VERSION 5.8 ;
BUSBITCHARS "[]" ;
DIVIDERCHAR "/" ;
UNITS
    DATABASE MICRONS 1000 ;
END UNITS

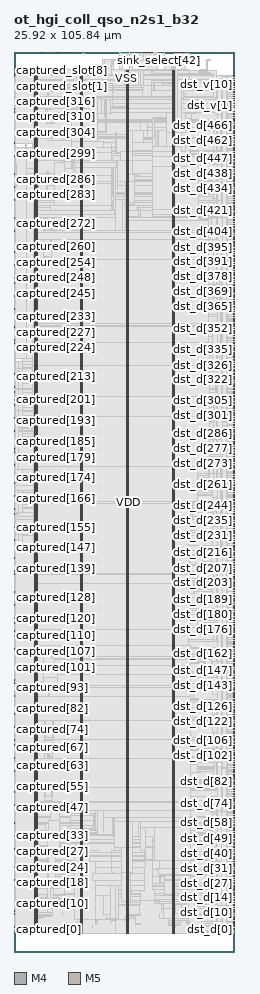
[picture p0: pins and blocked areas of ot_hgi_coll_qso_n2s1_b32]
MACRO ot_hgi_coll_qso_n2s1_b32
  FOREIGN ot_hgi_coll_qso_n2s1_b32 0 0 ;
  CLASS BLOCK ;
  SIZE 25.92 BY 105.84 ;
  PIN captured[0]
    DIRECTION INPUT ;
    USE SIGNAL ;
    PORT
      LAYER M4 ;
        RECT  0 2.64 0.084 2.664 ;
    END
  END captured[0]
  PIN captured[100]
    DIRECTION INPUT ;
    USE SIGNAL ;
    PORT
      LAYER M4 ;
        RECT  0 33.168 0.084 33.192 ;
    END
  END captured[100]
  PIN captured[101]
    DIRECTION INPUT ;
    USE SIGNAL ;
    PORT
      LAYER M4 ;
        RECT  0 33.456 0.084 33.48 ;
    END
  END captured[101]
  PIN captured[102]
    DIRECTION INPUT ;
    USE SIGNAL ;
    PORT
      LAYER M4 ;
        RECT  0 33.792 0.084 33.816 ;
    END
  END captured[102]
  PIN captured[103]
    DIRECTION INPUT ;
    USE SIGNAL ;
    PORT
      LAYER M4 ;
        RECT  0 34.08 0.084 34.104 ;
    END
  END captured[103]
  PIN captured[104]
    DIRECTION INPUT ;
    USE SIGNAL ;
    PORT
      LAYER M4 ;
        RECT  0 34.368 0.084 34.392 ;
    END
  END captured[104]
  PIN captured[105]
    DIRECTION INPUT ;
    USE SIGNAL ;
    PORT
      LAYER M4 ;
        RECT  0 34.704 0.084 34.728 ;
    END
  END captured[105]
  PIN captured[106]
    DIRECTION INPUT ;
    USE SIGNAL ;
    PORT
      LAYER M4 ;
        RECT  0 34.992 0.084 35.016 ;
    END
  END captured[106]
  PIN captured[107]
    DIRECTION INPUT ;
    USE SIGNAL ;
    PORT
      LAYER M4 ;
        RECT  0 35.328 0.084 35.352 ;
    END
  END captured[107]
  PIN captured[108]
    DIRECTION INPUT ;
    USE SIGNAL ;
    PORT
      LAYER M4 ;
        RECT  0 35.616 0.084 35.64 ;
    END
  END captured[108]
  PIN captured[109]
    DIRECTION INPUT ;
    USE SIGNAL ;
    PORT
      LAYER M4 ;
        RECT  0 35.904 0.084 35.928 ;
    END
  END captured[109]
  PIN captured[10]
    DIRECTION INPUT ;
    USE SIGNAL ;
    PORT
      LAYER M4 ;
        RECT  0 5.712 0.084 5.736 ;
    END
  END captured[10]
  PIN captured[110]
    DIRECTION INPUT ;
    USE SIGNAL ;
    PORT
      LAYER M4 ;
        RECT  0 36.24 0.084 36.264 ;
    END
  END captured[110]
  PIN captured[111]
    DIRECTION INPUT ;
    USE SIGNAL ;
    PORT
      LAYER M4 ;
        RECT  0 36.528 0.084 36.552 ;
    END
  END captured[111]
  PIN captured[112]
    DIRECTION INPUT ;
    USE SIGNAL ;
    PORT
      LAYER M4 ;
        RECT  0 36.816 0.084 36.84 ;
    END
  END captured[112]
  PIN captured[113]
    DIRECTION INPUT ;
    USE SIGNAL ;
    PORT
      LAYER M4 ;
        RECT  0 37.152 0.084 37.176 ;
    END
  END captured[113]
  PIN captured[114]
    DIRECTION INPUT ;
    USE SIGNAL ;
    PORT
      LAYER M4 ;
        RECT  0 37.44 0.084 37.464 ;
    END
  END captured[114]
  PIN captured[115]
    DIRECTION INPUT ;
    USE SIGNAL ;
    PORT
      LAYER M4 ;
        RECT  0 37.728 0.084 37.752 ;
    END
  END captured[115]
  PIN captured[116]
    DIRECTION INPUT ;
    USE SIGNAL ;
    PORT
      LAYER M4 ;
        RECT  0 38.064 0.084 38.088 ;
    END
  END captured[116]
  PIN captured[117]
    DIRECTION INPUT ;
    USE SIGNAL ;
    PORT
      LAYER M4 ;
        RECT  0 38.352 0.084 38.376 ;
    END
  END captured[117]
  PIN captured[118]
    DIRECTION INPUT ;
    USE SIGNAL ;
    PORT
      LAYER M4 ;
        RECT  0 38.688 0.084 38.712 ;
    END
  END captured[118]
  PIN captured[119]
    DIRECTION INPUT ;
    USE SIGNAL ;
    PORT
      LAYER M4 ;
        RECT  0 38.976 0.084 39 ;
    END
  END captured[119]
  PIN captured[11]
    DIRECTION INPUT ;
    USE SIGNAL ;
    PORT
      LAYER M4 ;
        RECT  0 6 0.084 6.024 ;
    END
  END captured[11]
  PIN captured[120]
    DIRECTION INPUT ;
    USE SIGNAL ;
    PORT
      LAYER M4 ;
        RECT  0 39.264 0.084 39.288 ;
    END
  END captured[120]
  PIN captured[121]
    DIRECTION INPUT ;
    USE SIGNAL ;
    PORT
      LAYER M4 ;
        RECT  0 39.6 0.084 39.624 ;
    END
  END captured[121]
  PIN captured[122]
    DIRECTION INPUT ;
    USE SIGNAL ;
    PORT
      LAYER M4 ;
        RECT  0 39.888 0.084 39.912 ;
    END
  END captured[122]
  PIN captured[123]
    DIRECTION INPUT ;
    USE SIGNAL ;
    PORT
      LAYER M4 ;
        RECT  0 40.176 0.084 40.2 ;
    END
  END captured[123]
  PIN captured[124]
    DIRECTION INPUT ;
    USE SIGNAL ;
    PORT
      LAYER M4 ;
        RECT  0 40.512 0.084 40.536 ;
    END
  END captured[124]
  PIN captured[125]
    DIRECTION INPUT ;
    USE SIGNAL ;
    PORT
      LAYER M4 ;
        RECT  0 40.8 0.084 40.824 ;
    END
  END captured[125]
  PIN captured[126]
    DIRECTION INPUT ;
    USE SIGNAL ;
    PORT
      LAYER M4 ;
        RECT  0 41.088 0.084 41.112 ;
    END
  END captured[126]
  PIN captured[127]
    DIRECTION INPUT ;
    USE SIGNAL ;
    PORT
      LAYER M4 ;
        RECT  0 41.424 0.084 41.448 ;
    END
  END captured[127]
  PIN captured[128]
    DIRECTION INPUT ;
    USE SIGNAL ;
    PORT
      LAYER M4 ;
        RECT  0 41.712 0.084 41.736 ;
    END
  END captured[128]
  PIN captured[129]
    DIRECTION INPUT ;
    USE SIGNAL ;
    PORT
      LAYER M4 ;
        RECT  0 42 0.084 42.024 ;
    END
  END captured[129]
  PIN captured[12]
    DIRECTION INPUT ;
    USE SIGNAL ;
    PORT
      LAYER M4 ;
        RECT  0 6.288 0.084 6.312 ;
    END
  END captured[12]
  PIN captured[130]
    DIRECTION INPUT ;
    USE SIGNAL ;
    PORT
      LAYER M4 ;
        RECT  0 42.336 0.084 42.36 ;
    END
  END captured[130]
  PIN captured[131]
    DIRECTION INPUT ;
    USE SIGNAL ;
    PORT
      LAYER M4 ;
        RECT  0 42.624 0.084 42.648 ;
    END
  END captured[131]
  PIN captured[132]
    DIRECTION INPUT ;
    USE SIGNAL ;
    PORT
      LAYER M4 ;
        RECT  0 42.96 0.084 42.984 ;
    END
  END captured[132]
  PIN captured[133]
    DIRECTION INPUT ;
    USE SIGNAL ;
    PORT
      LAYER M4 ;
        RECT  0 43.248 0.084 43.272 ;
    END
  END captured[133]
  PIN captured[134]
    DIRECTION INPUT ;
    USE SIGNAL ;
    PORT
      LAYER M4 ;
        RECT  0 43.536 0.084 43.56 ;
    END
  END captured[134]
  PIN captured[135]
    DIRECTION INPUT ;
    USE SIGNAL ;
    PORT
      LAYER M4 ;
        RECT  0 43.872 0.084 43.896 ;
    END
  END captured[135]
  PIN captured[136]
    DIRECTION INPUT ;
    USE SIGNAL ;
    PORT
      LAYER M4 ;
        RECT  0 44.16 0.084 44.184 ;
    END
  END captured[136]
  PIN captured[137]
    DIRECTION INPUT ;
    USE SIGNAL ;
    PORT
      LAYER M4 ;
        RECT  0 44.448 0.084 44.472 ;
    END
  END captured[137]
  PIN captured[138]
    DIRECTION INPUT ;
    USE SIGNAL ;
    PORT
      LAYER M4 ;
        RECT  0 44.784 0.084 44.808 ;
    END
  END captured[138]
  PIN captured[139]
    DIRECTION INPUT ;
    USE SIGNAL ;
    PORT
      LAYER M4 ;
        RECT  0 45.072 0.084 45.096 ;
    END
  END captured[139]
  PIN captured[13]
    DIRECTION INPUT ;
    USE SIGNAL ;
    PORT
      LAYER M4 ;
        RECT  0 6.624 0.084 6.648 ;
    END
  END captured[13]
  PIN captured[140]
    DIRECTION INPUT ;
    USE SIGNAL ;
    PORT
      LAYER M4 ;
        RECT  0 45.36 0.084 45.384 ;
    END
  END captured[140]
  PIN captured[141]
    DIRECTION INPUT ;
    USE SIGNAL ;
    PORT
      LAYER M4 ;
        RECT  0 45.696 0.084 45.72 ;
    END
  END captured[141]
  PIN captured[142]
    DIRECTION INPUT ;
    USE SIGNAL ;
    PORT
      LAYER M4 ;
        RECT  0 45.984 0.084 46.008 ;
    END
  END captured[142]
  PIN captured[143]
    DIRECTION INPUT ;
    USE SIGNAL ;
    PORT
      LAYER M4 ;
        RECT  0 46.32 0.084 46.344 ;
    END
  END captured[143]
  PIN captured[144]
    DIRECTION INPUT ;
    USE SIGNAL ;
    PORT
      LAYER M4 ;
        RECT  0 46.608 0.084 46.632 ;
    END
  END captured[144]
  PIN captured[145]
    DIRECTION INPUT ;
    USE SIGNAL ;
    PORT
      LAYER M4 ;
        RECT  0 46.896 0.084 46.92 ;
    END
  END captured[145]
  PIN captured[146]
    DIRECTION INPUT ;
    USE SIGNAL ;
    PORT
      LAYER M4 ;
        RECT  0 47.232 0.084 47.256 ;
    END
  END captured[146]
  PIN captured[147]
    DIRECTION INPUT ;
    USE SIGNAL ;
    PORT
      LAYER M4 ;
        RECT  0 47.52 0.084 47.544 ;
    END
  END captured[147]
  PIN captured[148]
    DIRECTION INPUT ;
    USE SIGNAL ;
    PORT
      LAYER M4 ;
        RECT  0 47.808 0.084 47.832 ;
    END
  END captured[148]
  PIN captured[149]
    DIRECTION INPUT ;
    USE SIGNAL ;
    PORT
      LAYER M4 ;
        RECT  0 48.144 0.084 48.168 ;
    END
  END captured[149]
  PIN captured[14]
    DIRECTION INPUT ;
    USE SIGNAL ;
    PORT
      LAYER M4 ;
        RECT  0 6.912 0.084 6.936 ;
    END
  END captured[14]
  PIN captured[150]
    DIRECTION INPUT ;
    USE SIGNAL ;
    PORT
      LAYER M4 ;
        RECT  0 48.432 0.084 48.456 ;
    END
  END captured[150]
  PIN captured[151]
    DIRECTION INPUT ;
    USE SIGNAL ;
    PORT
      LAYER M4 ;
        RECT  0 48.72 0.084 48.744 ;
    END
  END captured[151]
  PIN captured[152]
    DIRECTION INPUT ;
    USE SIGNAL ;
    PORT
      LAYER M4 ;
        RECT  0 49.056 0.084 49.08 ;
    END
  END captured[152]
  PIN captured[153]
    DIRECTION INPUT ;
    USE SIGNAL ;
    PORT
      LAYER M4 ;
        RECT  0 49.344 0.084 49.368 ;
    END
  END captured[153]
  PIN captured[154]
    DIRECTION INPUT ;
    USE SIGNAL ;
    PORT
      LAYER M4 ;
        RECT  0 49.632 0.084 49.656 ;
    END
  END captured[154]
  PIN captured[155]
    DIRECTION INPUT ;
    USE SIGNAL ;
    PORT
      LAYER M4 ;
        RECT  0 49.968 0.084 49.992 ;
    END
  END captured[155]
  PIN captured[156]
    DIRECTION INPUT ;
    USE SIGNAL ;
    PORT
      LAYER M4 ;
        RECT  0 50.256 0.084 50.28 ;
    END
  END captured[156]
  PIN captured[157]
    DIRECTION INPUT ;
    USE SIGNAL ;
    PORT
      LAYER M4 ;
        RECT  0 50.592 0.084 50.616 ;
    END
  END captured[157]
  PIN captured[158]
    DIRECTION INPUT ;
    USE SIGNAL ;
    PORT
      LAYER M4 ;
        RECT  0 50.88 0.084 50.904 ;
    END
  END captured[158]
  PIN captured[159]
    DIRECTION INPUT ;
    USE SIGNAL ;
    PORT
      LAYER M4 ;
        RECT  0 51.168 0.084 51.192 ;
    END
  END captured[159]
  PIN captured[15]
    DIRECTION INPUT ;
    USE SIGNAL ;
    PORT
      LAYER M4 ;
        RECT  0 7.2 0.084 7.224 ;
    END
  END captured[15]
  PIN captured[160]
    DIRECTION INPUT ;
    USE SIGNAL ;
    PORT
      LAYER M4 ;
        RECT  0 51.504 0.084 51.528 ;
    END
  END captured[160]
  PIN captured[161]
    DIRECTION INPUT ;
    USE SIGNAL ;
    PORT
      LAYER M4 ;
        RECT  0 51.792 0.084 51.816 ;
    END
  END captured[161]
  PIN captured[162]
    DIRECTION INPUT ;
    USE SIGNAL ;
    PORT
      LAYER M4 ;
        RECT  0 52.08 0.084 52.104 ;
    END
  END captured[162]
  PIN captured[163]
    DIRECTION INPUT ;
    USE SIGNAL ;
    PORT
      LAYER M4 ;
        RECT  0 52.416 0.084 52.44 ;
    END
  END captured[163]
  PIN captured[164]
    DIRECTION INPUT ;
    USE SIGNAL ;
    PORT
      LAYER M4 ;
        RECT  0 52.704 0.084 52.728 ;
    END
  END captured[164]
  PIN captured[165]
    DIRECTION INPUT ;
    USE SIGNAL ;
    PORT
      LAYER M4 ;
        RECT  0 52.992 0.084 53.016 ;
    END
  END captured[165]
  PIN captured[166]
    DIRECTION INPUT ;
    USE SIGNAL ;
    PORT
      LAYER M4 ;
        RECT  0 53.328 0.084 53.352 ;
    END
  END captured[166]
  PIN captured[167]
    DIRECTION INPUT ;
    USE SIGNAL ;
    PORT
      LAYER M4 ;
        RECT  0 53.616 0.084 53.64 ;
    END
  END captured[167]
  PIN captured[168]
    DIRECTION INPUT ;
    USE SIGNAL ;
    PORT
      LAYER M4 ;
        RECT  0 53.952 0.084 53.976 ;
    END
  END captured[168]
  PIN captured[169]
    DIRECTION INPUT ;
    USE SIGNAL ;
    PORT
      LAYER M4 ;
        RECT  0 54.24 0.084 54.264 ;
    END
  END captured[169]
  PIN captured[16]
    DIRECTION INPUT ;
    USE SIGNAL ;
    PORT
      LAYER M4 ;
        RECT  0 7.536 0.084 7.56 ;
    END
  END captured[16]
  PIN captured[170]
    DIRECTION INPUT ;
    USE SIGNAL ;
    PORT
      LAYER M4 ;
        RECT  0 54.528 0.084 54.552 ;
    END
  END captured[170]
  PIN captured[171]
    DIRECTION INPUT ;
    USE SIGNAL ;
    PORT
      LAYER M4 ;
        RECT  0 54.864 0.084 54.888 ;
    END
  END captured[171]
  PIN captured[172]
    DIRECTION INPUT ;
    USE SIGNAL ;
    PORT
      LAYER M4 ;
        RECT  0 55.152 0.084 55.176 ;
    END
  END captured[172]
  PIN captured[173]
    DIRECTION INPUT ;
    USE SIGNAL ;
    PORT
      LAYER M4 ;
        RECT  0 55.44 0.084 55.464 ;
    END
  END captured[173]
  PIN captured[174]
    DIRECTION INPUT ;
    USE SIGNAL ;
    PORT
      LAYER M4 ;
        RECT  0 55.776 0.084 55.8 ;
    END
  END captured[174]
  PIN captured[175]
    DIRECTION INPUT ;
    USE SIGNAL ;
    PORT
      LAYER M4 ;
        RECT  0 56.064 0.084 56.088 ;
    END
  END captured[175]
  PIN captured[176]
    DIRECTION INPUT ;
    USE SIGNAL ;
    PORT
      LAYER M4 ;
        RECT  0 56.352 0.084 56.376 ;
    END
  END captured[176]
  PIN captured[177]
    DIRECTION INPUT ;
    USE SIGNAL ;
    PORT
      LAYER M4 ;
        RECT  0 56.688 0.084 56.712 ;
    END
  END captured[177]
  PIN captured[178]
    DIRECTION INPUT ;
    USE SIGNAL ;
    PORT
      LAYER M4 ;
        RECT  0 56.976 0.084 57 ;
    END
  END captured[178]
  PIN captured[179]
    DIRECTION INPUT ;
    USE SIGNAL ;
    PORT
      LAYER M4 ;
        RECT  0 57.264 0.084 57.288 ;
    END
  END captured[179]
  PIN captured[17]
    DIRECTION INPUT ;
    USE SIGNAL ;
    PORT
      LAYER M4 ;
        RECT  0 7.824 0.084 7.848 ;
    END
  END captured[17]
  PIN captured[180]
    DIRECTION INPUT ;
    USE SIGNAL ;
    PORT
      LAYER M4 ;
        RECT  0 57.6 0.084 57.624 ;
    END
  END captured[180]
  PIN captured[181]
    DIRECTION INPUT ;
    USE SIGNAL ;
    PORT
      LAYER M4 ;
        RECT  0 57.888 0.084 57.912 ;
    END
  END captured[181]
  PIN captured[182]
    DIRECTION INPUT ;
    USE SIGNAL ;
    PORT
      LAYER M4 ;
        RECT  0 58.224 0.084 58.248 ;
    END
  END captured[182]
  PIN captured[183]
    DIRECTION INPUT ;
    USE SIGNAL ;
    PORT
      LAYER M4 ;
        RECT  0 58.512 0.084 58.536 ;
    END
  END captured[183]
  PIN captured[184]
    DIRECTION INPUT ;
    USE SIGNAL ;
    PORT
      LAYER M4 ;
        RECT  0 58.8 0.084 58.824 ;
    END
  END captured[184]
  PIN captured[185]
    DIRECTION INPUT ;
    USE SIGNAL ;
    PORT
      LAYER M4 ;
        RECT  0 59.136 0.084 59.16 ;
    END
  END captured[185]
  PIN captured[186]
    DIRECTION INPUT ;
    USE SIGNAL ;
    PORT
      LAYER M4 ;
        RECT  0 59.424 0.084 59.448 ;
    END
  END captured[186]
  PIN captured[187]
    DIRECTION INPUT ;
    USE SIGNAL ;
    PORT
      LAYER M4 ;
        RECT  0 59.712 0.084 59.736 ;
    END
  END captured[187]
  PIN captured[188]
    DIRECTION INPUT ;
    USE SIGNAL ;
    PORT
      LAYER M4 ;
        RECT  0 60.048 0.084 60.072 ;
    END
  END captured[188]
  PIN captured[189]
    DIRECTION INPUT ;
    USE SIGNAL ;
    PORT
      LAYER M4 ;
        RECT  0 60.336 0.084 60.36 ;
    END
  END captured[189]
  PIN captured[18]
    DIRECTION INPUT ;
    USE SIGNAL ;
    PORT
      LAYER M4 ;
        RECT  0 8.16 0.084 8.184 ;
    END
  END captured[18]
  PIN captured[190]
    DIRECTION INPUT ;
    USE SIGNAL ;
    PORT
      LAYER M4 ;
        RECT  0 60.624 0.084 60.648 ;
    END
  END captured[190]
  PIN captured[191]
    DIRECTION INPUT ;
    USE SIGNAL ;
    PORT
      LAYER M4 ;
        RECT  0 60.96 0.084 60.984 ;
    END
  END captured[191]
  PIN captured[192]
    DIRECTION INPUT ;
    USE SIGNAL ;
    PORT
      LAYER M4 ;
        RECT  0 61.248 0.084 61.272 ;
    END
  END captured[192]
  PIN captured[193]
    DIRECTION INPUT ;
    USE SIGNAL ;
    PORT
      LAYER M4 ;
        RECT  0 61.584 0.084 61.608 ;
    END
  END captured[193]
  PIN captured[194]
    DIRECTION INPUT ;
    USE SIGNAL ;
    PORT
      LAYER M4 ;
        RECT  0 61.872 0.084 61.896 ;
    END
  END captured[194]
  PIN captured[195]
    DIRECTION INPUT ;
    USE SIGNAL ;
    PORT
      LAYER M4 ;
        RECT  0 62.16 0.084 62.184 ;
    END
  END captured[195]
  PIN captured[196]
    DIRECTION INPUT ;
    USE SIGNAL ;
    PORT
      LAYER M4 ;
        RECT  0 62.496 0.084 62.52 ;
    END
  END captured[196]
  PIN captured[197]
    DIRECTION INPUT ;
    USE SIGNAL ;
    PORT
      LAYER M4 ;
        RECT  0 62.784 0.084 62.808 ;
    END
  END captured[197]
  PIN captured[198]
    DIRECTION INPUT ;
    USE SIGNAL ;
    PORT
      LAYER M4 ;
        RECT  0 63.072 0.084 63.096 ;
    END
  END captured[198]
  PIN captured[199]
    DIRECTION INPUT ;
    USE SIGNAL ;
    PORT
      LAYER M4 ;
        RECT  0 63.408 0.084 63.432 ;
    END
  END captured[199]
  PIN captured[19]
    DIRECTION INPUT ;
    USE SIGNAL ;
    PORT
      LAYER M4 ;
        RECT  0 8.448 0.084 8.472 ;
    END
  END captured[19]
  PIN captured[1]
    DIRECTION INPUT ;
    USE SIGNAL ;
    PORT
      LAYER M4 ;
        RECT  0 2.928 0.084 2.952 ;
    END
  END captured[1]
  PIN captured[200]
    DIRECTION INPUT ;
    USE SIGNAL ;
    PORT
      LAYER M4 ;
        RECT  0 63.696 0.084 63.72 ;
    END
  END captured[200]
  PIN captured[201]
    DIRECTION INPUT ;
    USE SIGNAL ;
    PORT
      LAYER M4 ;
        RECT  0 63.984 0.084 64.008 ;
    END
  END captured[201]
  PIN captured[202]
    DIRECTION INPUT ;
    USE SIGNAL ;
    PORT
      LAYER M4 ;
        RECT  0 64.32 0.084 64.344 ;
    END
  END captured[202]
  PIN captured[203]
    DIRECTION INPUT ;
    USE SIGNAL ;
    PORT
      LAYER M4 ;
        RECT  0 64.608 0.084 64.632 ;
    END
  END captured[203]
  PIN captured[204]
    DIRECTION INPUT ;
    USE SIGNAL ;
    PORT
      LAYER M4 ;
        RECT  0 64.896 0.084 64.92 ;
    END
  END captured[204]
  PIN captured[205]
    DIRECTION INPUT ;
    USE SIGNAL ;
    PORT
      LAYER M4 ;
        RECT  0 65.232 0.084 65.256 ;
    END
  END captured[205]
  PIN captured[206]
    DIRECTION INPUT ;
    USE SIGNAL ;
    PORT
      LAYER M4 ;
        RECT  0 65.52 0.084 65.544 ;
    END
  END captured[206]
  PIN captured[207]
    DIRECTION INPUT ;
    USE SIGNAL ;
    PORT
      LAYER M4 ;
        RECT  0 65.856 0.084 65.88 ;
    END
  END captured[207]
  PIN captured[208]
    DIRECTION INPUT ;
    USE SIGNAL ;
    PORT
      LAYER M4 ;
        RECT  0 66.144 0.084 66.168 ;
    END
  END captured[208]
  PIN captured[209]
    DIRECTION INPUT ;
    USE SIGNAL ;
    PORT
      LAYER M4 ;
        RECT  0 66.432 0.084 66.456 ;
    END
  END captured[209]
  PIN captured[20]
    DIRECTION INPUT ;
    USE SIGNAL ;
    PORT
      LAYER M4 ;
        RECT  0 8.736 0.084 8.76 ;
    END
  END captured[20]
  PIN captured[210]
    DIRECTION INPUT ;
    USE SIGNAL ;
    PORT
      LAYER M4 ;
        RECT  0 66.768 0.084 66.792 ;
    END
  END captured[210]
  PIN captured[211]
    DIRECTION INPUT ;
    USE SIGNAL ;
    PORT
      LAYER M4 ;
        RECT  0 67.056 0.084 67.08 ;
    END
  END captured[211]
  PIN captured[212]
    DIRECTION INPUT ;
    USE SIGNAL ;
    PORT
      LAYER M4 ;
        RECT  0 67.344 0.084 67.368 ;
    END
  END captured[212]
  PIN captured[213]
    DIRECTION INPUT ;
    USE SIGNAL ;
    PORT
      LAYER M4 ;
        RECT  0 67.68 0.084 67.704 ;
    END
  END captured[213]
  PIN captured[214]
    DIRECTION INPUT ;
    USE SIGNAL ;
    PORT
      LAYER M4 ;
        RECT  0 67.968 0.084 67.992 ;
    END
  END captured[214]
  PIN captured[215]
    DIRECTION INPUT ;
    USE SIGNAL ;
    PORT
      LAYER M4 ;
        RECT  0 68.256 0.084 68.28 ;
    END
  END captured[215]
  PIN captured[216]
    DIRECTION INPUT ;
    USE SIGNAL ;
    PORT
      LAYER M4 ;
        RECT  0 68.592 0.084 68.616 ;
    END
  END captured[216]
  PIN captured[217]
    DIRECTION INPUT ;
    USE SIGNAL ;
    PORT
      LAYER M4 ;
        RECT  0 68.88 0.084 68.904 ;
    END
  END captured[217]
  PIN captured[218]
    DIRECTION INPUT ;
    USE SIGNAL ;
    PORT
      LAYER M4 ;
        RECT  0 69.216 0.084 69.24 ;
    END
  END captured[218]
  PIN captured[219]
    DIRECTION INPUT ;
    USE SIGNAL ;
    PORT
      LAYER M4 ;
        RECT  0 69.504 0.084 69.528 ;
    END
  END captured[219]
  PIN captured[21]
    DIRECTION INPUT ;
    USE SIGNAL ;
    PORT
      LAYER M4 ;
        RECT  0 9.072 0.084 9.096 ;
    END
  END captured[21]
  PIN captured[220]
    DIRECTION INPUT ;
    USE SIGNAL ;
    PORT
      LAYER M4 ;
        RECT  0 69.792 0.084 69.816 ;
    END
  END captured[220]
  PIN captured[221]
    DIRECTION INPUT ;
    USE SIGNAL ;
    PORT
      LAYER M4 ;
        RECT  0 70.128 0.084 70.152 ;
    END
  END captured[221]
  PIN captured[222]
    DIRECTION INPUT ;
    USE SIGNAL ;
    PORT
      LAYER M4 ;
        RECT  0 70.416 0.084 70.44 ;
    END
  END captured[222]
  PIN captured[223]
    DIRECTION INPUT ;
    USE SIGNAL ;
    PORT
      LAYER M4 ;
        RECT  0 70.704 0.084 70.728 ;
    END
  END captured[223]
  PIN captured[224]
    DIRECTION INPUT ;
    USE SIGNAL ;
    PORT
      LAYER M4 ;
        RECT  0 71.04 0.084 71.064 ;
    END
  END captured[224]
  PIN captured[225]
    DIRECTION INPUT ;
    USE SIGNAL ;
    PORT
      LAYER M4 ;
        RECT  0 71.328 0.084 71.352 ;
    END
  END captured[225]
  PIN captured[226]
    DIRECTION INPUT ;
    USE SIGNAL ;
    PORT
      LAYER M4 ;
        RECT  0 71.616 0.084 71.64 ;
    END
  END captured[226]
  PIN captured[227]
    DIRECTION INPUT ;
    USE SIGNAL ;
    PORT
      LAYER M4 ;
        RECT  0 71.952 0.084 71.976 ;
    END
  END captured[227]
  PIN captured[228]
    DIRECTION INPUT ;
    USE SIGNAL ;
    PORT
      LAYER M4 ;
        RECT  0 72.24 0.084 72.264 ;
    END
  END captured[228]
  PIN captured[229]
    DIRECTION INPUT ;
    USE SIGNAL ;
    PORT
      LAYER M4 ;
        RECT  0 72.528 0.084 72.552 ;
    END
  END captured[229]
  PIN captured[22]
    DIRECTION INPUT ;
    USE SIGNAL ;
    PORT
      LAYER M4 ;
        RECT  0 9.36 0.084 9.384 ;
    END
  END captured[22]
  PIN captured[230]
    DIRECTION INPUT ;
    USE SIGNAL ;
    PORT
      LAYER M4 ;
        RECT  0 72.864 0.084 72.888 ;
    END
  END captured[230]
  PIN captured[231]
    DIRECTION INPUT ;
    USE SIGNAL ;
    PORT
      LAYER M4 ;
        RECT  0 73.152 0.084 73.176 ;
    END
  END captured[231]
  PIN captured[232]
    DIRECTION INPUT ;
    USE SIGNAL ;
    PORT
      LAYER M4 ;
        RECT  0 73.488 0.084 73.512 ;
    END
  END captured[232]
  PIN captured[233]
    DIRECTION INPUT ;
    USE SIGNAL ;
    PORT
      LAYER M4 ;
        RECT  0 73.776 0.084 73.8 ;
    END
  END captured[233]
  PIN captured[234]
    DIRECTION INPUT ;
    USE SIGNAL ;
    PORT
      LAYER M4 ;
        RECT  0 74.064 0.084 74.088 ;
    END
  END captured[234]
  PIN captured[235]
    DIRECTION INPUT ;
    USE SIGNAL ;
    PORT
      LAYER M4 ;
        RECT  0 74.4 0.084 74.424 ;
    END
  END captured[235]
  PIN captured[236]
    DIRECTION INPUT ;
    USE SIGNAL ;
    PORT
      LAYER M4 ;
        RECT  0 74.688 0.084 74.712 ;
    END
  END captured[236]
  PIN captured[237]
    DIRECTION INPUT ;
    USE SIGNAL ;
    PORT
      LAYER M4 ;
        RECT  0 74.976 0.084 75 ;
    END
  END captured[237]
  PIN captured[238]
    DIRECTION INPUT ;
    USE SIGNAL ;
    PORT
      LAYER M4 ;
        RECT  0 75.312 0.084 75.336 ;
    END
  END captured[238]
  PIN captured[239]
    DIRECTION INPUT ;
    USE SIGNAL ;
    PORT
      LAYER M4 ;
        RECT  0 75.6 0.084 75.624 ;
    END
  END captured[239]
  PIN captured[23]
    DIRECTION INPUT ;
    USE SIGNAL ;
    PORT
      LAYER M4 ;
        RECT  0 9.648 0.084 9.672 ;
    END
  END captured[23]
  PIN captured[240]
    DIRECTION INPUT ;
    USE SIGNAL ;
    PORT
      LAYER M4 ;
        RECT  0 75.888 0.084 75.912 ;
    END
  END captured[240]
  PIN captured[241]
    DIRECTION INPUT ;
    USE SIGNAL ;
    PORT
      LAYER M4 ;
        RECT  0 76.224 0.084 76.248 ;
    END
  END captured[241]
  PIN captured[242]
    DIRECTION INPUT ;
    USE SIGNAL ;
    PORT
      LAYER M4 ;
        RECT  0 76.512 0.084 76.536 ;
    END
  END captured[242]
  PIN captured[243]
    DIRECTION INPUT ;
    USE SIGNAL ;
    PORT
      LAYER M4 ;
        RECT  0 76.848 0.084 76.872 ;
    END
  END captured[243]
  PIN captured[244]
    DIRECTION INPUT ;
    USE SIGNAL ;
    PORT
      LAYER M4 ;
        RECT  0 77.136 0.084 77.16 ;
    END
  END captured[244]
  PIN captured[245]
    DIRECTION INPUT ;
    USE SIGNAL ;
    PORT
      LAYER M4 ;
        RECT  0 77.424 0.084 77.448 ;
    END
  END captured[245]
  PIN captured[246]
    DIRECTION INPUT ;
    USE SIGNAL ;
    PORT
      LAYER M4 ;
        RECT  0 77.76 0.084 77.784 ;
    END
  END captured[246]
  PIN captured[247]
    DIRECTION INPUT ;
    USE SIGNAL ;
    PORT
      LAYER M4 ;
        RECT  0 78.048 0.084 78.072 ;
    END
  END captured[247]
  PIN captured[248]
    DIRECTION INPUT ;
    USE SIGNAL ;
    PORT
      LAYER M4 ;
        RECT  0 78.336 0.084 78.36 ;
    END
  END captured[248]
  PIN captured[249]
    DIRECTION INPUT ;
    USE SIGNAL ;
    PORT
      LAYER M4 ;
        RECT  0 78.672 0.084 78.696 ;
    END
  END captured[249]
  PIN captured[24]
    DIRECTION INPUT ;
    USE SIGNAL ;
    PORT
      LAYER M4 ;
        RECT  0 9.984 0.084 10.008 ;
    END
  END captured[24]
  PIN captured[250]
    DIRECTION INPUT ;
    USE SIGNAL ;
    PORT
      LAYER M4 ;
        RECT  0 78.96 0.084 78.984 ;
    END
  END captured[250]
  PIN captured[251]
    DIRECTION INPUT ;
    USE SIGNAL ;
    PORT
      LAYER M4 ;
        RECT  0 79.248 0.084 79.272 ;
    END
  END captured[251]
  PIN captured[252]
    DIRECTION INPUT ;
    USE SIGNAL ;
    PORT
      LAYER M4 ;
        RECT  0 79.584 0.084 79.608 ;
    END
  END captured[252]
  PIN captured[253]
    DIRECTION INPUT ;
    USE SIGNAL ;
    PORT
      LAYER M4 ;
        RECT  0 79.872 0.084 79.896 ;
    END
  END captured[253]
  PIN captured[254]
    DIRECTION INPUT ;
    USE SIGNAL ;
    PORT
      LAYER M4 ;
        RECT  0 80.16 0.084 80.184 ;
    END
  END captured[254]
  PIN captured[255]
    DIRECTION INPUT ;
    USE SIGNAL ;
    PORT
      LAYER M4 ;
        RECT  0 80.496 0.084 80.52 ;
    END
  END captured[255]
  PIN captured[256]
    DIRECTION INPUT ;
    USE SIGNAL ;
    PORT
      LAYER M4 ;
        RECT  0 80.784 0.084 80.808 ;
    END
  END captured[256]
  PIN captured[257]
    DIRECTION INPUT ;
    USE SIGNAL ;
    PORT
      LAYER M4 ;
        RECT  0 81.12 0.084 81.144 ;
    END
  END captured[257]
  PIN captured[258]
    DIRECTION INPUT ;
    USE SIGNAL ;
    PORT
      LAYER M4 ;
        RECT  0 81.408 0.084 81.432 ;
    END
  END captured[258]
  PIN captured[259]
    DIRECTION INPUT ;
    USE SIGNAL ;
    PORT
      LAYER M4 ;
        RECT  0 81.696 0.084 81.72 ;
    END
  END captured[259]
  PIN captured[25]
    DIRECTION INPUT ;
    USE SIGNAL ;
    PORT
      LAYER M4 ;
        RECT  0 10.272 0.084 10.296 ;
    END
  END captured[25]
  PIN captured[260]
    DIRECTION INPUT ;
    USE SIGNAL ;
    PORT
      LAYER M4 ;
        RECT  0 82.032 0.084 82.056 ;
    END
  END captured[260]
  PIN captured[261]
    DIRECTION INPUT ;
    USE SIGNAL ;
    PORT
      LAYER M4 ;
        RECT  0 82.32 0.084 82.344 ;
    END
  END captured[261]
  PIN captured[262]
    DIRECTION INPUT ;
    USE SIGNAL ;
    PORT
      LAYER M4 ;
        RECT  0 82.608 0.084 82.632 ;
    END
  END captured[262]
  PIN captured[263]
    DIRECTION INPUT ;
    USE SIGNAL ;
    PORT
      LAYER M4 ;
        RECT  0 82.944 0.084 82.968 ;
    END
  END captured[263]
  PIN captured[264]
    DIRECTION INPUT ;
    USE SIGNAL ;
    PORT
      LAYER M4 ;
        RECT  0 83.232 0.084 83.256 ;
    END
  END captured[264]
  PIN captured[265]
    DIRECTION INPUT ;
    USE SIGNAL ;
    PORT
      LAYER M4 ;
        RECT  0 83.52 0.084 83.544 ;
    END
  END captured[265]
  PIN captured[266]
    DIRECTION INPUT ;
    USE SIGNAL ;
    PORT
      LAYER M4 ;
        RECT  0 83.856 0.084 83.88 ;
    END
  END captured[266]
  PIN captured[267]
    DIRECTION INPUT ;
    USE SIGNAL ;
    PORT
      LAYER M4 ;
        RECT  0 84.144 0.084 84.168 ;
    END
  END captured[267]
  PIN captured[268]
    DIRECTION INPUT ;
    USE SIGNAL ;
    PORT
      LAYER M4 ;
        RECT  0 84.48 0.084 84.504 ;
    END
  END captured[268]
  PIN captured[269]
    DIRECTION INPUT ;
    USE SIGNAL ;
    PORT
      LAYER M4 ;
        RECT  0 84.768 0.084 84.792 ;
    END
  END captured[269]
  PIN captured[26]
    DIRECTION INPUT ;
    USE SIGNAL ;
    PORT
      LAYER M4 ;
        RECT  0 10.56 0.084 10.584 ;
    END
  END captured[26]
  PIN captured[270]
    DIRECTION INPUT ;
    USE SIGNAL ;
    PORT
      LAYER M4 ;
        RECT  0 85.056 0.084 85.08 ;
    END
  END captured[270]
  PIN captured[271]
    DIRECTION INPUT ;
    USE SIGNAL ;
    PORT
      LAYER M4 ;
        RECT  0 85.392 0.084 85.416 ;
    END
  END captured[271]
  PIN captured[272]
    DIRECTION INPUT ;
    USE SIGNAL ;
    PORT
      LAYER M4 ;
        RECT  0 85.68 0.084 85.704 ;
    END
  END captured[272]
  PIN captured[273]
    DIRECTION INPUT ;
    USE SIGNAL ;
    PORT
      LAYER M4 ;
        RECT  0 85.968 0.084 85.992 ;
    END
  END captured[273]
  PIN captured[274]
    DIRECTION INPUT ;
    USE SIGNAL ;
    PORT
      LAYER M4 ;
        RECT  0 86.304 0.084 86.328 ;
    END
  END captured[274]
  PIN captured[275]
    DIRECTION INPUT ;
    USE SIGNAL ;
    PORT
      LAYER M4 ;
        RECT  0 86.592 0.084 86.616 ;
    END
  END captured[275]
  PIN captured[276]
    DIRECTION INPUT ;
    USE SIGNAL ;
    PORT
      LAYER M4 ;
        RECT  0 86.88 0.084 86.904 ;
    END
  END captured[276]
  PIN captured[277]
    DIRECTION INPUT ;
    USE SIGNAL ;
    PORT
      LAYER M4 ;
        RECT  0 87.216 0.084 87.24 ;
    END
  END captured[277]
  PIN captured[278]
    DIRECTION INPUT ;
    USE SIGNAL ;
    PORT
      LAYER M4 ;
        RECT  0 87.504 0.084 87.528 ;
    END
  END captured[278]
  PIN captured[279]
    DIRECTION INPUT ;
    USE SIGNAL ;
    PORT
      LAYER M4 ;
        RECT  0 87.792 0.084 87.816 ;
    END
  END captured[279]
  PIN captured[27]
    DIRECTION INPUT ;
    USE SIGNAL ;
    PORT
      LAYER M4 ;
        RECT  0 10.896 0.084 10.92 ;
    END
  END captured[27]
  PIN captured[280]
    DIRECTION INPUT ;
    USE SIGNAL ;
    PORT
      LAYER M4 ;
        RECT  0 88.128 0.084 88.152 ;
    END
  END captured[280]
  PIN captured[281]
    DIRECTION INPUT ;
    USE SIGNAL ;
    PORT
      LAYER M4 ;
        RECT  0 88.416 0.084 88.44 ;
    END
  END captured[281]
  PIN captured[282]
    DIRECTION INPUT ;
    USE SIGNAL ;
    PORT
      LAYER M4 ;
        RECT  0 88.752 0.084 88.776 ;
    END
  END captured[282]
  PIN captured[283]
    DIRECTION INPUT ;
    USE SIGNAL ;
    PORT
      LAYER M4 ;
        RECT  0 89.04 0.084 89.064 ;
    END
  END captured[283]
  PIN captured[284]
    DIRECTION INPUT ;
    USE SIGNAL ;
    PORT
      LAYER M4 ;
        RECT  0 89.328 0.084 89.352 ;
    END
  END captured[284]
  PIN captured[285]
    DIRECTION INPUT ;
    USE SIGNAL ;
    PORT
      LAYER M4 ;
        RECT  0 89.664 0.084 89.688 ;
    END
  END captured[285]
  PIN captured[286]
    DIRECTION INPUT ;
    USE SIGNAL ;
    PORT
      LAYER M4 ;
        RECT  0 89.952 0.084 89.976 ;
    END
  END captured[286]
  PIN captured[287]
    DIRECTION INPUT ;
    USE SIGNAL ;
    PORT
      LAYER M4 ;
        RECT  0 90.24 0.084 90.264 ;
    END
  END captured[287]
  PIN captured[288]
    DIRECTION INPUT ;
    USE SIGNAL ;
    PORT
      LAYER M4 ;
        RECT  0 90.576 0.084 90.6 ;
    END
  END captured[288]
  PIN captured[289]
    DIRECTION INPUT ;
    USE SIGNAL ;
    PORT
      LAYER M4 ;
        RECT  0 90.864 0.084 90.888 ;
    END
  END captured[289]
  PIN captured[28]
    DIRECTION INPUT ;
    USE SIGNAL ;
    PORT
      LAYER M4 ;
        RECT  0 11.184 0.084 11.208 ;
    END
  END captured[28]
  PIN captured[290]
    DIRECTION INPUT ;
    USE SIGNAL ;
    PORT
      LAYER M4 ;
        RECT  0 91.152 0.084 91.176 ;
    END
  END captured[290]
  PIN captured[291]
    DIRECTION INPUT ;
    USE SIGNAL ;
    PORT
      LAYER M4 ;
        RECT  0 91.488 0.084 91.512 ;
    END
  END captured[291]
  PIN captured[292]
    DIRECTION INPUT ;
    USE SIGNAL ;
    PORT
      LAYER M4 ;
        RECT  0 91.776 0.084 91.8 ;
    END
  END captured[292]
  PIN captured[293]
    DIRECTION INPUT ;
    USE SIGNAL ;
    PORT
      LAYER M4 ;
        RECT  0 92.112 0.084 92.136 ;
    END
  END captured[293]
  PIN captured[294]
    DIRECTION INPUT ;
    USE SIGNAL ;
    PORT
      LAYER M4 ;
        RECT  0 92.4 0.084 92.424 ;
    END
  END captured[294]
  PIN captured[295]
    DIRECTION INPUT ;
    USE SIGNAL ;
    PORT
      LAYER M4 ;
        RECT  0 92.688 0.084 92.712 ;
    END
  END captured[295]
  PIN captured[296]
    DIRECTION INPUT ;
    USE SIGNAL ;
    PORT
      LAYER M4 ;
        RECT  0 93.024 0.084 93.048 ;
    END
  END captured[296]
  PIN captured[297]
    DIRECTION INPUT ;
    USE SIGNAL ;
    PORT
      LAYER M4 ;
        RECT  0 93.312 0.084 93.336 ;
    END
  END captured[297]
  PIN captured[298]
    DIRECTION INPUT ;
    USE SIGNAL ;
    PORT
      LAYER M4 ;
        RECT  0 93.6 0.084 93.624 ;
    END
  END captured[298]
  PIN captured[299]
    DIRECTION INPUT ;
    USE SIGNAL ;
    PORT
      LAYER M4 ;
        RECT  0 93.936 0.084 93.96 ;
    END
  END captured[299]
  PIN captured[29]
    DIRECTION INPUT ;
    USE SIGNAL ;
    PORT
      LAYER M4 ;
        RECT  0 11.472 0.084 11.496 ;
    END
  END captured[29]
  PIN captured[2]
    DIRECTION INPUT ;
    USE SIGNAL ;
    PORT
      LAYER M4 ;
        RECT  0 3.264 0.084 3.288 ;
    END
  END captured[2]
  PIN captured[300]
    DIRECTION INPUT ;
    USE SIGNAL ;
    PORT
      LAYER M4 ;
        RECT  0 94.224 0.084 94.248 ;
    END
  END captured[300]
  PIN captured[301]
    DIRECTION INPUT ;
    USE SIGNAL ;
    PORT
      LAYER M4 ;
        RECT  0 94.512 0.084 94.536 ;
    END
  END captured[301]
  PIN captured[302]
    DIRECTION INPUT ;
    USE SIGNAL ;
    PORT
      LAYER M4 ;
        RECT  0 94.848 0.084 94.872 ;
    END
  END captured[302]
  PIN captured[303]
    DIRECTION INPUT ;
    USE SIGNAL ;
    PORT
      LAYER M4 ;
        RECT  0 95.136 0.084 95.16 ;
    END
  END captured[303]
  PIN captured[304]
    DIRECTION INPUT ;
    USE SIGNAL ;
    PORT
      LAYER M4 ;
        RECT  0 95.424 0.084 95.448 ;
    END
  END captured[304]
  PIN captured[305]
    DIRECTION INPUT ;
    USE SIGNAL ;
    PORT
      LAYER M4 ;
        RECT  0 95.76 0.084 95.784 ;
    END
  END captured[305]
  PIN captured[306]
    DIRECTION INPUT ;
    USE SIGNAL ;
    PORT
      LAYER M4 ;
        RECT  0 96.048 0.084 96.072 ;
    END
  END captured[306]
  PIN captured[307]
    DIRECTION INPUT ;
    USE SIGNAL ;
    PORT
      LAYER M4 ;
        RECT  0 96.384 0.084 96.408 ;
    END
  END captured[307]
  PIN captured[308]
    DIRECTION INPUT ;
    USE SIGNAL ;
    PORT
      LAYER M4 ;
        RECT  0 96.672 0.084 96.696 ;
    END
  END captured[308]
  PIN captured[309]
    DIRECTION INPUT ;
    USE SIGNAL ;
    PORT
      LAYER M4 ;
        RECT  0 96.96 0.084 96.984 ;
    END
  END captured[309]
  PIN captured[30]
    DIRECTION INPUT ;
    USE SIGNAL ;
    PORT
      LAYER M4 ;
        RECT  0 11.808 0.084 11.832 ;
    END
  END captured[30]
  PIN captured[310]
    DIRECTION INPUT ;
    USE SIGNAL ;
    PORT
      LAYER M4 ;
        RECT  0 97.296 0.084 97.32 ;
    END
  END captured[310]
  PIN captured[311]
    DIRECTION INPUT ;
    USE SIGNAL ;
    PORT
      LAYER M4 ;
        RECT  0 97.584 0.084 97.608 ;
    END
  END captured[311]
  PIN captured[312]
    DIRECTION INPUT ;
    USE SIGNAL ;
    PORT
      LAYER M4 ;
        RECT  0 97.872 0.084 97.896 ;
    END
  END captured[312]
  PIN captured[313]
    DIRECTION INPUT ;
    USE SIGNAL ;
    PORT
      LAYER M4 ;
        RECT  0 98.208 0.084 98.232 ;
    END
  END captured[313]
  PIN captured[314]
    DIRECTION INPUT ;
    USE SIGNAL ;
    PORT
      LAYER M4 ;
        RECT  0 98.496 0.084 98.52 ;
    END
  END captured[314]
  PIN captured[315]
    DIRECTION INPUT ;
    USE SIGNAL ;
    PORT
      LAYER M4 ;
        RECT  0 98.784 0.084 98.808 ;
    END
  END captured[315]
  PIN captured[316]
    DIRECTION INPUT ;
    USE SIGNAL ;
    PORT
      LAYER M4 ;
        RECT  0 99.12 0.084 99.144 ;
    END
  END captured[316]
  PIN captured[317]
    DIRECTION INPUT ;
    USE SIGNAL ;
    PORT
      LAYER M4 ;
        RECT  0 99.408 0.084 99.432 ;
    END
  END captured[317]
  PIN captured[318]
    DIRECTION INPUT ;
    USE SIGNAL ;
    PORT
      LAYER M4 ;
        RECT  0 99.744 0.084 99.768 ;
    END
  END captured[318]
  PIN captured[319]
    DIRECTION INPUT ;
    USE SIGNAL ;
    PORT
      LAYER M4 ;
        RECT  0 100.032 0.084 100.056 ;
    END
  END captured[319]
  PIN captured[31]
    DIRECTION INPUT ;
    USE SIGNAL ;
    PORT
      LAYER M4 ;
        RECT  0 12.096 0.084 12.12 ;
    END
  END captured[31]
  PIN captured[32]
    DIRECTION INPUT ;
    USE SIGNAL ;
    PORT
      LAYER M4 ;
        RECT  0 12.432 0.084 12.456 ;
    END
  END captured[32]
  PIN captured[33]
    DIRECTION INPUT ;
    USE SIGNAL ;
    PORT
      LAYER M4 ;
        RECT  0 12.72 0.084 12.744 ;
    END
  END captured[33]
  PIN captured[34]
    DIRECTION INPUT ;
    USE SIGNAL ;
    PORT
      LAYER M4 ;
        RECT  0 13.008 0.084 13.032 ;
    END
  END captured[34]
  PIN captured[35]
    DIRECTION INPUT ;
    USE SIGNAL ;
    PORT
      LAYER M4 ;
        RECT  0 13.344 0.084 13.368 ;
    END
  END captured[35]
  PIN captured[36]
    DIRECTION INPUT ;
    USE SIGNAL ;
    PORT
      LAYER M4 ;
        RECT  0 13.632 0.084 13.656 ;
    END
  END captured[36]
  PIN captured[37]
    DIRECTION INPUT ;
    USE SIGNAL ;
    PORT
      LAYER M4 ;
        RECT  0 13.92 0.084 13.944 ;
    END
  END captured[37]
  PIN captured[38]
    DIRECTION INPUT ;
    USE SIGNAL ;
    PORT
      LAYER M4 ;
        RECT  0 14.256 0.084 14.28 ;
    END
  END captured[38]
  PIN captured[39]
    DIRECTION INPUT ;
    USE SIGNAL ;
    PORT
      LAYER M4 ;
        RECT  0 14.544 0.084 14.568 ;
    END
  END captured[39]
  PIN captured[3]
    DIRECTION INPUT ;
    USE SIGNAL ;
    PORT
      LAYER M4 ;
        RECT  0 3.552 0.084 3.576 ;
    END
  END captured[3]
  PIN captured[40]
    DIRECTION INPUT ;
    USE SIGNAL ;
    PORT
      LAYER M4 ;
        RECT  0 14.832 0.084 14.856 ;
    END
  END captured[40]
  PIN captured[41]
    DIRECTION INPUT ;
    USE SIGNAL ;
    PORT
      LAYER M4 ;
        RECT  0 15.168 0.084 15.192 ;
    END
  END captured[41]
  PIN captured[42]
    DIRECTION INPUT ;
    USE SIGNAL ;
    PORT
      LAYER M4 ;
        RECT  0 15.456 0.084 15.48 ;
    END
  END captured[42]
  PIN captured[43]
    DIRECTION INPUT ;
    USE SIGNAL ;
    PORT
      LAYER M4 ;
        RECT  0 15.792 0.084 15.816 ;
    END
  END captured[43]
  PIN captured[44]
    DIRECTION INPUT ;
    USE SIGNAL ;
    PORT
      LAYER M4 ;
        RECT  0 16.08 0.084 16.104 ;
    END
  END captured[44]
  PIN captured[45]
    DIRECTION INPUT ;
    USE SIGNAL ;
    PORT
      LAYER M4 ;
        RECT  0 16.368 0.084 16.392 ;
    END
  END captured[45]
  PIN captured[46]
    DIRECTION INPUT ;
    USE SIGNAL ;
    PORT
      LAYER M4 ;
        RECT  0 16.704 0.084 16.728 ;
    END
  END captured[46]
  PIN captured[47]
    DIRECTION INPUT ;
    USE SIGNAL ;
    PORT
      LAYER M4 ;
        RECT  0 16.992 0.084 17.016 ;
    END
  END captured[47]
  PIN captured[48]
    DIRECTION INPUT ;
    USE SIGNAL ;
    PORT
      LAYER M4 ;
        RECT  0 17.28 0.084 17.304 ;
    END
  END captured[48]
  PIN captured[49]
    DIRECTION INPUT ;
    USE SIGNAL ;
    PORT
      LAYER M4 ;
        RECT  0 17.616 0.084 17.64 ;
    END
  END captured[49]
  PIN captured[4]
    DIRECTION INPUT ;
    USE SIGNAL ;
    PORT
      LAYER M4 ;
        RECT  0 3.84 0.084 3.864 ;
    END
  END captured[4]
  PIN captured[50]
    DIRECTION INPUT ;
    USE SIGNAL ;
    PORT
      LAYER M4 ;
        RECT  0 17.904 0.084 17.928 ;
    END
  END captured[50]
  PIN captured[51]
    DIRECTION INPUT ;
    USE SIGNAL ;
    PORT
      LAYER M4 ;
        RECT  0 18.192 0.084 18.216 ;
    END
  END captured[51]
  PIN captured[52]
    DIRECTION INPUT ;
    USE SIGNAL ;
    PORT
      LAYER M4 ;
        RECT  0 18.528 0.084 18.552 ;
    END
  END captured[52]
  PIN captured[53]
    DIRECTION INPUT ;
    USE SIGNAL ;
    PORT
      LAYER M4 ;
        RECT  0 18.816 0.084 18.84 ;
    END
  END captured[53]
  PIN captured[54]
    DIRECTION INPUT ;
    USE SIGNAL ;
    PORT
      LAYER M4 ;
        RECT  0 19.104 0.084 19.128 ;
    END
  END captured[54]
  PIN captured[55]
    DIRECTION INPUT ;
    USE SIGNAL ;
    PORT
      LAYER M4 ;
        RECT  0 19.44 0.084 19.464 ;
    END
  END captured[55]
  PIN captured[56]
    DIRECTION INPUT ;
    USE SIGNAL ;
    PORT
      LAYER M4 ;
        RECT  0 19.728 0.084 19.752 ;
    END
  END captured[56]
  PIN captured[57]
    DIRECTION INPUT ;
    USE SIGNAL ;
    PORT
      LAYER M4 ;
        RECT  0 20.064 0.084 20.088 ;
    END
  END captured[57]
  PIN captured[58]
    DIRECTION INPUT ;
    USE SIGNAL ;
    PORT
      LAYER M4 ;
        RECT  0 20.352 0.084 20.376 ;
    END
  END captured[58]
  PIN captured[59]
    DIRECTION INPUT ;
    USE SIGNAL ;
    PORT
      LAYER M4 ;
        RECT  0 20.64 0.084 20.664 ;
    END
  END captured[59]
  PIN captured[5]
    DIRECTION INPUT ;
    USE SIGNAL ;
    PORT
      LAYER M4 ;
        RECT  0 4.176 0.084 4.2 ;
    END
  END captured[5]
  PIN captured[60]
    DIRECTION INPUT ;
    USE SIGNAL ;
    PORT
      LAYER M4 ;
        RECT  0 20.976 0.084 21 ;
    END
  END captured[60]
  PIN captured[61]
    DIRECTION INPUT ;
    USE SIGNAL ;
    PORT
      LAYER M4 ;
        RECT  0 21.264 0.084 21.288 ;
    END
  END captured[61]
  PIN captured[62]
    DIRECTION INPUT ;
    USE SIGNAL ;
    PORT
      LAYER M4 ;
        RECT  0 21.552 0.084 21.576 ;
    END
  END captured[62]
  PIN captured[63]
    DIRECTION INPUT ;
    USE SIGNAL ;
    PORT
      LAYER M4 ;
        RECT  0 21.888 0.084 21.912 ;
    END
  END captured[63]
  PIN captured[64]
    DIRECTION INPUT ;
    USE SIGNAL ;
    PORT
      LAYER M4 ;
        RECT  0 22.176 0.084 22.2 ;
    END
  END captured[64]
  PIN captured[65]
    DIRECTION INPUT ;
    USE SIGNAL ;
    PORT
      LAYER M4 ;
        RECT  0 22.464 0.084 22.488 ;
    END
  END captured[65]
  PIN captured[66]
    DIRECTION INPUT ;
    USE SIGNAL ;
    PORT
      LAYER M4 ;
        RECT  0 22.8 0.084 22.824 ;
    END
  END captured[66]
  PIN captured[67]
    DIRECTION INPUT ;
    USE SIGNAL ;
    PORT
      LAYER M4 ;
        RECT  0 23.088 0.084 23.112 ;
    END
  END captured[67]
  PIN captured[68]
    DIRECTION INPUT ;
    USE SIGNAL ;
    PORT
      LAYER M4 ;
        RECT  0 23.424 0.084 23.448 ;
    END
  END captured[68]
  PIN captured[69]
    DIRECTION INPUT ;
    USE SIGNAL ;
    PORT
      LAYER M4 ;
        RECT  0 23.712 0.084 23.736 ;
    END
  END captured[69]
  PIN captured[6]
    DIRECTION INPUT ;
    USE SIGNAL ;
    PORT
      LAYER M4 ;
        RECT  0 4.464 0.084 4.488 ;
    END
  END captured[6]
  PIN captured[70]
    DIRECTION INPUT ;
    USE SIGNAL ;
    PORT
      LAYER M4 ;
        RECT  0 24 0.084 24.024 ;
    END
  END captured[70]
  PIN captured[71]
    DIRECTION INPUT ;
    USE SIGNAL ;
    PORT
      LAYER M4 ;
        RECT  0 24.336 0.084 24.36 ;
    END
  END captured[71]
  PIN captured[72]
    DIRECTION INPUT ;
    USE SIGNAL ;
    PORT
      LAYER M4 ;
        RECT  0 24.624 0.084 24.648 ;
    END
  END captured[72]
  PIN captured[73]
    DIRECTION INPUT ;
    USE SIGNAL ;
    PORT
      LAYER M4 ;
        RECT  0 24.912 0.084 24.936 ;
    END
  END captured[73]
  PIN captured[74]
    DIRECTION INPUT ;
    USE SIGNAL ;
    PORT
      LAYER M4 ;
        RECT  0 25.248 0.084 25.272 ;
    END
  END captured[74]
  PIN captured[75]
    DIRECTION INPUT ;
    USE SIGNAL ;
    PORT
      LAYER M4 ;
        RECT  0 25.536 0.084 25.56 ;
    END
  END captured[75]
  PIN captured[76]
    DIRECTION INPUT ;
    USE SIGNAL ;
    PORT
      LAYER M4 ;
        RECT  0 25.824 0.084 25.848 ;
    END
  END captured[76]
  PIN captured[77]
    DIRECTION INPUT ;
    USE SIGNAL ;
    PORT
      LAYER M4 ;
        RECT  0 26.16 0.084 26.184 ;
    END
  END captured[77]
  PIN captured[78]
    DIRECTION INPUT ;
    USE SIGNAL ;
    PORT
      LAYER M4 ;
        RECT  0 26.448 0.084 26.472 ;
    END
  END captured[78]
  PIN captured[79]
    DIRECTION INPUT ;
    USE SIGNAL ;
    PORT
      LAYER M4 ;
        RECT  0 26.736 0.084 26.76 ;
    END
  END captured[79]
  PIN captured[7]
    DIRECTION INPUT ;
    USE SIGNAL ;
    PORT
      LAYER M4 ;
        RECT  0 4.8 0.084 4.824 ;
    END
  END captured[7]
  PIN captured[80]
    DIRECTION INPUT ;
    USE SIGNAL ;
    PORT
      LAYER M4 ;
        RECT  0 27.072 0.084 27.096 ;
    END
  END captured[80]
  PIN captured[81]
    DIRECTION INPUT ;
    USE SIGNAL ;
    PORT
      LAYER M4 ;
        RECT  0 27.36 0.084 27.384 ;
    END
  END captured[81]
  PIN captured[82]
    DIRECTION INPUT ;
    USE SIGNAL ;
    PORT
      LAYER M4 ;
        RECT  0 27.696 0.084 27.72 ;
    END
  END captured[82]
  PIN captured[83]
    DIRECTION INPUT ;
    USE SIGNAL ;
    PORT
      LAYER M4 ;
        RECT  0 27.984 0.084 28.008 ;
    END
  END captured[83]
  PIN captured[84]
    DIRECTION INPUT ;
    USE SIGNAL ;
    PORT
      LAYER M4 ;
        RECT  0 28.272 0.084 28.296 ;
    END
  END captured[84]
  PIN captured[85]
    DIRECTION INPUT ;
    USE SIGNAL ;
    PORT
      LAYER M4 ;
        RECT  0 28.608 0.084 28.632 ;
    END
  END captured[85]
  PIN captured[86]
    DIRECTION INPUT ;
    USE SIGNAL ;
    PORT
      LAYER M4 ;
        RECT  0 28.896 0.084 28.92 ;
    END
  END captured[86]
  PIN captured[87]
    DIRECTION INPUT ;
    USE SIGNAL ;
    PORT
      LAYER M4 ;
        RECT  0 29.184 0.084 29.208 ;
    END
  END captured[87]
  PIN captured[88]
    DIRECTION INPUT ;
    USE SIGNAL ;
    PORT
      LAYER M4 ;
        RECT  0 29.52 0.084 29.544 ;
    END
  END captured[88]
  PIN captured[89]
    DIRECTION INPUT ;
    USE SIGNAL ;
    PORT
      LAYER M4 ;
        RECT  0 29.808 0.084 29.832 ;
    END
  END captured[89]
  PIN captured[8]
    DIRECTION INPUT ;
    USE SIGNAL ;
    PORT
      LAYER M4 ;
        RECT  0 5.088 0.084 5.112 ;
    END
  END captured[8]
  PIN captured[90]
    DIRECTION INPUT ;
    USE SIGNAL ;
    PORT
      LAYER M4 ;
        RECT  0 30.096 0.084 30.12 ;
    END
  END captured[90]
  PIN captured[91]
    DIRECTION INPUT ;
    USE SIGNAL ;
    PORT
      LAYER M4 ;
        RECT  0 30.432 0.084 30.456 ;
    END
  END captured[91]
  PIN captured[92]
    DIRECTION INPUT ;
    USE SIGNAL ;
    PORT
      LAYER M4 ;
        RECT  0 30.72 0.084 30.744 ;
    END
  END captured[92]
  PIN captured[93]
    DIRECTION INPUT ;
    USE SIGNAL ;
    PORT
      LAYER M4 ;
        RECT  0 31.056 0.084 31.08 ;
    END
  END captured[93]
  PIN captured[94]
    DIRECTION INPUT ;
    USE SIGNAL ;
    PORT
      LAYER M4 ;
        RECT  0 31.344 0.084 31.368 ;
    END
  END captured[94]
  PIN captured[95]
    DIRECTION INPUT ;
    USE SIGNAL ;
    PORT
      LAYER M4 ;
        RECT  0 31.632 0.084 31.656 ;
    END
  END captured[95]
  PIN captured[96]
    DIRECTION INPUT ;
    USE SIGNAL ;
    PORT
      LAYER M4 ;
        RECT  0 31.968 0.084 31.992 ;
    END
  END captured[96]
  PIN captured[97]
    DIRECTION INPUT ;
    USE SIGNAL ;
    PORT
      LAYER M4 ;
        RECT  0 32.256 0.084 32.28 ;
    END
  END captured[97]
  PIN captured[98]
    DIRECTION INPUT ;
    USE SIGNAL ;
    PORT
      LAYER M4 ;
        RECT  0 32.544 0.084 32.568 ;
    END
  END captured[98]
  PIN captured[99]
    DIRECTION INPUT ;
    USE SIGNAL ;
    PORT
      LAYER M4 ;
        RECT  0 32.88 0.084 32.904 ;
    END
  END captured[99]
  PIN captured[9]
    DIRECTION INPUT ;
    USE SIGNAL ;
    PORT
      LAYER M4 ;
        RECT  0 5.376 0.084 5.4 ;
    END
  END captured[9]
  PIN captured_slot[0]
    DIRECTION INPUT ;
    USE SIGNAL ;
    PORT
      LAYER M4 ;
        RECT  0 100.512 0.084 100.536 ;
    END
  END captured_slot[0]
  PIN captured_slot[1]
    DIRECTION INPUT ;
    USE SIGNAL ;
    PORT
      LAYER M4 ;
        RECT  0 100.8 0.084 100.824 ;
    END
  END captured_slot[1]
  PIN captured_slot[2]
    DIRECTION INPUT ;
    USE SIGNAL ;
    PORT
      LAYER M4 ;
        RECT  0 101.088 0.084 101.112 ;
    END
  END captured_slot[2]
  PIN captured_slot[3]
    DIRECTION INPUT ;
    USE SIGNAL ;
    PORT
      LAYER M4 ;
        RECT  0 101.328 0.084 101.352 ;
    END
  END captured_slot[3]
  PIN captured_slot[4]
    DIRECTION INPUT ;
    USE SIGNAL ;
    PORT
      LAYER M4 ;
        RECT  0 101.616 0.084 101.64 ;
    END
  END captured_slot[4]
  PIN captured_slot[5]
    DIRECTION INPUT ;
    USE SIGNAL ;
    PORT
      LAYER M4 ;
        RECT  0 101.904 0.084 101.928 ;
    END
  END captured_slot[5]
  PIN captured_slot[6]
    DIRECTION INPUT ;
    USE SIGNAL ;
    PORT
      LAYER M4 ;
        RECT  0 102.144 0.084 102.168 ;
    END
  END captured_slot[6]
  PIN captured_slot[7]
    DIRECTION INPUT ;
    USE SIGNAL ;
    PORT
      LAYER M4 ;
        RECT  0 102.432 0.084 102.456 ;
    END
  END captured_slot[7]
  PIN captured_slot[8]
    DIRECTION INPUT ;
    USE SIGNAL ;
    PORT
      LAYER M4 ;
        RECT  0 102.72 0.084 102.744 ;
    END
  END captured_slot[8]
  PIN captured_slot[9]
    DIRECTION INPUT ;
    USE SIGNAL ;
    PORT
      LAYER M4 ;
        RECT  0 103.008 0.084 103.032 ;
    END
  END captured_slot[9]
  PIN clk
    DIRECTION INPUT ;
    USE SIGNAL ;
    PORT
      LAYER M5 ;
        RECT  21.552 105.756 21.576 105.84 ;
    END
  END clk
  PIN dst_d[0]
    DIRECTION OUTPUT ;
    USE SIGNAL ;
    PORT
      LAYER M4 ;
        RECT  25.836 2.592 25.92 2.616 ;
    END
  END dst_d[0]
  PIN dst_d[100]
    DIRECTION OUTPUT ;
    USE SIGNAL ;
    PORT
      LAYER M4 ;
        RECT  25.836 22.704 25.92 22.728 ;
    END
  END dst_d[100]
  PIN dst_d[101]
    DIRECTION OUTPUT ;
    USE SIGNAL ;
    PORT
      LAYER M4 ;
        RECT  25.836 22.896 25.92 22.92 ;
    END
  END dst_d[101]
  PIN dst_d[102]
    DIRECTION OUTPUT ;
    USE SIGNAL ;
    PORT
      LAYER M4 ;
        RECT  25.836 23.088 25.92 23.112 ;
    END
  END dst_d[102]
  PIN dst_d[103]
    DIRECTION OUTPUT ;
    USE SIGNAL ;
    PORT
      LAYER M4 ;
        RECT  25.836 23.28 25.92 23.304 ;
    END
  END dst_d[103]
  PIN dst_d[104]
    DIRECTION OUTPUT ;
    USE SIGNAL ;
    PORT
      LAYER M4 ;
        RECT  25.836 23.472 25.92 23.496 ;
    END
  END dst_d[104]
  PIN dst_d[105]
    DIRECTION OUTPUT ;
    USE SIGNAL ;
    PORT
      LAYER M4 ;
        RECT  25.836 23.664 25.92 23.688 ;
    END
  END dst_d[105]
  PIN dst_d[106]
    DIRECTION OUTPUT ;
    USE SIGNAL ;
    PORT
      LAYER M4 ;
        RECT  25.836 23.904 25.92 23.928 ;
    END
  END dst_d[106]
  PIN dst_d[107]
    DIRECTION OUTPUT ;
    USE SIGNAL ;
    PORT
      LAYER M4 ;
        RECT  25.836 24.096 25.92 24.12 ;
    END
  END dst_d[107]
  PIN dst_d[108]
    DIRECTION OUTPUT ;
    USE SIGNAL ;
    PORT
      LAYER M4 ;
        RECT  25.836 24.288 25.92 24.312 ;
    END
  END dst_d[108]
  PIN dst_d[109]
    DIRECTION OUTPUT ;
    USE SIGNAL ;
    PORT
      LAYER M4 ;
        RECT  25.836 24.48 25.92 24.504 ;
    END
  END dst_d[109]
  PIN dst_d[10]
    DIRECTION OUTPUT ;
    USE SIGNAL ;
    PORT
      LAYER M4 ;
        RECT  25.836 4.608 25.92 4.632 ;
    END
  END dst_d[10]
  PIN dst_d[110]
    DIRECTION OUTPUT ;
    USE SIGNAL ;
    PORT
      LAYER M4 ;
        RECT  25.836 24.672 25.92 24.696 ;
    END
  END dst_d[110]
  PIN dst_d[111]
    DIRECTION OUTPUT ;
    USE SIGNAL ;
    PORT
      LAYER M4 ;
        RECT  25.836 24.912 25.92 24.936 ;
    END
  END dst_d[111]
  PIN dst_d[112]
    DIRECTION OUTPUT ;
    USE SIGNAL ;
    PORT
      LAYER M4 ;
        RECT  25.836 25.104 25.92 25.128 ;
    END
  END dst_d[112]
  PIN dst_d[113]
    DIRECTION OUTPUT ;
    USE SIGNAL ;
    PORT
      LAYER M4 ;
        RECT  25.836 25.296 25.92 25.32 ;
    END
  END dst_d[113]
  PIN dst_d[114]
    DIRECTION OUTPUT ;
    USE SIGNAL ;
    PORT
      LAYER M4 ;
        RECT  25.836 25.488 25.92 25.512 ;
    END
  END dst_d[114]
  PIN dst_d[115]
    DIRECTION OUTPUT ;
    USE SIGNAL ;
    PORT
      LAYER M4 ;
        RECT  25.836 25.68 25.92 25.704 ;
    END
  END dst_d[115]
  PIN dst_d[116]
    DIRECTION OUTPUT ;
    USE SIGNAL ;
    PORT
      LAYER M4 ;
        RECT  25.836 25.872 25.92 25.896 ;
    END
  END dst_d[116]
  PIN dst_d[117]
    DIRECTION OUTPUT ;
    USE SIGNAL ;
    PORT
      LAYER M4 ;
        RECT  25.836 26.112 25.92 26.136 ;
    END
  END dst_d[117]
  PIN dst_d[118]
    DIRECTION OUTPUT ;
    USE SIGNAL ;
    PORT
      LAYER M4 ;
        RECT  25.836 26.304 25.92 26.328 ;
    END
  END dst_d[118]
  PIN dst_d[119]
    DIRECTION OUTPUT ;
    USE SIGNAL ;
    PORT
      LAYER M4 ;
        RECT  25.836 26.496 25.92 26.52 ;
    END
  END dst_d[119]
  PIN dst_d[11]
    DIRECTION OUTPUT ;
    USE SIGNAL ;
    PORT
      LAYER M4 ;
        RECT  25.836 4.8 25.92 4.824 ;
    END
  END dst_d[11]
  PIN dst_d[120]
    DIRECTION OUTPUT ;
    USE SIGNAL ;
    PORT
      LAYER M4 ;
        RECT  25.836 26.688 25.92 26.712 ;
    END
  END dst_d[120]
  PIN dst_d[121]
    DIRECTION OUTPUT ;
    USE SIGNAL ;
    PORT
      LAYER M4 ;
        RECT  25.836 26.88 25.92 26.904 ;
    END
  END dst_d[121]
  PIN dst_d[122]
    DIRECTION OUTPUT ;
    USE SIGNAL ;
    PORT
      LAYER M4 ;
        RECT  25.836 27.12 25.92 27.144 ;
    END
  END dst_d[122]
  PIN dst_d[123]
    DIRECTION OUTPUT ;
    USE SIGNAL ;
    PORT
      LAYER M4 ;
        RECT  25.836 27.312 25.92 27.336 ;
    END
  END dst_d[123]
  PIN dst_d[124]
    DIRECTION OUTPUT ;
    USE SIGNAL ;
    PORT
      LAYER M4 ;
        RECT  25.836 27.504 25.92 27.528 ;
    END
  END dst_d[124]
  PIN dst_d[125]
    DIRECTION OUTPUT ;
    USE SIGNAL ;
    PORT
      LAYER M4 ;
        RECT  25.836 27.696 25.92 27.72 ;
    END
  END dst_d[125]
  PIN dst_d[126]
    DIRECTION OUTPUT ;
    USE SIGNAL ;
    PORT
      LAYER M4 ;
        RECT  25.836 27.888 25.92 27.912 ;
    END
  END dst_d[126]
  PIN dst_d[127]
    DIRECTION OUTPUT ;
    USE SIGNAL ;
    PORT
      LAYER M4 ;
        RECT  25.836 28.128 25.92 28.152 ;
    END
  END dst_d[127]
  PIN dst_d[128]
    DIRECTION OUTPUT ;
    USE SIGNAL ;
    PORT
      LAYER M4 ;
        RECT  25.836 28.32 25.92 28.344 ;
    END
  END dst_d[128]
  PIN dst_d[129]
    DIRECTION OUTPUT ;
    USE SIGNAL ;
    PORT
      LAYER M4 ;
        RECT  25.836 28.512 25.92 28.536 ;
    END
  END dst_d[129]
  PIN dst_d[12]
    DIRECTION OUTPUT ;
    USE SIGNAL ;
    PORT
      LAYER M4 ;
        RECT  25.836 4.992 25.92 5.016 ;
    END
  END dst_d[12]
  PIN dst_d[130]
    DIRECTION OUTPUT ;
    USE SIGNAL ;
    PORT
      LAYER M4 ;
        RECT  25.836 28.704 25.92 28.728 ;
    END
  END dst_d[130]
  PIN dst_d[131]
    DIRECTION OUTPUT ;
    USE SIGNAL ;
    PORT
      LAYER M4 ;
        RECT  25.836 28.896 25.92 28.92 ;
    END
  END dst_d[131]
  PIN dst_d[132]
    DIRECTION OUTPUT ;
    USE SIGNAL ;
    PORT
      LAYER M4 ;
        RECT  25.836 29.088 25.92 29.112 ;
    END
  END dst_d[132]
  PIN dst_d[133]
    DIRECTION OUTPUT ;
    USE SIGNAL ;
    PORT
      LAYER M4 ;
        RECT  25.836 29.328 25.92 29.352 ;
    END
  END dst_d[133]
  PIN dst_d[134]
    DIRECTION OUTPUT ;
    USE SIGNAL ;
    PORT
      LAYER M4 ;
        RECT  25.836 29.52 25.92 29.544 ;
    END
  END dst_d[134]
  PIN dst_d[135]
    DIRECTION OUTPUT ;
    USE SIGNAL ;
    PORT
      LAYER M4 ;
        RECT  25.836 29.712 25.92 29.736 ;
    END
  END dst_d[135]
  PIN dst_d[136]
    DIRECTION OUTPUT ;
    USE SIGNAL ;
    PORT
      LAYER M4 ;
        RECT  25.836 29.904 25.92 29.928 ;
    END
  END dst_d[136]
  PIN dst_d[137]
    DIRECTION OUTPUT ;
    USE SIGNAL ;
    PORT
      LAYER M4 ;
        RECT  25.836 30.096 25.92 30.12 ;
    END
  END dst_d[137]
  PIN dst_d[138]
    DIRECTION OUTPUT ;
    USE SIGNAL ;
    PORT
      LAYER M4 ;
        RECT  25.836 30.336 25.92 30.36 ;
    END
  END dst_d[138]
  PIN dst_d[139]
    DIRECTION OUTPUT ;
    USE SIGNAL ;
    PORT
      LAYER M4 ;
        RECT  25.836 30.528 25.92 30.552 ;
    END
  END dst_d[139]
  PIN dst_d[13]
    DIRECTION OUTPUT ;
    USE SIGNAL ;
    PORT
      LAYER M4 ;
        RECT  25.836 5.184 25.92 5.208 ;
    END
  END dst_d[13]
  PIN dst_d[140]
    DIRECTION OUTPUT ;
    USE SIGNAL ;
    PORT
      LAYER M4 ;
        RECT  25.836 30.72 25.92 30.744 ;
    END
  END dst_d[140]
  PIN dst_d[141]
    DIRECTION OUTPUT ;
    USE SIGNAL ;
    PORT
      LAYER M4 ;
        RECT  25.836 30.912 25.92 30.936 ;
    END
  END dst_d[141]
  PIN dst_d[142]
    DIRECTION OUTPUT ;
    USE SIGNAL ;
    PORT
      LAYER M4 ;
        RECT  25.836 31.104 25.92 31.128 ;
    END
  END dst_d[142]
  PIN dst_d[143]
    DIRECTION OUTPUT ;
    USE SIGNAL ;
    PORT
      LAYER M4 ;
        RECT  25.836 31.344 25.92 31.368 ;
    END
  END dst_d[143]
  PIN dst_d[144]
    DIRECTION OUTPUT ;
    USE SIGNAL ;
    PORT
      LAYER M4 ;
        RECT  25.836 31.536 25.92 31.56 ;
    END
  END dst_d[144]
  PIN dst_d[145]
    DIRECTION OUTPUT ;
    USE SIGNAL ;
    PORT
      LAYER M4 ;
        RECT  25.836 31.728 25.92 31.752 ;
    END
  END dst_d[145]
  PIN dst_d[146]
    DIRECTION OUTPUT ;
    USE SIGNAL ;
    PORT
      LAYER M4 ;
        RECT  25.836 31.92 25.92 31.944 ;
    END
  END dst_d[146]
  PIN dst_d[147]
    DIRECTION OUTPUT ;
    USE SIGNAL ;
    PORT
      LAYER M4 ;
        RECT  25.836 32.112 25.92 32.136 ;
    END
  END dst_d[147]
  PIN dst_d[148]
    DIRECTION OUTPUT ;
    USE SIGNAL ;
    PORT
      LAYER M4 ;
        RECT  25.836 32.304 25.92 32.328 ;
    END
  END dst_d[148]
  PIN dst_d[149]
    DIRECTION OUTPUT ;
    USE SIGNAL ;
    PORT
      LAYER M4 ;
        RECT  25.836 32.544 25.92 32.568 ;
    END
  END dst_d[149]
  PIN dst_d[14]
    DIRECTION OUTPUT ;
    USE SIGNAL ;
    PORT
      LAYER M4 ;
        RECT  25.836 5.424 25.92 5.448 ;
    END
  END dst_d[14]
  PIN dst_d[150]
    DIRECTION OUTPUT ;
    USE SIGNAL ;
    PORT
      LAYER M4 ;
        RECT  25.836 32.736 25.92 32.76 ;
    END
  END dst_d[150]
  PIN dst_d[151]
    DIRECTION OUTPUT ;
    USE SIGNAL ;
    PORT
      LAYER M4 ;
        RECT  25.836 32.928 25.92 32.952 ;
    END
  END dst_d[151]
  PIN dst_d[152]
    DIRECTION OUTPUT ;
    USE SIGNAL ;
    PORT
      LAYER M4 ;
        RECT  25.836 33.12 25.92 33.144 ;
    END
  END dst_d[152]
  PIN dst_d[153]
    DIRECTION OUTPUT ;
    USE SIGNAL ;
    PORT
      LAYER M4 ;
        RECT  25.836 33.312 25.92 33.336 ;
    END
  END dst_d[153]
  PIN dst_d[154]
    DIRECTION OUTPUT ;
    USE SIGNAL ;
    PORT
      LAYER M4 ;
        RECT  25.836 33.552 25.92 33.576 ;
    END
  END dst_d[154]
  PIN dst_d[155]
    DIRECTION OUTPUT ;
    USE SIGNAL ;
    PORT
      LAYER M4 ;
        RECT  25.836 33.744 25.92 33.768 ;
    END
  END dst_d[155]
  PIN dst_d[156]
    DIRECTION OUTPUT ;
    USE SIGNAL ;
    PORT
      LAYER M4 ;
        RECT  25.836 33.936 25.92 33.96 ;
    END
  END dst_d[156]
  PIN dst_d[157]
    DIRECTION OUTPUT ;
    USE SIGNAL ;
    PORT
      LAYER M4 ;
        RECT  25.836 34.128 25.92 34.152 ;
    END
  END dst_d[157]
  PIN dst_d[158]
    DIRECTION OUTPUT ;
    USE SIGNAL ;
    PORT
      LAYER M4 ;
        RECT  25.836 34.32 25.92 34.344 ;
    END
  END dst_d[158]
  PIN dst_d[159]
    DIRECTION OUTPUT ;
    USE SIGNAL ;
    PORT
      LAYER M4 ;
        RECT  25.836 34.512 25.92 34.536 ;
    END
  END dst_d[159]
  PIN dst_d[15]
    DIRECTION OUTPUT ;
    USE SIGNAL ;
    PORT
      LAYER M4 ;
        RECT  25.836 5.616 25.92 5.64 ;
    END
  END dst_d[15]
  PIN dst_d[160]
    DIRECTION OUTPUT ;
    USE SIGNAL ;
    PORT
      LAYER M4 ;
        RECT  25.836 34.752 25.92 34.776 ;
    END
  END dst_d[160]
  PIN dst_d[161]
    DIRECTION OUTPUT ;
    USE SIGNAL ;
    PORT
      LAYER M4 ;
        RECT  25.836 34.944 25.92 34.968 ;
    END
  END dst_d[161]
  PIN dst_d[162]
    DIRECTION OUTPUT ;
    USE SIGNAL ;
    PORT
      LAYER M4 ;
        RECT  25.836 35.136 25.92 35.16 ;
    END
  END dst_d[162]
  PIN dst_d[163]
    DIRECTION OUTPUT ;
    USE SIGNAL ;
    PORT
      LAYER M4 ;
        RECT  25.836 35.328 25.92 35.352 ;
    END
  END dst_d[163]
  PIN dst_d[164]
    DIRECTION OUTPUT ;
    USE SIGNAL ;
    PORT
      LAYER M4 ;
        RECT  25.836 35.52 25.92 35.544 ;
    END
  END dst_d[164]
  PIN dst_d[165]
    DIRECTION OUTPUT ;
    USE SIGNAL ;
    PORT
      LAYER M4 ;
        RECT  25.836 35.76 25.92 35.784 ;
    END
  END dst_d[165]
  PIN dst_d[166]
    DIRECTION OUTPUT ;
    USE SIGNAL ;
    PORT
      LAYER M4 ;
        RECT  25.836 35.952 25.92 35.976 ;
    END
  END dst_d[166]
  PIN dst_d[167]
    DIRECTION OUTPUT ;
    USE SIGNAL ;
    PORT
      LAYER M4 ;
        RECT  25.836 36.144 25.92 36.168 ;
    END
  END dst_d[167]
  PIN dst_d[168]
    DIRECTION OUTPUT ;
    USE SIGNAL ;
    PORT
      LAYER M4 ;
        RECT  25.836 36.336 25.92 36.36 ;
    END
  END dst_d[168]
  PIN dst_d[169]
    DIRECTION OUTPUT ;
    USE SIGNAL ;
    PORT
      LAYER M4 ;
        RECT  25.836 36.528 25.92 36.552 ;
    END
  END dst_d[169]
  PIN dst_d[16]
    DIRECTION OUTPUT ;
    USE SIGNAL ;
    PORT
      LAYER M4 ;
        RECT  25.836 5.808 25.92 5.832 ;
    END
  END dst_d[16]
  PIN dst_d[170]
    DIRECTION OUTPUT ;
    USE SIGNAL ;
    PORT
      LAYER M4 ;
        RECT  25.836 36.768 25.92 36.792 ;
    END
  END dst_d[170]
  PIN dst_d[171]
    DIRECTION OUTPUT ;
    USE SIGNAL ;
    PORT
      LAYER M4 ;
        RECT  25.836 36.96 25.92 36.984 ;
    END
  END dst_d[171]
  PIN dst_d[172]
    DIRECTION OUTPUT ;
    USE SIGNAL ;
    PORT
      LAYER M4 ;
        RECT  25.836 37.152 25.92 37.176 ;
    END
  END dst_d[172]
  PIN dst_d[173]
    DIRECTION OUTPUT ;
    USE SIGNAL ;
    PORT
      LAYER M4 ;
        RECT  25.836 37.344 25.92 37.368 ;
    END
  END dst_d[173]
  PIN dst_d[174]
    DIRECTION OUTPUT ;
    USE SIGNAL ;
    PORT
      LAYER M4 ;
        RECT  25.836 37.536 25.92 37.56 ;
    END
  END dst_d[174]
  PIN dst_d[175]
    DIRECTION OUTPUT ;
    USE SIGNAL ;
    PORT
      LAYER M4 ;
        RECT  25.836 37.728 25.92 37.752 ;
    END
  END dst_d[175]
  PIN dst_d[176]
    DIRECTION OUTPUT ;
    USE SIGNAL ;
    PORT
      LAYER M4 ;
        RECT  25.836 37.968 25.92 37.992 ;
    END
  END dst_d[176]
  PIN dst_d[177]
    DIRECTION OUTPUT ;
    USE SIGNAL ;
    PORT
      LAYER M4 ;
        RECT  25.836 38.16 25.92 38.184 ;
    END
  END dst_d[177]
  PIN dst_d[178]
    DIRECTION OUTPUT ;
    USE SIGNAL ;
    PORT
      LAYER M4 ;
        RECT  25.836 38.352 25.92 38.376 ;
    END
  END dst_d[178]
  PIN dst_d[179]
    DIRECTION OUTPUT ;
    USE SIGNAL ;
    PORT
      LAYER M4 ;
        RECT  25.836 38.544 25.92 38.568 ;
    END
  END dst_d[179]
  PIN dst_d[17]
    DIRECTION OUTPUT ;
    USE SIGNAL ;
    PORT
      LAYER M4 ;
        RECT  25.836 6 25.92 6.024 ;
    END
  END dst_d[17]
  PIN dst_d[180]
    DIRECTION OUTPUT ;
    USE SIGNAL ;
    PORT
      LAYER M4 ;
        RECT  25.836 38.736 25.92 38.76 ;
    END
  END dst_d[180]
  PIN dst_d[181]
    DIRECTION OUTPUT ;
    USE SIGNAL ;
    PORT
      LAYER M4 ;
        RECT  25.836 38.976 25.92 39 ;
    END
  END dst_d[181]
  PIN dst_d[182]
    DIRECTION OUTPUT ;
    USE SIGNAL ;
    PORT
      LAYER M4 ;
        RECT  25.836 39.168 25.92 39.192 ;
    END
  END dst_d[182]
  PIN dst_d[183]
    DIRECTION OUTPUT ;
    USE SIGNAL ;
    PORT
      LAYER M4 ;
        RECT  25.836 39.36 25.92 39.384 ;
    END
  END dst_d[183]
  PIN dst_d[184]
    DIRECTION OUTPUT ;
    USE SIGNAL ;
    PORT
      LAYER M4 ;
        RECT  25.836 39.552 25.92 39.576 ;
    END
  END dst_d[184]
  PIN dst_d[185]
    DIRECTION OUTPUT ;
    USE SIGNAL ;
    PORT
      LAYER M4 ;
        RECT  25.836 39.744 25.92 39.768 ;
    END
  END dst_d[185]
  PIN dst_d[186]
    DIRECTION OUTPUT ;
    USE SIGNAL ;
    PORT
      LAYER M4 ;
        RECT  25.836 39.936 25.92 39.96 ;
    END
  END dst_d[186]
  PIN dst_d[187]
    DIRECTION OUTPUT ;
    USE SIGNAL ;
    PORT
      LAYER M4 ;
        RECT  25.836 40.176 25.92 40.2 ;
    END
  END dst_d[187]
  PIN dst_d[188]
    DIRECTION OUTPUT ;
    USE SIGNAL ;
    PORT
      LAYER M4 ;
        RECT  25.836 40.368 25.92 40.392 ;
    END
  END dst_d[188]
  PIN dst_d[189]
    DIRECTION OUTPUT ;
    USE SIGNAL ;
    PORT
      LAYER M4 ;
        RECT  25.836 40.56 25.92 40.584 ;
    END
  END dst_d[189]
  PIN dst_d[18]
    DIRECTION OUTPUT ;
    USE SIGNAL ;
    PORT
      LAYER M4 ;
        RECT  25.836 6.192 25.92 6.216 ;
    END
  END dst_d[18]
  PIN dst_d[190]
    DIRECTION OUTPUT ;
    USE SIGNAL ;
    PORT
      LAYER M4 ;
        RECT  25.836 40.752 25.92 40.776 ;
    END
  END dst_d[190]
  PIN dst_d[191]
    DIRECTION OUTPUT ;
    USE SIGNAL ;
    PORT
      LAYER M4 ;
        RECT  25.836 40.944 25.92 40.968 ;
    END
  END dst_d[191]
  PIN dst_d[192]
    DIRECTION OUTPUT ;
    USE SIGNAL ;
    PORT
      LAYER M4 ;
        RECT  25.836 41.184 25.92 41.208 ;
    END
  END dst_d[192]
  PIN dst_d[193]
    DIRECTION OUTPUT ;
    USE SIGNAL ;
    PORT
      LAYER M4 ;
        RECT  25.836 41.376 25.92 41.4 ;
    END
  END dst_d[193]
  PIN dst_d[194]
    DIRECTION OUTPUT ;
    USE SIGNAL ;
    PORT
      LAYER M4 ;
        RECT  25.836 41.568 25.92 41.592 ;
    END
  END dst_d[194]
  PIN dst_d[195]
    DIRECTION OUTPUT ;
    USE SIGNAL ;
    PORT
      LAYER M4 ;
        RECT  25.836 41.76 25.92 41.784 ;
    END
  END dst_d[195]
  PIN dst_d[196]
    DIRECTION OUTPUT ;
    USE SIGNAL ;
    PORT
      LAYER M4 ;
        RECT  25.836 41.952 25.92 41.976 ;
    END
  END dst_d[196]
  PIN dst_d[197]
    DIRECTION OUTPUT ;
    USE SIGNAL ;
    PORT
      LAYER M4 ;
        RECT  25.836 42.192 25.92 42.216 ;
    END
  END dst_d[197]
  PIN dst_d[198]
    DIRECTION OUTPUT ;
    USE SIGNAL ;
    PORT
      LAYER M4 ;
        RECT  25.836 42.384 25.92 42.408 ;
    END
  END dst_d[198]
  PIN dst_d[199]
    DIRECTION OUTPUT ;
    USE SIGNAL ;
    PORT
      LAYER M4 ;
        RECT  25.836 42.576 25.92 42.6 ;
    END
  END dst_d[199]
  PIN dst_d[19]
    DIRECTION OUTPUT ;
    USE SIGNAL ;
    PORT
      LAYER M4 ;
        RECT  25.836 6.384 25.92 6.408 ;
    END
  END dst_d[19]
  PIN dst_d[1]
    DIRECTION OUTPUT ;
    USE SIGNAL ;
    PORT
      LAYER M4 ;
        RECT  25.836 2.784 25.92 2.808 ;
    END
  END dst_d[1]
  PIN dst_d[200]
    DIRECTION OUTPUT ;
    USE SIGNAL ;
    PORT
      LAYER M4 ;
        RECT  25.836 42.768 25.92 42.792 ;
    END
  END dst_d[200]
  PIN dst_d[201]
    DIRECTION OUTPUT ;
    USE SIGNAL ;
    PORT
      LAYER M4 ;
        RECT  25.836 42.96 25.92 42.984 ;
    END
  END dst_d[201]
  PIN dst_d[202]
    DIRECTION OUTPUT ;
    USE SIGNAL ;
    PORT
      LAYER M4 ;
        RECT  25.836 43.152 25.92 43.176 ;
    END
  END dst_d[202]
  PIN dst_d[203]
    DIRECTION OUTPUT ;
    USE SIGNAL ;
    PORT
      LAYER M4 ;
        RECT  25.836 43.392 25.92 43.416 ;
    END
  END dst_d[203]
  PIN dst_d[204]
    DIRECTION OUTPUT ;
    USE SIGNAL ;
    PORT
      LAYER M4 ;
        RECT  25.836 43.584 25.92 43.608 ;
    END
  END dst_d[204]
  PIN dst_d[205]
    DIRECTION OUTPUT ;
    USE SIGNAL ;
    PORT
      LAYER M4 ;
        RECT  25.836 43.776 25.92 43.8 ;
    END
  END dst_d[205]
  PIN dst_d[206]
    DIRECTION OUTPUT ;
    USE SIGNAL ;
    PORT
      LAYER M4 ;
        RECT  25.836 43.968 25.92 43.992 ;
    END
  END dst_d[206]
  PIN dst_d[207]
    DIRECTION OUTPUT ;
    USE SIGNAL ;
    PORT
      LAYER M4 ;
        RECT  25.836 44.16 25.92 44.184 ;
    END
  END dst_d[207]
  PIN dst_d[208]
    DIRECTION OUTPUT ;
    USE SIGNAL ;
    PORT
      LAYER M4 ;
        RECT  25.836 44.4 25.92 44.424 ;
    END
  END dst_d[208]
  PIN dst_d[209]
    DIRECTION OUTPUT ;
    USE SIGNAL ;
    PORT
      LAYER M4 ;
        RECT  25.836 44.592 25.92 44.616 ;
    END
  END dst_d[209]
  PIN dst_d[20]
    DIRECTION OUTPUT ;
    USE SIGNAL ;
    PORT
      LAYER M4 ;
        RECT  25.836 6.624 25.92 6.648 ;
    END
  END dst_d[20]
  PIN dst_d[210]
    DIRECTION OUTPUT ;
    USE SIGNAL ;
    PORT
      LAYER M4 ;
        RECT  25.836 44.784 25.92 44.808 ;
    END
  END dst_d[210]
  PIN dst_d[211]
    DIRECTION OUTPUT ;
    USE SIGNAL ;
    PORT
      LAYER M4 ;
        RECT  25.836 44.976 25.92 45 ;
    END
  END dst_d[211]
  PIN dst_d[212]
    DIRECTION OUTPUT ;
    USE SIGNAL ;
    PORT
      LAYER M4 ;
        RECT  25.836 45.168 25.92 45.192 ;
    END
  END dst_d[212]
  PIN dst_d[213]
    DIRECTION OUTPUT ;
    USE SIGNAL ;
    PORT
      LAYER M4 ;
        RECT  25.836 45.408 25.92 45.432 ;
    END
  END dst_d[213]
  PIN dst_d[214]
    DIRECTION OUTPUT ;
    USE SIGNAL ;
    PORT
      LAYER M4 ;
        RECT  25.836 45.6 25.92 45.624 ;
    END
  END dst_d[214]
  PIN dst_d[215]
    DIRECTION OUTPUT ;
    USE SIGNAL ;
    PORT
      LAYER M4 ;
        RECT  25.836 45.792 25.92 45.816 ;
    END
  END dst_d[215]
  PIN dst_d[216]
    DIRECTION OUTPUT ;
    USE SIGNAL ;
    PORT
      LAYER M4 ;
        RECT  25.836 45.984 25.92 46.008 ;
    END
  END dst_d[216]
  PIN dst_d[217]
    DIRECTION OUTPUT ;
    USE SIGNAL ;
    PORT
      LAYER M4 ;
        RECT  25.836 46.176 25.92 46.2 ;
    END
  END dst_d[217]
  PIN dst_d[218]
    DIRECTION OUTPUT ;
    USE SIGNAL ;
    PORT
      LAYER M4 ;
        RECT  25.836 46.368 25.92 46.392 ;
    END
  END dst_d[218]
  PIN dst_d[219]
    DIRECTION OUTPUT ;
    USE SIGNAL ;
    PORT
      LAYER M4 ;
        RECT  25.836 46.608 25.92 46.632 ;
    END
  END dst_d[219]
  PIN dst_d[21]
    DIRECTION OUTPUT ;
    USE SIGNAL ;
    PORT
      LAYER M4 ;
        RECT  25.836 6.816 25.92 6.84 ;
    END
  END dst_d[21]
  PIN dst_d[220]
    DIRECTION OUTPUT ;
    USE SIGNAL ;
    PORT
      LAYER M4 ;
        RECT  25.836 46.8 25.92 46.824 ;
    END
  END dst_d[220]
  PIN dst_d[221]
    DIRECTION OUTPUT ;
    USE SIGNAL ;
    PORT
      LAYER M4 ;
        RECT  25.836 46.992 25.92 47.016 ;
    END
  END dst_d[221]
  PIN dst_d[222]
    DIRECTION OUTPUT ;
    USE SIGNAL ;
    PORT
      LAYER M4 ;
        RECT  25.836 47.184 25.92 47.208 ;
    END
  END dst_d[222]
  PIN dst_d[223]
    DIRECTION OUTPUT ;
    USE SIGNAL ;
    PORT
      LAYER M4 ;
        RECT  25.836 47.376 25.92 47.4 ;
    END
  END dst_d[223]
  PIN dst_d[224]
    DIRECTION OUTPUT ;
    USE SIGNAL ;
    PORT
      LAYER M4 ;
        RECT  25.836 47.616 25.92 47.64 ;
    END
  END dst_d[224]
  PIN dst_d[225]
    DIRECTION OUTPUT ;
    USE SIGNAL ;
    PORT
      LAYER M4 ;
        RECT  25.836 47.808 25.92 47.832 ;
    END
  END dst_d[225]
  PIN dst_d[226]
    DIRECTION OUTPUT ;
    USE SIGNAL ;
    PORT
      LAYER M4 ;
        RECT  25.836 48 25.92 48.024 ;
    END
  END dst_d[226]
  PIN dst_d[227]
    DIRECTION OUTPUT ;
    USE SIGNAL ;
    PORT
      LAYER M4 ;
        RECT  25.836 48.192 25.92 48.216 ;
    END
  END dst_d[227]
  PIN dst_d[228]
    DIRECTION OUTPUT ;
    USE SIGNAL ;
    PORT
      LAYER M4 ;
        RECT  25.836 48.384 25.92 48.408 ;
    END
  END dst_d[228]
  PIN dst_d[229]
    DIRECTION OUTPUT ;
    USE SIGNAL ;
    PORT
      LAYER M4 ;
        RECT  25.836 48.576 25.92 48.6 ;
    END
  END dst_d[229]
  PIN dst_d[22]
    DIRECTION OUTPUT ;
    USE SIGNAL ;
    PORT
      LAYER M4 ;
        RECT  25.836 7.008 25.92 7.032 ;
    END
  END dst_d[22]
  PIN dst_d[230]
    DIRECTION OUTPUT ;
    USE SIGNAL ;
    PORT
      LAYER M4 ;
        RECT  25.836 48.816 25.92 48.84 ;
    END
  END dst_d[230]
  PIN dst_d[231]
    DIRECTION OUTPUT ;
    USE SIGNAL ;
    PORT
      LAYER M4 ;
        RECT  25.836 49.008 25.92 49.032 ;
    END
  END dst_d[231]
  PIN dst_d[232]
    DIRECTION OUTPUT ;
    USE SIGNAL ;
    PORT
      LAYER M4 ;
        RECT  25.836 49.2 25.92 49.224 ;
    END
  END dst_d[232]
  PIN dst_d[233]
    DIRECTION OUTPUT ;
    USE SIGNAL ;
    PORT
      LAYER M4 ;
        RECT  25.836 49.392 25.92 49.416 ;
    END
  END dst_d[233]
  PIN dst_d[234]
    DIRECTION OUTPUT ;
    USE SIGNAL ;
    PORT
      LAYER M4 ;
        RECT  25.836 49.584 25.92 49.608 ;
    END
  END dst_d[234]
  PIN dst_d[235]
    DIRECTION OUTPUT ;
    USE SIGNAL ;
    PORT
      LAYER M4 ;
        RECT  25.836 49.824 25.92 49.848 ;
    END
  END dst_d[235]
  PIN dst_d[236]
    DIRECTION OUTPUT ;
    USE SIGNAL ;
    PORT
      LAYER M4 ;
        RECT  25.836 50.016 25.92 50.04 ;
    END
  END dst_d[236]
  PIN dst_d[237]
    DIRECTION OUTPUT ;
    USE SIGNAL ;
    PORT
      LAYER M4 ;
        RECT  25.836 50.208 25.92 50.232 ;
    END
  END dst_d[237]
  PIN dst_d[238]
    DIRECTION OUTPUT ;
    USE SIGNAL ;
    PORT
      LAYER M4 ;
        RECT  25.836 50.4 25.92 50.424 ;
    END
  END dst_d[238]
  PIN dst_d[239]
    DIRECTION OUTPUT ;
    USE SIGNAL ;
    PORT
      LAYER M4 ;
        RECT  25.836 50.592 25.92 50.616 ;
    END
  END dst_d[239]
  PIN dst_d[23]
    DIRECTION OUTPUT ;
    USE SIGNAL ;
    PORT
      LAYER M4 ;
        RECT  25.836 7.2 25.92 7.224 ;
    END
  END dst_d[23]
  PIN dst_d[240]
    DIRECTION OUTPUT ;
    USE SIGNAL ;
    PORT
      LAYER M4 ;
        RECT  25.836 50.832 25.92 50.856 ;
    END
  END dst_d[240]
  PIN dst_d[241]
    DIRECTION OUTPUT ;
    USE SIGNAL ;
    PORT
      LAYER M4 ;
        RECT  25.836 51.024 25.92 51.048 ;
    END
  END dst_d[241]
  PIN dst_d[242]
    DIRECTION OUTPUT ;
    USE SIGNAL ;
    PORT
      LAYER M4 ;
        RECT  25.836 51.216 25.92 51.24 ;
    END
  END dst_d[242]
  PIN dst_d[243]
    DIRECTION OUTPUT ;
    USE SIGNAL ;
    PORT
      LAYER M4 ;
        RECT  25.836 51.408 25.92 51.432 ;
    END
  END dst_d[243]
  PIN dst_d[244]
    DIRECTION OUTPUT ;
    USE SIGNAL ;
    PORT
      LAYER M4 ;
        RECT  25.836 51.6 25.92 51.624 ;
    END
  END dst_d[244]
  PIN dst_d[245]
    DIRECTION OUTPUT ;
    USE SIGNAL ;
    PORT
      LAYER M4 ;
        RECT  25.836 51.792 25.92 51.816 ;
    END
  END dst_d[245]
  PIN dst_d[246]
    DIRECTION OUTPUT ;
    USE SIGNAL ;
    PORT
      LAYER M4 ;
        RECT  25.836 52.032 25.92 52.056 ;
    END
  END dst_d[246]
  PIN dst_d[247]
    DIRECTION OUTPUT ;
    USE SIGNAL ;
    PORT
      LAYER M4 ;
        RECT  25.836 52.224 25.92 52.248 ;
    END
  END dst_d[247]
  PIN dst_d[248]
    DIRECTION OUTPUT ;
    USE SIGNAL ;
    PORT
      LAYER M4 ;
        RECT  25.836 52.416 25.92 52.44 ;
    END
  END dst_d[248]
  PIN dst_d[249]
    DIRECTION OUTPUT ;
    USE SIGNAL ;
    PORT
      LAYER M4 ;
        RECT  25.836 52.608 25.92 52.632 ;
    END
  END dst_d[249]
  PIN dst_d[24]
    DIRECTION OUTPUT ;
    USE SIGNAL ;
    PORT
      LAYER M4 ;
        RECT  25.836 7.392 25.92 7.416 ;
    END
  END dst_d[24]
  PIN dst_d[250]
    DIRECTION OUTPUT ;
    USE SIGNAL ;
    PORT
      LAYER M4 ;
        RECT  25.836 52.8 25.92 52.824 ;
    END
  END dst_d[250]
  PIN dst_d[251]
    DIRECTION OUTPUT ;
    USE SIGNAL ;
    PORT
      LAYER M4 ;
        RECT  25.836 53.04 25.92 53.064 ;
    END
  END dst_d[251]
  PIN dst_d[252]
    DIRECTION OUTPUT ;
    USE SIGNAL ;
    PORT
      LAYER M4 ;
        RECT  25.836 53.232 25.92 53.256 ;
    END
  END dst_d[252]
  PIN dst_d[253]
    DIRECTION OUTPUT ;
    USE SIGNAL ;
    PORT
      LAYER M4 ;
        RECT  25.836 53.424 25.92 53.448 ;
    END
  END dst_d[253]
  PIN dst_d[254]
    DIRECTION OUTPUT ;
    USE SIGNAL ;
    PORT
      LAYER M4 ;
        RECT  25.836 53.616 25.92 53.64 ;
    END
  END dst_d[254]
  PIN dst_d[255]
    DIRECTION OUTPUT ;
    USE SIGNAL ;
    PORT
      LAYER M4 ;
        RECT  25.836 53.808 25.92 53.832 ;
    END
  END dst_d[255]
  PIN dst_d[256]
    DIRECTION OUTPUT ;
    USE SIGNAL ;
    PORT
      LAYER M4 ;
        RECT  25.836 54 25.92 54.024 ;
    END
  END dst_d[256]
  PIN dst_d[257]
    DIRECTION OUTPUT ;
    USE SIGNAL ;
    PORT
      LAYER M4 ;
        RECT  25.836 54.24 25.92 54.264 ;
    END
  END dst_d[257]
  PIN dst_d[258]
    DIRECTION OUTPUT ;
    USE SIGNAL ;
    PORT
      LAYER M4 ;
        RECT  25.836 54.432 25.92 54.456 ;
    END
  END dst_d[258]
  PIN dst_d[259]
    DIRECTION OUTPUT ;
    USE SIGNAL ;
    PORT
      LAYER M4 ;
        RECT  25.836 54.624 25.92 54.648 ;
    END
  END dst_d[259]
  PIN dst_d[25]
    DIRECTION OUTPUT ;
    USE SIGNAL ;
    PORT
      LAYER M4 ;
        RECT  25.836 7.632 25.92 7.656 ;
    END
  END dst_d[25]
  PIN dst_d[260]
    DIRECTION OUTPUT ;
    USE SIGNAL ;
    PORT
      LAYER M4 ;
        RECT  25.836 54.816 25.92 54.84 ;
    END
  END dst_d[260]
  PIN dst_d[261]
    DIRECTION OUTPUT ;
    USE SIGNAL ;
    PORT
      LAYER M4 ;
        RECT  25.836 55.008 25.92 55.032 ;
    END
  END dst_d[261]
  PIN dst_d[262]
    DIRECTION OUTPUT ;
    USE SIGNAL ;
    PORT
      LAYER M4 ;
        RECT  25.836 55.248 25.92 55.272 ;
    END
  END dst_d[262]
  PIN dst_d[263]
    DIRECTION OUTPUT ;
    USE SIGNAL ;
    PORT
      LAYER M4 ;
        RECT  25.836 55.44 25.92 55.464 ;
    END
  END dst_d[263]
  PIN dst_d[264]
    DIRECTION OUTPUT ;
    USE SIGNAL ;
    PORT
      LAYER M4 ;
        RECT  25.836 55.632 25.92 55.656 ;
    END
  END dst_d[264]
  PIN dst_d[265]
    DIRECTION OUTPUT ;
    USE SIGNAL ;
    PORT
      LAYER M4 ;
        RECT  25.836 55.824 25.92 55.848 ;
    END
  END dst_d[265]
  PIN dst_d[266]
    DIRECTION OUTPUT ;
    USE SIGNAL ;
    PORT
      LAYER M4 ;
        RECT  25.836 56.016 25.92 56.04 ;
    END
  END dst_d[266]
  PIN dst_d[267]
    DIRECTION OUTPUT ;
    USE SIGNAL ;
    PORT
      LAYER M4 ;
        RECT  25.836 56.256 25.92 56.28 ;
    END
  END dst_d[267]
  PIN dst_d[268]
    DIRECTION OUTPUT ;
    USE SIGNAL ;
    PORT
      LAYER M4 ;
        RECT  25.836 56.448 25.92 56.472 ;
    END
  END dst_d[268]
  PIN dst_d[269]
    DIRECTION OUTPUT ;
    USE SIGNAL ;
    PORT
      LAYER M4 ;
        RECT  25.836 56.64 25.92 56.664 ;
    END
  END dst_d[269]
  PIN dst_d[26]
    DIRECTION OUTPUT ;
    USE SIGNAL ;
    PORT
      LAYER M4 ;
        RECT  25.836 7.824 25.92 7.848 ;
    END
  END dst_d[26]
  PIN dst_d[270]
    DIRECTION OUTPUT ;
    USE SIGNAL ;
    PORT
      LAYER M4 ;
        RECT  25.836 56.832 25.92 56.856 ;
    END
  END dst_d[270]
  PIN dst_d[271]
    DIRECTION OUTPUT ;
    USE SIGNAL ;
    PORT
      LAYER M4 ;
        RECT  25.836 57.024 25.92 57.048 ;
    END
  END dst_d[271]
  PIN dst_d[272]
    DIRECTION OUTPUT ;
    USE SIGNAL ;
    PORT
      LAYER M4 ;
        RECT  25.836 57.216 25.92 57.24 ;
    END
  END dst_d[272]
  PIN dst_d[273]
    DIRECTION OUTPUT ;
    USE SIGNAL ;
    PORT
      LAYER M4 ;
        RECT  25.836 57.456 25.92 57.48 ;
    END
  END dst_d[273]
  PIN dst_d[274]
    DIRECTION OUTPUT ;
    USE SIGNAL ;
    PORT
      LAYER M4 ;
        RECT  25.836 57.648 25.92 57.672 ;
    END
  END dst_d[274]
  PIN dst_d[275]
    DIRECTION OUTPUT ;
    USE SIGNAL ;
    PORT
      LAYER M4 ;
        RECT  25.836 57.84 25.92 57.864 ;
    END
  END dst_d[275]
  PIN dst_d[276]
    DIRECTION OUTPUT ;
    USE SIGNAL ;
    PORT
      LAYER M4 ;
        RECT  25.836 58.032 25.92 58.056 ;
    END
  END dst_d[276]
  PIN dst_d[277]
    DIRECTION OUTPUT ;
    USE SIGNAL ;
    PORT
      LAYER M4 ;
        RECT  25.836 58.224 25.92 58.248 ;
    END
  END dst_d[277]
  PIN dst_d[278]
    DIRECTION OUTPUT ;
    USE SIGNAL ;
    PORT
      LAYER M4 ;
        RECT  25.836 58.464 25.92 58.488 ;
    END
  END dst_d[278]
  PIN dst_d[279]
    DIRECTION OUTPUT ;
    USE SIGNAL ;
    PORT
      LAYER M4 ;
        RECT  25.836 58.656 25.92 58.68 ;
    END
  END dst_d[279]
  PIN dst_d[27]
    DIRECTION OUTPUT ;
    USE SIGNAL ;
    PORT
      LAYER M4 ;
        RECT  25.836 8.016 25.92 8.04 ;
    END
  END dst_d[27]
  PIN dst_d[280]
    DIRECTION OUTPUT ;
    USE SIGNAL ;
    PORT
      LAYER M4 ;
        RECT  25.836 58.848 25.92 58.872 ;
    END
  END dst_d[280]
  PIN dst_d[281]
    DIRECTION OUTPUT ;
    USE SIGNAL ;
    PORT
      LAYER M4 ;
        RECT  25.836 59.04 25.92 59.064 ;
    END
  END dst_d[281]
  PIN dst_d[282]
    DIRECTION OUTPUT ;
    USE SIGNAL ;
    PORT
      LAYER M4 ;
        RECT  25.836 59.232 25.92 59.256 ;
    END
  END dst_d[282]
  PIN dst_d[283]
    DIRECTION OUTPUT ;
    USE SIGNAL ;
    PORT
      LAYER M4 ;
        RECT  25.836 59.472 25.92 59.496 ;
    END
  END dst_d[283]
  PIN dst_d[284]
    DIRECTION OUTPUT ;
    USE SIGNAL ;
    PORT
      LAYER M4 ;
        RECT  25.836 59.664 25.92 59.688 ;
    END
  END dst_d[284]
  PIN dst_d[285]
    DIRECTION OUTPUT ;
    USE SIGNAL ;
    PORT
      LAYER M4 ;
        RECT  25.836 59.856 25.92 59.88 ;
    END
  END dst_d[285]
  PIN dst_d[286]
    DIRECTION OUTPUT ;
    USE SIGNAL ;
    PORT
      LAYER M4 ;
        RECT  25.836 60.048 25.92 60.072 ;
    END
  END dst_d[286]
  PIN dst_d[287]
    DIRECTION OUTPUT ;
    USE SIGNAL ;
    PORT
      LAYER M4 ;
        RECT  25.836 60.24 25.92 60.264 ;
    END
  END dst_d[287]
  PIN dst_d[288]
    DIRECTION OUTPUT ;
    USE SIGNAL ;
    PORT
      LAYER M4 ;
        RECT  25.836 60.432 25.92 60.456 ;
    END
  END dst_d[288]
  PIN dst_d[289]
    DIRECTION OUTPUT ;
    USE SIGNAL ;
    PORT
      LAYER M4 ;
        RECT  25.836 60.672 25.92 60.696 ;
    END
  END dst_d[289]
  PIN dst_d[28]
    DIRECTION OUTPUT ;
    USE SIGNAL ;
    PORT
      LAYER M4 ;
        RECT  25.836 8.208 25.92 8.232 ;
    END
  END dst_d[28]
  PIN dst_d[290]
    DIRECTION OUTPUT ;
    USE SIGNAL ;
    PORT
      LAYER M4 ;
        RECT  25.836 60.864 25.92 60.888 ;
    END
  END dst_d[290]
  PIN dst_d[291]
    DIRECTION OUTPUT ;
    USE SIGNAL ;
    PORT
      LAYER M4 ;
        RECT  25.836 61.056 25.92 61.08 ;
    END
  END dst_d[291]
  PIN dst_d[292]
    DIRECTION OUTPUT ;
    USE SIGNAL ;
    PORT
      LAYER M4 ;
        RECT  25.836 61.248 25.92 61.272 ;
    END
  END dst_d[292]
  PIN dst_d[293]
    DIRECTION OUTPUT ;
    USE SIGNAL ;
    PORT
      LAYER M4 ;
        RECT  25.836 61.44 25.92 61.464 ;
    END
  END dst_d[293]
  PIN dst_d[294]
    DIRECTION OUTPUT ;
    USE SIGNAL ;
    PORT
      LAYER M4 ;
        RECT  25.836 61.68 25.92 61.704 ;
    END
  END dst_d[294]
  PIN dst_d[295]
    DIRECTION OUTPUT ;
    USE SIGNAL ;
    PORT
      LAYER M4 ;
        RECT  25.836 61.872 25.92 61.896 ;
    END
  END dst_d[295]
  PIN dst_d[296]
    DIRECTION OUTPUT ;
    USE SIGNAL ;
    PORT
      LAYER M4 ;
        RECT  25.836 62.064 25.92 62.088 ;
    END
  END dst_d[296]
  PIN dst_d[297]
    DIRECTION OUTPUT ;
    USE SIGNAL ;
    PORT
      LAYER M4 ;
        RECT  25.836 62.256 25.92 62.28 ;
    END
  END dst_d[297]
  PIN dst_d[298]
    DIRECTION OUTPUT ;
    USE SIGNAL ;
    PORT
      LAYER M4 ;
        RECT  25.836 62.448 25.92 62.472 ;
    END
  END dst_d[298]
  PIN dst_d[299]
    DIRECTION OUTPUT ;
    USE SIGNAL ;
    PORT
      LAYER M4 ;
        RECT  25.836 62.64 25.92 62.664 ;
    END
  END dst_d[299]
  PIN dst_d[29]
    DIRECTION OUTPUT ;
    USE SIGNAL ;
    PORT
      LAYER M4 ;
        RECT  25.836 8.4 25.92 8.424 ;
    END
  END dst_d[29]
  PIN dst_d[2]
    DIRECTION OUTPUT ;
    USE SIGNAL ;
    PORT
      LAYER M4 ;
        RECT  25.836 2.976 25.92 3 ;
    END
  END dst_d[2]
  PIN dst_d[300]
    DIRECTION OUTPUT ;
    USE SIGNAL ;
    PORT
      LAYER M4 ;
        RECT  25.836 62.88 25.92 62.904 ;
    END
  END dst_d[300]
  PIN dst_d[301]
    DIRECTION OUTPUT ;
    USE SIGNAL ;
    PORT
      LAYER M4 ;
        RECT  25.836 63.072 25.92 63.096 ;
    END
  END dst_d[301]
  PIN dst_d[302]
    DIRECTION OUTPUT ;
    USE SIGNAL ;
    PORT
      LAYER M4 ;
        RECT  25.836 63.264 25.92 63.288 ;
    END
  END dst_d[302]
  PIN dst_d[303]
    DIRECTION OUTPUT ;
    USE SIGNAL ;
    PORT
      LAYER M4 ;
        RECT  25.836 63.456 25.92 63.48 ;
    END
  END dst_d[303]
  PIN dst_d[304]
    DIRECTION OUTPUT ;
    USE SIGNAL ;
    PORT
      LAYER M4 ;
        RECT  25.836 63.648 25.92 63.672 ;
    END
  END dst_d[304]
  PIN dst_d[305]
    DIRECTION OUTPUT ;
    USE SIGNAL ;
    PORT
      LAYER M4 ;
        RECT  25.836 63.888 25.92 63.912 ;
    END
  END dst_d[305]
  PIN dst_d[306]
    DIRECTION OUTPUT ;
    USE SIGNAL ;
    PORT
      LAYER M4 ;
        RECT  25.836 64.08 25.92 64.104 ;
    END
  END dst_d[306]
  PIN dst_d[307]
    DIRECTION OUTPUT ;
    USE SIGNAL ;
    PORT
      LAYER M4 ;
        RECT  25.836 64.272 25.92 64.296 ;
    END
  END dst_d[307]
  PIN dst_d[308]
    DIRECTION OUTPUT ;
    USE SIGNAL ;
    PORT
      LAYER M4 ;
        RECT  25.836 64.464 25.92 64.488 ;
    END
  END dst_d[308]
  PIN dst_d[309]
    DIRECTION OUTPUT ;
    USE SIGNAL ;
    PORT
      LAYER M4 ;
        RECT  25.836 64.656 25.92 64.68 ;
    END
  END dst_d[309]
  PIN dst_d[30]
    DIRECTION OUTPUT ;
    USE SIGNAL ;
    PORT
      LAYER M4 ;
        RECT  25.836 8.64 25.92 8.664 ;
    END
  END dst_d[30]
  PIN dst_d[310]
    DIRECTION OUTPUT ;
    USE SIGNAL ;
    PORT
      LAYER M4 ;
        RECT  25.836 64.896 25.92 64.92 ;
    END
  END dst_d[310]
  PIN dst_d[311]
    DIRECTION OUTPUT ;
    USE SIGNAL ;
    PORT
      LAYER M4 ;
        RECT  25.836 65.088 25.92 65.112 ;
    END
  END dst_d[311]
  PIN dst_d[312]
    DIRECTION OUTPUT ;
    USE SIGNAL ;
    PORT
      LAYER M4 ;
        RECT  25.836 65.28 25.92 65.304 ;
    END
  END dst_d[312]
  PIN dst_d[313]
    DIRECTION OUTPUT ;
    USE SIGNAL ;
    PORT
      LAYER M4 ;
        RECT  25.836 65.472 25.92 65.496 ;
    END
  END dst_d[313]
  PIN dst_d[314]
    DIRECTION OUTPUT ;
    USE SIGNAL ;
    PORT
      LAYER M4 ;
        RECT  25.836 65.664 25.92 65.688 ;
    END
  END dst_d[314]
  PIN dst_d[315]
    DIRECTION OUTPUT ;
    USE SIGNAL ;
    PORT
      LAYER M4 ;
        RECT  25.836 65.856 25.92 65.88 ;
    END
  END dst_d[315]
  PIN dst_d[316]
    DIRECTION OUTPUT ;
    USE SIGNAL ;
    PORT
      LAYER M4 ;
        RECT  25.836 66.096 25.92 66.12 ;
    END
  END dst_d[316]
  PIN dst_d[317]
    DIRECTION OUTPUT ;
    USE SIGNAL ;
    PORT
      LAYER M4 ;
        RECT  25.836 66.288 25.92 66.312 ;
    END
  END dst_d[317]
  PIN dst_d[318]
    DIRECTION OUTPUT ;
    USE SIGNAL ;
    PORT
      LAYER M4 ;
        RECT  25.836 66.48 25.92 66.504 ;
    END
  END dst_d[318]
  PIN dst_d[319]
    DIRECTION OUTPUT ;
    USE SIGNAL ;
    PORT
      LAYER M4 ;
        RECT  25.836 66.672 25.92 66.696 ;
    END
  END dst_d[319]
  PIN dst_d[31]
    DIRECTION OUTPUT ;
    USE SIGNAL ;
    PORT
      LAYER M4 ;
        RECT  25.836 8.832 25.92 8.856 ;
    END
  END dst_d[31]
  PIN dst_d[320]
    DIRECTION OUTPUT ;
    USE SIGNAL ;
    PORT
      LAYER M4 ;
        RECT  25.836 66.864 25.92 66.888 ;
    END
  END dst_d[320]
  PIN dst_d[321]
    DIRECTION OUTPUT ;
    USE SIGNAL ;
    PORT
      LAYER M4 ;
        RECT  25.836 67.104 25.92 67.128 ;
    END
  END dst_d[321]
  PIN dst_d[322]
    DIRECTION OUTPUT ;
    USE SIGNAL ;
    PORT
      LAYER M4 ;
        RECT  25.836 67.296 25.92 67.32 ;
    END
  END dst_d[322]
  PIN dst_d[323]
    DIRECTION OUTPUT ;
    USE SIGNAL ;
    PORT
      LAYER M4 ;
        RECT  25.836 67.488 25.92 67.512 ;
    END
  END dst_d[323]
  PIN dst_d[324]
    DIRECTION OUTPUT ;
    USE SIGNAL ;
    PORT
      LAYER M4 ;
        RECT  25.836 67.68 25.92 67.704 ;
    END
  END dst_d[324]
  PIN dst_d[325]
    DIRECTION OUTPUT ;
    USE SIGNAL ;
    PORT
      LAYER M4 ;
        RECT  25.836 67.872 25.92 67.896 ;
    END
  END dst_d[325]
  PIN dst_d[326]
    DIRECTION OUTPUT ;
    USE SIGNAL ;
    PORT
      LAYER M4 ;
        RECT  25.836 68.064 25.92 68.088 ;
    END
  END dst_d[326]
  PIN dst_d[327]
    DIRECTION OUTPUT ;
    USE SIGNAL ;
    PORT
      LAYER M4 ;
        RECT  25.836 68.304 25.92 68.328 ;
    END
  END dst_d[327]
  PIN dst_d[328]
    DIRECTION OUTPUT ;
    USE SIGNAL ;
    PORT
      LAYER M4 ;
        RECT  25.836 68.496 25.92 68.52 ;
    END
  END dst_d[328]
  PIN dst_d[329]
    DIRECTION OUTPUT ;
    USE SIGNAL ;
    PORT
      LAYER M4 ;
        RECT  25.836 68.688 25.92 68.712 ;
    END
  END dst_d[329]
  PIN dst_d[32]
    DIRECTION OUTPUT ;
    USE SIGNAL ;
    PORT
      LAYER M4 ;
        RECT  25.836 9.024 25.92 9.048 ;
    END
  END dst_d[32]
  PIN dst_d[330]
    DIRECTION OUTPUT ;
    USE SIGNAL ;
    PORT
      LAYER M4 ;
        RECT  25.836 68.88 25.92 68.904 ;
    END
  END dst_d[330]
  PIN dst_d[331]
    DIRECTION OUTPUT ;
    USE SIGNAL ;
    PORT
      LAYER M4 ;
        RECT  25.836 69.072 25.92 69.096 ;
    END
  END dst_d[331]
  PIN dst_d[332]
    DIRECTION OUTPUT ;
    USE SIGNAL ;
    PORT
      LAYER M4 ;
        RECT  25.836 69.312 25.92 69.336 ;
    END
  END dst_d[332]
  PIN dst_d[333]
    DIRECTION OUTPUT ;
    USE SIGNAL ;
    PORT
      LAYER M4 ;
        RECT  25.836 69.504 25.92 69.528 ;
    END
  END dst_d[333]
  PIN dst_d[334]
    DIRECTION OUTPUT ;
    USE SIGNAL ;
    PORT
      LAYER M4 ;
        RECT  25.836 69.696 25.92 69.72 ;
    END
  END dst_d[334]
  PIN dst_d[335]
    DIRECTION OUTPUT ;
    USE SIGNAL ;
    PORT
      LAYER M4 ;
        RECT  25.836 69.888 25.92 69.912 ;
    END
  END dst_d[335]
  PIN dst_d[336]
    DIRECTION OUTPUT ;
    USE SIGNAL ;
    PORT
      LAYER M4 ;
        RECT  25.836 70.08 25.92 70.104 ;
    END
  END dst_d[336]
  PIN dst_d[337]
    DIRECTION OUTPUT ;
    USE SIGNAL ;
    PORT
      LAYER M4 ;
        RECT  25.836 70.32 25.92 70.344 ;
    END
  END dst_d[337]
  PIN dst_d[338]
    DIRECTION OUTPUT ;
    USE SIGNAL ;
    PORT
      LAYER M4 ;
        RECT  25.836 70.512 25.92 70.536 ;
    END
  END dst_d[338]
  PIN dst_d[339]
    DIRECTION OUTPUT ;
    USE SIGNAL ;
    PORT
      LAYER M4 ;
        RECT  25.836 70.704 25.92 70.728 ;
    END
  END dst_d[339]
  PIN dst_d[33]
    DIRECTION OUTPUT ;
    USE SIGNAL ;
    PORT
      LAYER M4 ;
        RECT  25.836 9.216 25.92 9.24 ;
    END
  END dst_d[33]
  PIN dst_d[340]
    DIRECTION OUTPUT ;
    USE SIGNAL ;
    PORT
      LAYER M4 ;
        RECT  25.836 70.896 25.92 70.92 ;
    END
  END dst_d[340]
  PIN dst_d[341]
    DIRECTION OUTPUT ;
    USE SIGNAL ;
    PORT
      LAYER M4 ;
        RECT  25.836 71.088 25.92 71.112 ;
    END
  END dst_d[341]
  PIN dst_d[342]
    DIRECTION OUTPUT ;
    USE SIGNAL ;
    PORT
      LAYER M4 ;
        RECT  25.836 71.28 25.92 71.304 ;
    END
  END dst_d[342]
  PIN dst_d[343]
    DIRECTION OUTPUT ;
    USE SIGNAL ;
    PORT
      LAYER M4 ;
        RECT  25.836 71.52 25.92 71.544 ;
    END
  END dst_d[343]
  PIN dst_d[344]
    DIRECTION OUTPUT ;
    USE SIGNAL ;
    PORT
      LAYER M4 ;
        RECT  25.836 71.712 25.92 71.736 ;
    END
  END dst_d[344]
  PIN dst_d[345]
    DIRECTION OUTPUT ;
    USE SIGNAL ;
    PORT
      LAYER M4 ;
        RECT  25.836 71.904 25.92 71.928 ;
    END
  END dst_d[345]
  PIN dst_d[346]
    DIRECTION OUTPUT ;
    USE SIGNAL ;
    PORT
      LAYER M4 ;
        RECT  25.836 72.096 25.92 72.12 ;
    END
  END dst_d[346]
  PIN dst_d[347]
    DIRECTION OUTPUT ;
    USE SIGNAL ;
    PORT
      LAYER M4 ;
        RECT  25.836 72.288 25.92 72.312 ;
    END
  END dst_d[347]
  PIN dst_d[348]
    DIRECTION OUTPUT ;
    USE SIGNAL ;
    PORT
      LAYER M4 ;
        RECT  25.836 72.528 25.92 72.552 ;
    END
  END dst_d[348]
  PIN dst_d[349]
    DIRECTION OUTPUT ;
    USE SIGNAL ;
    PORT
      LAYER M4 ;
        RECT  25.836 72.72 25.92 72.744 ;
    END
  END dst_d[349]
  PIN dst_d[34]
    DIRECTION OUTPUT ;
    USE SIGNAL ;
    PORT
      LAYER M4 ;
        RECT  25.836 9.408 25.92 9.432 ;
    END
  END dst_d[34]
  PIN dst_d[350]
    DIRECTION OUTPUT ;
    USE SIGNAL ;
    PORT
      LAYER M4 ;
        RECT  25.836 72.912 25.92 72.936 ;
    END
  END dst_d[350]
  PIN dst_d[351]
    DIRECTION OUTPUT ;
    USE SIGNAL ;
    PORT
      LAYER M4 ;
        RECT  25.836 73.104 25.92 73.128 ;
    END
  END dst_d[351]
  PIN dst_d[352]
    DIRECTION OUTPUT ;
    USE SIGNAL ;
    PORT
      LAYER M4 ;
        RECT  25.836 73.296 25.92 73.32 ;
    END
  END dst_d[352]
  PIN dst_d[353]
    DIRECTION OUTPUT ;
    USE SIGNAL ;
    PORT
      LAYER M4 ;
        RECT  25.836 73.536 25.92 73.56 ;
    END
  END dst_d[353]
  PIN dst_d[354]
    DIRECTION OUTPUT ;
    USE SIGNAL ;
    PORT
      LAYER M4 ;
        RECT  25.836 73.728 25.92 73.752 ;
    END
  END dst_d[354]
  PIN dst_d[355]
    DIRECTION OUTPUT ;
    USE SIGNAL ;
    PORT
      LAYER M4 ;
        RECT  25.836 73.92 25.92 73.944 ;
    END
  END dst_d[355]
  PIN dst_d[356]
    DIRECTION OUTPUT ;
    USE SIGNAL ;
    PORT
      LAYER M4 ;
        RECT  25.836 74.112 25.92 74.136 ;
    END
  END dst_d[356]
  PIN dst_d[357]
    DIRECTION OUTPUT ;
    USE SIGNAL ;
    PORT
      LAYER M4 ;
        RECT  25.836 74.304 25.92 74.328 ;
    END
  END dst_d[357]
  PIN dst_d[358]
    DIRECTION OUTPUT ;
    USE SIGNAL ;
    PORT
      LAYER M4 ;
        RECT  25.836 74.496 25.92 74.52 ;
    END
  END dst_d[358]
  PIN dst_d[359]
    DIRECTION OUTPUT ;
    USE SIGNAL ;
    PORT
      LAYER M4 ;
        RECT  25.836 74.736 25.92 74.76 ;
    END
  END dst_d[359]
  PIN dst_d[35]
    DIRECTION OUTPUT ;
    USE SIGNAL ;
    PORT
      LAYER M4 ;
        RECT  25.836 9.6 25.92 9.624 ;
    END
  END dst_d[35]
  PIN dst_d[360]
    DIRECTION OUTPUT ;
    USE SIGNAL ;
    PORT
      LAYER M4 ;
        RECT  25.836 74.928 25.92 74.952 ;
    END
  END dst_d[360]
  PIN dst_d[361]
    DIRECTION OUTPUT ;
    USE SIGNAL ;
    PORT
      LAYER M4 ;
        RECT  25.836 75.12 25.92 75.144 ;
    END
  END dst_d[361]
  PIN dst_d[362]
    DIRECTION OUTPUT ;
    USE SIGNAL ;
    PORT
      LAYER M4 ;
        RECT  25.836 75.312 25.92 75.336 ;
    END
  END dst_d[362]
  PIN dst_d[363]
    DIRECTION OUTPUT ;
    USE SIGNAL ;
    PORT
      LAYER M4 ;
        RECT  25.836 75.504 25.92 75.528 ;
    END
  END dst_d[363]
  PIN dst_d[364]
    DIRECTION OUTPUT ;
    USE SIGNAL ;
    PORT
      LAYER M4 ;
        RECT  25.836 75.744 25.92 75.768 ;
    END
  END dst_d[364]
  PIN dst_d[365]
    DIRECTION OUTPUT ;
    USE SIGNAL ;
    PORT
      LAYER M4 ;
        RECT  25.836 75.936 25.92 75.96 ;
    END
  END dst_d[365]
  PIN dst_d[366]
    DIRECTION OUTPUT ;
    USE SIGNAL ;
    PORT
      LAYER M4 ;
        RECT  25.836 76.128 25.92 76.152 ;
    END
  END dst_d[366]
  PIN dst_d[367]
    DIRECTION OUTPUT ;
    USE SIGNAL ;
    PORT
      LAYER M4 ;
        RECT  25.836 76.32 25.92 76.344 ;
    END
  END dst_d[367]
  PIN dst_d[368]
    DIRECTION OUTPUT ;
    USE SIGNAL ;
    PORT
      LAYER M4 ;
        RECT  25.836 76.512 25.92 76.536 ;
    END
  END dst_d[368]
  PIN dst_d[369]
    DIRECTION OUTPUT ;
    USE SIGNAL ;
    PORT
      LAYER M4 ;
        RECT  25.836 76.704 25.92 76.728 ;
    END
  END dst_d[369]
  PIN dst_d[36]
    DIRECTION OUTPUT ;
    USE SIGNAL ;
    PORT
      LAYER M4 ;
        RECT  25.836 9.84 25.92 9.864 ;
    END
  END dst_d[36]
  PIN dst_d[370]
    DIRECTION OUTPUT ;
    USE SIGNAL ;
    PORT
      LAYER M4 ;
        RECT  25.836 76.944 25.92 76.968 ;
    END
  END dst_d[370]
  PIN dst_d[371]
    DIRECTION OUTPUT ;
    USE SIGNAL ;
    PORT
      LAYER M4 ;
        RECT  25.836 77.136 25.92 77.16 ;
    END
  END dst_d[371]
  PIN dst_d[372]
    DIRECTION OUTPUT ;
    USE SIGNAL ;
    PORT
      LAYER M4 ;
        RECT  25.836 77.328 25.92 77.352 ;
    END
  END dst_d[372]
  PIN dst_d[373]
    DIRECTION OUTPUT ;
    USE SIGNAL ;
    PORT
      LAYER M4 ;
        RECT  25.836 77.52 25.92 77.544 ;
    END
  END dst_d[373]
  PIN dst_d[374]
    DIRECTION OUTPUT ;
    USE SIGNAL ;
    PORT
      LAYER M4 ;
        RECT  25.836 77.712 25.92 77.736 ;
    END
  END dst_d[374]
  PIN dst_d[375]
    DIRECTION OUTPUT ;
    USE SIGNAL ;
    PORT
      LAYER M4 ;
        RECT  25.836 77.952 25.92 77.976 ;
    END
  END dst_d[375]
  PIN dst_d[376]
    DIRECTION OUTPUT ;
    USE SIGNAL ;
    PORT
      LAYER M4 ;
        RECT  25.836 78.144 25.92 78.168 ;
    END
  END dst_d[376]
  PIN dst_d[377]
    DIRECTION OUTPUT ;
    USE SIGNAL ;
    PORT
      LAYER M4 ;
        RECT  25.836 78.336 25.92 78.36 ;
    END
  END dst_d[377]
  PIN dst_d[378]
    DIRECTION OUTPUT ;
    USE SIGNAL ;
    PORT
      LAYER M4 ;
        RECT  25.836 78.528 25.92 78.552 ;
    END
  END dst_d[378]
  PIN dst_d[379]
    DIRECTION OUTPUT ;
    USE SIGNAL ;
    PORT
      LAYER M4 ;
        RECT  25.836 78.72 25.92 78.744 ;
    END
  END dst_d[379]
  PIN dst_d[37]
    DIRECTION OUTPUT ;
    USE SIGNAL ;
    PORT
      LAYER M4 ;
        RECT  25.836 10.032 25.92 10.056 ;
    END
  END dst_d[37]
  PIN dst_d[380]
    DIRECTION OUTPUT ;
    USE SIGNAL ;
    PORT
      LAYER M4 ;
        RECT  25.836 78.96 25.92 78.984 ;
    END
  END dst_d[380]
  PIN dst_d[381]
    DIRECTION OUTPUT ;
    USE SIGNAL ;
    PORT
      LAYER M4 ;
        RECT  25.836 79.152 25.92 79.176 ;
    END
  END dst_d[381]
  PIN dst_d[382]
    DIRECTION OUTPUT ;
    USE SIGNAL ;
    PORT
      LAYER M4 ;
        RECT  25.836 79.344 25.92 79.368 ;
    END
  END dst_d[382]
  PIN dst_d[383]
    DIRECTION OUTPUT ;
    USE SIGNAL ;
    PORT
      LAYER M4 ;
        RECT  25.836 79.536 25.92 79.56 ;
    END
  END dst_d[383]
  PIN dst_d[384]
    DIRECTION OUTPUT ;
    USE SIGNAL ;
    PORT
      LAYER M4 ;
        RECT  25.836 79.728 25.92 79.752 ;
    END
  END dst_d[384]
  PIN dst_d[385]
    DIRECTION OUTPUT ;
    USE SIGNAL ;
    PORT
      LAYER M4 ;
        RECT  25.836 79.92 25.92 79.944 ;
    END
  END dst_d[385]
  PIN dst_d[386]
    DIRECTION OUTPUT ;
    USE SIGNAL ;
    PORT
      LAYER M4 ;
        RECT  25.836 80.16 25.92 80.184 ;
    END
  END dst_d[386]
  PIN dst_d[387]
    DIRECTION OUTPUT ;
    USE SIGNAL ;
    PORT
      LAYER M4 ;
        RECT  25.836 80.352 25.92 80.376 ;
    END
  END dst_d[387]
  PIN dst_d[388]
    DIRECTION OUTPUT ;
    USE SIGNAL ;
    PORT
      LAYER M4 ;
        RECT  25.836 80.544 25.92 80.568 ;
    END
  END dst_d[388]
  PIN dst_d[389]
    DIRECTION OUTPUT ;
    USE SIGNAL ;
    PORT
      LAYER M4 ;
        RECT  25.836 80.736 25.92 80.76 ;
    END
  END dst_d[389]
  PIN dst_d[38]
    DIRECTION OUTPUT ;
    USE SIGNAL ;
    PORT
      LAYER M4 ;
        RECT  25.836 10.224 25.92 10.248 ;
    END
  END dst_d[38]
  PIN dst_d[390]
    DIRECTION OUTPUT ;
    USE SIGNAL ;
    PORT
      LAYER M4 ;
        RECT  25.836 80.928 25.92 80.952 ;
    END
  END dst_d[390]
  PIN dst_d[391]
    DIRECTION OUTPUT ;
    USE SIGNAL ;
    PORT
      LAYER M4 ;
        RECT  25.836 81.168 25.92 81.192 ;
    END
  END dst_d[391]
  PIN dst_d[392]
    DIRECTION OUTPUT ;
    USE SIGNAL ;
    PORT
      LAYER M4 ;
        RECT  25.836 81.36 25.92 81.384 ;
    END
  END dst_d[392]
  PIN dst_d[393]
    DIRECTION OUTPUT ;
    USE SIGNAL ;
    PORT
      LAYER M4 ;
        RECT  25.836 81.552 25.92 81.576 ;
    END
  END dst_d[393]
  PIN dst_d[394]
    DIRECTION OUTPUT ;
    USE SIGNAL ;
    PORT
      LAYER M4 ;
        RECT  25.836 81.744 25.92 81.768 ;
    END
  END dst_d[394]
  PIN dst_d[395]
    DIRECTION OUTPUT ;
    USE SIGNAL ;
    PORT
      LAYER M4 ;
        RECT  25.836 81.936 25.92 81.96 ;
    END
  END dst_d[395]
  PIN dst_d[396]
    DIRECTION OUTPUT ;
    USE SIGNAL ;
    PORT
      LAYER M4 ;
        RECT  25.836 82.128 25.92 82.152 ;
    END
  END dst_d[396]
  PIN dst_d[397]
    DIRECTION OUTPUT ;
    USE SIGNAL ;
    PORT
      LAYER M4 ;
        RECT  25.836 82.368 25.92 82.392 ;
    END
  END dst_d[397]
  PIN dst_d[398]
    DIRECTION OUTPUT ;
    USE SIGNAL ;
    PORT
      LAYER M4 ;
        RECT  25.836 82.56 25.92 82.584 ;
    END
  END dst_d[398]
  PIN dst_d[399]
    DIRECTION OUTPUT ;
    USE SIGNAL ;
    PORT
      LAYER M4 ;
        RECT  25.836 82.752 25.92 82.776 ;
    END
  END dst_d[399]
  PIN dst_d[39]
    DIRECTION OUTPUT ;
    USE SIGNAL ;
    PORT
      LAYER M4 ;
        RECT  25.836 10.416 25.92 10.44 ;
    END
  END dst_d[39]
  PIN dst_d[3]
    DIRECTION OUTPUT ;
    USE SIGNAL ;
    PORT
      LAYER M4 ;
        RECT  25.836 3.168 25.92 3.192 ;
    END
  END dst_d[3]
  PIN dst_d[400]
    DIRECTION OUTPUT ;
    USE SIGNAL ;
    PORT
      LAYER M4 ;
        RECT  25.836 82.944 25.92 82.968 ;
    END
  END dst_d[400]
  PIN dst_d[401]
    DIRECTION OUTPUT ;
    USE SIGNAL ;
    PORT
      LAYER M4 ;
        RECT  25.836 83.136 25.92 83.16 ;
    END
  END dst_d[401]
  PIN dst_d[402]
    DIRECTION OUTPUT ;
    USE SIGNAL ;
    PORT
      LAYER M4 ;
        RECT  25.836 83.376 25.92 83.4 ;
    END
  END dst_d[402]
  PIN dst_d[403]
    DIRECTION OUTPUT ;
    USE SIGNAL ;
    PORT
      LAYER M4 ;
        RECT  25.836 83.568 25.92 83.592 ;
    END
  END dst_d[403]
  PIN dst_d[404]
    DIRECTION OUTPUT ;
    USE SIGNAL ;
    PORT
      LAYER M4 ;
        RECT  25.836 83.76 25.92 83.784 ;
    END
  END dst_d[404]
  PIN dst_d[405]
    DIRECTION OUTPUT ;
    USE SIGNAL ;
    PORT
      LAYER M4 ;
        RECT  25.836 83.952 25.92 83.976 ;
    END
  END dst_d[405]
  PIN dst_d[406]
    DIRECTION OUTPUT ;
    USE SIGNAL ;
    PORT
      LAYER M4 ;
        RECT  25.836 84.144 25.92 84.168 ;
    END
  END dst_d[406]
  PIN dst_d[407]
    DIRECTION OUTPUT ;
    USE SIGNAL ;
    PORT
      LAYER M4 ;
        RECT  25.836 84.384 25.92 84.408 ;
    END
  END dst_d[407]
  PIN dst_d[408]
    DIRECTION OUTPUT ;
    USE SIGNAL ;
    PORT
      LAYER M4 ;
        RECT  25.836 84.576 25.92 84.6 ;
    END
  END dst_d[408]
  PIN dst_d[409]
    DIRECTION OUTPUT ;
    USE SIGNAL ;
    PORT
      LAYER M4 ;
        RECT  25.836 84.768 25.92 84.792 ;
    END
  END dst_d[409]
  PIN dst_d[40]
    DIRECTION OUTPUT ;
    USE SIGNAL ;
    PORT
      LAYER M4 ;
        RECT  25.836 10.608 25.92 10.632 ;
    END
  END dst_d[40]
  PIN dst_d[410]
    DIRECTION OUTPUT ;
    USE SIGNAL ;
    PORT
      LAYER M4 ;
        RECT  25.836 84.96 25.92 84.984 ;
    END
  END dst_d[410]
  PIN dst_d[411]
    DIRECTION OUTPUT ;
    USE SIGNAL ;
    PORT
      LAYER M4 ;
        RECT  25.836 85.152 25.92 85.176 ;
    END
  END dst_d[411]
  PIN dst_d[412]
    DIRECTION OUTPUT ;
    USE SIGNAL ;
    PORT
      LAYER M4 ;
        RECT  25.836 85.344 25.92 85.368 ;
    END
  END dst_d[412]
  PIN dst_d[413]
    DIRECTION OUTPUT ;
    USE SIGNAL ;
    PORT
      LAYER M4 ;
        RECT  25.836 85.584 25.92 85.608 ;
    END
  END dst_d[413]
  PIN dst_d[414]
    DIRECTION OUTPUT ;
    USE SIGNAL ;
    PORT
      LAYER M4 ;
        RECT  25.836 85.776 25.92 85.8 ;
    END
  END dst_d[414]
  PIN dst_d[415]
    DIRECTION OUTPUT ;
    USE SIGNAL ;
    PORT
      LAYER M4 ;
        RECT  25.836 85.968 25.92 85.992 ;
    END
  END dst_d[415]
  PIN dst_d[416]
    DIRECTION OUTPUT ;
    USE SIGNAL ;
    PORT
      LAYER M4 ;
        RECT  25.836 86.16 25.92 86.184 ;
    END
  END dst_d[416]
  PIN dst_d[417]
    DIRECTION OUTPUT ;
    USE SIGNAL ;
    PORT
      LAYER M4 ;
        RECT  25.836 86.352 25.92 86.376 ;
    END
  END dst_d[417]
  PIN dst_d[418]
    DIRECTION OUTPUT ;
    USE SIGNAL ;
    PORT
      LAYER M4 ;
        RECT  25.836 86.592 25.92 86.616 ;
    END
  END dst_d[418]
  PIN dst_d[419]
    DIRECTION OUTPUT ;
    USE SIGNAL ;
    PORT
      LAYER M4 ;
        RECT  25.836 86.784 25.92 86.808 ;
    END
  END dst_d[419]
  PIN dst_d[41]
    DIRECTION OUTPUT ;
    USE SIGNAL ;
    PORT
      LAYER M4 ;
        RECT  25.836 10.848 25.92 10.872 ;
    END
  END dst_d[41]
  PIN dst_d[420]
    DIRECTION OUTPUT ;
    USE SIGNAL ;
    PORT
      LAYER M4 ;
        RECT  25.836 86.976 25.92 87 ;
    END
  END dst_d[420]
  PIN dst_d[421]
    DIRECTION OUTPUT ;
    USE SIGNAL ;
    PORT
      LAYER M4 ;
        RECT  25.836 87.168 25.92 87.192 ;
    END
  END dst_d[421]
  PIN dst_d[422]
    DIRECTION OUTPUT ;
    USE SIGNAL ;
    PORT
      LAYER M4 ;
        RECT  25.836 87.36 25.92 87.384 ;
    END
  END dst_d[422]
  PIN dst_d[423]
    DIRECTION OUTPUT ;
    USE SIGNAL ;
    PORT
      LAYER M4 ;
        RECT  25.836 87.6 25.92 87.624 ;
    END
  END dst_d[423]
  PIN dst_d[424]
    DIRECTION OUTPUT ;
    USE SIGNAL ;
    PORT
      LAYER M4 ;
        RECT  25.836 87.792 25.92 87.816 ;
    END
  END dst_d[424]
  PIN dst_d[425]
    DIRECTION OUTPUT ;
    USE SIGNAL ;
    PORT
      LAYER M4 ;
        RECT  25.836 87.984 25.92 88.008 ;
    END
  END dst_d[425]
  PIN dst_d[426]
    DIRECTION OUTPUT ;
    USE SIGNAL ;
    PORT
      LAYER M4 ;
        RECT  25.836 88.176 25.92 88.2 ;
    END
  END dst_d[426]
  PIN dst_d[427]
    DIRECTION OUTPUT ;
    USE SIGNAL ;
    PORT
      LAYER M4 ;
        RECT  25.836 88.368 25.92 88.392 ;
    END
  END dst_d[427]
  PIN dst_d[428]
    DIRECTION OUTPUT ;
    USE SIGNAL ;
    PORT
      LAYER M4 ;
        RECT  25.836 88.56 25.92 88.584 ;
    END
  END dst_d[428]
  PIN dst_d[429]
    DIRECTION OUTPUT ;
    USE SIGNAL ;
    PORT
      LAYER M4 ;
        RECT  25.836 88.8 25.92 88.824 ;
    END
  END dst_d[429]
  PIN dst_d[42]
    DIRECTION OUTPUT ;
    USE SIGNAL ;
    PORT
      LAYER M4 ;
        RECT  25.836 11.04 25.92 11.064 ;
    END
  END dst_d[42]
  PIN dst_d[430]
    DIRECTION OUTPUT ;
    USE SIGNAL ;
    PORT
      LAYER M4 ;
        RECT  25.836 88.992 25.92 89.016 ;
    END
  END dst_d[430]
  PIN dst_d[431]
    DIRECTION OUTPUT ;
    USE SIGNAL ;
    PORT
      LAYER M4 ;
        RECT  25.836 89.184 25.92 89.208 ;
    END
  END dst_d[431]
  PIN dst_d[432]
    DIRECTION OUTPUT ;
    USE SIGNAL ;
    PORT
      LAYER M4 ;
        RECT  25.836 89.376 25.92 89.4 ;
    END
  END dst_d[432]
  PIN dst_d[433]
    DIRECTION OUTPUT ;
    USE SIGNAL ;
    PORT
      LAYER M4 ;
        RECT  25.836 89.568 25.92 89.592 ;
    END
  END dst_d[433]
  PIN dst_d[434]
    DIRECTION OUTPUT ;
    USE SIGNAL ;
    PORT
      LAYER M4 ;
        RECT  25.836 89.808 25.92 89.832 ;
    END
  END dst_d[434]
  PIN dst_d[435]
    DIRECTION OUTPUT ;
    USE SIGNAL ;
    PORT
      LAYER M4 ;
        RECT  25.836 90 25.92 90.024 ;
    END
  END dst_d[435]
  PIN dst_d[436]
    DIRECTION OUTPUT ;
    USE SIGNAL ;
    PORT
      LAYER M4 ;
        RECT  25.836 90.192 25.92 90.216 ;
    END
  END dst_d[436]
  PIN dst_d[437]
    DIRECTION OUTPUT ;
    USE SIGNAL ;
    PORT
      LAYER M4 ;
        RECT  25.836 90.384 25.92 90.408 ;
    END
  END dst_d[437]
  PIN dst_d[438]
    DIRECTION OUTPUT ;
    USE SIGNAL ;
    PORT
      LAYER M4 ;
        RECT  25.836 90.576 25.92 90.6 ;
    END
  END dst_d[438]
  PIN dst_d[439]
    DIRECTION OUTPUT ;
    USE SIGNAL ;
    PORT
      LAYER M4 ;
        RECT  25.836 90.768 25.92 90.792 ;
    END
  END dst_d[439]
  PIN dst_d[43]
    DIRECTION OUTPUT ;
    USE SIGNAL ;
    PORT
      LAYER M4 ;
        RECT  25.836 11.232 25.92 11.256 ;
    END
  END dst_d[43]
  PIN dst_d[440]
    DIRECTION OUTPUT ;
    USE SIGNAL ;
    PORT
      LAYER M4 ;
        RECT  25.836 91.008 25.92 91.032 ;
    END
  END dst_d[440]
  PIN dst_d[441]
    DIRECTION OUTPUT ;
    USE SIGNAL ;
    PORT
      LAYER M4 ;
        RECT  25.836 91.2 25.92 91.224 ;
    END
  END dst_d[441]
  PIN dst_d[442]
    DIRECTION OUTPUT ;
    USE SIGNAL ;
    PORT
      LAYER M4 ;
        RECT  25.836 91.392 25.92 91.416 ;
    END
  END dst_d[442]
  PIN dst_d[443]
    DIRECTION OUTPUT ;
    USE SIGNAL ;
    PORT
      LAYER M4 ;
        RECT  25.836 91.584 25.92 91.608 ;
    END
  END dst_d[443]
  PIN dst_d[444]
    DIRECTION OUTPUT ;
    USE SIGNAL ;
    PORT
      LAYER M4 ;
        RECT  25.836 91.776 25.92 91.8 ;
    END
  END dst_d[444]
  PIN dst_d[445]
    DIRECTION OUTPUT ;
    USE SIGNAL ;
    PORT
      LAYER M4 ;
        RECT  25.836 92.016 25.92 92.04 ;
    END
  END dst_d[445]
  PIN dst_d[446]
    DIRECTION OUTPUT ;
    USE SIGNAL ;
    PORT
      LAYER M4 ;
        RECT  25.836 92.208 25.92 92.232 ;
    END
  END dst_d[446]
  PIN dst_d[447]
    DIRECTION OUTPUT ;
    USE SIGNAL ;
    PORT
      LAYER M4 ;
        RECT  25.836 92.4 25.92 92.424 ;
    END
  END dst_d[447]
  PIN dst_d[448]
    DIRECTION OUTPUT ;
    USE SIGNAL ;
    PORT
      LAYER M4 ;
        RECT  25.836 92.592 25.92 92.616 ;
    END
  END dst_d[448]
  PIN dst_d[449]
    DIRECTION OUTPUT ;
    USE SIGNAL ;
    PORT
      LAYER M4 ;
        RECT  25.836 92.784 25.92 92.808 ;
    END
  END dst_d[449]
  PIN dst_d[44]
    DIRECTION OUTPUT ;
    USE SIGNAL ;
    PORT
      LAYER M4 ;
        RECT  25.836 11.424 25.92 11.448 ;
    END
  END dst_d[44]
  PIN dst_d[450]
    DIRECTION OUTPUT ;
    USE SIGNAL ;
    PORT
      LAYER M4 ;
        RECT  25.836 93.024 25.92 93.048 ;
    END
  END dst_d[450]
  PIN dst_d[451]
    DIRECTION OUTPUT ;
    USE SIGNAL ;
    PORT
      LAYER M4 ;
        RECT  25.836 93.216 25.92 93.24 ;
    END
  END dst_d[451]
  PIN dst_d[452]
    DIRECTION OUTPUT ;
    USE SIGNAL ;
    PORT
      LAYER M4 ;
        RECT  25.836 93.408 25.92 93.432 ;
    END
  END dst_d[452]
  PIN dst_d[453]
    DIRECTION OUTPUT ;
    USE SIGNAL ;
    PORT
      LAYER M4 ;
        RECT  25.836 93.6 25.92 93.624 ;
    END
  END dst_d[453]
  PIN dst_d[454]
    DIRECTION OUTPUT ;
    USE SIGNAL ;
    PORT
      LAYER M4 ;
        RECT  25.836 93.792 25.92 93.816 ;
    END
  END dst_d[454]
  PIN dst_d[455]
    DIRECTION OUTPUT ;
    USE SIGNAL ;
    PORT
      LAYER M4 ;
        RECT  25.836 93.984 25.92 94.008 ;
    END
  END dst_d[455]
  PIN dst_d[456]
    DIRECTION OUTPUT ;
    USE SIGNAL ;
    PORT
      LAYER M4 ;
        RECT  25.836 94.224 25.92 94.248 ;
    END
  END dst_d[456]
  PIN dst_d[457]
    DIRECTION OUTPUT ;
    USE SIGNAL ;
    PORT
      LAYER M4 ;
        RECT  25.836 94.416 25.92 94.44 ;
    END
  END dst_d[457]
  PIN dst_d[458]
    DIRECTION OUTPUT ;
    USE SIGNAL ;
    PORT
      LAYER M4 ;
        RECT  25.836 94.608 25.92 94.632 ;
    END
  END dst_d[458]
  PIN dst_d[459]
    DIRECTION OUTPUT ;
    USE SIGNAL ;
    PORT
      LAYER M4 ;
        RECT  25.836 94.8 25.92 94.824 ;
    END
  END dst_d[459]
  PIN dst_d[45]
    DIRECTION OUTPUT ;
    USE SIGNAL ;
    PORT
      LAYER M4 ;
        RECT  25.836 11.616 25.92 11.64 ;
    END
  END dst_d[45]
  PIN dst_d[460]
    DIRECTION OUTPUT ;
    USE SIGNAL ;
    PORT
      LAYER M4 ;
        RECT  25.836 94.992 25.92 95.016 ;
    END
  END dst_d[460]
  PIN dst_d[461]
    DIRECTION OUTPUT ;
    USE SIGNAL ;
    PORT
      LAYER M4 ;
        RECT  25.836 95.232 25.92 95.256 ;
    END
  END dst_d[461]
  PIN dst_d[462]
    DIRECTION OUTPUT ;
    USE SIGNAL ;
    PORT
      LAYER M4 ;
        RECT  25.836 95.424 25.92 95.448 ;
    END
  END dst_d[462]
  PIN dst_d[463]
    DIRECTION OUTPUT ;
    USE SIGNAL ;
    PORT
      LAYER M4 ;
        RECT  25.836 95.616 25.92 95.64 ;
    END
  END dst_d[463]
  PIN dst_d[464]
    DIRECTION OUTPUT ;
    USE SIGNAL ;
    PORT
      LAYER M4 ;
        RECT  25.836 95.808 25.92 95.832 ;
    END
  END dst_d[464]
  PIN dst_d[465]
    DIRECTION OUTPUT ;
    USE SIGNAL ;
    PORT
      LAYER M4 ;
        RECT  25.836 96 25.92 96.024 ;
    END
  END dst_d[465]
  PIN dst_d[466]
    DIRECTION OUTPUT ;
    USE SIGNAL ;
    PORT
      LAYER M4 ;
        RECT  25.836 96.24 25.92 96.264 ;
    END
  END dst_d[466]
  PIN dst_d[467]
    DIRECTION OUTPUT ;
    USE SIGNAL ;
    PORT
      LAYER M4 ;
        RECT  25.836 96.432 25.92 96.456 ;
    END
  END dst_d[467]
  PIN dst_d[468]
    DIRECTION OUTPUT ;
    USE SIGNAL ;
    PORT
      LAYER M4 ;
        RECT  25.836 96.624 25.92 96.648 ;
    END
  END dst_d[468]
  PIN dst_d[469]
    DIRECTION OUTPUT ;
    USE SIGNAL ;
    PORT
      LAYER M4 ;
        RECT  25.836 96.816 25.92 96.84 ;
    END
  END dst_d[469]
  PIN dst_d[46]
    DIRECTION OUTPUT ;
    USE SIGNAL ;
    PORT
      LAYER M4 ;
        RECT  25.836 11.808 25.92 11.832 ;
    END
  END dst_d[46]
  PIN dst_d[470]
    DIRECTION OUTPUT ;
    USE SIGNAL ;
    PORT
      LAYER M4 ;
        RECT  25.836 97.008 25.92 97.032 ;
    END
  END dst_d[470]
  PIN dst_d[471]
    DIRECTION OUTPUT ;
    USE SIGNAL ;
    PORT
      LAYER M4 ;
        RECT  25.836 97.2 25.92 97.224 ;
    END
  END dst_d[471]
  PIN dst_d[472]
    DIRECTION OUTPUT ;
    USE SIGNAL ;
    PORT
      LAYER M4 ;
        RECT  25.836 97.44 25.92 97.464 ;
    END
  END dst_d[472]
  PIN dst_d[473]
    DIRECTION OUTPUT ;
    USE SIGNAL ;
    PORT
      LAYER M4 ;
        RECT  25.836 97.632 25.92 97.656 ;
    END
  END dst_d[473]
  PIN dst_d[474]
    DIRECTION OUTPUT ;
    USE SIGNAL ;
    PORT
      LAYER M4 ;
        RECT  25.836 97.824 25.92 97.848 ;
    END
  END dst_d[474]
  PIN dst_d[475]
    DIRECTION OUTPUT ;
    USE SIGNAL ;
    PORT
      LAYER M4 ;
        RECT  25.836 98.016 25.92 98.04 ;
    END
  END dst_d[475]
  PIN dst_d[476]
    DIRECTION OUTPUT ;
    USE SIGNAL ;
    PORT
      LAYER M4 ;
        RECT  25.836 98.208 25.92 98.232 ;
    END
  END dst_d[476]
  PIN dst_d[477]
    DIRECTION OUTPUT ;
    USE SIGNAL ;
    PORT
      LAYER M4 ;
        RECT  25.836 98.448 25.92 98.472 ;
    END
  END dst_d[477]
  PIN dst_d[478]
    DIRECTION OUTPUT ;
    USE SIGNAL ;
    PORT
      LAYER M4 ;
        RECT  25.836 98.64 25.92 98.664 ;
    END
  END dst_d[478]
  PIN dst_d[479]
    DIRECTION OUTPUT ;
    USE SIGNAL ;
    PORT
      LAYER M4 ;
        RECT  25.836 98.832 25.92 98.856 ;
    END
  END dst_d[479]
  PIN dst_d[47]
    DIRECTION OUTPUT ;
    USE SIGNAL ;
    PORT
      LAYER M4 ;
        RECT  25.836 12.048 25.92 12.072 ;
    END
  END dst_d[47]
  PIN dst_d[48]
    DIRECTION OUTPUT ;
    USE SIGNAL ;
    PORT
      LAYER M4 ;
        RECT  25.836 12.24 25.92 12.264 ;
    END
  END dst_d[48]
  PIN dst_d[49]
    DIRECTION OUTPUT ;
    USE SIGNAL ;
    PORT
      LAYER M4 ;
        RECT  25.836 12.432 25.92 12.456 ;
    END
  END dst_d[49]
  PIN dst_d[4]
    DIRECTION OUTPUT ;
    USE SIGNAL ;
    PORT
      LAYER M4 ;
        RECT  25.836 3.408 25.92 3.432 ;
    END
  END dst_d[4]
  PIN dst_d[50]
    DIRECTION OUTPUT ;
    USE SIGNAL ;
    PORT
      LAYER M4 ;
        RECT  25.836 12.624 25.92 12.648 ;
    END
  END dst_d[50]
  PIN dst_d[51]
    DIRECTION OUTPUT ;
    USE SIGNAL ;
    PORT
      LAYER M4 ;
        RECT  25.836 12.816 25.92 12.84 ;
    END
  END dst_d[51]
  PIN dst_d[52]
    DIRECTION OUTPUT ;
    USE SIGNAL ;
    PORT
      LAYER M4 ;
        RECT  25.836 13.056 25.92 13.08 ;
    END
  END dst_d[52]
  PIN dst_d[53]
    DIRECTION OUTPUT ;
    USE SIGNAL ;
    PORT
      LAYER M4 ;
        RECT  25.836 13.248 25.92 13.272 ;
    END
  END dst_d[53]
  PIN dst_d[54]
    DIRECTION OUTPUT ;
    USE SIGNAL ;
    PORT
      LAYER M4 ;
        RECT  25.836 13.44 25.92 13.464 ;
    END
  END dst_d[54]
  PIN dst_d[55]
    DIRECTION OUTPUT ;
    USE SIGNAL ;
    PORT
      LAYER M4 ;
        RECT  25.836 13.632 25.92 13.656 ;
    END
  END dst_d[55]
  PIN dst_d[56]
    DIRECTION OUTPUT ;
    USE SIGNAL ;
    PORT
      LAYER M4 ;
        RECT  25.836 13.824 25.92 13.848 ;
    END
  END dst_d[56]
  PIN dst_d[57]
    DIRECTION OUTPUT ;
    USE SIGNAL ;
    PORT
      LAYER M4 ;
        RECT  25.836 14.064 25.92 14.088 ;
    END
  END dst_d[57]
  PIN dst_d[58]
    DIRECTION OUTPUT ;
    USE SIGNAL ;
    PORT
      LAYER M4 ;
        RECT  25.836 14.256 25.92 14.28 ;
    END
  END dst_d[58]
  PIN dst_d[59]
    DIRECTION OUTPUT ;
    USE SIGNAL ;
    PORT
      LAYER M4 ;
        RECT  25.836 14.448 25.92 14.472 ;
    END
  END dst_d[59]
  PIN dst_d[5]
    DIRECTION OUTPUT ;
    USE SIGNAL ;
    PORT
      LAYER M4 ;
        RECT  25.836 3.6 25.92 3.624 ;
    END
  END dst_d[5]
  PIN dst_d[60]
    DIRECTION OUTPUT ;
    USE SIGNAL ;
    PORT
      LAYER M4 ;
        RECT  25.836 14.64 25.92 14.664 ;
    END
  END dst_d[60]
  PIN dst_d[61]
    DIRECTION OUTPUT ;
    USE SIGNAL ;
    PORT
      LAYER M4 ;
        RECT  25.836 14.832 25.92 14.856 ;
    END
  END dst_d[61]
  PIN dst_d[62]
    DIRECTION OUTPUT ;
    USE SIGNAL ;
    PORT
      LAYER M4 ;
        RECT  25.836 15.024 25.92 15.048 ;
    END
  END dst_d[62]
  PIN dst_d[63]
    DIRECTION OUTPUT ;
    USE SIGNAL ;
    PORT
      LAYER M4 ;
        RECT  25.836 15.264 25.92 15.288 ;
    END
  END dst_d[63]
  PIN dst_d[64]
    DIRECTION OUTPUT ;
    USE SIGNAL ;
    PORT
      LAYER M4 ;
        RECT  25.836 15.456 25.92 15.48 ;
    END
  END dst_d[64]
  PIN dst_d[65]
    DIRECTION OUTPUT ;
    USE SIGNAL ;
    PORT
      LAYER M4 ;
        RECT  25.836 15.648 25.92 15.672 ;
    END
  END dst_d[65]
  PIN dst_d[66]
    DIRECTION OUTPUT ;
    USE SIGNAL ;
    PORT
      LAYER M4 ;
        RECT  25.836 15.84 25.92 15.864 ;
    END
  END dst_d[66]
  PIN dst_d[67]
    DIRECTION OUTPUT ;
    USE SIGNAL ;
    PORT
      LAYER M4 ;
        RECT  25.836 16.032 25.92 16.056 ;
    END
  END dst_d[67]
  PIN dst_d[68]
    DIRECTION OUTPUT ;
    USE SIGNAL ;
    PORT
      LAYER M4 ;
        RECT  25.836 16.272 25.92 16.296 ;
    END
  END dst_d[68]
  PIN dst_d[69]
    DIRECTION OUTPUT ;
    USE SIGNAL ;
    PORT
      LAYER M4 ;
        RECT  25.836 16.464 25.92 16.488 ;
    END
  END dst_d[69]
  PIN dst_d[6]
    DIRECTION OUTPUT ;
    USE SIGNAL ;
    PORT
      LAYER M4 ;
        RECT  25.836 3.792 25.92 3.816 ;
    END
  END dst_d[6]
  PIN dst_d[70]
    DIRECTION OUTPUT ;
    USE SIGNAL ;
    PORT
      LAYER M4 ;
        RECT  25.836 16.656 25.92 16.68 ;
    END
  END dst_d[70]
  PIN dst_d[71]
    DIRECTION OUTPUT ;
    USE SIGNAL ;
    PORT
      LAYER M4 ;
        RECT  25.836 16.848 25.92 16.872 ;
    END
  END dst_d[71]
  PIN dst_d[72]
    DIRECTION OUTPUT ;
    USE SIGNAL ;
    PORT
      LAYER M4 ;
        RECT  25.836 17.04 25.92 17.064 ;
    END
  END dst_d[72]
  PIN dst_d[73]
    DIRECTION OUTPUT ;
    USE SIGNAL ;
    PORT
      LAYER M4 ;
        RECT  25.836 17.232 25.92 17.256 ;
    END
  END dst_d[73]
  PIN dst_d[74]
    DIRECTION OUTPUT ;
    USE SIGNAL ;
    PORT
      LAYER M4 ;
        RECT  25.836 17.472 25.92 17.496 ;
    END
  END dst_d[74]
  PIN dst_d[75]
    DIRECTION OUTPUT ;
    USE SIGNAL ;
    PORT
      LAYER M4 ;
        RECT  25.836 17.664 25.92 17.688 ;
    END
  END dst_d[75]
  PIN dst_d[76]
    DIRECTION OUTPUT ;
    USE SIGNAL ;
    PORT
      LAYER M4 ;
        RECT  25.836 17.856 25.92 17.88 ;
    END
  END dst_d[76]
  PIN dst_d[77]
    DIRECTION OUTPUT ;
    USE SIGNAL ;
    PORT
      LAYER M4 ;
        RECT  25.836 18.048 25.92 18.072 ;
    END
  END dst_d[77]
  PIN dst_d[78]
    DIRECTION OUTPUT ;
    USE SIGNAL ;
    PORT
      LAYER M4 ;
        RECT  25.836 18.24 25.92 18.264 ;
    END
  END dst_d[78]
  PIN dst_d[79]
    DIRECTION OUTPUT ;
    USE SIGNAL ;
    PORT
      LAYER M4 ;
        RECT  25.836 18.48 25.92 18.504 ;
    END
  END dst_d[79]
  PIN dst_d[7]
    DIRECTION OUTPUT ;
    USE SIGNAL ;
    PORT
      LAYER M4 ;
        RECT  25.836 3.984 25.92 4.008 ;
    END
  END dst_d[7]
  PIN dst_d[80]
    DIRECTION OUTPUT ;
    USE SIGNAL ;
    PORT
      LAYER M4 ;
        RECT  25.836 18.672 25.92 18.696 ;
    END
  END dst_d[80]
  PIN dst_d[81]
    DIRECTION OUTPUT ;
    USE SIGNAL ;
    PORT
      LAYER M4 ;
        RECT  25.836 18.864 25.92 18.888 ;
    END
  END dst_d[81]
  PIN dst_d[82]
    DIRECTION OUTPUT ;
    USE SIGNAL ;
    PORT
      LAYER M4 ;
        RECT  25.836 19.056 25.92 19.08 ;
    END
  END dst_d[82]
  PIN dst_d[83]
    DIRECTION OUTPUT ;
    USE SIGNAL ;
    PORT
      LAYER M4 ;
        RECT  25.836 19.248 25.92 19.272 ;
    END
  END dst_d[83]
  PIN dst_d[84]
    DIRECTION OUTPUT ;
    USE SIGNAL ;
    PORT
      LAYER M4 ;
        RECT  25.836 19.488 25.92 19.512 ;
    END
  END dst_d[84]
  PIN dst_d[85]
    DIRECTION OUTPUT ;
    USE SIGNAL ;
    PORT
      LAYER M4 ;
        RECT  25.836 19.68 25.92 19.704 ;
    END
  END dst_d[85]
  PIN dst_d[86]
    DIRECTION OUTPUT ;
    USE SIGNAL ;
    PORT
      LAYER M4 ;
        RECT  25.836 19.872 25.92 19.896 ;
    END
  END dst_d[86]
  PIN dst_d[87]
    DIRECTION OUTPUT ;
    USE SIGNAL ;
    PORT
      LAYER M4 ;
        RECT  25.836 20.064 25.92 20.088 ;
    END
  END dst_d[87]
  PIN dst_d[88]
    DIRECTION OUTPUT ;
    USE SIGNAL ;
    PORT
      LAYER M4 ;
        RECT  25.836 20.256 25.92 20.28 ;
    END
  END dst_d[88]
  PIN dst_d[89]
    DIRECTION OUTPUT ;
    USE SIGNAL ;
    PORT
      LAYER M4 ;
        RECT  25.836 20.448 25.92 20.472 ;
    END
  END dst_d[89]
  PIN dst_d[8]
    DIRECTION OUTPUT ;
    USE SIGNAL ;
    PORT
      LAYER M4 ;
        RECT  25.836 4.176 25.92 4.2 ;
    END
  END dst_d[8]
  PIN dst_d[90]
    DIRECTION OUTPUT ;
    USE SIGNAL ;
    PORT
      LAYER M4 ;
        RECT  25.836 20.688 25.92 20.712 ;
    END
  END dst_d[90]
  PIN dst_d[91]
    DIRECTION OUTPUT ;
    USE SIGNAL ;
    PORT
      LAYER M4 ;
        RECT  25.836 20.88 25.92 20.904 ;
    END
  END dst_d[91]
  PIN dst_d[92]
    DIRECTION OUTPUT ;
    USE SIGNAL ;
    PORT
      LAYER M4 ;
        RECT  25.836 21.072 25.92 21.096 ;
    END
  END dst_d[92]
  PIN dst_d[93]
    DIRECTION OUTPUT ;
    USE SIGNAL ;
    PORT
      LAYER M4 ;
        RECT  25.836 21.264 25.92 21.288 ;
    END
  END dst_d[93]
  PIN dst_d[94]
    DIRECTION OUTPUT ;
    USE SIGNAL ;
    PORT
      LAYER M4 ;
        RECT  25.836 21.456 25.92 21.48 ;
    END
  END dst_d[94]
  PIN dst_d[95]
    DIRECTION OUTPUT ;
    USE SIGNAL ;
    PORT
      LAYER M4 ;
        RECT  25.836 21.696 25.92 21.72 ;
    END
  END dst_d[95]
  PIN dst_d[96]
    DIRECTION OUTPUT ;
    USE SIGNAL ;
    PORT
      LAYER M4 ;
        RECT  25.836 21.888 25.92 21.912 ;
    END
  END dst_d[96]
  PIN dst_d[97]
    DIRECTION OUTPUT ;
    USE SIGNAL ;
    PORT
      LAYER M4 ;
        RECT  25.836 22.08 25.92 22.104 ;
    END
  END dst_d[97]
  PIN dst_d[98]
    DIRECTION OUTPUT ;
    USE SIGNAL ;
    PORT
      LAYER M4 ;
        RECT  25.836 22.272 25.92 22.296 ;
    END
  END dst_d[98]
  PIN dst_d[99]
    DIRECTION OUTPUT ;
    USE SIGNAL ;
    PORT
      LAYER M4 ;
        RECT  25.836 22.464 25.92 22.488 ;
    END
  END dst_d[99]
  PIN dst_d[9]
    DIRECTION OUTPUT ;
    USE SIGNAL ;
    PORT
      LAYER M4 ;
        RECT  25.836 4.416 25.92 4.44 ;
    END
  END dst_d[9]
  PIN dst_v[0]
    DIRECTION OUTPUT ;
    USE SIGNAL ;
    PORT
      LAYER M4 ;
        RECT  25.836 99.264 25.92 99.288 ;
    END
  END dst_v[0]
  PIN dst_v[10]
    DIRECTION OUTPUT ;
    USE SIGNAL ;
    PORT
      LAYER M4 ;
        RECT  25.836 101.952 25.92 101.976 ;
    END
  END dst_v[10]
  PIN dst_v[11]
    DIRECTION OUTPUT ;
    USE SIGNAL ;
    PORT
      LAYER M4 ;
        RECT  25.836 102.192 25.92 102.216 ;
    END
  END dst_v[11]
  PIN dst_v[12]
    DIRECTION OUTPUT ;
    USE SIGNAL ;
    PORT
      LAYER M4 ;
        RECT  25.836 102.48 25.92 102.504 ;
    END
  END dst_v[12]
  PIN dst_v[13]
    DIRECTION OUTPUT ;
    USE SIGNAL ;
    PORT
      LAYER M4 ;
        RECT  25.836 102.72 25.92 102.744 ;
    END
  END dst_v[13]
  PIN dst_v[14]
    DIRECTION OUTPUT ;
    USE SIGNAL ;
    PORT
      LAYER M4 ;
        RECT  25.836 103.008 25.92 103.032 ;
    END
  END dst_v[14]
  PIN dst_v[1]
    DIRECTION OUTPUT ;
    USE SIGNAL ;
    PORT
      LAYER M4 ;
        RECT  25.836 99.552 25.92 99.576 ;
    END
  END dst_v[1]
  PIN dst_v[2]
    DIRECTION OUTPUT ;
    USE SIGNAL ;
    PORT
      LAYER M4 ;
        RECT  25.836 99.792 25.92 99.816 ;
    END
  END dst_v[2]
  PIN dst_v[3]
    DIRECTION OUTPUT ;
    USE SIGNAL ;
    PORT
      LAYER M4 ;
        RECT  25.836 100.08 25.92 100.104 ;
    END
  END dst_v[3]
  PIN dst_v[4]
    DIRECTION OUTPUT ;
    USE SIGNAL ;
    PORT
      LAYER M4 ;
        RECT  25.836 100.32 25.92 100.344 ;
    END
  END dst_v[4]
  PIN dst_v[5]
    DIRECTION OUTPUT ;
    USE SIGNAL ;
    PORT
      LAYER M4 ;
        RECT  25.836 100.608 25.92 100.632 ;
    END
  END dst_v[5]
  PIN dst_v[6]
    DIRECTION OUTPUT ;
    USE SIGNAL ;
    PORT
      LAYER M4 ;
        RECT  25.836 100.848 25.92 100.872 ;
    END
  END dst_v[6]
  PIN dst_v[7]
    DIRECTION OUTPUT ;
    USE SIGNAL ;
    PORT
      LAYER M4 ;
        RECT  25.836 101.136 25.92 101.16 ;
    END
  END dst_v[7]
  PIN dst_v[8]
    DIRECTION OUTPUT ;
    USE SIGNAL ;
    PORT
      LAYER M4 ;
        RECT  25.836 101.376 25.92 101.4 ;
    END
  END dst_v[8]
  PIN dst_v[9]
    DIRECTION OUTPUT ;
    USE SIGNAL ;
    PORT
      LAYER M4 ;
        RECT  25.836 101.664 25.92 101.688 ;
    END
  END dst_v[9]
  PIN rst_n
    DIRECTION INPUT ;
    USE SIGNAL ;
    PORT
      LAYER M5 ;
        RECT  22.08 105.756 22.104 105.84 ;
    END
  END rst_n
  PIN select_fault
    DIRECTION OUTPUT ;
    USE SIGNAL ;
    PORT
      LAYER M5 ;
        RECT  22.56 105.756 22.584 105.84 ;
    END
  END select_fault
  PIN sink_select[0]
    DIRECTION INPUT ;
    USE SIGNAL ;
    PORT
      LAYER M5 ;
        RECT  6.816 105.756 6.84 105.84 ;
    END
  END sink_select[0]
  PIN sink_select[10]
    DIRECTION INPUT ;
    USE SIGNAL ;
    PORT
      LAYER M5 ;
        RECT  9.216 105.756 9.24 105.84 ;
    END
  END sink_select[10]
  PIN sink_select[11]
    DIRECTION INPUT ;
    USE SIGNAL ;
    PORT
      LAYER M5 ;
        RECT  9.456 105.756 9.48 105.84 ;
    END
  END sink_select[11]
  PIN sink_select[12]
    DIRECTION INPUT ;
    USE SIGNAL ;
    PORT
      LAYER M5 ;
        RECT  9.696 105.756 9.72 105.84 ;
    END
  END sink_select[12]
  PIN sink_select[13]
    DIRECTION INPUT ;
    USE SIGNAL ;
    PORT
      LAYER M5 ;
        RECT  9.936 105.756 9.96 105.84 ;
    END
  END sink_select[13]
  PIN sink_select[14]
    DIRECTION INPUT ;
    USE SIGNAL ;
    PORT
      LAYER M5 ;
        RECT  10.176 105.756 10.2 105.84 ;
    END
  END sink_select[14]
  PIN sink_select[15]
    DIRECTION INPUT ;
    USE SIGNAL ;
    PORT
      LAYER M5 ;
        RECT  10.416 105.756 10.44 105.84 ;
    END
  END sink_select[15]
  PIN sink_select[16]
    DIRECTION INPUT ;
    USE SIGNAL ;
    PORT
      LAYER M5 ;
        RECT  10.704 105.756 10.728 105.84 ;
    END
  END sink_select[16]
  PIN sink_select[17]
    DIRECTION INPUT ;
    USE SIGNAL ;
    PORT
      LAYER M5 ;
        RECT  10.944 105.756 10.968 105.84 ;
    END
  END sink_select[17]
  PIN sink_select[18]
    DIRECTION INPUT ;
    USE SIGNAL ;
    PORT
      LAYER M5 ;
        RECT  11.184 105.756 11.208 105.84 ;
    END
  END sink_select[18]
  PIN sink_select[19]
    DIRECTION INPUT ;
    USE SIGNAL ;
    PORT
      LAYER M5 ;
        RECT  11.424 105.756 11.448 105.84 ;
    END
  END sink_select[19]
  PIN sink_select[1]
    DIRECTION INPUT ;
    USE SIGNAL ;
    PORT
      LAYER M5 ;
        RECT  7.056 105.756 7.08 105.84 ;
    END
  END sink_select[1]
  PIN sink_select[20]
    DIRECTION INPUT ;
    USE SIGNAL ;
    PORT
      LAYER M5 ;
        RECT  11.664 105.756 11.688 105.84 ;
    END
  END sink_select[20]
  PIN sink_select[21]
    DIRECTION INPUT ;
    USE SIGNAL ;
    PORT
      LAYER M5 ;
        RECT  11.904 105.756 11.928 105.84 ;
    END
  END sink_select[21]
  PIN sink_select[22]
    DIRECTION INPUT ;
    USE SIGNAL ;
    PORT
      LAYER M5 ;
        RECT  12.144 105.756 12.168 105.84 ;
    END
  END sink_select[22]
  PIN sink_select[23]
    DIRECTION INPUT ;
    USE SIGNAL ;
    PORT
      LAYER M5 ;
        RECT  12.384 105.756 12.408 105.84 ;
    END
  END sink_select[23]
  PIN sink_select[24]
    DIRECTION INPUT ;
    USE SIGNAL ;
    PORT
      LAYER M5 ;
        RECT  12.624 105.756 12.648 105.84 ;
    END
  END sink_select[24]
  PIN sink_select[25]
    DIRECTION INPUT ;
    USE SIGNAL ;
    PORT
      LAYER M5 ;
        RECT  12.864 105.756 12.888 105.84 ;
    END
  END sink_select[25]
  PIN sink_select[26]
    DIRECTION INPUT ;
    USE SIGNAL ;
    PORT
      LAYER M5 ;
        RECT  13.104 105.756 13.128 105.84 ;
    END
  END sink_select[26]
  PIN sink_select[27]
    DIRECTION INPUT ;
    USE SIGNAL ;
    PORT
      LAYER M5 ;
        RECT  13.344 105.756 13.368 105.84 ;
    END
  END sink_select[27]
  PIN sink_select[28]
    DIRECTION INPUT ;
    USE SIGNAL ;
    PORT
      LAYER M5 ;
        RECT  13.584 105.756 13.608 105.84 ;
    END
  END sink_select[28]
  PIN sink_select[29]
    DIRECTION INPUT ;
    USE SIGNAL ;
    PORT
      LAYER M5 ;
        RECT  13.824 105.756 13.848 105.84 ;
    END
  END sink_select[29]
  PIN sink_select[2]
    DIRECTION INPUT ;
    USE SIGNAL ;
    PORT
      LAYER M5 ;
        RECT  7.296 105.756 7.32 105.84 ;
    END
  END sink_select[2]
  PIN sink_select[30]
    DIRECTION INPUT ;
    USE SIGNAL ;
    PORT
      LAYER M5 ;
        RECT  14.064 105.756 14.088 105.84 ;
    END
  END sink_select[30]
  PIN sink_select[31]
    DIRECTION INPUT ;
    USE SIGNAL ;
    PORT
      LAYER M5 ;
        RECT  14.304 105.756 14.328 105.84 ;
    END
  END sink_select[31]
  PIN sink_select[32]
    DIRECTION INPUT ;
    USE SIGNAL ;
    PORT
      LAYER M5 ;
        RECT  14.544 105.756 14.568 105.84 ;
    END
  END sink_select[32]
  PIN sink_select[33]
    DIRECTION INPUT ;
    USE SIGNAL ;
    PORT
      LAYER M5 ;
        RECT  14.784 105.756 14.808 105.84 ;
    END
  END sink_select[33]
  PIN sink_select[34]
    DIRECTION INPUT ;
    USE SIGNAL ;
    PORT
      LAYER M5 ;
        RECT  15.024 105.756 15.048 105.84 ;
    END
  END sink_select[34]
  PIN sink_select[35]
    DIRECTION INPUT ;
    USE SIGNAL ;
    PORT
      LAYER M5 ;
        RECT  15.264 105.756 15.288 105.84 ;
    END
  END sink_select[35]
  PIN sink_select[36]
    DIRECTION INPUT ;
    USE SIGNAL ;
    PORT
      LAYER M5 ;
        RECT  15.504 105.756 15.528 105.84 ;
    END
  END sink_select[36]
  PIN sink_select[37]
    DIRECTION INPUT ;
    USE SIGNAL ;
    PORT
      LAYER M5 ;
        RECT  15.744 105.756 15.768 105.84 ;
    END
  END sink_select[37]
  PIN sink_select[38]
    DIRECTION INPUT ;
    USE SIGNAL ;
    PORT
      LAYER M5 ;
        RECT  15.984 105.756 16.008 105.84 ;
    END
  END sink_select[38]
  PIN sink_select[39]
    DIRECTION INPUT ;
    USE SIGNAL ;
    PORT
      LAYER M5 ;
        RECT  16.224 105.756 16.248 105.84 ;
    END
  END sink_select[39]
  PIN sink_select[3]
    DIRECTION INPUT ;
    USE SIGNAL ;
    PORT
      LAYER M5 ;
        RECT  7.536 105.756 7.56 105.84 ;
    END
  END sink_select[3]
  PIN sink_select[40]
    DIRECTION INPUT ;
    USE SIGNAL ;
    PORT
      LAYER M5 ;
        RECT  16.512 105.756 16.536 105.84 ;
    END
  END sink_select[40]
  PIN sink_select[41]
    DIRECTION INPUT ;
    USE SIGNAL ;
    PORT
      LAYER M5 ;
        RECT  16.752 105.756 16.776 105.84 ;
    END
  END sink_select[41]
  PIN sink_select[42]
    DIRECTION INPUT ;
    USE SIGNAL ;
    PORT
      LAYER M5 ;
        RECT  16.992 105.756 17.016 105.84 ;
    END
  END sink_select[42]
  PIN sink_select[43]
    DIRECTION INPUT ;
    USE SIGNAL ;
    PORT
      LAYER M5 ;
        RECT  17.232 105.756 17.256 105.84 ;
    END
  END sink_select[43]
  PIN sink_select[44]
    DIRECTION INPUT ;
    USE SIGNAL ;
    PORT
      LAYER M5 ;
        RECT  17.472 105.756 17.496 105.84 ;
    END
  END sink_select[44]
  PIN sink_select[45]
    DIRECTION INPUT ;
    USE SIGNAL ;
    PORT
      LAYER M5 ;
        RECT  17.712 105.756 17.736 105.84 ;
    END
  END sink_select[45]
  PIN sink_select[46]
    DIRECTION INPUT ;
    USE SIGNAL ;
    PORT
      LAYER M5 ;
        RECT  17.952 105.756 17.976 105.84 ;
    END
  END sink_select[46]
  PIN sink_select[47]
    DIRECTION INPUT ;
    USE SIGNAL ;
    PORT
      LAYER M5 ;
        RECT  18.192 105.756 18.216 105.84 ;
    END
  END sink_select[47]
  PIN sink_select[48]
    DIRECTION INPUT ;
    USE SIGNAL ;
    PORT
      LAYER M5 ;
        RECT  18.432 105.756 18.456 105.84 ;
    END
  END sink_select[48]
  PIN sink_select[49]
    DIRECTION INPUT ;
    USE SIGNAL ;
    PORT
      LAYER M5 ;
        RECT  18.672 105.756 18.696 105.84 ;
    END
  END sink_select[49]
  PIN sink_select[4]
    DIRECTION INPUT ;
    USE SIGNAL ;
    PORT
      LAYER M5 ;
        RECT  7.776 105.756 7.8 105.84 ;
    END
  END sink_select[4]
  PIN sink_select[50]
    DIRECTION INPUT ;
    USE SIGNAL ;
    PORT
      LAYER M5 ;
        RECT  18.912 105.756 18.936 105.84 ;
    END
  END sink_select[50]
  PIN sink_select[51]
    DIRECTION INPUT ;
    USE SIGNAL ;
    PORT
      LAYER M5 ;
        RECT  19.152 105.756 19.176 105.84 ;
    END
  END sink_select[51]
  PIN sink_select[52]
    DIRECTION INPUT ;
    USE SIGNAL ;
    PORT
      LAYER M5 ;
        RECT  19.392 105.756 19.416 105.84 ;
    END
  END sink_select[52]
  PIN sink_select[53]
    DIRECTION INPUT ;
    USE SIGNAL ;
    PORT
      LAYER M5 ;
        RECT  19.632 105.756 19.656 105.84 ;
    END
  END sink_select[53]
  PIN sink_select[54]
    DIRECTION INPUT ;
    USE SIGNAL ;
    PORT
      LAYER M5 ;
        RECT  19.872 105.756 19.896 105.84 ;
    END
  END sink_select[54]
  PIN sink_select[55]
    DIRECTION INPUT ;
    USE SIGNAL ;
    PORT
      LAYER M5 ;
        RECT  20.112 105.756 20.136 105.84 ;
    END
  END sink_select[55]
  PIN sink_select[56]
    DIRECTION INPUT ;
    USE SIGNAL ;
    PORT
      LAYER M5 ;
        RECT  20.352 105.756 20.376 105.84 ;
    END
  END sink_select[56]
  PIN sink_select[57]
    DIRECTION INPUT ;
    USE SIGNAL ;
    PORT
      LAYER M5 ;
        RECT  20.592 105.756 20.616 105.84 ;
    END
  END sink_select[57]
  PIN sink_select[58]
    DIRECTION INPUT ;
    USE SIGNAL ;
    PORT
      LAYER M5 ;
        RECT  20.832 105.756 20.856 105.84 ;
    END
  END sink_select[58]
  PIN sink_select[59]
    DIRECTION INPUT ;
    USE SIGNAL ;
    PORT
      LAYER M5 ;
        RECT  21.072 105.756 21.096 105.84 ;
    END
  END sink_select[59]
  PIN sink_select[5]
    DIRECTION INPUT ;
    USE SIGNAL ;
    PORT
      LAYER M5 ;
        RECT  8.016 105.756 8.04 105.84 ;
    END
  END sink_select[5]
  PIN sink_select[6]
    DIRECTION INPUT ;
    USE SIGNAL ;
    PORT
      LAYER M5 ;
        RECT  8.256 105.756 8.28 105.84 ;
    END
  END sink_select[6]
  PIN sink_select[7]
    DIRECTION INPUT ;
    USE SIGNAL ;
    PORT
      LAYER M5 ;
        RECT  8.496 105.756 8.52 105.84 ;
    END
  END sink_select[7]
  PIN sink_select[8]
    DIRECTION INPUT ;
    USE SIGNAL ;
    PORT
      LAYER M5 ;
        RECT  8.736 105.756 8.76 105.84 ;
    END
  END sink_select[8]
  PIN sink_select[9]
    DIRECTION INPUT ;
    USE SIGNAL ;
    PORT
      LAYER M5 ;
        RECT  8.976 105.756 9 105.84 ;
    END
  END sink_select[9]
  PIN sink_slot[0]
    DIRECTION INPUT ;
    USE SIGNAL ;
    PORT
      LAYER M5 ;
        RECT  2.64 105.756 2.664 105.84 ;
    END
  END sink_slot[0]
  PIN sink_slot[10]
    DIRECTION INPUT ;
    USE SIGNAL ;
    PORT
      LAYER M5 ;
        RECT  5.28 105.756 5.304 105.84 ;
    END
  END sink_slot[10]
  PIN sink_slot[11]
    DIRECTION INPUT ;
    USE SIGNAL ;
    PORT
      LAYER M5 ;
        RECT  5.568 105.756 5.592 105.84 ;
    END
  END sink_slot[11]
  PIN sink_slot[12]
    DIRECTION INPUT ;
    USE SIGNAL ;
    PORT
      LAYER M5 ;
        RECT  5.808 105.756 5.832 105.84 ;
    END
  END sink_slot[12]
  PIN sink_slot[13]
    DIRECTION INPUT ;
    USE SIGNAL ;
    PORT
      LAYER M5 ;
        RECT  6.096 105.756 6.12 105.84 ;
    END
  END sink_slot[13]
  PIN sink_slot[14]
    DIRECTION INPUT ;
    USE SIGNAL ;
    PORT
      LAYER M5 ;
        RECT  6.336 105.756 6.36 105.84 ;
    END
  END sink_slot[14]
  PIN sink_slot[1]
    DIRECTION INPUT ;
    USE SIGNAL ;
    PORT
      LAYER M5 ;
        RECT  2.88 105.756 2.904 105.84 ;
    END
  END sink_slot[1]
  PIN sink_slot[2]
    DIRECTION INPUT ;
    USE SIGNAL ;
    PORT
      LAYER M5 ;
        RECT  3.168 105.756 3.192 105.84 ;
    END
  END sink_slot[2]
  PIN sink_slot[3]
    DIRECTION INPUT ;
    USE SIGNAL ;
    PORT
      LAYER M5 ;
        RECT  3.408 105.756 3.432 105.84 ;
    END
  END sink_slot[3]
  PIN sink_slot[4]
    DIRECTION INPUT ;
    USE SIGNAL ;
    PORT
      LAYER M5 ;
        RECT  3.696 105.756 3.72 105.84 ;
    END
  END sink_slot[4]
  PIN sink_slot[5]
    DIRECTION INPUT ;
    USE SIGNAL ;
    PORT
      LAYER M5 ;
        RECT  3.936 105.756 3.96 105.84 ;
    END
  END sink_slot[5]
  PIN sink_slot[6]
    DIRECTION INPUT ;
    USE SIGNAL ;
    PORT
      LAYER M5 ;
        RECT  4.224 105.756 4.248 105.84 ;
    END
  END sink_slot[6]
  PIN sink_slot[7]
    DIRECTION INPUT ;
    USE SIGNAL ;
    PORT
      LAYER M5 ;
        RECT  4.512 105.756 4.536 105.84 ;
    END
  END sink_slot[7]
  PIN sink_slot[8]
    DIRECTION INPUT ;
    USE SIGNAL ;
    PORT
      LAYER M5 ;
        RECT  4.752 105.756 4.776 105.84 ;
    END
  END sink_slot[8]
  PIN sink_slot[9]
    DIRECTION INPUT ;
    USE SIGNAL ;
    PORT
      LAYER M5 ;
        RECT  5.04 105.756 5.064 105.84 ;
    END
  END sink_slot[9]
  PIN unavailable_fault
    DIRECTION OUTPUT ;
    USE SIGNAL ;
    PORT
      LAYER M5 ;
        RECT  23.04 105.756 23.064 105.84 ;
    END
  END unavailable_fault
  PIN VDD
    DIRECTION INOUT ;
    USE POWER ;
    PORT
      LAYER M5 ;
        RECT  18.792 2.151 18.912 103.689 ;
        RECT  13.392 2.151 13.512 103.689 ;
        RECT  7.992 2.151 8.112 103.689 ;
        RECT  2.592 2.151 2.712 103.689 ;
    END
  END VDD
  PIN VSS
    DIRECTION INOUT ;
    USE GROUND ;
    PORT
      LAYER M5 ;
        RECT  18.6 2.137 18.72 103.703 ;
        RECT  13.2 2.137 13.32 103.703 ;
        RECT  7.8 2.137 7.92 103.703 ;
        RECT  2.4 2.137 2.52 103.703 ;
    END
  END VSS
  # OT_OBS_CLOSED layer=M5 d_um=1.536 added=72
  OBS
    LAYER RVTN ;
     RECT  2.16 2.16 23.76 2.295 ;
     RECT  2.16 2.565 23.76 2.835 ;
     RECT  2.16 3.105 23.76 3.375 ;
     RECT  2.16 3.645 23.76 3.915 ;
     RECT  2.16 4.185 23.76 4.455 ;
     RECT  2.16 4.725 23.76 4.995 ;
     RECT  2.16 5.265 23.76 5.535 ;
     RECT  2.16 5.805 23.76 6.075 ;
     RECT  2.16 6.345 23.76 6.615 ;
     RECT  2.16 6.885 23.76 7.155 ;
     RECT  2.16 7.425 23.76 7.695 ;
     RECT  2.16 7.965 23.76 8.235 ;
     RECT  2.16 8.505 23.76 8.775 ;
     RECT  2.16 9.045 23.76 9.315 ;
     RECT  2.16 9.585 23.76 9.855 ;
     RECT  2.16 10.125 23.76 10.395 ;
     RECT  2.16 10.665 23.76 10.935 ;
     RECT  2.16 11.205 23.76 11.475 ;
     RECT  2.16 11.745 23.76 12.015 ;
     RECT  2.16 12.285 23.76 12.555 ;
     RECT  2.16 12.825 23.76 13.095 ;
     RECT  2.16 13.365 23.76 13.635 ;
     RECT  2.16 13.905 23.76 14.175 ;
     RECT  2.16 14.445 23.76 14.715 ;
     RECT  2.16 14.985 23.76 15.255 ;
     RECT  2.16 15.525 23.76 15.795 ;
     RECT  2.16 16.065 23.76 16.335 ;
     RECT  2.16 16.605 23.76 16.875 ;
     RECT  2.16 17.145 23.76 17.415 ;
     RECT  2.16 17.685 23.76 17.955 ;
     RECT  2.16 18.225 23.76 18.495 ;
     RECT  2.16 18.765 23.76 19.035 ;
     RECT  2.16 19.305 23.76 19.575 ;
     RECT  2.16 19.845 23.76 20.115 ;
     RECT  2.16 20.385 23.76 20.655 ;
     RECT  2.16 20.925 23.76 21.195 ;
     RECT  2.16 21.465 23.76 21.735 ;
     RECT  2.16 22.005 23.76 22.275 ;
     RECT  2.16 22.545 23.76 22.815 ;
     RECT  2.16 23.085 23.76 23.355 ;
     RECT  2.16 23.625 23.76 23.895 ;
     RECT  2.16 24.165 23.76 24.435 ;
     RECT  2.16 24.705 23.76 24.975 ;
     RECT  2.16 25.245 23.76 25.515 ;
     RECT  2.16 25.785 23.76 26.055 ;
     RECT  2.16 26.325 23.76 26.595 ;
     RECT  2.16 26.865 23.76 27.135 ;
     RECT  2.16 27.405 23.76 27.675 ;
     RECT  2.16 27.945 23.76 28.215 ;
     RECT  2.16 28.485 23.76 28.755 ;
     RECT  2.16 29.025 23.76 29.295 ;
     RECT  2.16 29.565 23.76 29.835 ;
     RECT  2.16 30.105 23.76 30.375 ;
     RECT  2.16 30.645 23.76 30.915 ;
     RECT  2.16 31.185 23.76 31.455 ;
     RECT  2.16 31.725 23.76 31.995 ;
     RECT  2.16 32.265 23.76 32.535 ;
     RECT  2.16 32.805 23.76 33.075 ;
     RECT  2.16 33.345 23.76 33.615 ;
     RECT  2.16 33.885 23.76 34.155 ;
     RECT  2.16 34.425 23.76 34.695 ;
     RECT  2.16 34.965 23.76 35.235 ;
     RECT  2.16 35.505 23.76 35.775 ;
     RECT  2.16 36.045 23.76 36.315 ;
     RECT  2.16 36.585 23.76 36.855 ;
     RECT  2.16 37.125 23.76 37.395 ;
     RECT  2.16 37.665 23.76 37.935 ;
     RECT  2.16 38.205 23.76 38.475 ;
     RECT  2.16 38.745 23.76 39.015 ;
     RECT  2.16 39.285 23.76 39.555 ;
     RECT  2.16 39.825 23.76 40.095 ;
     RECT  2.16 40.365 23.76 40.635 ;
     RECT  2.16 40.905 23.76 41.175 ;
     RECT  2.16 41.445 23.76 41.715 ;
     RECT  2.16 41.985 23.76 42.255 ;
     RECT  2.16 42.525 23.76 42.795 ;
     RECT  2.16 43.065 23.76 43.335 ;
     RECT  2.16 43.605 23.76 43.875 ;
     RECT  2.16 44.145 23.76 44.415 ;
     RECT  2.16 44.685 23.76 44.955 ;
     RECT  2.16 45.225 23.76 45.495 ;
     RECT  2.16 45.765 23.76 46.035 ;
     RECT  2.16 46.305 23.76 46.575 ;
     RECT  2.16 46.845 23.76 47.115 ;
     RECT  2.16 47.385 23.76 47.655 ;
     RECT  2.16 47.925 23.76 48.195 ;
     RECT  2.16 48.465 23.76 48.735 ;
     RECT  2.16 49.005 23.76 49.275 ;
     RECT  2.16 49.545 23.76 49.815 ;
     RECT  2.16 50.085 23.76 50.355 ;
     RECT  2.16 50.625 23.76 50.895 ;
     RECT  2.16 51.165 23.76 51.435 ;
     RECT  2.16 51.705 23.76 51.975 ;
     RECT  2.16 52.245 23.76 52.515 ;
     RECT  2.16 52.785 23.76 53.055 ;
     RECT  2.16 53.325 23.76 53.595 ;
     RECT  2.16 53.865 23.76 54.135 ;
     RECT  2.16 54.405 23.76 54.675 ;
     RECT  2.16 54.945 23.76 55.215 ;
     RECT  2.16 55.485 23.76 55.755 ;
     RECT  2.16 56.025 23.76 56.295 ;
     RECT  2.16 56.565 23.76 56.835 ;
     RECT  2.16 57.105 23.76 57.375 ;
     RECT  2.16 57.645 23.76 57.915 ;
     RECT  2.16 58.185 23.76 58.455 ;
     RECT  2.16 58.725 23.76 58.995 ;
     RECT  2.16 59.265 23.76 59.535 ;
     RECT  2.16 59.805 23.76 60.075 ;
     RECT  2.16 60.345 23.76 60.615 ;
     RECT  2.16 60.885 23.76 61.155 ;
     RECT  2.16 61.425 23.76 61.695 ;
     RECT  2.16 61.965 23.76 62.235 ;
     RECT  2.16 62.505 23.76 62.775 ;
     RECT  2.16 63.045 23.76 63.315 ;
     RECT  2.16 63.585 23.76 63.855 ;
     RECT  2.16 64.125 23.76 64.395 ;
     RECT  2.16 64.665 23.76 64.935 ;
     RECT  2.16 65.205 23.76 65.475 ;
     RECT  2.16 65.745 23.76 66.015 ;
     RECT  2.16 66.285 23.76 66.555 ;
     RECT  2.16 66.825 23.76 67.095 ;
     RECT  2.16 67.365 23.76 67.635 ;
     RECT  2.16 67.905 23.76 68.175 ;
     RECT  2.16 68.445 23.76 68.715 ;
     RECT  2.16 68.985 23.76 69.255 ;
     RECT  2.16 69.525 23.76 69.795 ;
     RECT  2.16 70.065 23.76 70.335 ;
     RECT  2.16 70.605 23.76 70.875 ;
     RECT  2.16 71.145 23.76 71.415 ;
     RECT  2.16 71.685 23.76 71.955 ;
     RECT  2.16 72.225 23.76 72.495 ;
     RECT  2.16 72.765 23.76 73.035 ;
     RECT  2.16 73.305 23.76 73.575 ;
     RECT  2.16 73.845 23.76 74.115 ;
     RECT  2.16 74.385 23.76 74.655 ;
     RECT  2.16 74.925 23.76 75.195 ;
     RECT  2.16 75.465 23.76 75.735 ;
     RECT  2.16 76.005 23.76 76.275 ;
     RECT  2.16 76.545 23.76 76.815 ;
     RECT  2.16 77.085 23.76 77.355 ;
     RECT  2.16 77.625 23.76 77.895 ;
     RECT  2.16 78.165 23.76 78.435 ;
     RECT  2.16 78.705 23.76 78.975 ;
     RECT  2.16 79.245 23.76 79.515 ;
     RECT  2.16 79.785 23.76 80.055 ;
     RECT  2.16 80.325 23.76 80.595 ;
     RECT  2.16 80.865 23.76 81.135 ;
     RECT  2.16 81.405 23.76 81.675 ;
     RECT  2.16 81.945 23.76 82.215 ;
     RECT  2.16 82.485 23.76 82.755 ;
     RECT  2.16 83.025 23.76 83.295 ;
     RECT  2.16 83.565 23.76 83.835 ;
     RECT  2.16 84.105 23.76 84.375 ;
     RECT  2.16 84.645 23.76 84.915 ;
     RECT  2.16 85.185 23.76 85.455 ;
     RECT  2.16 85.725 23.76 85.995 ;
     RECT  2.16 86.265 23.76 86.535 ;
     RECT  2.16 86.805 23.76 87.075 ;
     RECT  2.16 87.345 23.76 87.615 ;
     RECT  2.16 87.885 23.76 88.155 ;
     RECT  2.16 88.425 23.76 88.695 ;
     RECT  2.16 88.965 23.76 89.235 ;
     RECT  2.16 89.505 23.76 89.775 ;
     RECT  2.16 90.045 23.76 90.315 ;
     RECT  2.16 90.585 23.76 90.855 ;
     RECT  2.16 91.125 23.76 91.395 ;
     RECT  2.16 91.665 23.76 91.935 ;
     RECT  2.16 92.205 23.76 92.475 ;
     RECT  2.16 92.745 23.76 93.015 ;
     RECT  2.16 93.285 23.76 93.555 ;
     RECT  2.16 93.825 23.76 94.095 ;
     RECT  2.16 94.365 23.76 94.635 ;
     RECT  2.16 94.905 23.76 95.175 ;
     RECT  2.16 95.445 23.76 95.715 ;
     RECT  2.16 95.985 23.76 96.255 ;
     RECT  2.16 96.525 23.76 96.795 ;
     RECT  2.16 97.065 23.76 97.335 ;
     RECT  2.16 97.605 23.76 97.875 ;
     RECT  2.16 98.145 23.76 98.415 ;
     RECT  2.16 98.685 23.76 98.955 ;
     RECT  2.16 99.225 23.76 99.495 ;
     RECT  2.16 99.765 23.76 100.035 ;
     RECT  2.16 100.305 23.76 100.575 ;
     RECT  2.16 100.845 23.76 101.115 ;
     RECT  2.16 101.385 23.76 101.655 ;
     RECT  2.16 101.925 23.76 102.195 ;
     RECT  2.16 102.465 23.76 102.735 ;
     RECT  2.16 103.005 23.76 103.275 ;
     RECT  2.16 103.545 23.76 103.68 ;
    LAYER RVTP ;
     RECT  2.16 2.295 23.76 2.565 ;
     RECT  2.16 2.835 23.76 3.105 ;
     RECT  2.16 3.375 23.76 3.645 ;
     RECT  2.16 3.915 23.76 4.185 ;
     RECT  2.16 4.455 23.76 4.725 ;
     RECT  2.16 4.995 23.76 5.265 ;
     RECT  2.16 5.535 23.76 5.805 ;
     RECT  2.16 6.075 23.76 6.345 ;
     RECT  2.16 6.615 23.76 6.885 ;
     RECT  2.16 7.155 23.76 7.425 ;
     RECT  2.16 7.695 23.76 7.965 ;
     RECT  2.16 8.235 23.76 8.505 ;
     RECT  2.16 8.775 23.76 9.045 ;
     RECT  2.16 9.315 23.76 9.585 ;
     RECT  2.16 9.855 23.76 10.125 ;
     RECT  2.16 10.395 23.76 10.665 ;
     RECT  2.16 10.935 23.76 11.205 ;
     RECT  2.16 11.475 23.76 11.745 ;
     RECT  2.16 12.015 23.76 12.285 ;
     RECT  2.16 12.555 23.76 12.825 ;
     RECT  2.16 13.095 23.76 13.365 ;
     RECT  2.16 13.635 23.76 13.905 ;
     RECT  2.16 14.175 23.76 14.445 ;
     RECT  2.16 14.715 23.76 14.985 ;
     RECT  2.16 15.255 23.76 15.525 ;
     RECT  2.16 15.795 23.76 16.065 ;
     RECT  2.16 16.335 23.76 16.605 ;
     RECT  2.16 16.875 23.76 17.145 ;
     RECT  2.16 17.415 23.76 17.685 ;
     RECT  2.16 17.955 23.76 18.225 ;
     RECT  2.16 18.495 23.76 18.765 ;
     RECT  2.16 19.035 23.76 19.305 ;
     RECT  2.16 19.575 23.76 19.845 ;
     RECT  2.16 20.115 23.76 20.385 ;
     RECT  2.16 20.655 23.76 20.925 ;
     RECT  2.16 21.195 23.76 21.465 ;
     RECT  2.16 21.735 23.76 22.005 ;
     RECT  2.16 22.275 23.76 22.545 ;
     RECT  2.16 22.815 23.76 23.085 ;
     RECT  2.16 23.355 23.76 23.625 ;
     RECT  2.16 23.895 23.76 24.165 ;
     RECT  2.16 24.435 23.76 24.705 ;
     RECT  2.16 24.975 23.76 25.245 ;
     RECT  2.16 25.515 23.76 25.785 ;
     RECT  2.16 26.055 23.76 26.325 ;
     RECT  2.16 26.595 23.76 26.865 ;
     RECT  2.16 27.135 23.76 27.405 ;
     RECT  2.16 27.675 23.76 27.945 ;
     RECT  2.16 28.215 23.76 28.485 ;
     RECT  2.16 28.755 23.76 29.025 ;
     RECT  2.16 29.295 23.76 29.565 ;
     RECT  2.16 29.835 23.76 30.105 ;
     RECT  2.16 30.375 23.76 30.645 ;
     RECT  2.16 30.915 23.76 31.185 ;
     RECT  2.16 31.455 23.76 31.725 ;
     RECT  2.16 31.995 23.76 32.265 ;
     RECT  2.16 32.535 23.76 32.805 ;
     RECT  2.16 33.075 23.76 33.345 ;
     RECT  2.16 33.615 23.76 33.885 ;
     RECT  2.16 34.155 23.76 34.425 ;
     RECT  2.16 34.695 23.76 34.965 ;
     RECT  2.16 35.235 23.76 35.505 ;
     RECT  2.16 35.775 23.76 36.045 ;
     RECT  2.16 36.315 23.76 36.585 ;
     RECT  2.16 36.855 23.76 37.125 ;
     RECT  2.16 37.395 23.76 37.665 ;
     RECT  2.16 37.935 23.76 38.205 ;
     RECT  2.16 38.475 23.76 38.745 ;
     RECT  2.16 39.015 23.76 39.285 ;
     RECT  2.16 39.555 23.76 39.825 ;
     RECT  2.16 40.095 23.76 40.365 ;
     RECT  2.16 40.635 23.76 40.905 ;
     RECT  2.16 41.175 23.76 41.445 ;
     RECT  2.16 41.715 23.76 41.985 ;
     RECT  2.16 42.255 23.76 42.525 ;
     RECT  2.16 42.795 23.76 43.065 ;
     RECT  2.16 43.335 23.76 43.605 ;
     RECT  2.16 43.875 23.76 44.145 ;
     RECT  2.16 44.415 23.76 44.685 ;
     RECT  2.16 44.955 23.76 45.225 ;
     RECT  2.16 45.495 23.76 45.765 ;
     RECT  2.16 46.035 23.76 46.305 ;
     RECT  2.16 46.575 23.76 46.845 ;
     RECT  2.16 47.115 23.76 47.385 ;
     RECT  2.16 47.655 23.76 47.925 ;
     RECT  2.16 48.195 23.76 48.465 ;
     RECT  2.16 48.735 23.76 49.005 ;
     RECT  2.16 49.275 23.76 49.545 ;
     RECT  2.16 49.815 23.76 50.085 ;
     RECT  2.16 50.355 23.76 50.625 ;
     RECT  2.16 50.895 23.76 51.165 ;
     RECT  2.16 51.435 23.76 51.705 ;
     RECT  2.16 51.975 23.76 52.245 ;
     RECT  2.16 52.515 23.76 52.785 ;
     RECT  2.16 53.055 23.76 53.325 ;
     RECT  2.16 53.595 23.76 53.865 ;
     RECT  2.16 54.135 23.76 54.405 ;
     RECT  2.16 54.675 23.76 54.945 ;
     RECT  2.16 55.215 23.76 55.485 ;
     RECT  2.16 55.755 23.76 56.025 ;
     RECT  2.16 56.295 23.76 56.565 ;
     RECT  2.16 56.835 23.76 57.105 ;
     RECT  2.16 57.375 23.76 57.645 ;
     RECT  2.16 57.915 23.76 58.185 ;
     RECT  2.16 58.455 23.76 58.725 ;
     RECT  2.16 58.995 23.76 59.265 ;
     RECT  2.16 59.535 23.76 59.805 ;
     RECT  2.16 60.075 23.76 60.345 ;
     RECT  2.16 60.615 23.76 60.885 ;
     RECT  2.16 61.155 23.76 61.425 ;
     RECT  2.16 61.695 23.76 61.965 ;
     RECT  2.16 62.235 23.76 62.505 ;
     RECT  2.16 62.775 23.76 63.045 ;
     RECT  2.16 63.315 23.76 63.585 ;
     RECT  2.16 63.855 23.76 64.125 ;
     RECT  2.16 64.395 23.76 64.665 ;
     RECT  2.16 64.935 23.76 65.205 ;
     RECT  2.16 65.475 23.76 65.745 ;
     RECT  2.16 66.015 23.76 66.285 ;
     RECT  2.16 66.555 23.76 66.825 ;
     RECT  2.16 67.095 23.76 67.365 ;
     RECT  2.16 67.635 23.76 67.905 ;
     RECT  2.16 68.175 23.76 68.445 ;
     RECT  2.16 68.715 23.76 68.985 ;
     RECT  2.16 69.255 23.76 69.525 ;
     RECT  2.16 69.795 23.76 70.065 ;
     RECT  2.16 70.335 23.76 70.605 ;
     RECT  2.16 70.875 23.76 71.145 ;
     RECT  2.16 71.415 23.76 71.685 ;
     RECT  2.16 71.955 23.76 72.225 ;
     RECT  2.16 72.495 23.76 72.765 ;
     RECT  2.16 73.035 23.76 73.305 ;
     RECT  2.16 73.575 23.76 73.845 ;
     RECT  2.16 74.115 23.76 74.385 ;
     RECT  2.16 74.655 23.76 74.925 ;
     RECT  2.16 75.195 23.76 75.465 ;
     RECT  2.16 75.735 23.76 76.005 ;
     RECT  2.16 76.275 23.76 76.545 ;
     RECT  2.16 76.815 23.76 77.085 ;
     RECT  2.16 77.355 23.76 77.625 ;
     RECT  2.16 77.895 23.76 78.165 ;
     RECT  2.16 78.435 23.76 78.705 ;
     RECT  2.16 78.975 23.76 79.245 ;
     RECT  2.16 79.515 23.76 79.785 ;
     RECT  2.16 80.055 23.76 80.325 ;
     RECT  2.16 80.595 23.76 80.865 ;
     RECT  2.16 81.135 23.76 81.405 ;
     RECT  2.16 81.675 23.76 81.945 ;
     RECT  2.16 82.215 23.76 82.485 ;
     RECT  2.16 82.755 23.76 83.025 ;
     RECT  2.16 83.295 23.76 83.565 ;
     RECT  2.16 83.835 23.76 84.105 ;
     RECT  2.16 84.375 23.76 84.645 ;
     RECT  2.16 84.915 23.76 85.185 ;
     RECT  2.16 85.455 23.76 85.725 ;
     RECT  2.16 85.995 23.76 86.265 ;
     RECT  2.16 86.535 23.76 86.805 ;
     RECT  2.16 87.075 23.76 87.345 ;
     RECT  2.16 87.615 23.76 87.885 ;
     RECT  2.16 88.155 23.76 88.425 ;
     RECT  2.16 88.695 23.76 88.965 ;
     RECT  2.16 89.235 23.76 89.505 ;
     RECT  2.16 89.775 23.76 90.045 ;
     RECT  2.16 90.315 23.76 90.585 ;
     RECT  2.16 90.855 23.76 91.125 ;
     RECT  2.16 91.395 23.76 91.665 ;
     RECT  2.16 91.935 23.76 92.205 ;
     RECT  2.16 92.475 23.76 92.745 ;
     RECT  2.16 93.015 23.76 93.285 ;
     RECT  2.16 93.555 23.76 93.825 ;
     RECT  2.16 94.095 23.76 94.365 ;
     RECT  2.16 94.635 23.76 94.905 ;
     RECT  2.16 95.175 23.76 95.445 ;
     RECT  2.16 95.715 23.76 95.985 ;
     RECT  2.16 96.255 23.76 96.525 ;
     RECT  2.16 96.795 23.76 97.065 ;
     RECT  2.16 97.335 23.76 97.605 ;
     RECT  2.16 97.875 23.76 98.145 ;
     RECT  2.16 98.415 23.76 98.685 ;
     RECT  2.16 98.955 23.76 99.225 ;
     RECT  2.16 99.495 23.76 99.765 ;
     RECT  2.16 100.035 23.76 100.305 ;
     RECT  2.16 100.575 23.76 100.845 ;
     RECT  2.16 101.115 23.76 101.385 ;
     RECT  2.16 101.655 23.76 101.925 ;
     RECT  2.16 102.195 23.76 102.465 ;
     RECT  2.16 102.735 23.76 103.005 ;
     RECT  2.16 103.275 23.76 103.545 ;
    LAYER M1 ;
     RECT  2.16 2.151 23.76 103.689 ;
    LAYER M2 ;
     RECT  0.031 79.218 0.103 79.236 ;
     RECT  0.031 91.872 0.103 91.89 ;
     RECT  0.103 91.71 0.131 91.89 ;
     RECT  0.103 25.02 0.139 25.038 ;
     RECT  0.103 39.222 0.139 39.24 ;
     RECT  0.103 48.816 0.139 52.74 ;
     RECT  0.103 61.362 0.139 62.19 ;
     RECT  0.103 68.652 0.139 69.48 ;
     RECT  0.103 83.61 0.139 83.628 ;
     RECT  0.103 87.12 0.139 87.138 ;
     RECT  0.103 93.6 0.139 93.618 ;
     RECT  0.103 94.572 0.139 94.59 ;
     RECT  0.139 48.402 0.535 52.74 ;
     RECT  0.103 58.392 0.535 60.03 ;
     RECT  0.139 61.092 0.535 62.19 ;
     RECT  0.103 62.982 0.535 67.428 ;
     RECT  0.139 68.22 0.535 69.48 ;
     RECT  0.103 79.218 0.823 79.578 ;
     RECT  0.103 43.812 1.039 43.83 ;
     RECT  0.103 45 1.039 45.45 ;
     RECT  1.039 73.35 1.075 73.368 ;
     RECT  0.103 33.588 1.111 33.606 ;
     RECT  1.111 72.54 1.147 72.558 ;
     RECT  0.139 25.02 1.399 25.308 ;
     RECT  0.103 77.832 1.399 77.85 ;
     RECT  0.139 93.6 1.399 94.59 ;
     RECT  0.139 90.9 1.435 90.918 ;
     RECT  0.131 91.71 1.435 91.728 ;
     RECT  0.103 95.49 1.435 95.508 ;
     RECT  0.103 96.3 1.435 96.318 ;
     RECT  0.103 71.622 1.471 71.64 ;
     RECT  1.147 72.432 1.471 72.558 ;
     RECT  1.435 95.49 1.471 96.318 ;
     RECT  0.103 74.592 1.507 74.61 ;
     RECT  1.039 43.812 1.543 45.45 ;
     RECT  1.543 43.146 1.579 45.45 ;
     RECT  1.507 74.592 1.579 74.988 ;
     RECT  0.535 58.392 1.651 69.48 ;
     RECT  0.535 70.344 1.651 70.362 ;
     RECT  1.651 58.392 1.687 70.362 ;
     RECT  1.471 71.622 1.687 72.558 ;
     RECT  0.139 83.502 1.687 83.628 ;
     RECT  0.103 35.28 1.903 35.298 ;
     RECT  1.579 74.592 1.903 75.528 ;
     RECT  1.723 81.18 1.939 81.198 ;
     RECT  1.687 58.392 1.975 72.558 ;
     RECT  0.823 79.218 1.975 80.118 ;
     RECT  0.103 88.902 1.975 88.92 ;
     RECT  1.399 77.832 2.011 78.39 ;
     RECT  1.975 79.218 2.011 80.154 ;
     RECT  1.975 58.23 2.047 72.558 ;
     RECT  1.075 73.314 2.047 73.368 ;
     RECT  2.011 77.832 2.083 80.154 ;
     RECT  1.939 80.946 2.083 81.198 ;
     RECT  1.687 37.71 2.119 37.728 ;
     RECT  2.119 37.71 2.155 37.764 ;
     RECT  1.903 74.592 2.155 75.564 ;
     RECT  0.103 76.59 2.155 76.608 ;
     RECT  0.103 2.916 2.16 2.934 ;
     RECT  0.103 5.076 2.16 5.094 ;
     RECT  1.399 8.442 2.16 8.46 ;
     RECT  1.975 10.206 2.16 10.224 ;
     RECT  1.975 12.564 2.16 12.582 ;
     RECT  0.103 18.774 2.16 19.368 ;
     RECT  0.103 22.752 2.16 22.77 ;
     RECT  1.399 25.02 2.16 25.74 ;
     RECT  0.103 28.8 2.16 28.818 ;
     RECT  0.103 31.23 2.16 31.248 ;
     RECT  1.111 33.354 2.16 33.606 ;
     RECT  1.939 34.47 2.16 34.488 ;
     RECT  1.903 35.28 2.16 35.838 ;
     RECT  2.155 37.71 2.16 38.034 ;
     RECT  0.139 39.222 2.16 39.618 ;
     RECT  0.103 40.41 2.16 40.428 ;
     RECT  1.579 43.146 2.16 45.594 ;
     RECT  1.507 46.854 2.16 46.872 ;
     RECT  0.535 48.402 2.16 52.884 ;
     RECT  0.103 54.072 2.16 57.33 ;
     RECT  2.047 58.23 2.16 73.368 ;
     RECT  2.155 74.592 2.16 76.608 ;
     RECT  2.083 77.832 2.16 81.198 ;
     RECT  1.687 83.376 2.16 83.628 ;
     RECT  0.139 86.778 2.16 87.138 ;
     RECT  1.975 88.2 2.16 88.92 ;
     RECT  2.047 89.982 2.16 90 ;
     RECT  1.435 90.9 2.16 91.728 ;
     RECT  1.399 93.06 2.16 94.59 ;
     RECT  1.471 95.49 2.16 96.588 ;
     RECT  0.031 97.65 2.16 97.668 ;
     RECT  0.103 99.162 2.16 99.18 ;
     RECT  0.103 100.242 2.16 100.26 ;
     RECT  0.103 101.43 2.16 101.988 ;
     RECT  2.16 2.151 11.983 103.689 ;
     RECT  11.983 2.151 20.471 103.734 ;
     RECT  20.471 2.151 23.76 103.689 ;
     RECT  23.76 80.874 23.891 101.844 ;
     RECT  23.76 7.596 23.927 30.024 ;
     RECT  23.76 30.888 23.927 80.082 ;
     RECT  23.927 16.236 23.963 30.024 ;
     RECT  23.927 55.296 23.963 64.314 ;
     RECT  23.891 80.946 23.963 101.844 ;
     RECT  23.927 68.616 24.143 79.974 ;
     RECT  23.927 30.888 24.359 31.914 ;
     RECT  23.927 32.706 24.395 38.034 ;
     RECT  24.143 69.498 24.395 79.974 ;
     RECT  23.963 16.236 24.431 21.834 ;
     RECT  23.963 22.896 24.431 30.024 ;
     RECT  23.963 90.864 24.431 101.844 ;
     RECT  23.927 14.526 24.467 15.282 ;
     RECT  24.431 16.236 24.467 19.134 ;
     RECT  24.431 22.896 24.467 25.704 ;
     RECT  24.395 35.406 24.467 38.034 ;
     RECT  23.927 43.038 24.467 48.924 ;
     RECT  24.395 69.498 24.467 77.544 ;
     RECT  24.431 99.576 24.467 101.844 ;
     RECT  23.927 7.596 24.503 13.662 ;
     RECT  24.467 14.688 24.503 15.282 ;
     RECT  24.467 18.846 24.503 19.134 ;
     RECT  24.467 22.986 24.503 25.704 ;
     RECT  24.431 26.766 24.503 30.024 ;
     RECT  23.927 39.294 24.503 40.356 ;
     RECT  23.927 41.256 24.503 42.084 ;
     RECT  24.467 43.038 24.503 47.142 ;
     RECT  23.927 49.896 24.503 50.814 ;
     RECT  23.927 51.606 24.503 54.468 ;
     RECT  23.963 55.386 24.503 62.604 ;
     RECT  23.963 63.666 24.503 64.314 ;
     RECT  24.467 69.696 24.503 71.064 ;
     RECT  23.963 80.946 24.503 89.964 ;
     RECT  24.431 90.864 24.503 98.514 ;
     RECT  24.467 99.666 24.503 101.844 ;
     RECT  23.76 3.816 24.539 6.804 ;
     RECT  24.503 23.706 24.539 25.704 ;
     RECT  24.467 72.036 24.539 77.544 ;
     RECT  24.503 93.636 24.539 98.514 ;
     RECT  24.503 80.946 24.575 82.944 ;
     RECT  24.359 30.888 25.043 31.104 ;
     RECT  24.467 35.406 25.043 37.854 ;
     RECT  24.503 51.606 25.043 52.974 ;
     RECT  24.143 68.616 25.043 68.742 ;
     RECT  24.503 70.038 25.043 71.064 ;
     RECT  24.395 78.336 25.043 79.974 ;
     RECT  24.539 93.636 25.043 97.794 ;
     RECT  23.76 102.744 25.043 103.104 ;
     RECT  24.539 3.816 25.079 6.102 ;
     RECT  24.503 7.596 25.079 8.424 ;
     RECT  24.503 9.216 25.079 13.554 ;
     RECT  24.503 14.994 25.079 15.282 ;
     RECT  24.467 16.236 25.079 17.874 ;
     RECT  24.503 18.846 25.079 19.062 ;
     RECT  24.431 20.556 25.079 21.834 ;
     RECT  24.539 24.786 25.079 25.704 ;
     RECT  24.503 26.766 25.079 28.944 ;
     RECT  24.503 30.006 25.079 30.024 ;
     RECT  25.043 30.924 25.079 31.104 ;
     RECT  24.359 31.896 25.079 31.914 ;
     RECT  24.395 32.706 25.079 33.534 ;
     RECT  24.395 34.506 25.079 34.614 ;
     RECT  25.043 35.406 25.079 35.424 ;
     RECT  25.043 36.216 25.079 37.854 ;
     RECT  24.503 39.456 25.079 40.194 ;
     RECT  24.503 44.496 25.079 47.07 ;
     RECT  24.467 48.096 25.079 48.924 ;
     RECT  24.503 49.986 25.079 50.814 ;
     RECT  25.043 51.876 25.079 51.894 ;
     RECT  25.043 52.686 25.079 52.974 ;
     RECT  24.503 53.766 25.079 54.126 ;
     RECT  24.503 55.386 25.079 57.294 ;
     RECT  24.503 58.122 25.079 62.604 ;
     RECT  24.503 63.756 25.079 64.314 ;
     RECT  23.927 65.214 25.079 67.554 ;
     RECT  25.043 68.616 25.079 68.634 ;
     RECT  25.043 71.046 25.079 71.064 ;
     RECT  24.539 72.126 25.079 77.544 ;
     RECT  25.043 78.336 25.079 78.354 ;
     RECT  25.043 79.326 25.079 79.974 ;
     RECT  24.575 80.946 25.079 82.134 ;
     RECT  24.575 82.926 25.079 82.944 ;
     RECT  24.503 84.456 25.079 89.964 ;
     RECT  24.503 90.864 25.079 91.854 ;
     RECT  25.043 93.636 25.079 97.524 ;
     RECT  24.503 100.386 25.079 101.754 ;
     RECT  25.043 102.744 25.079 102.762 ;
     RECT  25.079 6.084 25.115 6.102 ;
     RECT  25.079 7.776 25.115 7.794 ;
     RECT  25.079 9.9 25.115 11.574 ;
     RECT  25.079 12.366 25.115 12.888 ;
     RECT  25.079 16.956 25.115 17.172 ;
     RECT  25.079 20.736 25.115 21.834 ;
     RECT  25.079 27.216 25.115 28.944 ;
     RECT  25.079 34.506 25.115 34.524 ;
     RECT  24.503 43.038 25.115 43.632 ;
     RECT  25.079 44.496 25.115 46.062 ;
     RECT  25.079 58.122 25.115 58.824 ;
     RECT  25.079 60.39 25.115 62.604 ;
     RECT  25.079 65.214 25.115 66.888 ;
     RECT  25.079 72.396 25.115 72.594 ;
     RECT  25.079 76.014 25.115 76.302 ;
     RECT  25.079 79.326 25.115 79.344 ;
     RECT  25.079 80.946 25.115 81.738 ;
     RECT  25.079 93.636 25.115 94.626 ;
     RECT  25.079 101.736 25.115 101.754 ;
     RECT  23.76 2.268 25.151 2.826 ;
     RECT  25.115 12.87 25.151 12.888 ;
     RECT  25.115 28.296 25.151 28.944 ;
     RECT  25.115 72.396 25.151 72.414 ;
     RECT  25.079 84.456 25.151 85.554 ;
     RECT  25.151 2.268 25.187 2.556 ;
     RECT  25.079 4.536 25.799 5.328 ;
     RECT  25.079 25.29 25.799 25.344 ;
     RECT  25.079 36.63 25.799 36.684 ;
     RECT  24.503 41.256 25.799 41.814 ;
     RECT  25.115 43.038 25.799 43.092 ;
     RECT  25.115 45.036 25.799 46.062 ;
     RECT  25.079 88.236 25.799 88.722 ;
     RECT  25.187 2.268 25.835 2.286 ;
     RECT  25.799 4.536 25.835 4.554 ;
     RECT  25.799 5.31 25.835 5.328 ;
     RECT  25.115 9.9 25.835 10.962 ;
     RECT  25.115 17.154 25.835 17.172 ;
     RECT  25.079 18.846 25.835 18.864 ;
     RECT  25.115 21.276 25.835 21.294 ;
     RECT  24.539 23.706 25.835 23.724 ;
     RECT  25.799 25.326 25.835 25.344 ;
     RECT  25.151 28.926 25.835 28.944 ;
     RECT  25.079 30.924 25.835 30.942 ;
     RECT  25.079 33.318 25.835 33.336 ;
     RECT  25.799 36.666 25.835 36.684 ;
     RECT  25.079 37.476 25.835 37.494 ;
     RECT  25.079 39.636 25.835 39.654 ;
     RECT  25.799 41.796 25.835 41.814 ;
     RECT  25.799 43.074 25.835 43.092 ;
     RECT  25.799 45.036 25.835 45.054 ;
     RECT  25.799 46.044 25.835 46.062 ;
     RECT  25.079 48.546 25.835 48.564 ;
     RECT  25.079 56.034 25.835 56.052 ;
     RECT  25.115 58.122 25.835 58.14 ;
     RECT  25.079 59.616 25.835 59.634 ;
     RECT  25.115 60.39 25.835 60.408 ;
     RECT  25.115 61.236 25.835 62.334 ;
     RECT  25.079 63.756 25.835 64.152 ;
     RECT  25.115 65.214 25.835 65.232 ;
     RECT  25.115 66.87 25.835 66.888 ;
     RECT  25.043 70.038 25.835 70.056 ;
     RECT  25.079 73.854 25.835 73.872 ;
     RECT  25.115 76.284 25.835 76.302 ;
     RECT  25.115 80.946 25.835 80.964 ;
     RECT  25.115 81.72 25.835 81.738 ;
     RECT  25.151 84.456 25.835 84.672 ;
     RECT  25.151 85.536 25.835 85.554 ;
     RECT  25.079 86.778 25.835 86.796 ;
     RECT  25.799 88.236 25.835 88.254 ;
     RECT  25.079 89.586 25.835 89.874 ;
     RECT  25.079 90.864 25.835 91.188 ;
     RECT  25.115 93.636 25.835 94.194 ;
     RECT  25.079 96.228 25.835 96.246 ;
     RECT  25.079 97.146 25.835 97.164 ;
     RECT  25.079 100.386 25.835 100.404 ;
    LAYER M3 ;
     RECT  2.415 2.143 2.505 2.413 ;
     RECT  7.815 2.143 7.905 2.413 ;
     RECT  13.215 2.143 13.305 2.413 ;
     RECT  18.615 2.143 18.705 2.413 ;
     RECT  22.716 2.263 23.418 2.461 ;
     RECT  25.812 2.263 25.83 2.533 ;
     RECT  22.32 2.461 23.418 2.569 ;
     RECT  25.164 2.533 25.83 2.587 ;
     RECT  24.48 2.587 25.83 2.633 ;
     RECT  2.415 2.413 2.697 2.635 ;
     RECT  24.516 2.633 25.83 2.813 ;
     RECT  18.615 2.413 18.897 2.911 ;
     RECT  0.108 2.911 0.126 2.957 ;
     RECT  3.924 2.875 4.014 3.001 ;
     RECT  21.492 2.641 21.51 3.001 ;
     RECT  22.32 2.569 23.49 3.001 ;
     RECT  4.86 2.911 4.878 3.029 ;
     RECT  21.492 3.001 23.49 3.029 ;
     RECT  3.636 3.001 4.014 3.065 ;
     RECT  9.252 2.911 9.27 3.065 ;
     RECT  3.636 3.065 3.654 3.101 ;
     RECT  21.924 3.029 23.49 3.101 ;
     RECT  7.815 2.413 8.097 3.109 ;
     RECT  18.615 2.911 18.954 3.109 ;
     RECT  20.7 2.911 20.718 3.145 ;
     RECT  14.292 3.145 14.31 3.181 ;
     RECT  18.216 3.109 19.422 3.181 ;
     RECT  24.516 2.813 25.182 3.197 ;
     RECT  14.292 3.181 14.886 3.335 ;
     RECT  21.996 3.101 23.49 3.371 ;
     RECT  20.556 3.145 20.754 3.403 ;
     RECT  18.216 3.181 19.53 3.415 ;
     RECT  24.516 3.197 25.074 3.437 ;
     RECT  20.268 3.403 20.754 3.569 ;
     RECT  22.068 3.371 23.49 3.569 ;
     RECT  7.416 3.109 8.097 3.605 ;
     RECT  13.215 2.413 13.497 3.649 ;
     RECT  18.144 3.415 19.53 3.649 ;
     RECT  20.268 3.569 20.502 3.649 ;
     RECT  11.304 3.307 11.322 3.685 ;
     RECT  2.304 2.635 2.697 3.721 ;
     RECT  9.576 3.181 9.702 3.721 ;
     RECT  11.304 3.685 12.042 3.811 ;
     RECT  12.996 3.649 13.497 3.811 ;
     RECT  11.304 3.811 13.497 3.839 ;
     RECT  25.056 3.437 25.074 3.839 ;
     RECT  9.576 3.721 9.918 3.869 ;
     RECT  18.144 3.649 20.502 3.911 ;
     RECT  2.304 3.721 2.754 3.919 ;
     RECT  11.304 3.839 12.33 3.919 ;
     RECT  13.068 3.839 13.497 3.947 ;
     RECT  13.104 3.947 13.497 3.955 ;
     RECT  14.292 3.335 14.31 3.955 ;
     RECT  18.144 3.911 20.322 3.965 ;
     RECT  10.872 3.919 12.33 3.983 ;
     RECT  23.94 3.883 23.958 4.013 ;
     RECT  2.304 3.919 3.078 4.081 ;
     RECT  13.104 3.955 14.31 4.145 ;
     RECT  2.304 4.081 3.438 4.189 ;
     RECT  2.304 4.189 3.87 4.225 ;
     RECT  2.304 4.225 4.374 4.261 ;
     RECT  13.215 4.145 14.31 4.261 ;
     RECT  22.068 3.569 23.202 4.261 ;
     RECT  24.444 4.171 24.462 4.289 ;
     RECT  2.304 4.261 4.518 4.379 ;
     RECT  17.064 3.931 17.082 4.379 ;
     RECT  21.456 4.261 23.202 4.379 ;
     RECT  13.215 4.261 14.85 4.415 ;
     RECT  10.872 3.983 11.322 4.423 ;
     RECT  21.456 4.379 23.13 4.495 ;
     RECT  25.776 4.411 25.794 4.531 ;
     RECT  18.216 3.965 20.322 4.559 ;
     RECT  2.304 4.379 4.482 4.685 ;
     RECT  5.688 4.261 5.706 4.685 ;
     RECT  25.776 4.531 25.83 4.757 ;
     RECT  3.924 4.685 4.482 5.099 ;
     RECT  0.108 5.071 0.126 5.117 ;
     RECT  17.352 4.621 17.37 5.131 ;
     RECT  18.216 4.559 18.954 5.131 ;
     RECT  21.312 4.495 23.13 5.161 ;
     RECT  25.056 4.795 25.074 5.269 ;
     RECT  25.812 4.757 25.83 5.333 ;
     RECT  3.996 5.099 4.482 5.341 ;
     RECT  21.312 5.161 23.454 5.341 ;
     RECT  2.304 4.685 2.898 5.371 ;
     RECT  12.312 3.983 12.33 5.431 ;
     RECT  13.215 4.415 14.814 5.431 ;
     RECT  17.352 5.131 18.954 5.575 ;
     RECT  19.692 4.559 20.322 5.575 ;
     RECT  12.312 5.431 14.814 5.603 ;
     RECT  13.176 5.603 14.814 5.611 ;
     RECT  21.312 5.341 23.958 5.611 ;
     RECT  25.02 5.269 25.074 5.611 ;
     RECT  16.56 5.611 16.578 5.707 ;
     RECT  17.352 5.575 20.322 5.707 ;
     RECT  3.996 5.341 4.59 5.765 ;
     RECT  13.176 5.611 14.85 5.765 ;
     RECT  2.268 5.371 2.898 5.881 ;
     RECT  3.996 5.765 4.374 5.881 ;
     RECT  5.976 5.071 5.994 5.881 ;
     RECT  21.276 5.611 25.074 5.909 ;
     RECT  16.56 5.707 20.322 5.971 ;
     RECT  21.276 5.909 23.922 5.971 ;
     RECT  2.268 5.881 4.374 6.035 ;
     RECT  24.984 5.909 25.074 6.079 ;
     RECT  5.904 5.881 5.994 6.151 ;
     RECT  16.56 5.971 23.922 6.179 ;
     RECT  24.984 6.079 25.11 6.221 ;
     RECT  2.268 6.035 2.898 6.305 ;
     RECT  5.364 6.151 5.994 6.331 ;
     RECT  24.984 6.221 25.074 6.413 ;
     RECT  12.312 5.603 12.33 6.511 ;
     RECT  12.312 6.511 12.366 6.547 ;
     RECT  13.215 5.765 14.85 6.547 ;
     RECT  16.56 6.179 23.454 6.611 ;
     RECT  5.148 6.331 5.994 6.619 ;
     RECT  3.78 6.035 4.374 6.691 ;
     RECT  5.148 6.619 6.03 6.691 ;
     RECT  9.576 3.869 9.594 6.691 ;
     RECT  10.512 4.423 11.322 6.691 ;
     RECT  2.304 6.305 2.898 6.781 ;
     RECT  3.78 6.691 6.03 6.781 ;
     RECT  12.312 6.547 14.85 6.781 ;
     RECT  24.984 6.413 25.002 6.781 ;
     RECT  2.304 6.781 6.03 6.809 ;
     RECT  16.56 6.611 23.382 6.845 ;
     RECT  12.276 6.781 14.85 6.853 ;
     RECT  24.516 6.781 25.002 7.195 ;
     RECT  12.276 6.853 14.922 7.231 ;
     RECT  16.56 6.845 23.13 7.321 ;
     RECT  24.516 7.195 25.074 7.387 ;
     RECT  2.304 6.809 5.994 7.565 ;
     RECT  24.48 7.387 25.074 7.627 ;
     RECT  2.34 7.565 5.994 7.655 ;
     RECT  16.272 7.321 23.13 7.723 ;
     RECT  16.272 7.723 23.346 7.735 ;
     RECT  24.444 7.627 25.074 7.735 ;
     RECT  16.272 7.735 25.074 7.771 ;
     RECT  16.272 7.771 25.11 7.853 ;
     RECT  9.576 6.691 11.322 7.861 ;
     RECT  12.276 7.231 15.39 7.861 ;
     RECT  0.108 7.819 0.126 7.949 ;
     RECT  16.272 7.853 25.074 8.045 ;
     RECT  7.815 3.605 8.097 8.311 ;
     RECT  9.576 7.861 15.39 8.401 ;
     RECT  7.632 8.311 8.097 8.437 ;
     RECT  2.415 7.655 5.994 8.443 ;
     RECT  1.404 4.459 1.422 8.465 ;
     RECT  7.632 8.437 8.37 8.465 ;
     RECT  7.815 8.465 8.37 8.581 ;
     RECT  7.815 8.581 8.406 8.699 ;
     RECT  7.815 8.699 8.19 8.735 ;
     RECT  16.272 8.045 23.454 8.843 ;
     RECT  2.304 8.443 5.994 8.851 ;
     RECT  24.372 8.045 25.074 8.879 ;
     RECT  2.304 8.851 6.354 9.077 ;
     RECT  5.652 9.077 6.354 9.121 ;
     RECT  5.652 9.121 6.678 9.211 ;
     RECT  22.572 8.843 23.454 9.211 ;
     RECT  9.288 8.401 15.39 9.275 ;
     RECT  5.652 9.211 6.858 9.391 ;
     RECT  7.815 8.735 8.097 9.391 ;
     RECT  22.572 9.211 23.922 9.419 ;
     RECT  5.652 9.391 7.002 9.509 ;
     RECT  7.776 9.391 8.097 9.545 ;
     RECT  22.572 9.419 23.454 9.625 ;
     RECT  2.304 9.077 4.806 9.643 ;
     RECT  16.272 8.843 21.402 9.661 ;
     RECT  22.392 9.625 23.454 9.661 ;
     RECT  25.056 8.879 25.074 9.835 ;
     RECT  25.812 9.403 25.83 9.835 ;
     RECT  9.576 9.275 15.39 9.931 ;
     RECT  25.056 9.835 25.83 9.931 ;
     RECT  2.268 9.643 4.806 10.027 ;
     RECT  5.652 9.509 6.858 10.027 ;
     RECT  24.372 9.931 25.83 10.061 ;
     RECT  2.268 10.027 6.858 10.201 ;
     RECT  1.98 10.201 6.858 10.301 ;
     RECT  25.056 10.061 25.83 10.499 ;
     RECT  2.304 10.301 6.858 10.597 ;
     RECT  9.576 9.931 15.426 10.669 ;
     RECT  16.272 9.661 23.454 10.741 ;
     RECT  2.304 10.597 6.93 10.769 ;
     RECT  16.272 10.741 23.49 10.903 ;
     RECT  2.304 10.769 6.354 10.925 ;
     RECT  25.812 10.499 25.83 10.967 ;
     RECT  7.815 9.545 8.097 11.011 ;
     RECT  25.056 10.499 25.074 11.035 ;
     RECT  24.408 11.035 25.074 11.227 ;
     RECT  8.892 10.669 15.426 11.245 ;
     RECT  24.372 11.227 25.074 11.309 ;
     RECT  8.892 11.245 15.462 11.405 ;
     RECT  16.272 10.903 23.526 11.419 ;
     RECT  2.415 10.925 6.354 11.515 ;
     RECT  7.272 11.011 8.097 11.515 ;
     RECT  25.056 11.309 25.074 11.551 ;
     RECT  2.415 11.515 8.097 11.659 ;
     RECT  8.892 11.405 15.426 11.659 ;
     RECT  2.415 11.659 15.426 11.669 ;
     RECT  2.415 11.669 6.39 11.803 ;
     RECT  16.272 11.419 23.922 11.849 ;
     RECT  2.304 11.803 6.39 12.427 ;
     RECT  1.98 12.427 6.39 12.479 ;
     RECT  1.98 12.479 3.114 12.515 ;
     RECT  1.98 12.515 2.862 12.587 ;
     RECT  25.056 11.551 25.11 12.619 ;
     RECT  3.96 12.479 6.39 12.793 ;
     RECT  7.272 11.669 15.426 12.793 ;
     RECT  3.96 12.793 15.426 12.821 ;
     RECT  24.48 12.619 25.11 12.821 ;
     RECT  25.056 12.821 25.11 12.865 ;
     RECT  16.272 11.849 23.526 13.051 ;
     RECT  16.272 13.051 23.922 13.091 ;
     RECT  3.96 12.821 15.39 13.261 ;
     RECT  25.056 12.865 25.146 13.277 ;
     RECT  25.056 13.277 25.074 13.559 ;
     RECT  3.636 13.261 15.39 13.675 ;
     RECT  16.272 13.091 23.418 13.675 ;
     RECT  3.636 13.675 23.418 13.819 ;
     RECT  24.48 13.627 24.498 13.819 ;
     RECT  2.304 12.587 2.862 13.981 ;
     RECT  3.636 13.819 24.498 13.981 ;
     RECT  2.304 13.981 24.498 14.009 ;
     RECT  2.304 14.009 23.418 14.285 ;
     RECT  0.108 14.539 0.126 14.669 ;
     RECT  24.444 14.009 24.498 14.711 ;
     RECT  4.644 14.285 23.418 14.827 ;
     RECT  2.304 14.285 3.726 15.025 ;
     RECT  2.268 15.025 3.726 15.061 ;
     RECT  4.644 14.827 23.922 15.061 ;
     RECT  2.268 15.061 23.922 15.197 ;
     RECT  25.056 14.989 25.074 15.296 ;
     RECT  2.304 15.197 23.922 15.827 ;
     RECT  2.304 15.827 23.886 15.899 ;
     RECT  2.304 15.899 23.454 15.989 ;
     RECT  2.304 15.989 23.382 16.699 ;
     RECT  2.268 16.699 23.382 16.915 ;
     RECT  25.056 16.027 25.074 16.951 ;
     RECT  25.056 16.951 25.11 17.035 ;
     RECT  2.268 16.915 23.454 17.105 ;
     RECT  25.056 17.035 25.83 17.177 ;
     RECT  25.056 17.177 25.11 17.261 ;
     RECT  0.108 17.275 0.126 17.453 ;
     RECT  2.304 17.105 23.454 17.851 ;
     RECT  25.056 17.261 25.074 17.879 ;
     RECT  2.304 17.851 23.922 18.235 ;
     RECT  2.304 18.235 24.498 18.329 ;
     RECT  25.812 18.667 25.83 18.869 ;
     RECT  4.464 18.329 24.498 19.039 ;
     RECT  4.464 19.039 25.074 19.085 ;
     RECT  4.464 19.085 24.498 19.139 ;
     RECT  4.464 19.139 24.426 19.265 ;
     RECT  2.304 18.329 3.654 19.381 ;
     RECT  0.108 18.769 0.126 19.469 ;
     RECT  4.788 19.265 24.426 19.867 ;
     RECT  4.788 19.867 25.074 19.949 ;
     RECT  4.788 19.949 23.562 20.039 ;
     RECT  2.304 19.381 3.834 20.047 ;
     RECT  2.304 20.047 3.906 20.191 ;
     RECT  4.788 20.039 23.49 20.191 ;
     RECT  2.304 20.191 23.49 20.219 ;
     RECT  4.572 20.219 23.49 20.309 ;
     RECT  24.372 19.949 25.074 20.381 ;
     RECT  24.48 20.381 25.074 20.687 ;
     RECT  25.02 20.687 25.074 20.731 ;
     RECT  2.304 20.219 3.834 20.849 ;
     RECT  25.02 20.731 25.11 20.909 ;
     RECT  4.572 20.309 23.418 21.235 ;
     RECT  25.812 21.067 25.83 21.299 ;
     RECT  2.304 20.849 3.726 21.505 ;
     RECT  4.572 21.235 23.454 21.505 ;
     RECT  25.02 20.909 25.074 21.541 ;
     RECT  2.268 21.505 3.726 21.581 ;
     RECT  2.304 21.581 3.726 21.595 ;
     RECT  4.572 21.505 23.562 21.595 ;
     RECT  2.304 21.595 23.562 21.659 ;
     RECT  4.5 21.659 23.562 21.775 ;
     RECT  24.516 21.541 25.074 21.811 ;
     RECT  24.516 21.811 25.11 21.917 ;
     RECT  4.5 21.775 23.634 22.267 ;
     RECT  24.444 22.075 24.462 22.267 ;
     RECT  2.304 21.659 3.726 22.549 ;
     RECT  4.5 22.267 24.462 22.549 ;
     RECT  0.108 22.747 0.126 22.829 ;
     RECT  2.304 22.549 24.462 22.891 ;
     RECT  2.304 22.891 24.498 23.009 ;
     RECT  2.304 23.009 23.958 23.707 ;
     RECT  25.812 22.699 25.83 23.729 ;
     RECT  2.268 23.707 23.958 23.863 ;
     RECT  2.268 23.863 24.498 23.927 ;
     RECT  2.268 23.927 23.418 23.963 ;
     RECT  24.444 23.927 24.498 24.241 ;
     RECT  24.444 24.241 24.534 24.283 ;
     RECT  2.304 23.963 23.418 24.907 ;
     RECT  24.444 24.283 25.074 24.907 ;
     RECT  2.304 24.907 25.074 25.007 ;
     RECT  2.304 25.007 23.454 25.205 ;
     RECT  0.108 25.015 0.126 25.285 ;
     RECT  24.408 25.007 25.074 25.285 ;
     RECT  25.812 25.099 25.83 25.285 ;
     RECT  24.408 25.285 25.83 25.349 ;
     RECT  0.108 25.285 0.162 25.565 ;
     RECT  1.404 21.883 1.422 25.745 ;
     RECT  0.144 25.565 0.162 25.853 ;
     RECT  24.408 25.349 25.794 26.051 ;
     RECT  25.056 26.051 25.794 26.141 ;
     RECT  4.5 25.205 23.454 26.491 ;
     RECT  4.5 26.491 23.922 26.627 ;
     RECT  25.056 26.141 25.074 27.115 ;
     RECT  2.304 25.205 3.726 27.175 ;
     RECT  4.5 26.627 23.454 27.175 ;
     RECT  24.48 27.115 25.074 27.211 ;
     RECT  2.304 27.175 23.454 27.329 ;
     RECT  2.304 27.329 23.418 27.599 ;
     RECT  24.48 27.211 25.11 27.779 ;
     RECT  25.056 27.779 25.11 27.869 ;
     RECT  25.092 27.869 25.11 28.291 ;
     RECT  25.092 28.291 25.146 28.349 ;
     RECT  25.128 28.349 25.146 28.541 ;
     RECT  2.304 27.599 23.382 28.699 ;
     RECT  25.812 28.921 25.83 29.117 ;
     RECT  0.108 28.795 0.126 29.213 ;
     RECT  2.304 28.699 23.922 29.299 ;
     RECT  2.304 29.299 23.958 29.323 ;
     RECT  2.304 29.323 24.498 29.561 ;
     RECT  2.304 29.561 23.958 29.741 ;
     RECT  25.056 29.899 25.074 30.883 ;
     RECT  25.812 30.523 25.83 30.947 ;
     RECT  2.304 29.741 23.922 31.531 ;
     RECT  25.02 30.883 25.074 31.531 ;
     RECT  0.108 31.225 0.126 31.997 ;
     RECT  2.304 31.531 25.074 32.261 ;
     RECT  24.48 32.261 25.074 32.909 ;
     RECT  25.812 33.304 25.83 33.341 ;
     RECT  25.056 32.909 25.074 33.739 ;
     RECT  2.304 32.261 23.454 33.961 ;
     RECT  24.372 33.739 25.074 33.961 ;
     RECT  1.116 33.349 1.134 34.075 ;
     RECT  2.304 33.961 25.074 34.075 ;
     RECT  0.108 33.583 0.126 34.109 ;
     RECT  1.116 34.075 25.074 34.157 ;
     RECT  24.372 34.157 25.074 34.501 ;
     RECT  24.372 34.501 25.11 34.541 ;
     RECT  1.116 34.157 23.238 34.747 ;
     RECT  1.08 34.747 23.238 34.969 ;
     RECT  1.08 34.969 23.454 35.131 ;
     RECT  24.372 34.541 25.074 35.131 ;
     RECT  0.108 35.275 0.126 35.357 ;
     RECT  1.08 35.131 25.074 35.771 ;
     RECT  25.02 35.771 25.074 35.807 ;
     RECT  25.056 35.807 25.074 36.331 ;
     RECT  25.812 36.139 25.83 36.331 ;
     RECT  1.08 35.771 23.958 36.557 ;
     RECT  25.056 36.331 25.83 36.653 ;
     RECT  1.08 36.557 23.634 36.779 ;
     RECT  25.056 36.653 25.074 36.895 ;
     RECT  25.812 36.653 25.83 37.499 ;
     RECT  24.516 36.895 25.074 37.859 ;
     RECT  1.08 36.779 23.418 38.129 ;
     RECT  22.32 38.129 23.418 38.155 ;
     RECT  24.444 37.963 24.498 38.155 ;
     RECT  22.32 38.155 24.498 38.731 ;
     RECT  22.32 38.731 25.074 39.011 ;
     RECT  1.08 38.129 21.546 39.019 ;
     RECT  22.32 39.011 23.634 39.019 ;
     RECT  24.48 39.011 25.074 39.395 ;
     RECT  0.108 39.217 0.126 39.595 ;
     RECT  25.812 39.163 25.83 39.659 ;
     RECT  1.08 39.019 23.634 39.739 ;
     RECT  1.08 39.739 23.994 40.171 ;
     RECT  25.056 39.395 25.074 40.171 ;
     RECT  1.08 40.171 25.074 40.397 ;
     RECT  0.108 39.595 0.162 40.541 ;
     RECT  0.144 40.541 0.162 40.829 ;
     RECT  1.08 40.397 24.498 40.901 ;
     RECT  25.776 41.251 25.794 41.563 ;
     RECT  1.08 40.901 23.598 41.639 ;
     RECT  25.776 41.563 25.83 41.789 ;
     RECT  25.812 41.789 25.83 41.819 ;
     RECT  1.08 41.639 23.526 42.379 ;
     RECT  24.444 40.901 24.498 42.379 ;
     RECT  1.08 42.379 24.498 42.629 ;
     RECT  25.812 42.763 25.83 42.955 ;
     RECT  25.776 42.955 25.83 43.097 ;
     RECT  24.48 42.629 24.498 43.387 ;
     RECT  1.08 42.629 23.418 43.645 ;
     RECT  1.08 43.645 23.454 43.871 ;
     RECT  21.636 43.871 23.454 43.963 ;
     RECT  24.48 43.387 25.11 43.963 ;
     RECT  21.636 43.963 25.11 44.213 ;
     RECT  1.08 43.871 20.718 44.491 ;
     RECT  24.408 44.213 25.11 44.587 ;
     RECT  21.636 44.213 23.49 44.609 ;
     RECT  1.044 44.491 20.718 44.761 ;
     RECT  21.636 44.609 23.454 44.761 ;
     RECT  24.408 44.587 25.83 44.951 ;
     RECT  25.092 44.951 25.83 45.059 ;
     RECT  1.044 44.761 23.454 45.499 ;
     RECT  1.044 45.499 23.958 45.527 ;
     RECT  22.14 45.527 23.958 45.629 ;
     RECT  22.14 45.629 23.454 45.689 ;
     RECT  0.108 43.807 0.126 45.725 ;
     RECT  25.092 45.059 25.794 45.787 ;
     RECT  22.14 45.689 23.346 45.869 ;
     RECT  25.092 45.787 25.83 46.013 ;
     RECT  25.812 46.013 25.83 46.067 ;
     RECT  1.044 45.527 21.294 46.381 ;
     RECT  22.14 45.869 23.238 46.381 ;
     RECT  1.044 46.381 23.238 46.651 ;
     RECT  1.044 46.651 23.418 46.795 ;
     RECT  24.48 46.171 25.074 46.795 ;
     RECT  1.044 46.795 25.074 47.213 ;
     RECT  1.044 47.213 24.462 47.759 ;
     RECT  0.108 48.139 0.126 48.397 ;
     RECT  25.812 48.187 25.83 48.569 ;
     RECT  0.108 48.397 0.162 48.749 ;
     RECT  1.044 47.759 23.958 49.003 ;
     RECT  25.056 47.995 25.074 49.003 ;
     RECT  1.044 49.003 25.074 49.307 ;
     RECT  1.044 49.307 23.49 50.203 ;
     RECT  24.444 49.307 25.074 50.203 ;
     RECT  0.108 48.749 0.126 50.251 ;
     RECT  1.044 50.203 25.074 50.251 ;
     RECT  0.108 50.251 25.074 50.861 ;
     RECT  0.108 50.861 23.922 51.197 ;
     RECT  25.02 50.861 25.074 51.595 ;
     RECT  0.108 51.197 23.418 51.737 ;
     RECT  1.044 51.737 23.418 52.213 ;
     RECT  24.372 51.595 25.074 52.213 ;
     RECT  1.044 52.213 25.074 52.277 ;
     RECT  1.044 52.277 23.958 52.637 ;
     RECT  0.108 51.737 0.162 52.745 ;
     RECT  1.044 52.637 23.454 52.861 ;
     RECT  0.54 52.861 23.454 53.021 ;
     RECT  25.02 52.277 25.074 53.035 ;
     RECT  24.444 53.035 25.074 53.591 ;
     RECT  1.044 53.021 23.454 53.671 ;
     RECT  1.044 53.671 23.958 53.837 ;
     RECT  1.044 53.837 23.49 54.059 ;
     RECT  0.108 53.947 0.126 54.235 ;
     RECT  1.044 54.059 23.418 54.235 ;
     RECT  25.056 53.591 25.074 54.269 ;
     RECT  24.48 54.427 24.498 54.473 ;
     RECT  0.108 54.235 23.418 54.811 ;
     RECT  0.108 54.811 24.462 55.243 ;
     RECT  0.108 55.243 25.074 55.469 ;
     RECT  0.108 55.469 23.454 55.517 ;
     RECT  25.812 55.627 25.83 56.057 ;
     RECT  1.044 55.517 23.454 56.251 ;
     RECT  24.444 55.469 25.074 56.251 ;
     RECT  1.044 56.251 25.074 56.327 ;
     RECT  24.336 56.327 25.074 56.939 ;
     RECT  1.044 56.327 23.49 57.029 ;
     RECT  24.372 56.939 25.074 57.299 ;
     RECT  1.044 57.029 23.418 57.835 ;
     RECT  24.372 57.299 24.498 57.835 ;
     RECT  0.108 55.517 0.126 58.507 ;
     RECT  1.044 57.835 24.498 58.559 ;
     RECT  24.48 58.559 24.498 58.685 ;
     RECT  25.812 58.117 25.83 58.801 ;
     RECT  25.02 58.801 25.83 58.877 ;
     RECT  25.02 58.877 25.074 59.539 ;
     RECT  25.812 58.877 25.83 59.639 ;
     RECT  24.372 59.539 25.074 59.885 ;
     RECT  1.044 58.559 23.49 60.235 ;
     RECT  24.372 59.885 24.498 60.235 ;
     RECT  0.108 58.507 0.162 60.331 ;
     RECT  1.044 60.235 24.498 60.331 ;
     RECT  0.108 60.331 24.498 60.413 ;
     RECT  1.044 60.413 24.498 60.611 ;
     RECT  1.044 60.611 23.922 60.917 ;
     RECT  1.044 60.917 23.886 60.989 ;
     RECT  25.056 60.667 25.074 61.123 ;
     RECT  25.812 60.385 25.83 61.123 ;
     RECT  25.056 61.123 25.83 61.277 ;
     RECT  25.056 61.277 25.074 61.469 ;
     RECT  0.108 60.413 0.162 61.579 ;
     RECT  1.044 60.989 23.454 61.579 ;
     RECT  0.108 61.579 23.454 61.727 ;
     RECT  24.516 61.867 24.534 62.251 ;
     RECT  25.812 61.277 25.83 62.251 ;
     RECT  24.516 62.251 25.83 62.339 ;
     RECT  1.044 61.727 23.454 62.401 ;
     RECT  24.516 62.339 25.146 62.477 ;
     RECT  0.108 61.727 0.126 62.491 ;
     RECT  1.044 62.401 23.562 62.491 ;
     RECT  0.108 62.491 23.562 62.573 ;
     RECT  24.516 62.477 25.11 62.669 ;
     RECT  1.044 62.573 23.562 63.121 ;
     RECT  24.48 62.875 24.498 63.121 ;
     RECT  1.044 63.121 24.498 63.581 ;
     RECT  24.48 63.581 24.498 63.643 ;
     RECT  24.48 63.643 25.074 63.689 ;
     RECT  1.044 63.581 23.526 64.049 ;
     RECT  25.812 63.751 25.83 64.157 ;
     RECT  25.056 63.689 25.074 64.459 ;
     RECT  1.044 64.049 23.418 64.891 ;
     RECT  24.444 64.459 25.074 64.891 ;
     RECT  25.812 65.083 25.83 65.237 ;
     RECT  1.044 64.891 25.074 65.309 ;
     RECT  25.056 65.309 25.074 65.399 ;
     RECT  1.044 65.309 24.138 65.741 ;
     RECT  1.044 65.741 23.922 65.849 ;
     RECT  0.108 62.573 0.126 66.139 ;
     RECT  1.044 65.849 23.742 66.139 ;
     RECT  25.092 65.551 25.11 66.283 ;
     RECT  0.108 66.139 23.742 66.317 ;
     RECT  25.056 66.283 25.11 66.509 ;
     RECT  1.044 66.317 23.742 66.859 ;
     RECT  25.812 66.667 25.83 66.893 ;
     RECT  0.108 66.317 0.126 67.339 ;
     RECT  1.044 66.859 23.922 67.339 ;
     RECT  0.108 67.339 23.922 67.667 ;
     RECT  1.044 67.667 23.922 67.867 ;
     RECT  0.108 67.667 0.162 68.285 ;
     RECT  25.056 66.509 25.074 68.491 ;
     RECT  25.02 68.491 25.074 68.639 ;
     RECT  1.044 67.867 24.138 68.683 ;
     RECT  25.02 68.639 25.038 68.683 ;
     RECT  1.044 68.683 25.038 68.747 ;
     RECT  1.044 68.747 24.498 69.101 ;
     RECT  0.108 68.285 0.126 69.295 ;
     RECT  1.044 69.101 23.634 69.449 ;
     RECT  0.108 69.295 0.162 69.485 ;
     RECT  0.144 69.485 0.162 69.533 ;
     RECT  25.812 69.883 25.83 70.061 ;
     RECT  24.408 69.101 24.498 70.075 ;
     RECT  1.044 69.449 23.346 70.123 ;
     RECT  0.54 70.123 23.346 70.367 ;
     RECT  1.044 70.367 23.346 70.375 ;
     RECT  1.044 70.375 23.418 70.507 ;
     RECT  24.408 70.075 25.074 70.507 ;
     RECT  1.044 70.507 25.074 71.309 ;
     RECT  1.044 71.309 23.526 71.339 ;
     RECT  1.044 71.339 23.49 71.609 ;
     RECT  0.108 71.323 0.126 71.645 ;
     RECT  24.444 71.309 25.074 71.987 ;
     RECT  24.48 71.987 25.074 72.329 ;
     RECT  25.056 72.329 25.074 72.391 ;
     RECT  1.044 71.609 23.418 72.427 ;
     RECT  1.044 72.427 23.454 72.841 ;
     RECT  1.044 72.841 23.49 73.075 ;
     RECT  25.056 72.391 25.146 73.133 ;
     RECT  25.056 73.133 25.074 73.139 ;
     RECT  1.044 73.075 23.634 73.345 ;
     RECT  24.48 73.291 24.498 73.345 ;
     RECT  1.044 73.345 24.498 73.373 ;
     RECT  25.812 73.531 25.83 73.877 ;
     RECT  1.512 73.373 24.498 73.915 ;
     RECT  1.512 73.915 25.074 73.949 ;
     RECT  0.108 74.587 0.126 74.717 ;
     RECT  1.512 73.949 23.922 74.731 ;
     RECT  25.056 73.949 25.074 74.731 ;
     RECT  1.512 74.731 25.074 74.993 ;
     RECT  1.584 74.993 25.074 75.533 ;
     RECT  1.692 75.533 25.074 75.731 ;
     RECT  25.056 75.731 25.074 76.009 ;
     RECT  25.812 75.739 25.83 76.009 ;
     RECT  25.056 76.009 25.83 76.157 ;
     RECT  25.812 76.157 25.83 76.307 ;
     RECT  1.692 75.731 23.922 76.379 ;
     RECT  1.692 76.379 23.562 76.469 ;
     RECT  25.056 76.157 25.074 76.507 ;
     RECT  25.02 76.507 25.074 76.699 ;
     RECT  24.336 76.699 25.074 77.621 ;
     RECT  1.692 76.469 23.418 77.707 ;
     RECT  1.692 77.707 23.922 78.367 ;
     RECT  1.404 78.367 23.922 78.539 ;
     RECT  0.108 76.585 0.126 78.701 ;
     RECT  25.02 77.621 25.074 78.955 ;
     RECT  1.404 78.539 23.454 79.169 ;
     RECT  24.372 78.955 25.074 79.321 ;
     RECT  24.372 79.321 25.11 79.373 ;
     RECT  0.036 79.213 0.054 79.555 ;
     RECT  24.372 79.373 25.074 79.619 ;
     RECT  0.036 79.555 0.126 79.901 ;
     RECT  1.404 79.169 23.274 79.915 ;
     RECT  25.056 79.619 25.074 79.979 ;
     RECT  1.404 79.915 23.922 80.095 ;
     RECT  25.092 80.347 25.11 80.923 ;
     RECT  25.092 80.923 25.83 81.131 ;
     RECT  0.828 80.095 23.922 81.139 ;
     RECT  0.828 81.139 25.074 81.197 ;
     RECT  0.828 81.197 23.922 81.671 ;
     RECT  25.812 81.131 25.83 81.743 ;
     RECT  25.056 81.197 25.074 81.931 ;
     RECT  25.02 81.931 25.074 82.123 ;
     RECT  24.372 82.123 25.074 82.247 ;
     RECT  0.828 81.671 23.454 82.409 ;
     RECT  24.48 82.247 25.074 82.949 ;
     RECT  24.48 82.949 24.57 82.973 ;
     RECT  0.036 79.901 0.054 83.497 ;
     RECT  0.828 82.409 23.418 83.497 ;
     RECT  0.036 83.497 23.418 83.569 ;
     RECT  24.48 82.973 24.498 83.569 ;
     RECT  0.036 83.569 24.498 83.789 ;
     RECT  23.94 83.789 24.498 83.981 ;
     RECT  24.48 83.981 24.498 84.173 ;
     RECT  0.036 83.789 23.13 84.613 ;
     RECT  0.036 84.613 23.382 84.955 ;
     RECT  0.036 84.955 23.49 85.085 ;
     RECT  0.828 85.085 23.49 85.109 ;
     RECT  24.48 84.955 24.498 85.147 ;
     RECT  24.48 85.147 25.074 85.181 ;
     RECT  25.056 85.181 25.074 85.261 ;
     RECT  25.812 84.379 25.83 85.261 ;
     RECT  25.056 85.261 25.83 85.805 ;
     RECT  0.828 85.109 23.274 86.305 ;
     RECT  0.828 86.305 23.418 86.347 ;
     RECT  0.828 86.347 23.922 86.495 ;
     RECT  18.54 86.495 23.922 86.503 ;
     RECT  25.056 85.805 25.074 86.503 ;
     RECT  18.54 86.503 25.074 86.639 ;
     RECT  18.54 86.639 23.418 86.729 ;
     RECT  0.036 85.085 0.054 86.773 ;
     RECT  0.828 86.495 17.73 86.773 ;
     RECT  25.812 85.805 25.83 86.801 ;
     RECT  0.036 86.773 17.73 87.241 ;
     RECT  18.54 86.729 23.274 87.241 ;
     RECT  0.036 87.241 23.274 87.511 ;
     RECT  24.336 86.639 25.074 87.809 ;
     RECT  0.036 87.511 23.418 87.821 ;
     RECT  24.336 87.809 24.39 87.917 ;
     RECT  25.812 87.979 25.83 88.171 ;
     RECT  0.828 87.821 23.418 88.195 ;
     RECT  25.776 88.171 25.83 88.259 ;
     RECT  0.828 88.195 23.958 88.397 ;
     RECT  25.776 88.259 25.794 88.727 ;
     RECT  0.036 87.821 0.054 88.897 ;
     RECT  0.828 88.397 23.454 88.897 ;
     RECT  0.036 88.897 23.454 89.069 ;
     RECT  0.828 89.069 23.454 89.179 ;
     RECT  0.828 89.179 23.922 89.267 ;
     RECT  25.812 89.371 25.83 89.879 ;
     RECT  25.056 88.771 25.074 89.969 ;
     RECT  0.828 89.267 23.418 90.121 ;
     RECT  0.828 90.121 23.958 90.617 ;
     RECT  0.828 90.617 23.346 90.689 ;
     RECT  17.28 90.689 23.238 90.779 ;
     RECT  0.036 89.069 0.054 90.895 ;
     RECT  0.828 90.689 16.29 90.895 ;
     RECT  0.036 90.895 16.29 91.181 ;
     RECT  25.812 90.763 25.83 91.229 ;
     RECT  17.424 90.779 23.238 91.319 ;
     RECT  24.48 90.931 24.498 91.387 ;
     RECT  1.404 91.181 16.29 91.517 ;
     RECT  24.48 91.387 25.074 91.579 ;
     RECT  24.372 91.579 25.074 91.741 ;
     RECT  23.94 91.741 25.074 91.859 ;
     RECT  0.036 91.181 0.162 91.895 ;
     RECT  17.424 91.319 23.202 91.895 ;
     RECT  21.96 91.895 23.202 92.137 ;
     RECT  23.94 91.859 24.498 92.137 ;
     RECT  0.108 91.895 0.162 92.429 ;
     RECT  21.96 92.137 24.498 92.741 ;
     RECT  17.424 91.895 21.114 92.923 ;
     RECT  17.244 92.923 21.114 92.971 ;
     RECT  24.444 92.741 24.498 93.019 ;
     RECT  1.44 91.517 16.29 93.055 ;
     RECT  17.1 92.971 21.114 93.055 ;
     RECT  21.96 92.741 23.346 93.055 ;
     RECT  0.144 92.429 0.162 93.595 ;
     RECT  1.404 93.055 16.29 93.629 ;
     RECT  2.304 93.629 16.29 93.865 ;
     RECT  17.1 93.055 23.346 93.865 ;
     RECT  24.444 93.019 25.074 93.979 ;
     RECT  2.304 93.865 23.346 94.135 ;
     RECT  24.336 93.979 25.074 94.135 ;
     RECT  2.304 94.135 25.074 94.253 ;
     RECT  24.336 94.253 25.074 94.469 ;
     RECT  0.108 93.595 0.162 94.541 ;
     RECT  24.48 94.469 25.074 94.603 ;
     RECT  25.812 93.403 25.83 94.603 ;
     RECT  24.48 94.603 25.83 94.733 ;
     RECT  24.48 94.733 25.11 94.829 ;
     RECT  24.48 94.829 25.074 95.419 ;
     RECT  2.304 94.253 23.418 95.719 ;
     RECT  24.444 95.419 25.074 95.719 ;
     RECT  2.304 95.719 25.074 95.819 ;
     RECT  15.66 95.819 25.074 95.837 ;
     RECT  2.304 95.819 14.886 95.945 ;
     RECT  2.34 95.945 14.886 96.179 ;
     RECT  25.812 95.611 25.83 96.251 ;
     RECT  0.108 94.541 0.126 96.413 ;
     RECT  1.404 93.629 1.458 96.565 ;
     RECT  15.66 95.837 23.418 96.565 ;
     RECT  15.66 96.565 23.49 96.601 ;
     RECT  2.34 96.179 6.894 96.667 ;
     RECT  2.304 96.667 6.894 96.755 ;
     RECT  15.66 96.601 23.562 96.989 ;
     RECT  25.812 97.003 25.83 97.169 ;
     RECT  24.444 95.837 25.074 97.195 ;
     RECT  24.372 97.195 25.074 97.529 ;
     RECT  7.668 96.179 14.886 97.537 ;
     RECT  15.66 96.989 23.49 97.537 ;
     RECT  1.404 96.565 1.494 97.613 ;
     RECT  7.668 97.537 23.49 97.681 ;
     RECT  24.372 97.529 25.038 97.799 ;
     RECT  7.632 97.681 23.49 97.819 ;
     RECT  24.372 97.799 24.534 97.819 ;
     RECT  2.304 96.755 6.786 97.915 ;
     RECT  7.632 97.819 24.534 97.915 ;
     RECT  2.304 97.915 24.534 98.669 ;
     RECT  1.44 97.613 1.494 98.813 ;
     RECT  2.304 98.669 24.498 99.149 ;
     RECT  0.036 97.645 0.054 99.157 ;
     RECT  0.036 99.157 0.126 99.437 ;
     RECT  2.415 99.149 24.498 99.725 ;
     RECT  1.476 98.813 1.494 99.773 ;
     RECT  5.688 99.725 24.498 99.773 ;
     RECT  2.415 99.725 4.914 100.075 ;
     RECT  0.036 99.437 0.054 100.237 ;
     RECT  7.704 99.773 24.498 100.301 ;
     RECT  25.812 100.075 25.83 100.409 ;
     RECT  7.704 100.301 23.706 100.499 ;
     RECT  7.704 100.499 23.49 100.535 ;
     RECT  0.036 100.237 0.126 100.541 ;
     RECT  7.704 100.535 23.418 100.607 ;
     RECT  24.444 100.301 24.498 100.637 ;
     RECT  2.304 100.075 4.914 100.651 ;
     RECT  5.688 99.773 6.75 100.651 ;
     RECT  24.48 100.637 24.498 100.843 ;
     RECT  2.304 100.651 6.75 101.155 ;
     RECT  16.164 100.607 23.418 101.309 ;
     RECT  2.304 101.155 6.822 101.317 ;
     RECT  7.704 100.607 15.102 101.317 ;
     RECT  24.48 100.843 25.074 101.371 ;
     RECT  0.036 100.541 0.054 101.425 ;
     RECT  2.304 101.317 15.102 101.461 ;
     RECT  24.444 101.371 25.074 101.489 ;
     RECT  2.304 101.461 15.174 101.687 ;
     RECT  24.48 101.489 25.074 101.731 ;
     RECT  24.48 101.731 25.11 102.221 ;
     RECT  16.164 101.309 23.31 102.271 ;
     RECT  2.304 101.687 14.958 102.475 ;
     RECT  16.164 102.271 23.346 102.541 ;
     RECT  2.304 102.475 15.21 102.631 ;
     RECT  16.128 102.541 23.562 102.631 ;
     RECT  0.036 101.425 0.126 102.653 ;
     RECT  2.304 102.631 23.562 102.659 ;
     RECT  0.108 102.653 0.126 102.749 ;
     RECT  24.48 102.221 25.074 102.767 ;
     RECT  24.48 102.767 25.038 103.037 ;
     RECT  2.304 102.659 23.454 103.073 ;
     RECT  25.02 103.037 25.038 103.109 ;
     RECT  2.415 103.073 23.454 103.199 ;
     RECT  2.415 103.199 23.058 103.343 ;
     RECT  21.672 103.343 23.058 103.469 ;
     RECT  21.744 103.469 22.806 103.505 ;
     RECT  21.96 103.505 22.806 103.613 ;
     RECT  2.415 103.343 20.61 103.649 ;
     RECT  2.415 103.649 18.882 103.661 ;
     RECT  19.692 103.649 20.61 103.661 ;
     RECT  2.415 103.661 8.37 103.697 ;
     RECT  9.216 103.661 13.878 103.697 ;
     RECT  2.664 103.697 8.37 103.709 ;
     RECT  14.616 103.661 18.882 103.709 ;
     RECT  19.692 103.661 20.466 103.739 ;
     RECT  2.664 103.709 8.262 103.757 ;
     RECT  9.216 103.697 12.726 103.757 ;
     RECT  14.616 103.709 16.902 103.757 ;
     RECT  17.64 103.709 18.882 103.757 ;
     RECT  21.996 103.613 22.806 103.757 ;
     RECT  2.664 103.757 2.682 103.805 ;
     RECT  7.776 103.757 7.794 103.853 ;
     RECT  9.288 103.757 10.458 104.333 ;
     RECT  11.304 103.757 11.646 104.333 ;
     RECT  17.64 103.757 18.846 104.381 ;
     RECT  17.64 104.381 17.982 104.861 ;
     RECT  22.608 103.757 22.806 104.861 ;
     RECT  10.44 104.333 10.458 104.909 ;
     RECT  11.628 104.333 11.646 104.909 ;
     RECT  14.796 103.757 16.902 104.909 ;
     RECT  19.692 103.739 20.214 104.909 ;
     RECT  22.788 104.861 22.806 104.909 ;
     RECT  12.456 103.757 12.726 104.957 ;
     RECT  19.692 104.909 20.142 105.629 ;
     RECT  13.536 103.697 13.878 105.677 ;
     RECT  19.692 105.629 19.818 105.677 ;
     RECT  12.456 104.957 12.474 105.725 ;
     RECT  13.536 105.677 13.554 105.725 ;
     RECT  15.264 104.909 15.282 105.725 ;
     RECT  16.452 104.909 16.902 105.725 ;
     RECT  17.64 104.861 17.658 105.725 ;
     RECT  18.828 104.381 18.846 105.725 ;
     RECT  19.692 105.677 19.71 105.725 ;
    LAYER M4 ;
     RECT  0.025 102.624 0.06 102.648 ;
     RECT  0.084 2.64 0.137 2.664 ;
     RECT  0.06 2.664 0.137 2.928 ;
     RECT  0.084 2.928 0.137 2.952 ;
     RECT  0.06 2.952 0.137 3.264 ;
     RECT  0.084 3.264 0.137 3.288 ;
     RECT  0.06 3.288 0.137 3.552 ;
     RECT  0.084 3.552 0.137 3.576 ;
     RECT  0.06 3.576 0.137 3.84 ;
     RECT  0.084 3.84 0.137 3.864 ;
     RECT  0.06 3.864 0.137 4.176 ;
     RECT  0.084 4.176 0.137 4.2 ;
     RECT  0.06 4.2 0.137 4.464 ;
     RECT  0.084 4.464 0.137 4.488 ;
     RECT  0.06 4.488 0.137 4.8 ;
     RECT  0.084 4.8 0.137 4.824 ;
     RECT  0.06 4.824 0.137 5.088 ;
     RECT  0.084 5.088 0.137 5.112 ;
     RECT  0.06 5.112 0.137 5.376 ;
     RECT  0.084 5.376 0.137 5.4 ;
     RECT  0.06 5.4 0.137 5.712 ;
     RECT  0.084 5.712 0.137 5.736 ;
     RECT  0.06 5.736 0.137 6 ;
     RECT  0.084 6 0.137 6.024 ;
     RECT  0.06 6.024 0.137 6.288 ;
     RECT  0.084 6.288 0.137 6.312 ;
     RECT  0.06 6.312 0.137 6.624 ;
     RECT  0.084 6.624 0.137 6.648 ;
     RECT  0.06 6.648 0.137 6.912 ;
     RECT  0.084 6.912 0.137 6.936 ;
     RECT  0.06 6.936 0.137 7.2 ;
     RECT  0.084 7.2 0.137 7.224 ;
     RECT  0.06 7.224 0.137 7.536 ;
     RECT  0.084 7.536 0.137 7.56 ;
     RECT  0.06 7.56 0.137 7.824 ;
     RECT  0.084 7.824 0.137 7.848 ;
     RECT  0.06 7.848 0.137 8.16 ;
     RECT  0.084 8.16 0.137 8.184 ;
     RECT  0.06 8.184 0.137 8.448 ;
     RECT  0.084 8.448 0.137 8.472 ;
     RECT  0.06 8.472 0.137 8.736 ;
     RECT  0.084 8.736 0.137 8.76 ;
     RECT  0.06 8.76 0.137 9.072 ;
     RECT  0.084 9.072 0.137 9.096 ;
     RECT  0.06 9.096 0.137 9.36 ;
     RECT  0.084 9.36 0.137 9.384 ;
     RECT  0.06 9.384 0.137 9.648 ;
     RECT  0.084 9.648 0.137 9.672 ;
     RECT  0.06 9.672 0.137 9.984 ;
     RECT  0.084 9.984 0.137 10.008 ;
     RECT  0.06 10.008 0.137 10.272 ;
     RECT  0.084 10.272 0.137 10.296 ;
     RECT  0.06 10.296 0.137 10.56 ;
     RECT  0.084 10.56 0.137 10.584 ;
     RECT  0.06 10.584 0.137 10.896 ;
     RECT  0.084 10.896 0.137 10.92 ;
     RECT  0.06 10.92 0.137 11.184 ;
     RECT  0.084 11.184 0.137 11.208 ;
     RECT  0.06 11.208 0.137 11.472 ;
     RECT  0.084 11.472 0.137 11.496 ;
     RECT  0.06 11.496 0.137 11.808 ;
     RECT  0.084 11.808 0.137 11.832 ;
     RECT  0.06 11.832 0.137 12.096 ;
     RECT  0.084 12.096 0.137 12.12 ;
     RECT  0.06 12.12 0.137 12.432 ;
     RECT  0.084 12.432 0.137 12.456 ;
     RECT  0.06 12.456 0.137 12.72 ;
     RECT  0.084 12.72 0.137 12.744 ;
     RECT  0.06 12.744 0.137 13.008 ;
     RECT  0.084 13.008 0.137 13.032 ;
     RECT  0.06 13.032 0.137 13.344 ;
     RECT  0.084 13.344 0.137 13.368 ;
     RECT  0.06 13.368 0.137 13.632 ;
     RECT  0.084 13.632 0.137 13.656 ;
     RECT  0.06 13.656 0.137 13.92 ;
     RECT  0.084 13.92 0.137 13.944 ;
     RECT  0.06 13.944 0.137 14.256 ;
     RECT  0.084 14.256 0.137 14.28 ;
     RECT  0.06 14.28 0.137 14.544 ;
     RECT  0.084 14.544 0.137 14.568 ;
     RECT  0.06 14.568 0.137 14.832 ;
     RECT  0.084 14.832 0.137 14.856 ;
     RECT  0.06 14.856 0.137 15.168 ;
     RECT  0.084 15.168 0.137 15.192 ;
     RECT  0.06 15.192 0.137 15.456 ;
     RECT  0.084 15.456 0.137 15.48 ;
     RECT  0.06 15.48 0.137 15.792 ;
     RECT  0.084 15.792 0.137 15.816 ;
     RECT  0.06 15.816 0.137 16.08 ;
     RECT  0.084 16.08 0.137 16.104 ;
     RECT  0.06 16.104 0.137 16.368 ;
     RECT  0.084 16.368 0.137 16.392 ;
     RECT  0.06 16.392 0.137 16.704 ;
     RECT  0.084 16.704 0.137 16.728 ;
     RECT  0.06 16.728 0.137 16.992 ;
     RECT  0.084 16.992 0.137 17.016 ;
     RECT  0.06 17.016 0.137 17.28 ;
     RECT  0.084 17.28 0.137 17.304 ;
     RECT  0.06 17.304 0.137 17.616 ;
     RECT  0.084 17.616 0.137 17.64 ;
     RECT  0.06 17.64 0.137 17.904 ;
     RECT  0.084 17.904 0.137 17.928 ;
     RECT  0.06 17.928 0.137 18.192 ;
     RECT  0.084 18.192 0.137 18.216 ;
     RECT  0.06 18.216 0.137 18.528 ;
     RECT  0.084 18.528 0.137 18.552 ;
     RECT  0.06 18.552 0.137 18.816 ;
     RECT  0.084 18.816 0.137 18.84 ;
     RECT  0.06 18.84 0.137 19.104 ;
     RECT  0.084 19.104 0.137 19.128 ;
     RECT  0.06 19.128 0.137 19.44 ;
     RECT  0.084 19.44 0.137 19.464 ;
     RECT  0.06 19.464 0.137 19.728 ;
     RECT  0.084 19.728 0.137 19.752 ;
     RECT  0.06 19.752 0.137 20.064 ;
     RECT  0.084 20.064 0.137 20.088 ;
     RECT  0.06 20.088 0.137 20.352 ;
     RECT  0.084 20.352 0.137 20.376 ;
     RECT  0.06 20.376 0.137 20.64 ;
     RECT  0.084 20.64 0.137 20.664 ;
     RECT  0.06 20.664 0.137 20.976 ;
     RECT  0.084 20.976 0.137 21 ;
     RECT  0.06 21 0.137 21.264 ;
     RECT  0.084 21.264 0.137 21.288 ;
     RECT  0.06 21.288 0.137 21.552 ;
     RECT  0.084 21.552 0.137 21.576 ;
     RECT  0.06 21.576 0.137 21.888 ;
     RECT  0.084 21.888 0.137 21.912 ;
     RECT  0.06 21.912 0.137 22.176 ;
     RECT  0.084 22.176 0.137 22.2 ;
     RECT  0.06 22.2 0.137 22.464 ;
     RECT  0.084 22.464 0.137 22.488 ;
     RECT  0.06 22.488 0.137 22.8 ;
     RECT  0.084 22.8 0.137 22.824 ;
     RECT  0.06 22.824 0.137 23.088 ;
     RECT  0.084 23.088 0.137 23.112 ;
     RECT  0.06 23.112 0.137 23.424 ;
     RECT  0.084 23.424 0.137 23.448 ;
     RECT  0.06 23.448 0.137 23.712 ;
     RECT  0.084 23.712 0.137 23.736 ;
     RECT  0.06 23.736 0.137 24 ;
     RECT  0.084 24 0.137 24.024 ;
     RECT  0.06 24.024 0.137 24.336 ;
     RECT  0.084 24.336 0.137 24.36 ;
     RECT  0.06 24.36 0.137 24.624 ;
     RECT  0.084 24.624 0.137 24.648 ;
     RECT  0.06 24.648 0.137 24.912 ;
     RECT  0.084 24.912 0.137 24.936 ;
     RECT  0.06 24.936 0.137 25.248 ;
     RECT  0.084 25.248 0.137 25.272 ;
     RECT  0.06 25.272 0.137 25.536 ;
     RECT  0.084 25.536 0.137 25.56 ;
     RECT  0.06 25.56 0.137 25.824 ;
     RECT  0.084 25.824 0.137 25.848 ;
     RECT  0.06 25.848 0.137 26.16 ;
     RECT  0.084 26.16 0.137 26.184 ;
     RECT  0.06 26.184 0.137 26.448 ;
     RECT  0.084 26.448 0.137 26.472 ;
     RECT  0.06 26.472 0.137 26.736 ;
     RECT  0.084 26.736 0.137 26.76 ;
     RECT  0.06 26.76 0.137 27.072 ;
     RECT  0.084 27.072 0.137 27.096 ;
     RECT  0.06 27.096 0.137 27.36 ;
     RECT  0.084 27.36 0.137 27.384 ;
     RECT  0.06 27.384 0.137 27.696 ;
     RECT  0.084 27.696 0.137 27.72 ;
     RECT  0.06 27.72 0.137 27.984 ;
     RECT  0.084 27.984 0.137 28.008 ;
     RECT  0.06 28.008 0.137 28.272 ;
     RECT  0.084 28.272 0.137 28.296 ;
     RECT  0.06 28.296 0.137 28.608 ;
     RECT  0.084 28.608 0.137 28.632 ;
     RECT  0.06 28.632 0.137 28.896 ;
     RECT  0.084 28.896 0.137 28.92 ;
     RECT  0.06 28.92 0.137 29.184 ;
     RECT  0.084 29.184 0.137 29.208 ;
     RECT  0.06 29.208 0.137 29.52 ;
     RECT  0.084 29.52 0.137 29.544 ;
     RECT  0.06 29.544 0.137 29.808 ;
     RECT  0.084 29.808 0.137 29.832 ;
     RECT  0.06 29.832 0.137 30.096 ;
     RECT  0.084 30.096 0.137 30.12 ;
     RECT  0.06 30.12 0.137 30.432 ;
     RECT  0.084 30.432 0.137 30.456 ;
     RECT  0.06 30.456 0.137 30.72 ;
     RECT  0.084 30.72 0.137 30.744 ;
     RECT  0.06 30.744 0.137 31.056 ;
     RECT  0.084 31.056 0.137 31.08 ;
     RECT  0.06 31.08 0.137 31.344 ;
     RECT  0.084 31.344 0.137 31.368 ;
     RECT  0.06 31.368 0.137 31.632 ;
     RECT  0.084 31.632 0.137 31.656 ;
     RECT  0.06 31.656 0.137 31.968 ;
     RECT  0.084 31.968 0.137 31.992 ;
     RECT  0.06 31.992 0.137 32.256 ;
     RECT  0.084 32.256 0.137 32.28 ;
     RECT  0.06 32.28 0.137 32.544 ;
     RECT  0.084 32.544 0.137 32.568 ;
     RECT  0.06 32.568 0.137 32.88 ;
     RECT  0.084 32.88 0.137 32.904 ;
     RECT  0.06 32.904 0.137 33.168 ;
     RECT  0.084 33.168 0.137 33.192 ;
     RECT  0.06 33.192 0.137 33.456 ;
     RECT  0.084 33.456 0.137 33.48 ;
     RECT  0.06 33.48 0.137 33.792 ;
     RECT  0.084 33.792 0.137 33.816 ;
     RECT  0.06 33.816 0.137 34.08 ;
     RECT  0.084 34.08 0.137 34.104 ;
     RECT  0.06 34.104 0.137 34.368 ;
     RECT  0.084 34.368 0.137 34.392 ;
     RECT  0.06 34.392 0.137 34.704 ;
     RECT  0.084 34.704 0.137 34.728 ;
     RECT  0.06 34.728 0.137 34.992 ;
     RECT  0.084 34.992 0.137 35.016 ;
     RECT  0.06 35.016 0.137 35.328 ;
     RECT  0.084 35.328 0.137 35.352 ;
     RECT  0.06 35.352 0.137 35.616 ;
     RECT  0.084 35.616 0.137 35.64 ;
     RECT  0.06 35.64 0.137 35.904 ;
     RECT  0.084 35.904 0.137 35.928 ;
     RECT  0.06 35.928 0.137 36.24 ;
     RECT  0.084 36.24 0.137 36.264 ;
     RECT  0.06 36.264 0.137 36.528 ;
     RECT  0.084 36.528 0.137 36.552 ;
     RECT  0.06 36.552 0.137 36.816 ;
     RECT  0.084 36.816 0.137 36.84 ;
     RECT  0.06 36.84 0.137 37.152 ;
     RECT  0.084 37.152 0.137 37.176 ;
     RECT  0.06 37.176 0.137 37.44 ;
     RECT  0.084 37.44 0.137 37.464 ;
     RECT  0.06 37.464 0.137 37.728 ;
     RECT  0.084 37.728 0.137 37.752 ;
     RECT  0.06 37.752 0.137 38.064 ;
     RECT  0.084 38.064 0.137 38.088 ;
     RECT  0.06 38.088 0.137 38.352 ;
     RECT  0.084 38.352 0.137 38.376 ;
     RECT  0.06 38.376 0.137 38.688 ;
     RECT  0.084 38.688 0.137 38.712 ;
     RECT  0.06 38.712 0.137 38.976 ;
     RECT  0.084 38.976 0.137 39 ;
     RECT  0.06 39 0.137 39.264 ;
     RECT  0.084 39.264 0.137 39.288 ;
     RECT  0.06 39.288 0.137 39.6 ;
     RECT  0.084 39.6 0.137 39.624 ;
     RECT  0.06 39.624 0.137 39.888 ;
     RECT  0.084 39.888 0.137 39.912 ;
     RECT  0.06 39.912 0.137 40.176 ;
     RECT  0.084 40.176 0.137 40.2 ;
     RECT  0.06 40.2 0.137 40.512 ;
     RECT  0.084 40.512 0.137 40.536 ;
     RECT  0.06 40.536 0.137 40.8 ;
     RECT  0.084 40.8 0.137 40.824 ;
     RECT  0.06 40.824 0.137 41.088 ;
     RECT  0.084 41.088 0.137 41.112 ;
     RECT  0.06 41.112 0.137 41.424 ;
     RECT  0.084 41.424 0.137 41.448 ;
     RECT  0.06 41.448 0.137 41.712 ;
     RECT  0.084 41.712 0.137 41.736 ;
     RECT  0.06 41.736 0.137 42 ;
     RECT  0.084 42 0.137 42.024 ;
     RECT  0.06 42.024 0.137 42.336 ;
     RECT  0.084 42.336 0.137 42.36 ;
     RECT  0.06 42.36 0.137 42.624 ;
     RECT  0.084 42.624 0.137 42.648 ;
     RECT  0.06 42.648 0.137 42.96 ;
     RECT  0.084 42.96 0.137 42.984 ;
     RECT  0.06 42.984 0.137 43.248 ;
     RECT  0.084 43.248 0.137 43.272 ;
     RECT  0.06 43.272 0.137 43.536 ;
     RECT  0.084 43.536 0.137 43.56 ;
     RECT  0.06 43.56 0.137 43.872 ;
     RECT  0.084 43.872 0.137 43.896 ;
     RECT  0.06 43.896 0.137 44.16 ;
     RECT  0.084 44.16 0.137 44.184 ;
     RECT  0.06 44.184 0.137 44.448 ;
     RECT  0.084 44.448 0.137 44.472 ;
     RECT  0.06 44.472 0.137 44.784 ;
     RECT  0.084 44.784 0.137 44.808 ;
     RECT  0.06 44.808 0.137 45.072 ;
     RECT  0.084 45.072 0.137 45.096 ;
     RECT  0.06 45.096 0.137 45.36 ;
     RECT  0.084 45.36 0.137 45.384 ;
     RECT  0.06 45.384 0.137 45.696 ;
     RECT  0.084 45.696 0.137 45.72 ;
     RECT  0.06 45.72 0.137 45.984 ;
     RECT  0.084 45.984 0.137 46.008 ;
     RECT  0.06 46.008 0.137 46.32 ;
     RECT  0.084 46.32 0.137 46.344 ;
     RECT  0.06 46.344 0.137 46.608 ;
     RECT  0.084 46.608 0.137 46.632 ;
     RECT  0.06 46.632 0.137 46.896 ;
     RECT  0.084 46.896 0.137 46.92 ;
     RECT  0.06 46.92 0.137 47.232 ;
     RECT  0.084 47.232 0.137 47.256 ;
     RECT  0.06 47.256 0.137 47.52 ;
     RECT  0.084 47.52 0.137 47.544 ;
     RECT  0.06 47.544 0.137 47.808 ;
     RECT  0.084 47.808 0.137 47.832 ;
     RECT  0.06 47.832 0.137 48.144 ;
     RECT  0.084 48.144 0.137 48.168 ;
     RECT  0.06 48.168 0.137 48.432 ;
     RECT  0.084 48.432 0.137 48.456 ;
     RECT  0.06 48.456 0.137 48.72 ;
     RECT  0.084 48.72 0.137 48.744 ;
     RECT  0.06 48.744 0.137 49.056 ;
     RECT  0.084 49.056 0.137 49.08 ;
     RECT  0.06 49.08 0.137 49.344 ;
     RECT  0.084 49.344 0.137 49.368 ;
     RECT  0.06 49.368 0.137 49.632 ;
     RECT  0.084 49.632 0.137 49.656 ;
     RECT  0.06 49.656 0.137 49.968 ;
     RECT  0.084 49.968 0.137 49.992 ;
     RECT  0.06 49.992 0.137 50.256 ;
     RECT  0.084 50.256 0.137 50.28 ;
     RECT  0.06 50.28 0.137 50.592 ;
     RECT  0.084 50.592 0.137 50.616 ;
     RECT  0.06 50.616 0.137 50.88 ;
     RECT  0.084 50.88 0.137 50.904 ;
     RECT  0.06 50.904 0.137 51.168 ;
     RECT  0.084 51.168 0.137 51.192 ;
     RECT  0.06 51.192 0.137 51.504 ;
     RECT  0.084 51.504 0.137 51.528 ;
     RECT  0.06 51.528 0.137 51.792 ;
     RECT  0.084 51.792 0.137 51.816 ;
     RECT  0.06 51.816 0.137 52.08 ;
     RECT  0.084 52.08 0.137 52.104 ;
     RECT  0.06 52.104 0.137 52.416 ;
     RECT  0.084 52.416 0.137 52.44 ;
     RECT  0.06 52.44 0.137 52.704 ;
     RECT  0.084 52.704 0.137 52.728 ;
     RECT  0.06 52.728 0.137 52.992 ;
     RECT  0.084 52.992 0.137 53.016 ;
     RECT  0.06 53.016 0.137 53.328 ;
     RECT  0.084 53.328 0.137 53.352 ;
     RECT  0.06 53.352 0.137 53.616 ;
     RECT  0.084 53.616 0.137 53.64 ;
     RECT  0.06 53.64 0.137 53.952 ;
     RECT  0.084 53.952 0.137 53.976 ;
     RECT  0.06 53.976 0.137 54.24 ;
     RECT  0.084 54.24 0.137 54.264 ;
     RECT  0.06 54.264 0.137 54.528 ;
     RECT  0.084 54.528 0.137 54.552 ;
     RECT  0.06 54.552 0.137 54.864 ;
     RECT  0.084 54.864 0.137 54.888 ;
     RECT  0.06 54.888 0.137 55.152 ;
     RECT  0.084 55.152 0.137 55.176 ;
     RECT  0.06 55.176 0.137 55.44 ;
     RECT  0.084 55.44 0.137 55.464 ;
     RECT  0.06 55.464 0.137 55.776 ;
     RECT  0.084 55.776 0.137 55.8 ;
     RECT  0.06 55.8 0.137 56.064 ;
     RECT  0.084 56.064 0.137 56.088 ;
     RECT  0.06 56.088 0.137 56.352 ;
     RECT  0.084 56.352 0.137 56.376 ;
     RECT  0.06 56.376 0.137 56.688 ;
     RECT  0.084 56.688 0.137 56.712 ;
     RECT  0.06 56.712 0.137 56.976 ;
     RECT  0.084 56.976 0.137 57 ;
     RECT  0.06 57 0.137 57.264 ;
     RECT  0.084 57.264 0.137 57.288 ;
     RECT  0.06 57.288 0.137 57.6 ;
     RECT  0.084 57.6 0.137 57.624 ;
     RECT  0.06 57.624 0.137 57.888 ;
     RECT  0.084 57.888 0.137 57.912 ;
     RECT  0.06 57.912 0.137 58.224 ;
     RECT  0.084 58.224 0.137 58.248 ;
     RECT  0.06 58.248 0.137 58.512 ;
     RECT  0.084 58.512 0.137 58.536 ;
     RECT  0.06 58.536 0.137 58.8 ;
     RECT  0.084 58.8 0.137 58.824 ;
     RECT  0.06 58.824 0.137 59.136 ;
     RECT  0.084 59.136 0.137 59.16 ;
     RECT  0.06 59.16 0.137 59.424 ;
     RECT  0.084 59.424 0.137 59.448 ;
     RECT  0.06 59.448 0.137 59.712 ;
     RECT  0.084 59.712 0.137 59.736 ;
     RECT  0.06 59.736 0.137 60.048 ;
     RECT  0.084 60.048 0.137 60.072 ;
     RECT  0.06 60.072 0.137 60.336 ;
     RECT  0.084 60.336 0.137 60.36 ;
     RECT  0.06 60.36 0.137 60.624 ;
     RECT  0.084 60.624 0.137 60.648 ;
     RECT  0.06 60.648 0.137 60.96 ;
     RECT  0.084 60.96 0.137 60.984 ;
     RECT  0.06 60.984 0.137 61.248 ;
     RECT  0.084 61.248 0.137 61.272 ;
     RECT  0.06 61.272 0.137 61.584 ;
     RECT  0.084 61.584 0.137 61.608 ;
     RECT  0.06 61.608 0.137 61.872 ;
     RECT  0.084 61.872 0.137 61.896 ;
     RECT  0.06 61.896 0.137 62.16 ;
     RECT  0.084 62.16 0.137 62.184 ;
     RECT  0.06 62.184 0.137 62.496 ;
     RECT  0.084 62.496 0.137 62.52 ;
     RECT  0.06 62.52 0.137 62.784 ;
     RECT  0.084 62.784 0.137 62.808 ;
     RECT  0.06 62.808 0.137 63.072 ;
     RECT  0.084 63.072 0.137 63.096 ;
     RECT  0.06 63.096 0.137 63.408 ;
     RECT  0.084 63.408 0.137 63.432 ;
     RECT  0.06 63.432 0.137 63.696 ;
     RECT  0.084 63.696 0.137 63.72 ;
     RECT  0.06 63.72 0.137 63.984 ;
     RECT  0.084 63.984 0.137 64.008 ;
     RECT  0.06 64.008 0.137 64.32 ;
     RECT  0.084 64.32 0.137 64.344 ;
     RECT  0.06 64.344 0.137 64.608 ;
     RECT  0.084 64.608 0.137 64.632 ;
     RECT  0.06 64.632 0.137 64.896 ;
     RECT  0.084 64.896 0.137 64.92 ;
     RECT  0.06 64.92 0.137 65.232 ;
     RECT  0.084 65.232 0.137 65.256 ;
     RECT  0.06 65.256 0.137 65.52 ;
     RECT  0.084 65.52 0.137 65.544 ;
     RECT  0.06 65.544 0.137 65.856 ;
     RECT  0.084 65.856 0.137 65.88 ;
     RECT  0.06 65.88 0.137 66.144 ;
     RECT  0.084 66.144 0.137 66.168 ;
     RECT  0.06 66.168 0.137 66.432 ;
     RECT  0.084 66.432 0.137 66.456 ;
     RECT  0.06 66.456 0.137 66.768 ;
     RECT  0.084 66.768 0.137 66.792 ;
     RECT  0.06 66.792 0.137 67.056 ;
     RECT  0.084 67.056 0.137 67.08 ;
     RECT  0.06 67.08 0.137 67.344 ;
     RECT  0.084 67.344 0.137 67.368 ;
     RECT  0.06 67.368 0.137 67.68 ;
     RECT  0.084 67.68 0.137 67.704 ;
     RECT  0.06 67.704 0.137 67.968 ;
     RECT  0.084 67.968 0.137 67.992 ;
     RECT  0.06 67.992 0.137 68.256 ;
     RECT  0.084 68.256 0.137 68.28 ;
     RECT  0.06 68.28 0.137 68.592 ;
     RECT  0.084 68.592 0.137 68.616 ;
     RECT  0.06 68.616 0.137 68.88 ;
     RECT  0.084 68.88 0.137 68.904 ;
     RECT  0.06 68.904 0.137 69.216 ;
     RECT  0.084 69.216 0.137 69.24 ;
     RECT  0.06 69.24 0.137 69.504 ;
     RECT  0.084 69.504 0.137 69.528 ;
     RECT  0.06 69.528 0.137 69.792 ;
     RECT  0.084 69.792 0.137 69.816 ;
     RECT  0.06 69.816 0.137 70.128 ;
     RECT  0.084 70.128 0.137 70.152 ;
     RECT  0.06 70.152 0.137 70.416 ;
     RECT  0.084 70.416 0.137 70.44 ;
     RECT  0.06 70.44 0.137 70.704 ;
     RECT  0.084 70.704 0.137 70.728 ;
     RECT  0.06 70.728 0.137 71.04 ;
     RECT  0.084 71.04 0.137 71.064 ;
     RECT  0.06 71.064 0.137 71.328 ;
     RECT  0.084 71.328 0.137 71.352 ;
     RECT  0.06 71.352 0.137 71.616 ;
     RECT  0.084 71.616 0.137 71.64 ;
     RECT  0.06 71.64 0.137 71.952 ;
     RECT  0.084 71.952 0.137 71.976 ;
     RECT  0.06 71.976 0.137 72.24 ;
     RECT  0.084 72.24 0.137 72.264 ;
     RECT  0.06 72.264 0.137 72.528 ;
     RECT  0.084 72.528 0.137 72.552 ;
     RECT  0.06 72.552 0.137 72.864 ;
     RECT  0.084 72.864 0.137 72.888 ;
     RECT  0.06 72.888 0.137 73.152 ;
     RECT  0.084 73.152 0.137 73.176 ;
     RECT  0.06 73.176 0.137 73.488 ;
     RECT  0.084 73.488 0.137 73.512 ;
     RECT  0.06 73.512 0.137 73.776 ;
     RECT  0.084 73.776 0.137 73.8 ;
     RECT  0.06 73.8 0.137 74.064 ;
     RECT  0.084 74.064 0.137 74.088 ;
     RECT  0.06 74.088 0.137 74.4 ;
     RECT  0.084 74.4 0.137 74.424 ;
     RECT  0.06 74.424 0.137 74.688 ;
     RECT  0.084 74.688 0.137 74.712 ;
     RECT  0.06 74.712 0.137 74.976 ;
     RECT  0.084 74.976 0.137 75 ;
     RECT  0.06 75 0.137 75.312 ;
     RECT  0.084 75.312 0.137 75.336 ;
     RECT  0.06 75.336 0.137 75.6 ;
     RECT  0.084 75.6 0.137 75.624 ;
     RECT  0.06 75.624 0.137 75.888 ;
     RECT  0.084 75.888 0.137 75.912 ;
     RECT  0.06 75.912 0.137 76.224 ;
     RECT  0.084 76.224 0.137 76.248 ;
     RECT  0.06 76.248 0.137 76.512 ;
     RECT  0.084 76.512 0.137 76.536 ;
     RECT  0.06 76.536 0.137 76.848 ;
     RECT  0.084 76.848 0.137 76.872 ;
     RECT  0.06 76.872 0.137 77.136 ;
     RECT  0.084 77.136 0.137 77.16 ;
     RECT  0.06 77.16 0.137 77.424 ;
     RECT  0.084 77.424 0.137 77.448 ;
     RECT  0.06 77.448 0.137 77.76 ;
     RECT  0.084 77.76 0.137 77.784 ;
     RECT  0.06 77.784 0.137 78.048 ;
     RECT  0.084 78.048 0.137 78.072 ;
     RECT  0.06 78.072 0.137 78.336 ;
     RECT  0.084 78.336 0.137 78.36 ;
     RECT  0.06 78.36 0.137 78.672 ;
     RECT  0.084 78.672 0.137 78.696 ;
     RECT  0.06 78.696 0.137 78.96 ;
     RECT  0.084 78.96 0.137 78.984 ;
     RECT  0.06 78.984 0.137 79.248 ;
     RECT  0.084 79.248 0.137 79.272 ;
     RECT  0.06 79.272 0.137 79.584 ;
     RECT  0.084 79.584 0.137 79.608 ;
     RECT  0.06 79.608 0.137 79.872 ;
     RECT  0.084 79.872 0.137 79.896 ;
     RECT  0.06 79.896 0.137 80.16 ;
     RECT  0.084 80.16 0.137 80.184 ;
     RECT  0.06 80.184 0.137 80.496 ;
     RECT  0.084 80.496 0.137 80.52 ;
     RECT  0.06 80.52 0.137 80.784 ;
     RECT  0.084 80.784 0.137 80.808 ;
     RECT  0.06 80.808 0.137 81.12 ;
     RECT  0.084 81.12 0.137 81.144 ;
     RECT  0.06 81.144 0.137 81.408 ;
     RECT  0.084 81.408 0.137 81.432 ;
     RECT  0.06 81.432 0.137 81.696 ;
     RECT  0.084 81.696 0.137 81.72 ;
     RECT  0.06 81.72 0.137 82.032 ;
     RECT  0.084 82.032 0.137 82.056 ;
     RECT  0.06 82.056 0.137 82.32 ;
     RECT  0.084 82.32 0.137 82.344 ;
     RECT  0.06 82.344 0.137 82.608 ;
     RECT  0.084 82.608 0.137 82.632 ;
     RECT  0.06 82.632 0.137 82.944 ;
     RECT  0.084 82.944 0.137 82.968 ;
     RECT  0.06 82.968 0.137 83.232 ;
     RECT  0.084 83.232 0.137 83.256 ;
     RECT  0.06 83.256 0.137 83.52 ;
     RECT  0.084 83.52 0.137 83.544 ;
     RECT  0.06 83.544 0.137 83.856 ;
     RECT  0.084 83.856 0.137 83.88 ;
     RECT  0.06 83.88 0.137 84.144 ;
     RECT  0.084 84.144 0.137 84.168 ;
     RECT  0.06 84.168 0.137 84.48 ;
     RECT  0.084 84.48 0.137 84.504 ;
     RECT  0.06 84.504 0.137 84.768 ;
     RECT  0.084 84.768 0.137 84.792 ;
     RECT  0.06 84.792 0.137 85.056 ;
     RECT  0.084 85.056 0.137 85.08 ;
     RECT  0.06 85.08 0.137 85.392 ;
     RECT  0.084 85.392 0.137 85.416 ;
     RECT  0.06 85.416 0.137 85.68 ;
     RECT  0.084 85.68 0.137 85.704 ;
     RECT  0.06 85.704 0.137 85.968 ;
     RECT  0.084 85.968 0.137 85.992 ;
     RECT  0.06 85.992 0.137 86.304 ;
     RECT  0.084 86.304 0.137 86.328 ;
     RECT  0.06 86.328 0.137 86.592 ;
     RECT  0.084 86.592 0.137 86.616 ;
     RECT  0.06 86.616 0.137 86.88 ;
     RECT  0.084 86.88 0.137 86.904 ;
     RECT  0.06 86.904 0.137 87.216 ;
     RECT  0.084 87.216 0.137 87.24 ;
     RECT  0.06 87.24 0.137 87.504 ;
     RECT  0.084 87.504 0.137 87.528 ;
     RECT  0.06 87.528 0.137 87.792 ;
     RECT  0.084 87.792 0.137 87.816 ;
     RECT  0.06 87.816 0.137 88.128 ;
     RECT  0.084 88.128 0.137 88.152 ;
     RECT  0.06 88.152 0.137 88.416 ;
     RECT  0.084 88.416 0.137 88.44 ;
     RECT  0.06 88.44 0.137 88.752 ;
     RECT  0.084 88.752 0.137 88.776 ;
     RECT  0.06 88.776 0.137 89.04 ;
     RECT  0.084 89.04 0.137 89.064 ;
     RECT  0.06 89.064 0.137 89.328 ;
     RECT  0.084 89.328 0.137 89.352 ;
     RECT  0.06 89.352 0.137 89.664 ;
     RECT  0.084 89.664 0.137 89.688 ;
     RECT  0.06 89.688 0.137 89.952 ;
     RECT  0.084 89.952 0.137 89.976 ;
     RECT  0.06 89.976 0.137 90.24 ;
     RECT  0.084 90.24 0.137 90.264 ;
     RECT  0.06 90.264 0.137 90.576 ;
     RECT  0.084 90.576 0.137 90.6 ;
     RECT  0.06 90.6 0.137 90.864 ;
     RECT  0.084 90.864 0.137 90.888 ;
     RECT  0.06 90.888 0.137 91.152 ;
     RECT  0.084 91.152 0.137 91.176 ;
     RECT  0.06 91.176 0.137 91.488 ;
     RECT  0.084 91.488 0.137 91.512 ;
     RECT  0.06 91.512 0.137 91.776 ;
     RECT  0.084 91.776 0.137 91.8 ;
     RECT  0.06 91.8 0.137 92.112 ;
     RECT  0.084 92.112 0.137 92.136 ;
     RECT  0.06 92.136 0.137 92.4 ;
     RECT  0.084 92.4 0.137 92.424 ;
     RECT  0.06 92.424 0.137 92.688 ;
     RECT  0.084 92.688 0.137 92.712 ;
     RECT  0.06 92.712 0.137 93.024 ;
     RECT  0.084 93.024 0.137 93.048 ;
     RECT  0.06 93.048 0.137 93.312 ;
     RECT  0.084 93.312 0.137 93.336 ;
     RECT  0.06 93.336 0.137 93.6 ;
     RECT  0.084 93.6 0.137 93.624 ;
     RECT  0.06 93.624 0.137 93.936 ;
     RECT  0.084 93.936 0.137 93.96 ;
     RECT  0.06 93.96 0.137 94.224 ;
     RECT  0.084 94.224 0.137 94.248 ;
     RECT  0.06 94.248 0.137 94.512 ;
     RECT  0.084 94.512 0.137 94.536 ;
     RECT  0.06 94.536 0.137 94.848 ;
     RECT  0.084 94.848 0.137 94.872 ;
     RECT  0.06 94.872 0.137 95.136 ;
     RECT  0.084 95.136 0.137 95.16 ;
     RECT  0.06 95.16 0.137 95.424 ;
     RECT  0.084 95.424 0.137 95.448 ;
     RECT  0.06 95.448 0.137 95.76 ;
     RECT  0.084 95.76 0.137 95.784 ;
     RECT  0.06 95.784 0.137 96.048 ;
     RECT  0.084 96.048 0.137 96.072 ;
     RECT  0.06 96.072 0.137 96.384 ;
     RECT  0.084 96.384 0.137 96.408 ;
     RECT  0.06 96.408 0.137 96.672 ;
     RECT  0.084 96.672 0.137 96.696 ;
     RECT  0.06 96.696 0.137 96.96 ;
     RECT  0.084 96.96 0.137 96.984 ;
     RECT  0.06 96.984 0.137 97.296 ;
     RECT  0.084 97.296 0.137 97.32 ;
     RECT  0.06 97.32 0.137 97.584 ;
     RECT  0.084 97.584 0.137 97.608 ;
     RECT  0.06 97.608 0.137 97.872 ;
     RECT  0.084 97.872 0.137 97.896 ;
     RECT  0.06 97.896 0.137 98.208 ;
     RECT  0.084 98.208 0.137 98.232 ;
     RECT  0.06 98.232 0.137 98.496 ;
     RECT  0.084 98.496 0.137 98.52 ;
     RECT  0.06 98.52 0.137 98.784 ;
     RECT  0.084 98.784 0.137 98.808 ;
     RECT  0.06 98.808 0.137 99.12 ;
     RECT  0.084 99.12 0.137 99.144 ;
     RECT  0.06 99.144 0.137 99.408 ;
     RECT  0.084 99.408 0.137 99.432 ;
     RECT  0.06 99.432 0.137 99.744 ;
     RECT  0.084 99.744 0.137 99.768 ;
     RECT  0.06 99.768 0.137 100.032 ;
     RECT  0.084 100.032 0.137 100.056 ;
     RECT  0.06 100.056 0.137 100.512 ;
     RECT  0.084 100.512 0.137 100.536 ;
     RECT  0.06 100.536 0.137 100.8 ;
     RECT  0.084 100.8 0.137 100.824 ;
     RECT  0.06 100.824 0.137 101.088 ;
     RECT  0.084 101.088 0.137 101.112 ;
     RECT  0.06 101.112 0.137 101.328 ;
     RECT  0.084 101.328 0.137 101.352 ;
     RECT  0.06 101.352 0.137 101.616 ;
     RECT  0.084 101.616 0.137 101.64 ;
     RECT  0.06 101.64 0.137 101.904 ;
     RECT  0.084 101.904 0.137 101.928 ;
     RECT  0.06 101.928 0.137 102.144 ;
     RECT  0.084 102.144 0.137 102.168 ;
     RECT  0.06 102.168 0.137 102.432 ;
     RECT  0.084 102.432 0.137 102.456 ;
     RECT  0.06 102.456 0.137 102.72 ;
     RECT  0.084 102.72 0.137 102.744 ;
     RECT  0.06 102.744 0.137 103.008 ;
     RECT  0.084 103.008 0.137 103.032 ;
     RECT  0.137 2.64 0.173 50.28 ;
     RECT  0.137 51.504 0.173 54.264 ;
     RECT  0.137 67.344 0.173 103.032 ;
     RECT  0.173 49.056 0.569 50.28 ;
     RECT  0.173 51.504 0.569 51.528 ;
     RECT  0.173 52.992 0.569 54.264 ;
     RECT  0.137 56.688 0.569 62.52 ;
     RECT  0.137 66.144 0.569 66.168 ;
     RECT  0.173 67.344 0.569 67.368 ;
     RECT  0.173 69.792 1.433 93.624 ;
     RECT  0.137 63.696 2.245 63.72 ;
     RECT  0.173 95.136 2.245 103.032 ;
     RECT  2.197 65.328 2.293 65.352 ;
     RECT  0.173 2.64 2.408 47.832 ;
     RECT  0.569 49.056 2.408 49.656 ;
     RECT  0.569 53.328 2.408 53.64 ;
     RECT  0.569 56.688 2.408 59.448 ;
     RECT  0.569 61.248 2.408 61.272 ;
     RECT  2.245 63.024 2.408 63.72 ;
     RECT  2.293 65.328 2.408 65.448 ;
     RECT  0.173 68.592 2.408 68.616 ;
     RECT  1.433 69.792 2.408 90.6 ;
     RECT  1.433 92.112 2.408 93.624 ;
     RECT  2.245 95.136 2.408 103.224 ;
     RECT  2.408 2.148 2.512 103.692 ;
     RECT  2.512 2.418 2.629 103.692 ;
     RECT  2.629 2.418 2.704 103.8 ;
     RECT  2.704 103.2 2.716 103.8 ;
     RECT  2.704 83.088 2.729 91.368 ;
     RECT  2.704 79.248 2.765 79.272 ;
     RECT  2.704 13.632 2.801 14.28 ;
     RECT  2.704 27.216 2.801 28.008 ;
     RECT  2.704 96.48 2.801 96.504 ;
     RECT  2.729 83.088 2.819 91.224 ;
     RECT  2.819 88.8 2.837 91.224 ;
     RECT  2.704 4.176 2.873 4.2 ;
     RECT  2.704 50.4 2.917 52.152 ;
     RECT  2.704 66.576 2.953 66.6 ;
     RECT  2.917 51.84 2.963 52.152 ;
     RECT  2.704 67.776 2.963 68.424 ;
     RECT  2.704 72.912 2.963 76.488 ;
     RECT  2.704 61.968 2.981 63.144 ;
     RECT  2.819 83.088 2.981 85.512 ;
     RECT  2.704 53.568 3.004 58.152 ;
     RECT  3.004 53.568 3.011 55.944 ;
     RECT  2.981 62.352 3.107 63.144 ;
     RECT  2.704 22.128 3.299 25.56 ;
     RECT  2.963 52.032 3.305 52.152 ;
     RECT  2.704 16.656 3.377 17.64 ;
     RECT  2.963 72.96 3.443 76.488 ;
     RECT  2.704 59.232 3.449 59.88 ;
     RECT  2.981 83.232 3.457 85.512 ;
     RECT  2.704 42.576 3.484 44.472 ;
     RECT  3.299 24.576 3.485 24.6 ;
     RECT  2.704 20.16 3.521 20.184 ;
     RECT  2.963 67.824 3.521 68.424 ;
     RECT  2.704 81.744 3.521 82.056 ;
     RECT  2.704 31.872 3.557 31.896 ;
     RECT  3.011 55.632 3.629 55.944 ;
     RECT  3.004 57.024 3.697 58.152 ;
     RECT  2.819 86.688 3.701 87.24 ;
     RECT  3.107 63.12 3.733 63.144 ;
     RECT  2.917 50.4 3.745 50.76 ;
     RECT  2.704 65.328 3.769 65.352 ;
     RECT  3.521 81.744 3.781 81.768 ;
     RECT  3.697 57.024 3.827 58.968 ;
     RECT  3.769 64.944 3.841 65.352 ;
     RECT  2.837 88.8 3.845 91.176 ;
     RECT  3.827 57.072 3.868 58.968 ;
     RECT  3.845 89.424 3.877 91.176 ;
     RECT  3.443 76.272 3.913 76.488 ;
     RECT  2.704 77.52 3.913 77.784 ;
     RECT  3.697 98.64 3.917 99.048 ;
     RECT  2.801 14.256 3.925 14.28 ;
     RECT  3.443 72.96 3.925 75.192 ;
     RECT  2.704 7.488 3.949 10.056 ;
     RECT  2.704 11.184 3.949 12.024 ;
     RECT  3.305 52.032 3.971 52.056 ;
     RECT  3.299 22.128 3.973 23.4 ;
     RECT  3.841 64.416 3.973 65.352 ;
     RECT  3.805 102.048 3.973 102.072 ;
     RECT  2.704 6.336 3.985 6.36 ;
     RECT  3.949 7.488 3.985 12.504 ;
     RECT  3.877 89.424 3.989 91.752 ;
     RECT  3.973 100.752 4.019 102.072 ;
     RECT  3.913 2.88 4.025 2.904 ;
     RECT  3.913 5.04 4.025 5.064 ;
     RECT  3.484 42.72 4.025 44.472 ;
     RECT  3.973 21.6 4.06 23.4 ;
     RECT  4.019 100.752 4.06 101.352 ;
     RECT  3.973 64.416 4.061 66.168 ;
     RECT  3.989 90.24 4.061 91.752 ;
     RECT  2.704 93.072 4.061 93.096 ;
     RECT  3.985 28.944 4.093 28.968 ;
     RECT  2.704 30.048 4.093 30.792 ;
     RECT  3.925 13.536 4.097 14.28 ;
     RECT  4.097 14.256 4.161 14.28 ;
     RECT  4.093 28.944 4.165 30.792 ;
     RECT  2.704 70.032 4.165 70.728 ;
     RECT  4.06 21.84 4.169 23.4 ;
     RECT  4.061 90.24 4.169 91.176 ;
     RECT  2.704 46.128 4.172 48.984 ;
     RECT  2.801 27.216 4.201 27.336 ;
     RECT  3.733 63.12 4.201 63.24 ;
     RECT  4.061 64.416 4.201 65.688 ;
     RECT  4.165 28.944 4.211 31.128 ;
     RECT  3.011 53.568 4.237 54.168 ;
     RECT  3.985 15.456 4.277 15.48 ;
     RECT  3.457 83.232 4.309 84.888 ;
     RECT  3.985 6.336 4.313 12.504 ;
     RECT  2.704 94.176 4.313 94.2 ;
     RECT  3.913 86.016 4.355 86.376 ;
     RECT  4.313 8.496 4.385 12.504 ;
     RECT  3.917 99.024 4.385 99.048 ;
     RECT  3.973 61.344 4.417 61.368 ;
     RECT  4.201 27.216 4.453 27.624 ;
     RECT  3.913 76.272 4.453 77.784 ;
     RECT  3.841 41.376 4.525 41.4 ;
     RECT  4.025 42.72 4.525 44.232 ;
     RECT  3.913 95.376 4.525 95.4 ;
     RECT  4.169 91.152 4.529 91.176 ;
     RECT  4.165 69.552 4.549 70.728 ;
     RECT  3.925 72.144 4.549 75.192 ;
     RECT  4.172 46.08 4.561 48.984 ;
     RECT  4.201 50.016 4.561 50.04 ;
     RECT  4.385 9.648 4.573 12.504 ;
     RECT  3.697 60.144 4.597 60.168 ;
     RECT  3.521 68.352 4.597 68.424 ;
     RECT  4.549 69.552 4.597 75.192 ;
     RECT  4.453 76.272 4.597 77.976 ;
     RECT  3.781 81.36 4.597 81.768 ;
     RECT  4.313 6.336 4.601 7.512 ;
     RECT  4.06 101.328 4.601 101.352 ;
     RECT  4.561 46.08 4.633 50.04 ;
     RECT  4.597 68.304 4.633 68.424 ;
     RECT  4.597 69.552 4.633 77.976 ;
     RECT  4.453 27.216 4.645 28.392 ;
     RECT  4.633 68.304 4.645 77.976 ;
     RECT  4.597 80.352 4.691 81.768 ;
     RECT  4.501 24.96 4.705 24.984 ;
     RECT  4.211 30.048 4.705 31.128 ;
     RECT  3.877 97.488 4.709 97.512 ;
     RECT  4.573 10.032 4.717 12.504 ;
     RECT  4.633 32.928 4.741 32.952 ;
     RECT  2.704 33.984 4.741 39.816 ;
     RECT  4.237 53.568 4.741 55.128 ;
     RECT  4.705 24.624 4.777 24.984 ;
     RECT  3.377 17.616 4.787 17.64 ;
     RECT  4.417 61.344 4.796 62.136 ;
     RECT  4.201 63.12 4.796 65.688 ;
     RECT  4.777 24.624 4.813 25.128 ;
     RECT  4.645 26.544 4.813 28.392 ;
     RECT  3.868 58.56 4.844 58.968 ;
     RECT  4.597 60.096 4.844 60.312 ;
     RECT  4.645 68.304 4.849 78.168 ;
     RECT  4.741 53.568 4.885 55.992 ;
     RECT  4.885 52.32 4.921 55.992 ;
     RECT  3.868 57.072 4.921 57.528 ;
     RECT  4.309 87.792 4.925 87.816 ;
     RECT  4.921 52.32 4.933 57.528 ;
     RECT  4.525 41.376 4.94 44.232 ;
     RECT  4.933 52.032 4.957 57.528 ;
     RECT  4.309 83.184 4.957 84.888 ;
     RECT  4.385 8.496 4.969 8.52 ;
     RECT  4.705 30.048 4.981 31.32 ;
     RECT  4.525 16.512 4.993 16.536 ;
     RECT  4.813 24.624 5.029 28.392 ;
     RECT  4.94 40.8 5.029 44.232 ;
     RECT  4.633 45.6 5.029 50.04 ;
     RECT  4.844 58.56 5.065 60.312 ;
     RECT  4.796 61.344 5.065 65.688 ;
     RECT  4.169 21.84 5.087 22.584 ;
     RECT  4.741 32.928 5.101 39.816 ;
     RECT  5.029 40.8 5.101 50.04 ;
     RECT  4.705 66.864 5.101 66.888 ;
     RECT  5.077 14.448 5.125 14.472 ;
     RECT  5.087 21.648 5.125 22.584 ;
     RECT  4.981 30.048 5.125 31.368 ;
     RECT  5.101 32.928 5.137 50.04 ;
     RECT  5.101 66.864 5.137 67.272 ;
     RECT  4.849 68.304 5.137 79.56 ;
     RECT  5.029 24.528 5.173 28.392 ;
     RECT  5.125 30.048 5.173 31.656 ;
     RECT  4.957 51.648 5.173 57.528 ;
     RECT  5.065 58.56 5.173 65.688 ;
     RECT  4.691 80.592 5.173 81.768 ;
     RECT  4.601 6.336 5.177 6.36 ;
     RECT  4.717 10.032 5.177 10.344 ;
     RECT  5.125 21.12 5.221 22.584 ;
     RECT  5.173 24.144 5.221 31.656 ;
     RECT  5.209 90.048 5.245 90.072 ;
     RECT  5.137 32.832 5.269 50.04 ;
     RECT  4.957 83.184 5.285 85.512 ;
     RECT  3.973 19.344 5.353 19.368 ;
     RECT  5.285 83.184 5.353 84.888 ;
     RECT  5.173 80.592 5.365 82.008 ;
     RECT  5.353 82.992 5.365 84.888 ;
     RECT  4.601 7.488 5.393 7.512 ;
     RECT  4.717 11.376 5.437 12.504 ;
     RECT  5.269 32.832 5.461 50.136 ;
     RECT  5.173 51.6 5.497 65.688 ;
     RECT  5.461 32.832 5.509 50.568 ;
     RECT  5.509 32.736 5.533 50.568 ;
     RECT  5.497 51.6 5.533 65.736 ;
     RECT  5.137 66.864 5.533 79.56 ;
     RECT  5.437 11.664 5.573 12.504 ;
     RECT  5.353 19.344 5.605 19.896 ;
     RECT  4.525 95.376 5.609 96.216 ;
     RECT  5.605 19.344 5.677 20.088 ;
     RECT  5.221 21.12 5.677 31.656 ;
     RECT  5.677 19.344 5.701 31.656 ;
     RECT  5.701 19.008 5.749 31.656 ;
     RECT  5.533 32.736 5.749 79.56 ;
     RECT  4.789 92.832 5.749 92.856 ;
     RECT  5.245 90.048 5.861 90.936 ;
     RECT  5.749 19.008 5.929 79.56 ;
     RECT  5.365 80.592 5.929 84.888 ;
     RECT  5.749 92.832 5.965 92.952 ;
     RECT  4.993 16.512 6.085 17.352 ;
     RECT  5.929 19.008 6.085 84.888 ;
     RECT  5.713 100.704 6.277 100.728 ;
     RECT  6.085 16.512 6.289 84.888 ;
     RECT  5.861 90.048 6.289 90.6 ;
     RECT  6.277 100.704 6.323 102.072 ;
     RECT  5.125 13.488 6.353 14.472 ;
     RECT  6.323 101.28 6.365 102.072 ;
     RECT  6.289 86.592 6.397 86.616 ;
     RECT  6.353 13.488 6.437 14.856 ;
     RECT  6.397 86.592 6.505 87.24 ;
     RECT  5.641 88.368 6.505 88.392 ;
     RECT  6.505 86.592 6.545 88.392 ;
     RECT  6.545 86.592 6.613 88.152 ;
     RECT  6.397 94.32 6.749 94.344 ;
     RECT  5.965 92.16 6.757 92.952 ;
     RECT  6.749 94.08 6.757 94.344 ;
     RECT  5.609 95.376 6.757 95.4 ;
     RECT  6.685 96.864 6.803 96.888 ;
     RECT  6.289 89.952 6.805 90.6 ;
     RECT  6.757 92.16 6.833 95.4 ;
     RECT  6.365 102.048 7.045 102.072 ;
     RECT  2.716 103.2 7.045 103.752 ;
     RECT  6.805 89.136 7.052 90.6 ;
     RECT  6.833 92.16 7.052 93.48 ;
     RECT  6.829 9.216 7.093 9.24 ;
     RECT  5.965 99.12 7.093 99.144 ;
     RECT  7.117 15.456 7.189 15.48 ;
     RECT  6.289 16.512 7.189 85.08 ;
     RECT  7.189 15.456 7.261 85.08 ;
     RECT  6.613 86.208 7.261 88.152 ;
     RECT  7.093 98.64 7.333 99.144 ;
     RECT  7.333 98.496 7.405 99.144 ;
     RECT  7.045 102.048 7.405 103.752 ;
     RECT  7.405 98.496 7.429 99.768 ;
     RECT  7.429 98.4 7.669 99.768 ;
     RECT  7.405 101.472 7.669 103.752 ;
     RECT  7.669 98.4 7.724 103.752 ;
     RECT  7.093 3.84 7.808 3.864 ;
     RECT  5.857 6.816 7.808 6.84 ;
     RECT  7.093 8.448 7.808 9.24 ;
     RECT  5.573 11.664 7.808 11.976 ;
     RECT  6.437 13.488 7.808 14.472 ;
     RECT  7.261 15.456 7.808 88.152 ;
     RECT  7.052 89.136 7.808 93.48 ;
     RECT  6.833 94.992 7.808 95.4 ;
     RECT  7.724 98.4 7.808 103.848 ;
     RECT  7.808 2.148 7.811 103.848 ;
     RECT  7.811 2.148 7.912 103.752 ;
     RECT  7.912 2.418 8.104 103.752 ;
     RECT  8.005 105.648 8.339 105.672 ;
     RECT  8.104 8.448 8.381 8.472 ;
     RECT  8.104 75.408 8.476 89.496 ;
     RECT  8.104 11.664 8.741 11.976 ;
     RECT  8.104 94.56 9.011 95.4 ;
     RECT  8.104 96.432 9.011 96.696 ;
     RECT  9.011 94.56 9.029 94.968 ;
     RECT  8.104 92.976 9.097 93 ;
     RECT  9.097 92.976 9.133 93.48 ;
     RECT  8.104 97.824 9.133 98.664 ;
     RECT  8.104 90.48 9.17 91.848 ;
     RECT  9.133 97.488 9.173 98.664 ;
     RECT  8.104 99.744 9.173 100.536 ;
     RECT  9.17 90.96 9.205 91.848 ;
     RECT  9.133 92.832 9.205 93.48 ;
     RECT  8.104 103.2 9.277 103.752 ;
     RECT  8.104 14.4 9.493 74.328 ;
     RECT  8.476 75.552 9.493 89.496 ;
     RECT  9.277 103.2 9.497 104.328 ;
     RECT  9.493 14.4 9.548 89.496 ;
     RECT  9.173 97.488 9.605 97.512 ;
     RECT  9.548 14.4 9.635 89.88 ;
     RECT  9.173 98.64 9.781 98.664 ;
     RECT  9.173 99.744 9.781 100.344 ;
     RECT  9.635 14.4 9.817 88.104 ;
     RECT  8.741 11.952 9.929 11.976 ;
     RECT  9.029 94.944 10.001 94.968 ;
     RECT  8.104 101.856 10.033 101.88 ;
     RECT  9.781 98.64 10.253 100.344 ;
     RECT  9.497 104.304 10.429 104.328 ;
     RECT  9.635 89.184 10.573 89.88 ;
     RECT  9.205 90.96 10.573 93.48 ;
     RECT  9.497 103.2 10.673 103.32 ;
     RECT  10.429 104.304 10.673 104.904 ;
     RECT  10.253 98.64 10.681 100.296 ;
     RECT  10.681 98.304 10.789 100.296 ;
     RECT  9.011 96.432 10.835 96.456 ;
     RECT  10.789 97.536 10.835 100.296 ;
     RECT  10.573 89.184 10.861 93.48 ;
     RECT  10.835 97.536 10.973 97.56 ;
     RECT  10.835 98.64 11.297 100.296 ;
     RECT  11.365 9.936 11.413 9.96 ;
     RECT  10.249 11.664 11.413 11.688 ;
     RECT  11.413 9.36 11.459 9.96 ;
     RECT  11.413 11.664 11.459 11.976 ;
     RECT  10.673 103.2 11.459 104.904 ;
     RECT  10.549 95.232 11.461 95.256 ;
     RECT  11.297 99.36 11.557 100.296 ;
     RECT  10.033 101.856 11.557 102.12 ;
     RECT  11.557 99.36 11.603 102.12 ;
     RECT  9.817 13.824 11.617 88.104 ;
     RECT  10.861 89.136 11.621 93.48 ;
     RECT  11.603 101.04 11.621 102.12 ;
     RECT  11.621 101.04 11.644 101.88 ;
     RECT  11.459 9.36 11.657 9.384 ;
     RECT  11.617 13.584 11.725 88.104 ;
     RECT  11.621 89.136 11.725 93.096 ;
     RECT  11.459 11.952 11.845 11.976 ;
     RECT  11.461 94.608 11.977 95.256 ;
     RECT  11.725 13.584 11.981 93.096 ;
     RECT  11.977 94.08 11.989 95.256 ;
     RECT  11.977 96.336 11.989 96.36 ;
     RECT  8.104 3.84 12.053 3.864 ;
     RECT  11.989 94.08 12.061 96.36 ;
     RECT  11.981 89.808 12.161 93.096 ;
     RECT  11.459 104.88 12.445 104.904 ;
     RECT  11.845 11.952 12.764 12.36 ;
     RECT  11.981 13.584 12.764 88.488 ;
     RECT  11.644 101.856 13.021 101.88 ;
     RECT  11.459 103.2 13.021 103.752 ;
     RECT  13.021 101.856 13.139 103.752 ;
     RECT  12.613 6 13.208 6.024 ;
     RECT  13.165 8.544 13.208 8.568 ;
     RECT  12.764 11.952 13.208 88.488 ;
     RECT  12.161 90.624 13.208 93.096 ;
     RECT  12.061 94.08 13.208 95.688 ;
     RECT  11.603 99.36 13.208 99.384 ;
     RECT  13.139 101.856 13.208 103.692 ;
     RECT  13.208 2.148 13.312 103.692 ;
     RECT  12.445 104.88 13.379 105.72 ;
     RECT  13.312 2.418 13.504 103.422 ;
     RECT  13.379 104.928 13.619 105.72 ;
     RECT  13.504 5.568 13.667 6.024 ;
     RECT  13.504 8.544 13.667 9.432 ;
     RECT  13.504 13.584 13.715 87.96 ;
     RECT  13.504 7.056 13.817 7.08 ;
     RECT  13.619 105.648 13.859 105.72 ;
     RECT  13.667 9.408 13.955 9.432 ;
     RECT  13.504 93.072 13.997 93.096 ;
     RECT  13.504 90 14.147 90.024 ;
     RECT  13.504 101.856 14.317 103.422 ;
     RECT  14.317 101.856 14.605 103.656 ;
     RECT  13.715 13.584 14.617 87.816 ;
     RECT  13.504 91.344 14.753 91.608 ;
     RECT  13.859 105.648 14.785 105.672 ;
     RECT  14.605 101.856 14.819 103.752 ;
     RECT  13.504 12.336 14.885 12.36 ;
     RECT  14.617 13.584 14.897 87.336 ;
     RECT  13.504 95.232 15.185 96.6 ;
     RECT  14.819 101.856 15.221 103.656 ;
     RECT  14.785 104.88 15.253 105.672 ;
     RECT  13.504 10.8 15.389 10.824 ;
     RECT  14.885 11.952 15.389 12.36 ;
     RECT  15.389 10.8 15.473 12.36 ;
     RECT  14.753 91.584 15.689 91.608 ;
     RECT  15.253 104.88 16.019 105.72 ;
     RECT  15.221 103.2 16.181 103.656 ;
     RECT  16.181 103.2 16.265 103.752 ;
     RECT  15.221 101.856 16.412 101.88 ;
     RECT  16.412 100.224 16.499 100.248 ;
     RECT  16.412 101.28 16.499 102.216 ;
     RECT  15.473 10.8 16.547 10.824 ;
     RECT  16.265 103.2 16.547 103.704 ;
     RECT  15.185 95.232 16.597 95.592 ;
     RECT  15.185 96.576 16.597 96.6 ;
     RECT  16.597 95.232 16.837 96.6 ;
     RECT  13.667 6 16.981 6.024 ;
     RECT  16.729 9.744 16.981 9.768 ;
     RECT  16.837 94.56 16.981 96.6 ;
     RECT  16.547 103.632 17.027 103.704 ;
     RECT  16.981 9.168 17.053 9.768 ;
     RECT  15.473 12.336 17.053 12.36 ;
     RECT  14.897 13.584 17.053 87.24 ;
     RECT  16.981 5.712 17.165 6.024 ;
     RECT  17.053 8.112 17.173 9.768 ;
     RECT  17.089 92.976 17.189 93 ;
     RECT  17.053 12.336 17.411 87.288 ;
     RECT  16.499 101.856 17.42 102.216 ;
     RECT  17.42 101.856 17.507 102.552 ;
     RECT  17.165 5.712 17.593 5.736 ;
     RECT  17.411 12.336 17.597 12.552 ;
     RECT  17.413 89.52 17.605 89.544 ;
     RECT  17.173 8.112 17.653 8.136 ;
     RECT  16.019 105.696 17.747 105.72 ;
     RECT  16.729 88.368 17.797 88.392 ;
     RECT  17.605 89.52 17.797 89.688 ;
     RECT  17.797 88.368 17.845 89.688 ;
     RECT  17.269 90.72 17.845 90.744 ;
     RECT  17.411 13.68 17.893 87.288 ;
     RECT  17.845 88.368 17.893 90.744 ;
     RECT  17.189 92.928 17.893 93 ;
     RECT  16.981 94.08 17.893 96.6 ;
     RECT  16.261 98.064 17.893 98.088 ;
     RECT  17.173 9.504 17.948 9.768 ;
     RECT  17.948 9.504 18.061 10.296 ;
     RECT  17.665 103.728 18.097 103.8 ;
     RECT  17.653 6.816 18.277 8.136 ;
     RECT  17.893 92.928 18.277 96.6 ;
     RECT  17.893 98.064 18.277 98.664 ;
     RECT  17.597 12.528 18.565 12.552 ;
     RECT  18.097 103.632 18.565 103.8 ;
     RECT  17.953 104.832 18.565 104.856 ;
     RECT  17.053 3.936 18.608 3.96 ;
     RECT  17.593 5.136 18.608 5.736 ;
     RECT  18.277 6.816 18.608 8.52 ;
     RECT  18.061 9.504 18.608 10.632 ;
     RECT  18.565 12.24 18.608 12.552 ;
     RECT  17.893 13.68 18.608 90.744 ;
     RECT  17.804 91.824 18.608 91.848 ;
     RECT  18.277 92.928 18.608 98.664 ;
     RECT  17.507 101.856 18.608 102.12 ;
     RECT  18.565 103.632 18.608 104.856 ;
     RECT  18.608 2.148 18.707 104.856 ;
     RECT  18.707 2.148 18.712 104.376 ;
     RECT  18.712 2.418 18.904 104.376 ;
     RECT  18.904 97.488 18.947 104.376 ;
     RECT  18.904 7.344 19.001 7.368 ;
     RECT  18.904 92.976 19.091 95.112 ;
     RECT  18.947 97.488 19.187 103.8 ;
     RECT  18.904 12.24 19.379 12.936 ;
     RECT  18.904 10.608 19.42 11.16 ;
     RECT  18.904 14.016 19.468 89.544 ;
     RECT  18.904 90.576 19.469 91.848 ;
     RECT  19.468 14.208 19.475 89.544 ;
     RECT  19.475 84.192 19.541 89.544 ;
     RECT  19.379 12.912 19.571 12.936 ;
     RECT  19.475 14.208 19.613 82.68 ;
     RECT  19.613 14.208 19.649 22.296 ;
     RECT  19.613 23.28 19.649 82.68 ;
     RECT  19.187 97.488 19.667 102.6 ;
     RECT  19.187 103.728 19.667 103.8 ;
     RECT  19.469 91.2 19.721 91.848 ;
     RECT  18.817 105.696 19.789 105.72 ;
     RECT  19.649 19.536 19.793 22.296 ;
     RECT  19.649 23.28 19.829 82.584 ;
     RECT  19.829 65.664 19.865 82.584 ;
     RECT  19.667 103.728 19.907 103.752 ;
     RECT  19.865 70.896 19.955 82.584 ;
     RECT  19.955 79.68 19.973 82.584 ;
     RECT  19.667 100.32 19.973 102.6 ;
     RECT  19.973 79.68 19.981 81.528 ;
     RECT  19.981 79.68 20.003 81.384 ;
     RECT  19.649 14.208 20.009 18.456 ;
     RECT  19.955 70.896 20.009 78.696 ;
     RECT  20.003 79.728 20.009 81.384 ;
     RECT  18.904 8.448 20.041 9.528 ;
     RECT  19.42 10.608 20.041 11.016 ;
     RECT  20.009 70.896 20.045 76.104 ;
     RECT  19.541 84.336 20.081 89.544 ;
     RECT  20.009 14.736 20.099 18.456 ;
     RECT  19.793 19.632 20.099 22.2 ;
     RECT  19.829 23.28 20.099 64.344 ;
     RECT  20.041 8.448 20.101 11.016 ;
     RECT  19.789 105.648 20.113 105.72 ;
     RECT  19.667 97.488 20.117 98.712 ;
     RECT  20.113 105.6 20.147 105.72 ;
     RECT  19.091 93.456 20.153 95.112 ;
     RECT  19.973 100.848 20.153 102.6 ;
     RECT  20.147 105.6 20.185 105.672 ;
     RECT  20.099 14.736 20.195 15.432 ;
     RECT  20.099 23.28 20.225 25.848 ;
     RECT  20.009 77.472 20.225 78.696 ;
     RECT  20.117 97.488 20.225 98.616 ;
     RECT  20.099 16.8 20.243 18.456 ;
     RECT  20.099 19.68 20.243 22.2 ;
     RECT  20.099 27.84 20.243 64.344 ;
     RECT  19.973 82.56 20.243 82.584 ;
     RECT  20.243 27.84 20.261 28.728 ;
     RECT  20.243 29.808 20.261 64.344 ;
     RECT  20.081 84.336 20.261 88.968 ;
     RECT  20.261 34.128 20.291 64.344 ;
     RECT  20.261 84.336 20.291 87.864 ;
     RECT  20.101 7.872 20.297 11.016 ;
     RECT  20.291 34.128 20.297 44.472 ;
     RECT  18.904 4.512 20.333 4.536 ;
     RECT  20.297 37.104 20.333 44.472 ;
     RECT  20.045 76.08 20.333 76.104 ;
     RECT  20.009 81.36 20.333 81.384 ;
     RECT  20.261 29.808 20.339 33.096 ;
     RECT  20.333 37.104 20.369 39.192 ;
     RECT  20.243 17.088 20.387 17.112 ;
     RECT  20.243 18.432 20.387 18.456 ;
     RECT  20.243 19.92 20.387 22.2 ;
     RECT  20.261 27.888 20.387 28.728 ;
     RECT  20.185 104.88 20.387 105.672 ;
     RECT  20.297 7.92 20.405 11.016 ;
     RECT  18.904 96.336 20.405 96.36 ;
     RECT  20.297 34.128 20.435 36.072 ;
     RECT  19.865 65.664 20.435 69.48 ;
     RECT  20.387 27.984 20.441 28.728 ;
     RECT  20.435 35.664 20.441 36.072 ;
     RECT  20.333 40.56 20.441 44.472 ;
     RECT  20.291 45.552 20.441 64.344 ;
     RECT  20.195 14.736 20.477 14.952 ;
     RECT  20.225 23.28 20.477 24.12 ;
     RECT  20.009 79.728 20.477 79.992 ;
     RECT  20.441 48.96 20.513 64.344 ;
     RECT  20.405 7.92 20.531 9.432 ;
     RECT  20.531 7.92 20.549 9 ;
     RECT  20.441 40.608 20.549 44.472 ;
     RECT  20.513 49.104 20.549 64.344 ;
     RECT  20.549 8.448 20.572 9 ;
     RECT  20.549 42.192 20.579 44.472 ;
     RECT  20.257 3.408 20.585 3.432 ;
     RECT  20.387 21.168 20.585 22.2 ;
     RECT  20.477 23.52 20.585 24.12 ;
     RECT  20.339 29.808 20.585 32.952 ;
     RECT  20.369 37.104 20.585 39.144 ;
     RECT  20.225 78.096 20.585 78.696 ;
     RECT  20.005 92.352 20.609 92.376 ;
     RECT  20.153 93.456 20.609 94.68 ;
     RECT  20.153 101.712 20.609 102.6 ;
     RECT  20.581 103.632 20.609 103.656 ;
     RECT  20.477 14.736 20.627 14.76 ;
     RECT  20.291 84.336 20.627 87.816 ;
     RECT  20.387 104.88 20.627 105.624 ;
     RECT  20.225 25.104 20.657 25.848 ;
     RECT  20.549 50.592 20.657 64.344 ;
     RECT  20.387 19.92 20.675 19.944 ;
     RECT  20.585 31.536 20.693 32.952 ;
     RECT  20.549 40.608 20.693 40.632 ;
     RECT  20.441 45.552 20.693 47.88 ;
     RECT  20.627 84.336 20.693 84.936 ;
     RECT  20.609 92.352 20.693 94.68 ;
     RECT  20.609 101.712 20.693 103.656 ;
     RECT  20.585 24.096 20.723 24.12 ;
     RECT  20.441 35.664 20.723 36.024 ;
     RECT  20.405 10.992 20.729 11.016 ;
     RECT  20.693 45.552 20.729 47.256 ;
     RECT  20.657 50.592 20.729 54.6 ;
     RECT  20.693 84.912 20.729 84.936 ;
     RECT  20.585 37.104 20.765 38.712 ;
     RECT  20.729 45.552 20.765 45.576 ;
     RECT  20.729 50.592 20.765 53.4 ;
     RECT  20.693 101.712 20.765 102.6 ;
     RECT  20.572 8.496 20.771 9 ;
     RECT  20.693 32.592 20.771 32.952 ;
     RECT  20.435 34.128 20.771 34.536 ;
     RECT  20.441 28.08 20.801 28.728 ;
     RECT  20.765 38.16 20.801 38.712 ;
     RECT  20.261 88.944 20.801 88.968 ;
     RECT  20.693 93.744 20.801 94.68 ;
     RECT  20.657 25.104 20.837 25.512 ;
     RECT  20.657 55.824 20.837 64.344 ;
     RECT  20.627 86.016 20.867 87.816 ;
     RECT  20.693 103.632 20.867 103.656 ;
     RECT  20.225 97.968 20.873 98.616 ;
     RECT  20.837 25.104 20.909 25.128 ;
     RECT  20.549 49.104 20.909 49.56 ;
     RECT  20.693 31.536 20.945 31.56 ;
     RECT  20.477 79.824 21.013 79.992 ;
     RECT  19.721 91.2 21.013 91.224 ;
     RECT  20.693 92.352 21.013 92.376 ;
     RECT  20.729 47.232 21.017 47.256 ;
     RECT  20.765 51.024 21.017 53.4 ;
     RECT  20.585 78.672 21.053 78.696 ;
     RECT  21.013 91.2 21.059 92.376 ;
     RECT  20.771 32.928 21.089 32.952 ;
     RECT  21.017 52.464 21.089 53.4 ;
     RECT  20.435 65.808 21.089 69.48 ;
     RECT  21.059 92.112 21.1 92.376 ;
     RECT  20.627 104.88 21.107 104.904 ;
     RECT  20.585 29.808 21.125 30.504 ;
     RECT  20.801 93.744 21.155 93.768 ;
     RECT  20.771 8.976 21.161 9 ;
     RECT  20.771 34.128 21.161 34.392 ;
     RECT  20.579 42.192 21.161 43.56 ;
     RECT  21.089 65.808 21.161 69 ;
     RECT  21.161 42.192 21.269 43.512 ;
     RECT  21.161 67.872 21.269 69 ;
     RECT  20.801 38.16 21.305 38.184 ;
     RECT  20.837 55.824 21.305 59.496 ;
     RECT  20.909 49.536 21.341 49.56 ;
     RECT  20.873 98.592 21.341 98.616 ;
     RECT  21.089 52.464 21.377 52.968 ;
     RECT  20.045 70.896 21.377 74.904 ;
     RECT  20.837 60.624 21.413 64.344 ;
     RECT  20.801 28.08 21.449 28.104 ;
     RECT  21.377 72.672 21.449 74.904 ;
     RECT  21.013 79.824 21.485 80.472 ;
     RECT  20.765 102.576 21.485 102.6 ;
     RECT  20.585 21.168 21.521 22.008 ;
     RECT  21.125 29.808 21.557 29.832 ;
     RECT  21.305 57.024 21.557 59.496 ;
     RECT  21.377 52.944 21.587 52.968 ;
     RECT  21.161 65.808 21.593 66.456 ;
     RECT  21.593 66.432 21.629 66.456 ;
     RECT  21.377 70.896 21.661 71.688 ;
     RECT  21.1 92.352 21.683 92.376 ;
     RECT  20.867 86.016 21.731 87.288 ;
     RECT  21.269 42.72 21.737 43.512 ;
     RECT  21.413 61.2 21.779 64.344 ;
     RECT  21.731 86.016 21.779 86.712 ;
     RECT  21.779 63.216 21.809 64.344 ;
     RECT  21.779 86.016 21.827 86.472 ;
     RECT  20.723 35.664 21.845 35.688 ;
     RECT  21.521 21.168 21.917 21.192 ;
     RECT  21.269 67.872 21.989 67.896 ;
     RECT  21.985 103.728 22.115 103.752 ;
     RECT  22.021 93.216 22.205 93.24 ;
     RECT  21.827 86.016 22.259 86.088 ;
     RECT  21.809 63.648 22.355 64.344 ;
     RECT  21.485 79.824 22.355 79.848 ;
     RECT  21.557 57.12 22.403 59.496 ;
     RECT  22.403 57.456 22.457 59.496 ;
     RECT  21.161 34.368 22.561 34.392 ;
     RECT  21.269 68.976 22.561 69 ;
     RECT  21.737 43.296 22.601 43.512 ;
     RECT  21.805 88.32 22.601 88.344 ;
     RECT  22.549 104.832 22.637 104.856 ;
     RECT  22.273 81.024 22.669 81.048 ;
     RECT  22.457 57.456 22.673 59.016 ;
     RECT  21.779 61.2 22.705 62.184 ;
     RECT  22.705 60.336 22.745 62.184 ;
     RECT  22.237 31.104 22.777 31.128 ;
     RECT  22.777 7.728 22.813 7.752 ;
     RECT  22.745 60.336 22.817 61.224 ;
     RECT  22.355 64.32 22.835 64.344 ;
     RECT  22.259 86.064 22.835 86.088 ;
     RECT  22.669 81.024 22.849 81.192 ;
     RECT  21.661 17.088 22.853 17.112 ;
     RECT  22.705 23.856 22.853 23.88 ;
     RECT  22.849 81.024 22.853 81.24 ;
     RECT  21.305 55.824 22.883 55.992 ;
     RECT  21.449 73.008 22.883 74.904 ;
     RECT  22.777 31.104 22.889 31.848 ;
     RECT  22.883 74.88 22.925 74.904 ;
     RECT  22.201 84.336 22.925 84.36 ;
     RECT  22.883 55.968 22.931 55.992 ;
     RECT  22.883 73.008 22.931 73.608 ;
     RECT  22.673 57.456 22.979 58.728 ;
     RECT  22.777 104.88 23.075 104.904 ;
     RECT  22.849 62.256 23.177 62.28 ;
     RECT  21.661 70.8 23.245 71.688 ;
     RECT  22.561 33.552 23.249 34.392 ;
     RECT  22.813 7.632 23.353 7.752 ;
     RECT  22.813 14.64 23.353 14.664 ;
     RECT  23.101 16.464 23.353 16.488 ;
     RECT  22.889 31.104 23.353 31.368 ;
     RECT  23.249 33.552 23.353 34.152 ;
     RECT  22.849 42.192 23.353 42.216 ;
     RECT  23.317 45.408 23.353 45.432 ;
     RECT  22.525 47.808 23.353 47.832 ;
     RECT  22.777 52.176 23.353 52.2 ;
     RECT  20.729 54.576 23.353 54.6 ;
     RECT  23.245 70.704 23.353 71.688 ;
     RECT  22.931 73.008 23.353 73.032 ;
     RECT  23.353 6.816 23.357 7.752 ;
     RECT  23.353 23.28 23.389 23.304 ;
     RECT  23.353 41.376 23.389 42.216 ;
     RECT  22.601 43.296 23.389 43.32 ;
     RECT  23.353 50.016 23.389 50.04 ;
     RECT  22.813 12.24 23.461 12.264 ;
     RECT  23.353 16.272 23.821 16.488 ;
     RECT  22.853 81.216 23.821 81.24 ;
     RECT  23.821 15.84 23.857 16.488 ;
     RECT  23.389 41.376 23.857 43.32 ;
     RECT  23.353 44.784 23.857 45.432 ;
     RECT  23.245 79.728 23.857 79.752 ;
     RECT  23.821 80.736 23.857 81.24 ;
     RECT  23.357 6.816 23.893 6.84 ;
     RECT  23.353 10.608 23.893 10.632 ;
     RECT  23.461 12.048 23.893 12.264 ;
     RECT  23.353 14.064 23.893 14.664 ;
     RECT  23.857 15.648 23.893 16.488 ;
     RECT  23.353 18.048 23.893 18.072 ;
     RECT  23.857 19.68 23.893 19.704 ;
     RECT  23.389 23.088 23.893 23.304 ;
     RECT  23.353 25.872 23.893 27.912 ;
     RECT  23.353 30.336 23.893 31.368 ;
     RECT  23.353 32.928 23.893 34.152 ;
     RECT  23.353 37.536 23.893 37.56 ;
     RECT  23.857 40.752 23.893 45.432 ;
     RECT  23.353 47.808 23.893 48.408 ;
     RECT  23.389 49.392 23.893 50.04 ;
     RECT  23.353 51.792 23.893 52.44 ;
     RECT  23.353 53.424 23.893 54.648 ;
     RECT  23.857 60.432 23.893 60.456 ;
     RECT  23.533 63.072 23.893 63.096 ;
     RECT  23.389 64.272 23.893 64.296 ;
     RECT  23.713 66.096 23.893 66.12 ;
     RECT  23.785 67.296 23.893 67.32 ;
     RECT  22.561 68.304 23.893 69 ;
     RECT  23.353 70.704 23.893 73.032 ;
     RECT  22.813 76.944 23.893 76.968 ;
     RECT  23.353 78.528 23.893 78.552 ;
     RECT  23.065 86.976 23.893 87 ;
     RECT  23.389 88.56 23.893 88.584 ;
     RECT  23.353 90 23.893 90.6 ;
     RECT  23.353 92.592 23.893 92.616 ;
     RECT  23.353 94.992 23.893 95.016 ;
     RECT  23.677 98.448 23.893 98.472 ;
     RECT  22.957 3.6 23.929 3.624 ;
     RECT  23.893 6 23.929 6.84 ;
     RECT  23.893 17.856 23.929 18.072 ;
     RECT  23.893 19.488 23.929 19.704 ;
     RECT  23.893 22.464 23.929 23.688 ;
     RECT  23.893 35.136 23.929 35.976 ;
     RECT  23.893 37.536 23.929 45.432 ;
     RECT  23.893 46.8 23.929 52.44 ;
     RECT  23.893 53.424 23.929 54.84 ;
     RECT  23.893 56.256 23.929 56.28 ;
     RECT  23.893 63.072 23.929 69 ;
     RECT  23.893 70.512 23.929 73.032 ;
     RECT  23.893 74.304 23.929 75.96 ;
     RECT  23.353 83.136 23.929 83.784 ;
     RECT  23.353 84.768 23.929 84.792 ;
     RECT  23.893 88.56 23.929 90.6 ;
     RECT  23.893 92.208 23.929 92.616 ;
     RECT  23.893 94.224 23.929 95.016 ;
     RECT  23.353 96.624 23.929 96.648 ;
     RECT  23.929 46.8 24.325 56.28 ;
     RECT  23.929 70.512 24.325 75.96 ;
     RECT  23.893 76.944 24.325 78.552 ;
     RECT  23.893 86.352 24.325 87 ;
     RECT  23.929 94.224 24.325 96.648 ;
     RECT  23.929 8.016 24.361 8.04 ;
     RECT  23.893 9.216 24.361 9.24 ;
     RECT  23.893 10.608 24.361 16.488 ;
     RECT  23.929 17.856 24.361 19.704 ;
     RECT  23.893 24.912 24.361 34.152 ;
     RECT  23.929 35.136 24.361 36.552 ;
     RECT  24.325 46.8 24.361 56.472 ;
     RECT  22.979 57.456 24.361 58.248 ;
     RECT  23.893 60.24 24.361 60.456 ;
     RECT  24.325 70.512 24.361 78.552 ;
     RECT  23.857 79.728 24.361 81.384 ;
     RECT  24.325 86.352 24.361 87.192 ;
     RECT  23.929 88.368 24.361 90.6 ;
     RECT  23.929 91.776 24.361 92.616 ;
     RECT  24.325 93.984 24.361 96.648 ;
     RECT  23.893 97.824 24.361 98.472 ;
     RECT  23.929 63.072 24.397 69.096 ;
     RECT  24.361 93.984 24.397 98.472 ;
     RECT  23.893 99.792 24.397 99.816 ;
     RECT  23.929 3.6 24.433 4.008 ;
     RECT  23.929 5.424 24.433 6.84 ;
     RECT  24.361 8.016 24.433 16.488 ;
     RECT  23.929 22.272 24.433 23.688 ;
     RECT  24.361 24.912 24.433 36.552 ;
     RECT  24.397 63.072 24.433 69.528 ;
     RECT  24.361 70.512 24.433 82.152 ;
     RECT  24.361 91.584 24.433 92.616 ;
     RECT  24.397 93.984 24.433 99.816 ;
     RECT  24.361 17.856 24.469 20.28 ;
     RECT  23.929 37.536 24.469 45.624 ;
     RECT  24.361 46.8 24.469 58.248 ;
     RECT  24.433 63.072 24.469 82.152 ;
     RECT  23.929 83.136 24.469 84.792 ;
     RECT  24.361 86.352 24.469 90.6 ;
     RECT  24.433 91.584 24.469 101.4 ;
     RECT  24.469 2.592 24.505 2.616 ;
     RECT  24.433 3.6 24.505 4.2 ;
     RECT  24.433 22.08 24.505 36.552 ;
     RECT  24.469 37.536 24.505 58.68 ;
     RECT  24.505 21.696 25.009 58.68 ;
     RECT  24.361 59.664 25.009 60.456 ;
     RECT  24.469 86.352 25.009 101.976 ;
     RECT  24.469 103.008 25.009 103.032 ;
     RECT  24.505 2.592 25.045 4.2 ;
     RECT  24.433 5.424 25.045 16.488 ;
     RECT  24.469 17.856 25.045 20.472 ;
     RECT  25.009 21.456 25.045 60.456 ;
     RECT  24.505 61.872 25.045 61.896 ;
     RECT  24.469 62.88 25.045 84.984 ;
     RECT  25.009 86.352 25.045 103.032 ;
     RECT  25.045 2.592 25.081 61.896 ;
     RECT  25.045 62.88 25.081 103.032 ;
     RECT  25.081 2.592 25.836 2.616 ;
     RECT  25.081 2.616 25.884 2.784 ;
     RECT  25.081 2.784 25.836 2.808 ;
     RECT  25.081 2.808 25.884 2.976 ;
     RECT  25.081 2.976 25.836 3 ;
     RECT  25.081 3 25.884 3.168 ;
     RECT  25.081 3.168 25.836 3.192 ;
     RECT  25.081 3.192 25.884 3.408 ;
     RECT  25.081 3.408 25.836 3.432 ;
     RECT  25.081 3.432 25.884 3.6 ;
     RECT  25.081 3.6 25.836 3.624 ;
     RECT  25.081 3.624 25.884 3.792 ;
     RECT  25.081 3.792 25.836 3.816 ;
     RECT  25.081 3.816 25.884 3.984 ;
     RECT  25.081 3.984 25.836 4.008 ;
     RECT  25.081 4.008 25.884 4.176 ;
     RECT  25.081 4.176 25.836 4.2 ;
     RECT  25.081 4.2 25.884 4.416 ;
     RECT  25.081 4.416 25.836 4.44 ;
     RECT  25.081 4.44 25.884 4.608 ;
     RECT  25.081 4.608 25.836 4.632 ;
     RECT  25.081 4.632 25.884 4.8 ;
     RECT  25.081 4.8 25.836 4.824 ;
     RECT  25.081 4.824 25.884 4.992 ;
     RECT  25.081 4.992 25.836 5.016 ;
     RECT  25.081 5.016 25.884 5.184 ;
     RECT  25.081 5.184 25.836 5.208 ;
     RECT  25.081 5.208 25.884 5.424 ;
     RECT  25.081 5.424 25.836 5.448 ;
     RECT  25.081 5.448 25.884 5.616 ;
     RECT  25.081 5.616 25.836 5.64 ;
     RECT  25.081 5.64 25.884 5.808 ;
     RECT  25.081 5.808 25.836 5.832 ;
     RECT  25.081 5.832 25.884 6 ;
     RECT  25.081 6 25.836 6.024 ;
     RECT  25.081 6.024 25.884 6.192 ;
     RECT  25.081 6.192 25.836 6.216 ;
     RECT  25.081 6.216 25.884 6.384 ;
     RECT  25.081 6.384 25.836 6.408 ;
     RECT  25.081 6.408 25.884 6.624 ;
     RECT  25.081 6.624 25.836 6.648 ;
     RECT  25.081 6.648 25.884 6.816 ;
     RECT  25.081 6.816 25.836 6.84 ;
     RECT  25.081 6.84 25.884 7.008 ;
     RECT  25.081 7.008 25.836 7.032 ;
     RECT  25.081 7.032 25.884 7.2 ;
     RECT  25.081 7.2 25.836 7.224 ;
     RECT  25.081 7.224 25.884 7.392 ;
     RECT  25.081 7.392 25.836 7.416 ;
     RECT  25.081 7.416 25.884 7.632 ;
     RECT  25.081 7.632 25.836 7.656 ;
     RECT  25.081 7.656 25.884 7.824 ;
     RECT  25.081 7.824 25.836 7.848 ;
     RECT  25.081 7.848 25.884 8.016 ;
     RECT  25.081 8.016 25.836 8.04 ;
     RECT  25.081 8.04 25.884 8.208 ;
     RECT  25.081 8.208 25.836 8.232 ;
     RECT  25.081 8.232 25.884 8.4 ;
     RECT  25.081 8.4 25.836 8.424 ;
     RECT  25.081 8.424 25.884 8.64 ;
     RECT  25.081 8.64 25.836 8.664 ;
     RECT  25.081 8.664 25.884 8.832 ;
     RECT  25.081 8.832 25.836 8.856 ;
     RECT  25.081 8.856 25.884 9.024 ;
     RECT  25.081 9.024 25.836 9.048 ;
     RECT  25.081 9.048 25.884 9.216 ;
     RECT  25.081 9.216 25.836 9.24 ;
     RECT  25.081 9.24 25.884 9.408 ;
     RECT  25.081 9.408 25.836 9.432 ;
     RECT  25.081 9.432 25.884 9.6 ;
     RECT  25.081 9.6 25.836 9.624 ;
     RECT  25.081 9.624 25.884 9.84 ;
     RECT  25.081 9.84 25.836 9.864 ;
     RECT  25.081 9.864 25.884 10.032 ;
     RECT  25.081 10.032 25.836 10.056 ;
     RECT  25.081 10.056 25.884 10.224 ;
     RECT  25.081 10.224 25.836 10.248 ;
     RECT  25.081 10.248 25.884 10.416 ;
     RECT  25.081 10.416 25.836 10.44 ;
     RECT  25.081 10.44 25.884 10.608 ;
     RECT  25.081 10.608 25.836 10.632 ;
     RECT  25.081 10.632 25.884 10.848 ;
     RECT  25.081 10.848 25.836 10.872 ;
     RECT  25.081 10.872 25.884 11.04 ;
     RECT  25.081 11.04 25.836 11.064 ;
     RECT  25.081 11.064 25.884 11.232 ;
     RECT  25.081 11.232 25.836 11.256 ;
     RECT  25.081 11.256 25.884 11.424 ;
     RECT  25.081 11.424 25.836 11.448 ;
     RECT  25.081 11.448 25.884 11.616 ;
     RECT  25.081 11.616 25.836 11.64 ;
     RECT  25.081 11.64 25.884 11.808 ;
     RECT  25.081 11.808 25.836 11.832 ;
     RECT  25.081 11.832 25.884 12.048 ;
     RECT  25.081 12.048 25.836 12.072 ;
     RECT  25.081 12.072 25.884 12.24 ;
     RECT  25.081 12.24 25.836 12.264 ;
     RECT  25.081 12.264 25.884 12.432 ;
     RECT  25.081 12.432 25.836 12.456 ;
     RECT  25.081 12.456 25.884 12.624 ;
     RECT  25.081 12.624 25.836 12.648 ;
     RECT  25.081 12.648 25.884 12.816 ;
     RECT  25.081 12.816 25.836 12.84 ;
     RECT  25.081 12.84 25.884 13.056 ;
     RECT  25.081 13.056 25.836 13.08 ;
     RECT  25.081 13.08 25.884 13.248 ;
     RECT  25.081 13.248 25.836 13.272 ;
     RECT  25.081 13.272 25.884 13.44 ;
     RECT  25.081 13.44 25.836 13.464 ;
     RECT  25.081 13.464 25.884 13.632 ;
     RECT  25.081 13.632 25.836 13.656 ;
     RECT  25.081 13.656 25.884 13.824 ;
     RECT  25.081 13.824 25.836 13.848 ;
     RECT  25.081 13.848 25.884 14.064 ;
     RECT  25.081 14.064 25.836 14.088 ;
     RECT  25.081 14.088 25.884 14.256 ;
     RECT  25.081 14.256 25.836 14.28 ;
     RECT  25.081 14.28 25.884 14.448 ;
     RECT  25.081 14.448 25.836 14.472 ;
     RECT  25.081 14.472 25.884 14.64 ;
     RECT  25.081 14.64 25.836 14.664 ;
     RECT  25.081 14.664 25.884 14.832 ;
     RECT  25.081 14.832 25.836 14.856 ;
     RECT  25.081 14.856 25.884 15.024 ;
     RECT  25.081 15.024 25.836 15.048 ;
     RECT  25.081 15.048 25.884 15.264 ;
     RECT  25.081 15.264 25.836 15.288 ;
     RECT  25.081 15.288 25.884 15.456 ;
     RECT  25.081 15.456 25.836 15.48 ;
     RECT  25.081 15.48 25.884 15.648 ;
     RECT  25.081 15.648 25.836 15.672 ;
     RECT  25.081 15.672 25.884 15.84 ;
     RECT  25.081 15.84 25.836 15.864 ;
     RECT  25.081 15.864 25.884 16.032 ;
     RECT  25.081 16.032 25.836 16.056 ;
     RECT  25.081 16.056 25.884 16.272 ;
     RECT  25.081 16.272 25.836 16.296 ;
     RECT  25.081 16.296 25.884 16.464 ;
     RECT  25.081 16.464 25.836 16.488 ;
     RECT  25.081 16.488 25.884 16.656 ;
     RECT  25.081 16.656 25.836 16.68 ;
     RECT  25.081 16.68 25.884 16.848 ;
     RECT  25.081 16.848 25.836 16.872 ;
     RECT  25.081 16.872 25.884 17.04 ;
     RECT  25.081 17.04 25.836 17.064 ;
     RECT  25.081 17.064 25.884 17.232 ;
     RECT  25.081 17.232 25.836 17.256 ;
     RECT  25.081 17.256 25.884 17.472 ;
     RECT  25.081 17.472 25.836 17.496 ;
     RECT  25.081 17.496 25.884 17.664 ;
     RECT  25.081 17.664 25.836 17.688 ;
     RECT  25.081 17.688 25.884 17.856 ;
     RECT  25.081 17.856 25.836 17.88 ;
     RECT  25.081 17.88 25.884 18.048 ;
     RECT  25.081 18.048 25.836 18.072 ;
     RECT  25.081 18.072 25.884 18.24 ;
     RECT  25.081 18.24 25.836 18.264 ;
     RECT  25.081 18.264 25.884 18.48 ;
     RECT  25.081 18.48 25.836 18.504 ;
     RECT  25.081 18.504 25.884 18.672 ;
     RECT  25.081 18.672 25.836 18.696 ;
     RECT  25.081 18.696 25.884 18.864 ;
     RECT  25.081 18.864 25.836 18.888 ;
     RECT  25.081 18.888 25.884 19.056 ;
     RECT  25.081 19.056 25.836 19.08 ;
     RECT  25.081 19.08 25.884 19.248 ;
     RECT  25.081 19.248 25.836 19.272 ;
     RECT  25.081 19.272 25.884 19.488 ;
     RECT  25.081 19.488 25.836 19.512 ;
     RECT  25.081 19.512 25.884 19.68 ;
     RECT  25.081 19.68 25.836 19.704 ;
     RECT  25.081 19.704 25.884 19.872 ;
     RECT  25.081 19.872 25.836 19.896 ;
     RECT  25.081 19.896 25.884 20.064 ;
     RECT  25.081 20.064 25.836 20.088 ;
     RECT  25.081 20.088 25.884 20.256 ;
     RECT  25.081 20.256 25.836 20.28 ;
     RECT  25.081 20.28 25.884 20.448 ;
     RECT  25.081 20.448 25.836 20.472 ;
     RECT  25.081 20.472 25.884 20.688 ;
     RECT  25.081 20.688 25.836 20.712 ;
     RECT  25.081 20.712 25.884 20.88 ;
     RECT  25.081 20.88 25.836 20.904 ;
     RECT  25.081 20.904 25.884 21.072 ;
     RECT  25.081 21.072 25.836 21.096 ;
     RECT  25.081 21.096 25.884 21.264 ;
     RECT  25.081 21.264 25.836 21.288 ;
     RECT  25.081 21.288 25.884 21.456 ;
     RECT  25.081 21.456 25.836 21.48 ;
     RECT  25.081 21.48 25.884 21.696 ;
     RECT  25.081 21.696 25.836 21.72 ;
     RECT  25.081 21.72 25.884 21.888 ;
     RECT  25.081 21.888 25.836 21.912 ;
     RECT  25.081 21.912 25.884 22.08 ;
     RECT  25.081 22.08 25.836 22.104 ;
     RECT  25.081 22.104 25.884 22.272 ;
     RECT  25.081 22.272 25.836 22.296 ;
     RECT  25.081 22.296 25.884 22.464 ;
     RECT  25.081 22.464 25.836 22.488 ;
     RECT  25.081 22.488 25.884 22.704 ;
     RECT  25.081 22.704 25.836 22.728 ;
     RECT  25.081 22.728 25.884 22.896 ;
     RECT  25.081 22.896 25.836 22.92 ;
     RECT  25.081 22.92 25.884 23.088 ;
     RECT  25.081 23.088 25.836 23.112 ;
     RECT  25.081 23.112 25.884 23.28 ;
     RECT  25.081 23.28 25.836 23.304 ;
     RECT  25.081 23.304 25.884 23.472 ;
     RECT  25.081 23.472 25.836 23.496 ;
     RECT  25.081 23.496 25.884 23.664 ;
     RECT  25.081 23.664 25.836 23.688 ;
     RECT  25.081 23.688 25.884 23.904 ;
     RECT  25.081 23.904 25.836 23.928 ;
     RECT  25.081 23.928 25.884 24.096 ;
     RECT  25.081 24.096 25.836 24.12 ;
     RECT  25.081 24.12 25.884 24.288 ;
     RECT  25.081 24.288 25.836 24.312 ;
     RECT  25.081 24.312 25.884 24.48 ;
     RECT  25.081 24.48 25.836 24.504 ;
     RECT  25.081 24.504 25.884 24.672 ;
     RECT  25.081 24.672 25.836 24.696 ;
     RECT  25.081 24.696 25.884 24.912 ;
     RECT  25.081 24.912 25.836 24.936 ;
     RECT  25.081 24.936 25.884 25.104 ;
     RECT  25.081 25.104 25.836 25.128 ;
     RECT  25.081 25.128 25.884 25.296 ;
     RECT  25.081 25.296 25.836 25.32 ;
     RECT  25.081 25.32 25.884 25.488 ;
     RECT  25.081 25.488 25.836 25.512 ;
     RECT  25.081 25.512 25.884 25.68 ;
     RECT  25.081 25.68 25.836 25.704 ;
     RECT  25.081 25.704 25.884 25.872 ;
     RECT  25.081 25.872 25.836 25.896 ;
     RECT  25.081 25.896 25.884 26.112 ;
     RECT  25.081 26.112 25.836 26.136 ;
     RECT  25.081 26.136 25.884 26.304 ;
     RECT  25.081 26.304 25.836 26.328 ;
     RECT  25.081 26.328 25.884 26.496 ;
     RECT  25.081 26.496 25.836 26.52 ;
     RECT  25.081 26.52 25.884 26.688 ;
     RECT  25.081 26.688 25.836 26.712 ;
     RECT  25.081 26.712 25.884 26.88 ;
     RECT  25.081 26.88 25.836 26.904 ;
     RECT  25.081 26.904 25.884 27.12 ;
     RECT  25.081 27.12 25.836 27.144 ;
     RECT  25.081 27.144 25.884 27.312 ;
     RECT  25.081 27.312 25.836 27.336 ;
     RECT  25.081 27.336 25.884 27.504 ;
     RECT  25.081 27.504 25.836 27.528 ;
     RECT  25.081 27.528 25.884 27.696 ;
     RECT  25.081 27.696 25.836 27.72 ;
     RECT  25.081 27.72 25.884 27.888 ;
     RECT  25.081 27.888 25.836 27.912 ;
     RECT  25.081 27.912 25.884 28.128 ;
     RECT  25.081 28.128 25.836 28.152 ;
     RECT  25.081 28.152 25.884 28.32 ;
     RECT  25.081 28.32 25.836 28.344 ;
     RECT  25.081 28.344 25.884 28.512 ;
     RECT  25.081 28.512 25.836 28.536 ;
     RECT  25.081 28.536 25.884 28.704 ;
     RECT  25.081 28.704 25.836 28.728 ;
     RECT  25.081 28.728 25.884 28.896 ;
     RECT  25.081 28.896 25.836 28.92 ;
     RECT  25.081 28.92 25.884 29.088 ;
     RECT  25.081 29.088 25.836 29.112 ;
     RECT  25.081 29.112 25.884 29.328 ;
     RECT  25.081 29.328 25.836 29.352 ;
     RECT  25.081 29.352 25.884 29.52 ;
     RECT  25.081 29.52 25.836 29.544 ;
     RECT  25.081 29.544 25.884 29.712 ;
     RECT  25.081 29.712 25.836 29.736 ;
     RECT  25.081 29.736 25.884 29.904 ;
     RECT  25.081 29.904 25.836 29.928 ;
     RECT  25.081 29.928 25.884 30.096 ;
     RECT  25.081 30.096 25.836 30.12 ;
     RECT  25.081 30.12 25.884 30.336 ;
     RECT  25.081 30.336 25.836 30.36 ;
     RECT  25.081 30.36 25.884 30.528 ;
     RECT  25.081 30.528 25.836 30.552 ;
     RECT  25.081 30.552 25.884 30.72 ;
     RECT  25.081 30.72 25.836 30.744 ;
     RECT  25.081 30.744 25.884 30.912 ;
     RECT  25.081 30.912 25.836 30.936 ;
     RECT  25.081 30.936 25.884 31.104 ;
     RECT  25.081 31.104 25.836 31.128 ;
     RECT  25.081 31.128 25.884 31.344 ;
     RECT  25.081 31.344 25.836 31.368 ;
     RECT  25.081 31.368 25.884 31.536 ;
     RECT  25.081 31.536 25.836 31.56 ;
     RECT  25.081 31.56 25.884 31.728 ;
     RECT  25.081 31.728 25.836 31.752 ;
     RECT  25.081 31.752 25.884 31.92 ;
     RECT  25.081 31.92 25.836 31.944 ;
     RECT  25.081 31.944 25.884 32.112 ;
     RECT  25.081 32.112 25.836 32.136 ;
     RECT  25.081 32.136 25.884 32.304 ;
     RECT  25.081 32.304 25.836 32.328 ;
     RECT  25.081 32.328 25.884 32.544 ;
     RECT  25.081 32.544 25.836 32.568 ;
     RECT  25.081 32.568 25.884 32.736 ;
     RECT  25.081 32.736 25.836 32.76 ;
     RECT  25.081 32.76 25.884 32.928 ;
     RECT  25.081 32.928 25.836 32.952 ;
     RECT  25.081 32.952 25.884 33.12 ;
     RECT  25.081 33.12 25.836 33.144 ;
     RECT  25.081 33.144 25.884 33.312 ;
     RECT  25.081 33.312 25.836 33.336 ;
     RECT  25.081 33.336 25.884 33.552 ;
     RECT  25.081 33.552 25.836 33.576 ;
     RECT  25.081 33.576 25.884 33.744 ;
     RECT  25.081 33.744 25.836 33.768 ;
     RECT  25.081 33.768 25.884 33.936 ;
     RECT  25.081 33.936 25.836 33.96 ;
     RECT  25.081 33.96 25.884 34.128 ;
     RECT  25.081 34.128 25.836 34.152 ;
     RECT  25.081 34.152 25.884 34.32 ;
     RECT  25.081 34.32 25.836 34.344 ;
     RECT  25.081 34.344 25.884 34.512 ;
     RECT  25.081 34.512 25.836 34.536 ;
     RECT  25.081 34.536 25.884 34.752 ;
     RECT  25.081 34.752 25.836 34.776 ;
     RECT  25.081 34.776 25.884 34.944 ;
     RECT  25.081 34.944 25.836 34.968 ;
     RECT  25.081 34.968 25.884 35.136 ;
     RECT  25.081 35.136 25.836 35.16 ;
     RECT  25.081 35.16 25.884 35.328 ;
     RECT  25.081 35.328 25.836 35.352 ;
     RECT  25.081 35.352 25.884 35.52 ;
     RECT  25.081 35.52 25.836 35.544 ;
     RECT  25.081 35.544 25.884 35.76 ;
     RECT  25.081 35.76 25.836 35.784 ;
     RECT  25.081 35.784 25.884 35.952 ;
     RECT  25.081 35.952 25.836 35.976 ;
     RECT  25.081 35.976 25.884 36.144 ;
     RECT  25.081 36.144 25.836 36.168 ;
     RECT  25.081 36.168 25.884 36.336 ;
     RECT  25.081 36.336 25.836 36.36 ;
     RECT  25.081 36.36 25.884 36.528 ;
     RECT  25.081 36.528 25.836 36.552 ;
     RECT  25.081 36.552 25.884 36.768 ;
     RECT  25.081 36.768 25.836 36.792 ;
     RECT  25.081 36.792 25.884 36.96 ;
     RECT  25.081 36.96 25.836 36.984 ;
     RECT  25.081 36.984 25.884 37.152 ;
     RECT  25.081 37.152 25.836 37.176 ;
     RECT  25.081 37.176 25.884 37.344 ;
     RECT  25.081 37.344 25.836 37.368 ;
     RECT  25.081 37.368 25.884 37.536 ;
     RECT  25.081 37.536 25.836 37.56 ;
     RECT  25.081 37.56 25.884 37.728 ;
     RECT  25.081 37.728 25.836 37.752 ;
     RECT  25.081 37.752 25.884 37.968 ;
     RECT  25.081 37.968 25.836 37.992 ;
     RECT  25.081 37.992 25.884 38.16 ;
     RECT  25.081 38.16 25.836 38.184 ;
     RECT  25.081 38.184 25.884 38.352 ;
     RECT  25.081 38.352 25.836 38.376 ;
     RECT  25.081 38.376 25.884 38.544 ;
     RECT  25.081 38.544 25.836 38.568 ;
     RECT  25.081 38.568 25.884 38.736 ;
     RECT  25.081 38.736 25.836 38.76 ;
     RECT  25.081 38.76 25.884 38.976 ;
     RECT  25.081 38.976 25.836 39 ;
     RECT  25.081 39 25.884 39.168 ;
     RECT  25.081 39.168 25.836 39.192 ;
     RECT  25.081 39.192 25.884 39.36 ;
     RECT  25.081 39.36 25.836 39.384 ;
     RECT  25.081 39.384 25.884 39.552 ;
     RECT  25.081 39.552 25.836 39.576 ;
     RECT  25.081 39.576 25.884 39.744 ;
     RECT  25.081 39.744 25.836 39.768 ;
     RECT  25.081 39.768 25.884 39.936 ;
     RECT  25.081 39.936 25.836 39.96 ;
     RECT  25.081 39.96 25.884 40.176 ;
     RECT  25.081 40.176 25.836 40.2 ;
     RECT  25.081 40.2 25.884 40.368 ;
     RECT  25.081 40.368 25.836 40.392 ;
     RECT  25.081 40.392 25.884 40.56 ;
     RECT  25.081 40.56 25.836 40.584 ;
     RECT  25.081 40.584 25.884 40.752 ;
     RECT  25.081 40.752 25.836 40.776 ;
     RECT  25.081 40.776 25.884 40.944 ;
     RECT  25.081 40.944 25.836 40.968 ;
     RECT  25.081 40.968 25.884 41.184 ;
     RECT  25.081 41.184 25.836 41.208 ;
     RECT  25.081 41.208 25.884 41.376 ;
     RECT  25.081 41.376 25.836 41.4 ;
     RECT  25.081 41.4 25.884 41.568 ;
     RECT  25.081 41.568 25.836 41.592 ;
     RECT  25.081 41.592 25.884 41.76 ;
     RECT  25.081 41.76 25.836 41.784 ;
     RECT  25.081 41.784 25.884 41.952 ;
     RECT  25.081 41.952 25.836 41.976 ;
     RECT  25.081 41.976 25.884 42.192 ;
     RECT  25.081 42.192 25.836 42.216 ;
     RECT  25.081 42.216 25.884 42.384 ;
     RECT  25.081 42.384 25.836 42.408 ;
     RECT  25.081 42.408 25.884 42.576 ;
     RECT  25.081 42.576 25.836 42.6 ;
     RECT  25.081 42.6 25.884 42.768 ;
     RECT  25.081 42.768 25.836 42.792 ;
     RECT  25.081 42.792 25.884 42.96 ;
     RECT  25.081 42.96 25.836 42.984 ;
     RECT  25.081 42.984 25.884 43.152 ;
     RECT  25.081 43.152 25.836 43.176 ;
     RECT  25.081 43.176 25.884 43.392 ;
     RECT  25.081 43.392 25.836 43.416 ;
     RECT  25.081 43.416 25.884 43.584 ;
     RECT  25.081 43.584 25.836 43.608 ;
     RECT  25.081 43.608 25.884 43.776 ;
     RECT  25.081 43.776 25.836 43.8 ;
     RECT  25.081 43.8 25.884 43.968 ;
     RECT  25.081 43.968 25.836 43.992 ;
     RECT  25.081 43.992 25.884 44.16 ;
     RECT  25.081 44.16 25.836 44.184 ;
     RECT  25.081 44.184 25.884 44.4 ;
     RECT  25.081 44.4 25.836 44.424 ;
     RECT  25.081 44.424 25.884 44.592 ;
     RECT  25.081 44.592 25.836 44.616 ;
     RECT  25.081 44.616 25.884 44.784 ;
     RECT  25.081 44.784 25.836 44.808 ;
     RECT  25.081 44.808 25.884 44.976 ;
     RECT  25.081 44.976 25.836 45 ;
     RECT  25.081 45 25.884 45.168 ;
     RECT  25.081 45.168 25.836 45.192 ;
     RECT  25.081 45.192 25.884 45.408 ;
     RECT  25.081 45.408 25.836 45.432 ;
     RECT  25.081 45.432 25.884 45.6 ;
     RECT  25.081 45.6 25.836 45.624 ;
     RECT  25.081 45.624 25.884 45.792 ;
     RECT  25.081 45.792 25.836 45.816 ;
     RECT  25.081 45.816 25.884 45.984 ;
     RECT  25.081 45.984 25.836 46.008 ;
     RECT  25.081 46.008 25.884 46.176 ;
     RECT  25.081 46.176 25.836 46.2 ;
     RECT  25.081 46.2 25.884 46.368 ;
     RECT  25.081 46.368 25.836 46.392 ;
     RECT  25.081 46.392 25.884 46.608 ;
     RECT  25.081 46.608 25.836 46.632 ;
     RECT  25.081 46.632 25.884 46.8 ;
     RECT  25.081 46.8 25.836 46.824 ;
     RECT  25.081 46.824 25.884 46.992 ;
     RECT  25.081 46.992 25.836 47.016 ;
     RECT  25.081 47.016 25.884 47.184 ;
     RECT  25.081 47.184 25.836 47.208 ;
     RECT  25.081 47.208 25.884 47.376 ;
     RECT  25.081 47.376 25.836 47.4 ;
     RECT  25.081 47.4 25.884 47.616 ;
     RECT  25.081 47.616 25.836 47.64 ;
     RECT  25.081 47.64 25.884 47.808 ;
     RECT  25.081 47.808 25.836 47.832 ;
     RECT  25.081 47.832 25.884 48 ;
     RECT  25.081 48 25.836 48.024 ;
     RECT  25.081 48.024 25.884 48.192 ;
     RECT  25.081 48.192 25.836 48.216 ;
     RECT  25.081 48.216 25.884 48.384 ;
     RECT  25.081 48.384 25.836 48.408 ;
     RECT  25.081 48.408 25.884 48.576 ;
     RECT  25.081 48.576 25.836 48.6 ;
     RECT  25.081 48.6 25.884 48.816 ;
     RECT  25.081 48.816 25.836 48.84 ;
     RECT  25.081 48.84 25.884 49.008 ;
     RECT  25.081 49.008 25.836 49.032 ;
     RECT  25.081 49.032 25.884 49.2 ;
     RECT  25.081 49.2 25.836 49.224 ;
     RECT  25.081 49.224 25.884 49.392 ;
     RECT  25.081 49.392 25.836 49.416 ;
     RECT  25.081 49.416 25.884 49.584 ;
     RECT  25.081 49.584 25.836 49.608 ;
     RECT  25.081 49.608 25.884 49.824 ;
     RECT  25.081 49.824 25.836 49.848 ;
     RECT  25.081 49.848 25.884 50.016 ;
     RECT  25.081 50.016 25.836 50.04 ;
     RECT  25.081 50.04 25.884 50.208 ;
     RECT  25.081 50.208 25.836 50.232 ;
     RECT  25.081 50.232 25.884 50.4 ;
     RECT  25.081 50.4 25.836 50.424 ;
     RECT  25.081 50.424 25.884 50.592 ;
     RECT  25.081 50.592 25.836 50.616 ;
     RECT  25.081 50.616 25.884 50.832 ;
     RECT  25.081 50.832 25.836 50.856 ;
     RECT  25.081 50.856 25.884 51.024 ;
     RECT  25.081 51.024 25.836 51.048 ;
     RECT  25.081 51.048 25.884 51.216 ;
     RECT  25.081 51.216 25.836 51.24 ;
     RECT  25.081 51.24 25.884 51.408 ;
     RECT  25.081 51.408 25.836 51.432 ;
     RECT  25.081 51.432 25.884 51.6 ;
     RECT  25.081 51.6 25.836 51.624 ;
     RECT  25.081 51.624 25.884 51.792 ;
     RECT  25.081 51.792 25.836 51.816 ;
     RECT  25.081 51.816 25.884 52.032 ;
     RECT  25.081 52.032 25.836 52.056 ;
     RECT  25.081 52.056 25.884 52.224 ;
     RECT  25.081 52.224 25.836 52.248 ;
     RECT  25.081 52.248 25.884 52.416 ;
     RECT  25.081 52.416 25.836 52.44 ;
     RECT  25.081 52.44 25.884 52.608 ;
     RECT  25.081 52.608 25.836 52.632 ;
     RECT  25.081 52.632 25.884 52.8 ;
     RECT  25.081 52.8 25.836 52.824 ;
     RECT  25.081 52.824 25.884 53.04 ;
     RECT  25.081 53.04 25.836 53.064 ;
     RECT  25.081 53.064 25.884 53.232 ;
     RECT  25.081 53.232 25.836 53.256 ;
     RECT  25.081 53.256 25.884 53.424 ;
     RECT  25.081 53.424 25.836 53.448 ;
     RECT  25.081 53.448 25.884 53.616 ;
     RECT  25.081 53.616 25.836 53.64 ;
     RECT  25.081 53.64 25.884 53.808 ;
     RECT  25.081 53.808 25.836 53.832 ;
     RECT  25.081 53.832 25.884 54 ;
     RECT  25.081 54 25.836 54.024 ;
     RECT  25.081 54.024 25.884 54.24 ;
     RECT  25.081 54.24 25.836 54.264 ;
     RECT  25.081 54.264 25.884 54.432 ;
     RECT  25.081 54.432 25.836 54.456 ;
     RECT  25.081 54.456 25.884 54.624 ;
     RECT  25.081 54.624 25.836 54.648 ;
     RECT  25.081 54.648 25.884 54.816 ;
     RECT  25.081 54.816 25.836 54.84 ;
     RECT  25.081 54.84 25.884 55.008 ;
     RECT  25.081 55.008 25.836 55.032 ;
     RECT  25.081 55.032 25.884 55.248 ;
     RECT  25.081 55.248 25.836 55.272 ;
     RECT  25.081 55.272 25.884 55.44 ;
     RECT  25.081 55.44 25.836 55.464 ;
     RECT  25.081 55.464 25.884 55.632 ;
     RECT  25.081 55.632 25.836 55.656 ;
     RECT  25.081 55.656 25.884 55.824 ;
     RECT  25.081 55.824 25.836 55.848 ;
     RECT  25.081 55.848 25.884 56.016 ;
     RECT  25.081 56.016 25.836 56.04 ;
     RECT  25.081 56.04 25.884 56.256 ;
     RECT  25.081 56.256 25.836 56.28 ;
     RECT  25.081 56.28 25.884 56.448 ;
     RECT  25.081 56.448 25.836 56.472 ;
     RECT  25.081 56.472 25.884 56.64 ;
     RECT  25.081 56.64 25.836 56.664 ;
     RECT  25.081 56.664 25.884 56.832 ;
     RECT  25.081 56.832 25.836 56.856 ;
     RECT  25.081 56.856 25.884 57.024 ;
     RECT  25.081 57.024 25.836 57.048 ;
     RECT  25.081 57.048 25.884 57.216 ;
     RECT  25.081 57.216 25.836 57.24 ;
     RECT  25.081 57.24 25.884 57.456 ;
     RECT  25.081 57.456 25.836 57.48 ;
     RECT  25.081 57.48 25.884 57.648 ;
     RECT  25.081 57.648 25.836 57.672 ;
     RECT  25.081 57.672 25.884 57.84 ;
     RECT  25.081 57.84 25.836 57.864 ;
     RECT  25.081 57.864 25.884 58.032 ;
     RECT  25.081 58.032 25.836 58.056 ;
     RECT  25.081 58.056 25.884 58.224 ;
     RECT  25.081 58.224 25.836 58.248 ;
     RECT  25.081 58.248 25.884 58.464 ;
     RECT  25.081 58.464 25.836 58.488 ;
     RECT  25.081 58.488 25.884 58.656 ;
     RECT  25.081 58.656 25.836 58.68 ;
     RECT  25.081 58.68 25.884 58.848 ;
     RECT  25.081 58.848 25.836 58.872 ;
     RECT  25.081 58.872 25.884 59.04 ;
     RECT  25.081 59.04 25.836 59.064 ;
     RECT  25.081 59.064 25.884 59.232 ;
     RECT  25.081 59.232 25.836 59.256 ;
     RECT  25.081 59.256 25.884 59.472 ;
     RECT  25.081 59.472 25.836 59.496 ;
     RECT  25.081 59.496 25.884 59.664 ;
     RECT  25.081 59.664 25.836 59.688 ;
     RECT  25.081 59.688 25.884 59.856 ;
     RECT  25.081 59.856 25.836 59.88 ;
     RECT  25.081 59.88 25.884 60.048 ;
     RECT  25.081 60.048 25.836 60.072 ;
     RECT  25.081 60.072 25.884 60.24 ;
     RECT  25.081 60.24 25.836 60.264 ;
     RECT  25.081 60.264 25.884 60.432 ;
     RECT  25.081 60.432 25.836 60.456 ;
     RECT  25.081 60.456 25.884 60.672 ;
     RECT  25.081 60.672 25.836 60.696 ;
     RECT  25.081 60.696 25.884 60.864 ;
     RECT  25.081 60.864 25.836 60.888 ;
     RECT  25.081 60.888 25.884 61.056 ;
     RECT  25.081 61.056 25.836 61.08 ;
     RECT  25.081 61.08 25.884 61.248 ;
     RECT  25.081 61.248 25.836 61.272 ;
     RECT  25.081 61.272 25.884 61.44 ;
     RECT  25.081 61.44 25.836 61.464 ;
     RECT  25.081 61.464 25.884 61.68 ;
     RECT  25.081 61.68 25.836 61.704 ;
     RECT  25.081 61.704 25.884 61.872 ;
     RECT  25.081 61.872 25.836 61.896 ;
     RECT  25.081 61.896 25.884 62.064 ;
     RECT  25.081 62.064 25.836 62.088 ;
     RECT  25.081 62.088 25.884 62.256 ;
     RECT  25.081 62.256 25.836 62.28 ;
     RECT  25.081 62.28 25.884 62.448 ;
     RECT  25.081 62.448 25.836 62.472 ;
     RECT  25.081 62.472 25.884 62.64 ;
     RECT  25.081 62.64 25.836 62.664 ;
     RECT  25.081 62.664 25.884 62.88 ;
     RECT  25.081 62.88 25.836 62.904 ;
     RECT  25.081 62.904 25.884 63.072 ;
     RECT  25.081 63.072 25.836 63.096 ;
     RECT  25.081 63.096 25.884 63.264 ;
     RECT  25.081 63.264 25.836 63.288 ;
     RECT  25.081 63.288 25.884 63.456 ;
     RECT  25.081 63.456 25.836 63.48 ;
     RECT  25.081 63.48 25.884 63.648 ;
     RECT  25.081 63.648 25.836 63.672 ;
     RECT  25.081 63.672 25.884 63.888 ;
     RECT  25.081 63.888 25.836 63.912 ;
     RECT  25.081 63.912 25.884 64.08 ;
     RECT  25.081 64.08 25.836 64.104 ;
     RECT  25.081 64.104 25.884 64.272 ;
     RECT  25.081 64.272 25.836 64.296 ;
     RECT  25.081 64.296 25.884 64.464 ;
     RECT  25.081 64.464 25.836 64.488 ;
     RECT  25.081 64.488 25.884 64.656 ;
     RECT  25.081 64.656 25.836 64.68 ;
     RECT  25.081 64.68 25.884 64.896 ;
     RECT  25.081 64.896 25.836 64.92 ;
     RECT  25.081 64.92 25.884 65.088 ;
     RECT  25.081 65.088 25.836 65.112 ;
     RECT  25.081 65.112 25.884 65.28 ;
     RECT  25.081 65.28 25.836 65.304 ;
     RECT  25.081 65.304 25.884 65.472 ;
     RECT  25.081 65.472 25.836 65.496 ;
     RECT  25.081 65.496 25.884 65.664 ;
     RECT  25.081 65.664 25.836 65.688 ;
     RECT  25.081 65.688 25.884 65.856 ;
     RECT  25.081 65.856 25.836 65.88 ;
     RECT  25.081 65.88 25.884 66.096 ;
     RECT  25.081 66.096 25.836 66.12 ;
     RECT  25.081 66.12 25.884 66.288 ;
     RECT  25.081 66.288 25.836 66.312 ;
     RECT  25.081 66.312 25.884 66.48 ;
     RECT  25.081 66.48 25.836 66.504 ;
     RECT  25.081 66.504 25.884 66.672 ;
     RECT  25.081 66.672 25.836 66.696 ;
     RECT  25.081 66.696 25.884 66.864 ;
     RECT  25.081 66.864 25.836 66.888 ;
     RECT  25.081 66.888 25.884 67.104 ;
     RECT  25.081 67.104 25.836 67.128 ;
     RECT  25.081 67.128 25.884 67.296 ;
     RECT  25.081 67.296 25.836 67.32 ;
     RECT  25.081 67.32 25.884 67.488 ;
     RECT  25.081 67.488 25.836 67.512 ;
     RECT  25.081 67.512 25.884 67.68 ;
     RECT  25.081 67.68 25.836 67.704 ;
     RECT  25.081 67.704 25.884 67.872 ;
     RECT  25.081 67.872 25.836 67.896 ;
     RECT  25.081 67.896 25.884 68.064 ;
     RECT  25.081 68.064 25.836 68.088 ;
     RECT  25.081 68.088 25.884 68.304 ;
     RECT  25.081 68.304 25.836 68.328 ;
     RECT  25.081 68.328 25.884 68.496 ;
     RECT  25.081 68.496 25.836 68.52 ;
     RECT  25.081 68.52 25.884 68.688 ;
     RECT  25.081 68.688 25.836 68.712 ;
     RECT  25.081 68.712 25.884 68.88 ;
     RECT  25.081 68.88 25.836 68.904 ;
     RECT  25.081 68.904 25.884 69.072 ;
     RECT  25.081 69.072 25.836 69.096 ;
     RECT  25.081 69.096 25.884 69.312 ;
     RECT  25.081 69.312 25.836 69.336 ;
     RECT  25.081 69.336 25.884 69.504 ;
     RECT  25.081 69.504 25.836 69.528 ;
     RECT  25.081 69.528 25.884 69.696 ;
     RECT  25.081 69.696 25.836 69.72 ;
     RECT  25.081 69.72 25.884 69.888 ;
     RECT  25.081 69.888 25.836 69.912 ;
     RECT  25.081 69.912 25.884 70.08 ;
     RECT  25.081 70.08 25.836 70.104 ;
     RECT  25.081 70.104 25.884 70.32 ;
     RECT  25.081 70.32 25.836 70.344 ;
     RECT  25.081 70.344 25.884 70.512 ;
     RECT  25.081 70.512 25.836 70.536 ;
     RECT  25.081 70.536 25.884 70.704 ;
     RECT  25.081 70.704 25.836 70.728 ;
     RECT  25.081 70.728 25.884 70.896 ;
     RECT  25.081 70.896 25.836 70.92 ;
     RECT  25.081 70.92 25.884 71.088 ;
     RECT  25.081 71.088 25.836 71.112 ;
     RECT  25.081 71.112 25.884 71.28 ;
     RECT  25.081 71.28 25.836 71.304 ;
     RECT  25.081 71.304 25.884 71.52 ;
     RECT  25.081 71.52 25.836 71.544 ;
     RECT  25.081 71.544 25.884 71.712 ;
     RECT  25.081 71.712 25.836 71.736 ;
     RECT  25.081 71.736 25.884 71.904 ;
     RECT  25.081 71.904 25.836 71.928 ;
     RECT  25.081 71.928 25.884 72.096 ;
     RECT  25.081 72.096 25.836 72.12 ;
     RECT  25.081 72.12 25.884 72.288 ;
     RECT  25.081 72.288 25.836 72.312 ;
     RECT  25.081 72.312 25.884 72.528 ;
     RECT  25.081 72.528 25.836 72.552 ;
     RECT  25.081 72.552 25.884 72.72 ;
     RECT  25.081 72.72 25.836 72.744 ;
     RECT  25.081 72.744 25.884 72.912 ;
     RECT  25.081 72.912 25.836 72.936 ;
     RECT  25.081 72.936 25.884 73.104 ;
     RECT  25.081 73.104 25.836 73.128 ;
     RECT  25.081 73.128 25.884 73.296 ;
     RECT  25.081 73.296 25.836 73.32 ;
     RECT  25.081 73.32 25.884 73.536 ;
     RECT  25.081 73.536 25.836 73.56 ;
     RECT  25.081 73.56 25.884 73.728 ;
     RECT  25.081 73.728 25.836 73.752 ;
     RECT  25.081 73.752 25.884 73.92 ;
     RECT  25.081 73.92 25.836 73.944 ;
     RECT  25.081 73.944 25.884 74.112 ;
     RECT  25.081 74.112 25.836 74.136 ;
     RECT  25.081 74.136 25.884 74.304 ;
     RECT  25.081 74.304 25.836 74.328 ;
     RECT  25.081 74.328 25.884 74.496 ;
     RECT  25.081 74.496 25.836 74.52 ;
     RECT  25.081 74.52 25.884 74.736 ;
     RECT  25.081 74.736 25.836 74.76 ;
     RECT  25.081 74.76 25.884 74.928 ;
     RECT  25.081 74.928 25.836 74.952 ;
     RECT  25.081 74.952 25.884 75.12 ;
     RECT  25.081 75.12 25.836 75.144 ;
     RECT  25.081 75.144 25.884 75.312 ;
     RECT  25.081 75.312 25.836 75.336 ;
     RECT  25.081 75.336 25.884 75.504 ;
     RECT  25.081 75.504 25.836 75.528 ;
     RECT  25.081 75.528 25.884 75.744 ;
     RECT  25.081 75.744 25.836 75.768 ;
     RECT  25.081 75.768 25.884 75.936 ;
     RECT  25.081 75.936 25.836 75.96 ;
     RECT  25.081 75.96 25.884 76.128 ;
     RECT  25.081 76.128 25.836 76.152 ;
     RECT  25.081 76.152 25.884 76.32 ;
     RECT  25.081 76.32 25.836 76.344 ;
     RECT  25.081 76.344 25.884 76.512 ;
     RECT  25.081 76.512 25.836 76.536 ;
     RECT  25.081 76.536 25.884 76.704 ;
     RECT  25.081 76.704 25.836 76.728 ;
     RECT  25.081 76.728 25.884 76.944 ;
     RECT  25.081 76.944 25.836 76.968 ;
     RECT  25.081 76.968 25.884 77.136 ;
     RECT  25.081 77.136 25.836 77.16 ;
     RECT  25.081 77.16 25.884 77.328 ;
     RECT  25.081 77.328 25.836 77.352 ;
     RECT  25.081 77.352 25.884 77.52 ;
     RECT  25.081 77.52 25.836 77.544 ;
     RECT  25.081 77.544 25.884 77.712 ;
     RECT  25.081 77.712 25.836 77.736 ;
     RECT  25.081 77.736 25.884 77.952 ;
     RECT  25.081 77.952 25.836 77.976 ;
     RECT  25.081 77.976 25.884 78.144 ;
     RECT  25.081 78.144 25.836 78.168 ;
     RECT  25.081 78.168 25.884 78.336 ;
     RECT  25.081 78.336 25.836 78.36 ;
     RECT  25.081 78.36 25.884 78.528 ;
     RECT  25.081 78.528 25.836 78.552 ;
     RECT  25.081 78.552 25.884 78.72 ;
     RECT  25.081 78.72 25.836 78.744 ;
     RECT  25.081 78.744 25.884 78.96 ;
     RECT  25.081 78.96 25.836 78.984 ;
     RECT  25.081 78.984 25.884 79.152 ;
     RECT  25.081 79.152 25.836 79.176 ;
     RECT  25.081 79.176 25.884 79.344 ;
     RECT  25.081 79.344 25.836 79.368 ;
     RECT  25.081 79.368 25.884 79.536 ;
     RECT  25.081 79.536 25.836 79.56 ;
     RECT  25.081 79.56 25.884 79.728 ;
     RECT  25.081 79.728 25.836 79.752 ;
     RECT  25.081 79.752 25.884 79.92 ;
     RECT  25.081 79.92 25.836 79.944 ;
     RECT  25.081 79.944 25.884 80.16 ;
     RECT  25.081 80.16 25.836 80.184 ;
     RECT  25.081 80.184 25.884 80.352 ;
     RECT  25.081 80.352 25.836 80.376 ;
     RECT  25.081 80.376 25.884 80.544 ;
     RECT  25.081 80.544 25.836 80.568 ;
     RECT  25.081 80.568 25.884 80.736 ;
     RECT  25.081 80.736 25.836 80.76 ;
     RECT  25.081 80.76 25.884 80.928 ;
     RECT  25.081 80.928 25.836 80.952 ;
     RECT  25.081 80.952 25.884 81.168 ;
     RECT  25.081 81.168 25.836 81.192 ;
     RECT  25.081 81.192 25.884 81.36 ;
     RECT  25.081 81.36 25.836 81.384 ;
     RECT  25.081 81.384 25.884 81.552 ;
     RECT  25.081 81.552 25.836 81.576 ;
     RECT  25.081 81.576 25.884 81.744 ;
     RECT  25.081 81.744 25.836 81.768 ;
     RECT  25.081 81.768 25.884 81.936 ;
     RECT  25.081 81.936 25.836 81.96 ;
     RECT  25.081 81.96 25.884 82.128 ;
     RECT  25.081 82.128 25.836 82.152 ;
     RECT  25.081 82.152 25.884 82.368 ;
     RECT  25.081 82.368 25.836 82.392 ;
     RECT  25.081 82.392 25.884 82.56 ;
     RECT  25.081 82.56 25.836 82.584 ;
     RECT  25.081 82.584 25.884 82.752 ;
     RECT  25.081 82.752 25.836 82.776 ;
     RECT  25.081 82.776 25.884 82.944 ;
     RECT  25.081 82.944 25.836 82.968 ;
     RECT  25.081 82.968 25.884 83.136 ;
     RECT  25.081 83.136 25.836 83.16 ;
     RECT  25.081 83.16 25.884 83.376 ;
     RECT  25.081 83.376 25.836 83.4 ;
     RECT  25.081 83.4 25.884 83.568 ;
     RECT  25.081 83.568 25.836 83.592 ;
     RECT  25.081 83.592 25.884 83.76 ;
     RECT  25.081 83.76 25.836 83.784 ;
     RECT  25.081 83.784 25.884 83.952 ;
     RECT  25.081 83.952 25.836 83.976 ;
     RECT  25.081 83.976 25.884 84.144 ;
     RECT  25.081 84.144 25.836 84.168 ;
     RECT  25.081 84.168 25.884 84.384 ;
     RECT  25.081 84.384 25.836 84.408 ;
     RECT  25.081 84.408 25.884 84.576 ;
     RECT  25.081 84.576 25.836 84.6 ;
     RECT  25.081 84.6 25.884 84.768 ;
     RECT  25.081 84.768 25.836 84.792 ;
     RECT  25.081 84.792 25.884 84.96 ;
     RECT  25.081 84.96 25.836 84.984 ;
     RECT  25.081 84.984 25.884 85.152 ;
     RECT  25.081 85.152 25.836 85.176 ;
     RECT  25.081 85.176 25.884 85.344 ;
     RECT  25.081 85.344 25.836 85.368 ;
     RECT  25.081 85.368 25.884 85.584 ;
     RECT  25.081 85.584 25.836 85.608 ;
     RECT  25.081 85.608 25.884 85.776 ;
     RECT  25.081 85.776 25.836 85.8 ;
     RECT  25.081 85.8 25.884 85.968 ;
     RECT  25.081 85.968 25.836 85.992 ;
     RECT  25.081 85.992 25.884 86.16 ;
     RECT  25.081 86.16 25.836 86.184 ;
     RECT  25.081 86.184 25.884 86.352 ;
     RECT  25.081 86.352 25.836 86.376 ;
     RECT  25.081 86.376 25.884 86.592 ;
     RECT  25.081 86.592 25.836 86.616 ;
     RECT  25.081 86.616 25.884 86.784 ;
     RECT  25.081 86.784 25.836 86.808 ;
     RECT  25.081 86.808 25.884 86.976 ;
     RECT  25.081 86.976 25.836 87 ;
     RECT  25.081 87 25.884 87.168 ;
     RECT  25.081 87.168 25.836 87.192 ;
     RECT  25.081 87.192 25.884 87.36 ;
     RECT  25.081 87.36 25.836 87.384 ;
     RECT  25.081 87.384 25.884 87.6 ;
     RECT  25.081 87.6 25.836 87.624 ;
     RECT  25.081 87.624 25.884 87.792 ;
     RECT  25.081 87.792 25.836 87.816 ;
     RECT  25.081 87.816 25.884 87.984 ;
     RECT  25.081 87.984 25.836 88.008 ;
     RECT  25.081 88.008 25.884 88.176 ;
     RECT  25.081 88.176 25.836 88.2 ;
     RECT  25.081 88.2 25.884 88.368 ;
     RECT  25.081 88.368 25.836 88.392 ;
     RECT  25.081 88.392 25.884 88.56 ;
     RECT  25.081 88.56 25.836 88.584 ;
     RECT  25.081 88.584 25.884 88.8 ;
     RECT  25.081 88.8 25.836 88.824 ;
     RECT  25.081 88.824 25.884 88.992 ;
     RECT  25.081 88.992 25.836 89.016 ;
     RECT  25.081 89.016 25.884 89.184 ;
     RECT  25.081 89.184 25.836 89.208 ;
     RECT  25.081 89.208 25.884 89.376 ;
     RECT  25.081 89.376 25.836 89.4 ;
     RECT  25.081 89.4 25.884 89.568 ;
     RECT  25.081 89.568 25.836 89.592 ;
     RECT  25.081 89.592 25.884 89.808 ;
     RECT  25.081 89.808 25.836 89.832 ;
     RECT  25.081 89.832 25.884 90 ;
     RECT  25.081 90 25.836 90.024 ;
     RECT  25.081 90.024 25.884 90.192 ;
     RECT  25.081 90.192 25.836 90.216 ;
     RECT  25.081 90.216 25.884 90.384 ;
     RECT  25.081 90.384 25.836 90.408 ;
     RECT  25.081 90.408 25.884 90.576 ;
     RECT  25.081 90.576 25.836 90.6 ;
     RECT  25.081 90.6 25.884 90.768 ;
     RECT  25.081 90.768 25.836 90.792 ;
     RECT  25.081 90.792 25.884 91.008 ;
     RECT  25.081 91.008 25.836 91.032 ;
     RECT  25.081 91.032 25.884 91.2 ;
     RECT  25.081 91.2 25.836 91.224 ;
     RECT  25.081 91.224 25.884 91.392 ;
     RECT  25.081 91.392 25.836 91.416 ;
     RECT  25.081 91.416 25.884 91.584 ;
     RECT  25.081 91.584 25.836 91.608 ;
     RECT  25.081 91.608 25.884 91.776 ;
     RECT  25.081 91.776 25.836 91.8 ;
     RECT  25.081 91.8 25.884 92.016 ;
     RECT  25.081 92.016 25.836 92.04 ;
     RECT  25.081 92.04 25.884 92.208 ;
     RECT  25.081 92.208 25.836 92.232 ;
     RECT  25.081 92.232 25.884 92.4 ;
     RECT  25.081 92.4 25.836 92.424 ;
     RECT  25.081 92.424 25.884 92.592 ;
     RECT  25.081 92.592 25.836 92.616 ;
     RECT  25.081 92.616 25.884 92.784 ;
     RECT  25.081 92.784 25.836 92.808 ;
     RECT  25.081 92.808 25.884 93.024 ;
     RECT  25.081 93.024 25.836 93.048 ;
     RECT  25.081 93.048 25.884 93.216 ;
     RECT  25.081 93.216 25.836 93.24 ;
     RECT  25.081 93.24 25.884 93.408 ;
     RECT  25.081 93.408 25.836 93.432 ;
     RECT  25.081 93.432 25.884 93.6 ;
     RECT  25.081 93.6 25.836 93.624 ;
     RECT  25.081 93.624 25.884 93.792 ;
     RECT  25.081 93.792 25.836 93.816 ;
     RECT  25.081 93.816 25.884 93.984 ;
     RECT  25.081 93.984 25.836 94.008 ;
     RECT  25.081 94.008 25.884 94.224 ;
     RECT  25.081 94.224 25.836 94.248 ;
     RECT  25.081 94.248 25.884 94.416 ;
     RECT  25.081 94.416 25.836 94.44 ;
     RECT  25.081 94.44 25.884 94.608 ;
     RECT  25.081 94.608 25.836 94.632 ;
     RECT  25.081 94.632 25.884 94.8 ;
     RECT  25.081 94.8 25.836 94.824 ;
     RECT  25.081 94.824 25.884 94.992 ;
     RECT  25.081 94.992 25.836 95.016 ;
     RECT  25.081 95.016 25.884 95.232 ;
     RECT  25.081 95.232 25.836 95.256 ;
     RECT  25.081 95.256 25.884 95.424 ;
     RECT  25.081 95.424 25.836 95.448 ;
     RECT  25.081 95.448 25.884 95.616 ;
     RECT  25.081 95.616 25.836 95.64 ;
     RECT  25.081 95.64 25.884 95.808 ;
     RECT  25.081 95.808 25.836 95.832 ;
     RECT  25.081 95.832 25.884 96 ;
     RECT  25.081 96 25.836 96.024 ;
     RECT  25.081 96.024 25.884 96.24 ;
     RECT  25.081 96.24 25.836 96.264 ;
     RECT  25.081 96.264 25.884 96.432 ;
     RECT  25.081 96.432 25.836 96.456 ;
     RECT  25.081 96.456 25.884 96.624 ;
     RECT  25.081 96.624 25.836 96.648 ;
     RECT  25.081 96.648 25.884 96.816 ;
     RECT  25.081 96.816 25.836 96.84 ;
     RECT  25.081 96.84 25.884 97.008 ;
     RECT  25.081 97.008 25.836 97.032 ;
     RECT  25.081 97.032 25.884 97.2 ;
     RECT  25.081 97.2 25.836 97.224 ;
     RECT  25.081 97.224 25.884 97.44 ;
     RECT  25.081 97.44 25.836 97.464 ;
     RECT  25.081 97.464 25.884 97.632 ;
     RECT  25.081 97.632 25.836 97.656 ;
     RECT  25.081 97.656 25.884 97.824 ;
     RECT  25.081 97.824 25.836 97.848 ;
     RECT  25.081 97.848 25.884 98.016 ;
     RECT  25.081 98.016 25.836 98.04 ;
     RECT  25.081 98.04 25.884 98.208 ;
     RECT  25.081 98.208 25.836 98.232 ;
     RECT  25.081 98.232 25.884 98.448 ;
     RECT  25.081 98.448 25.836 98.472 ;
     RECT  25.081 98.472 25.884 98.64 ;
     RECT  25.081 98.64 25.836 98.664 ;
     RECT  25.081 98.664 25.884 98.832 ;
     RECT  25.081 98.832 25.836 98.856 ;
     RECT  25.081 98.856 25.884 99.264 ;
     RECT  25.081 99.264 25.836 99.288 ;
     RECT  25.081 99.288 25.884 99.552 ;
     RECT  25.081 99.552 25.836 99.576 ;
     RECT  25.081 99.576 25.884 99.792 ;
     RECT  25.081 99.792 25.836 99.816 ;
     RECT  25.081 99.816 25.884 100.08 ;
     RECT  25.081 100.08 25.836 100.104 ;
     RECT  25.081 100.104 25.884 100.32 ;
     RECT  25.081 100.32 25.836 100.344 ;
     RECT  25.081 100.344 25.884 100.608 ;
     RECT  25.081 100.608 25.836 100.632 ;
     RECT  25.081 100.632 25.884 100.848 ;
     RECT  25.081 100.848 25.836 100.872 ;
     RECT  25.081 100.872 25.884 101.136 ;
     RECT  25.081 101.136 25.836 101.16 ;
     RECT  25.081 101.16 25.884 101.376 ;
     RECT  25.081 101.376 25.836 101.4 ;
     RECT  25.081 101.4 25.884 101.664 ;
     RECT  25.081 101.664 25.836 101.688 ;
     RECT  25.081 101.688 25.884 101.952 ;
     RECT  25.081 101.952 25.836 101.976 ;
     RECT  25.081 101.976 25.884 102.192 ;
     RECT  25.081 102.192 25.836 102.216 ;
     RECT  25.081 102.216 25.884 102.48 ;
     RECT  25.081 102.48 25.836 102.504 ;
     RECT  25.081 102.504 25.884 102.72 ;
     RECT  25.081 102.72 25.836 102.744 ;
     RECT  25.081 102.744 25.884 103.008 ;
     RECT  25.081 103.008 25.836 103.032 ;
    LAYER M5 ;
     RECT  2.4 2.137 2.52 2.151 ;
     RECT  7.8 2.137 7.92 2.151 ;
     RECT  13.2 2.137 13.32 2.151 ;
     RECT  18.6 2.137 18.72 2.151 ;
     RECT  7.8 2.151 8.112 3.829 ;
     RECT  18.6 2.151 18.912 3.925 ;
     RECT  17.616 3.925 18.912 5.171 ;
     RECT  13.2 2.151 13.512 5.557 ;
     RECT  13.2 5.557 13.656 5.989 ;
     RECT  18.6 5.171 18.912 6.805 ;
     RECT  4.224 7.909 4.248 7.957 ;
     RECT  17.664 6.805 18.912 8.437 ;
     RECT  20.112 7.861 20.136 8.437 ;
     RECT  4.032 7.957 4.248 8.485 ;
     RECT  17.664 8.437 20.52 8.485 ;
     RECT  17.664 8.485 20.76 8.965 ;
     RECT  17.088 8.965 20.76 9.157 ;
     RECT  12.624 5.989 13.656 9.397 ;
     RECT  16.992 9.157 20.76 9.779 ;
     RECT  17.136 9.779 20.76 10.789 ;
     RECT  4.032 8.485 4.92 11.365 ;
     RECT  15.408 11.365 15.432 11.941 ;
     RECT  7.104 3.829 8.112 11.987 ;
     RECT  11.424 9.349 11.448 11.987 ;
     RECT  4.032 11.365 5.4 11.989 ;
     RECT  12.624 9.397 13.944 12.325 ;
     RECT  7.8 11.987 8.112 13.477 ;
     RECT  3.936 11.989 5.4 13.571 ;
     RECT  6.816 13.477 8.112 14.053 ;
     RECT  6.384 14.053 8.112 14.099 ;
     RECT  7.8 14.099 8.112 14.389 ;
     RECT  7.8 14.389 8.712 14.485 ;
     RECT  14.928 11.941 15.432 14.677 ;
     RECT  16.512 10.789 20.76 14.677 ;
     RECT  6.384 14.099 6.648 14.867 ;
     RECT  7.8 14.485 9.24 14.917 ;
     RECT  11.856 12.325 13.944 15.301 ;
     RECT  14.928 14.677 20.76 15.301 ;
     RECT  6.624 14.867 6.648 15.445 ;
     RECT  7.8 14.917 9.336 15.445 ;
     RECT  4.08 13.571 5.4 15.491 ;
     RECT  10.512 14.197 10.536 15.829 ;
     RECT  11.856 15.301 20.76 15.829 ;
     RECT  6.624 15.445 9.336 16.021 ;
     RECT  6.624 16.021 9.384 16.309 ;
     RECT  6.624 16.309 9.528 16.645 ;
     RECT  10.512 15.829 20.76 16.645 ;
     RECT  2.4 2.151 2.712 17.605 ;
     RECT  4.32 15.491 5.4 17.605 ;
     RECT  6.624 16.645 20.76 17.605 ;
     RECT  2.4 17.605 20.76 17.651 ;
     RECT  2.4 17.651 3.528 19.333 ;
     RECT  4.512 17.651 20.76 19.333 ;
     RECT  2.4 19.333 20.76 22.739 ;
     RECT  4.512 22.739 20.76 24.995 ;
     RECT  2.4 22.739 3.528 27.205 ;
     RECT  4.656 24.995 20.76 27.205 ;
     RECT  2.4 27.205 20.76 30.083 ;
     RECT  4.176 30.083 20.76 31.139 ;
     RECT  4.992 31.139 20.76 31.379 ;
     RECT  2.4 30.083 2.712 31.861 ;
     RECT  5.088 31.379 20.76 32.627 ;
     RECT  5.088 32.627 20.712 33.733 ;
     RECT  4.752 33.733 20.712 34.357 ;
     RECT  4.752 34.357 20.76 34.501 ;
     RECT  4.464 34.501 20.76 34.547 ;
     RECT  2.4 31.861 3.48 34.741 ;
     RECT  4.464 34.547 20.712 34.741 ;
     RECT  2.4 34.741 20.712 36.035 ;
     RECT  2.4 36.035 20.568 37.907 ;
     RECT  2.4 37.907 20.52 43.285 ;
     RECT  2.4 43.285 20.568 44.389 ;
     RECT  2.304 44.389 20.568 44.483 ;
     RECT  2.304 44.483 20.52 52.741 ;
     RECT  2.304 52.741 20.712 52.933 ;
     RECT  22.992 54.565 23.016 55.813 ;
     RECT  2.304 52.933 21.576 57.109 ;
     RECT  22.848 55.813 23.016 57.109 ;
     RECT  2.304 57.109 23.016 63.013 ;
     RECT  2.256 63.013 23.016 65.317 ;
     RECT  2.208 65.317 23.016 69.011 ;
     RECT  2.208 69.011 22.968 71.699 ;
     RECT  2.208 71.699 22.92 73.571 ;
     RECT  2.256 73.571 22.92 73.619 ;
     RECT  2.256 73.619 22.872 73.955 ;
     RECT  2.256 73.955 22.824 81.395 ;
     RECT  2.256 81.395 3.432 83.797 ;
     RECT  4.464 81.395 22.824 83.797 ;
     RECT  2.256 83.797 22.824 84.611 ;
     RECT  4.8 84.611 22.824 84.851 ;
     RECT  0.144 84.469 0.168 85.523 ;
     RECT  13.104 84.851 22.824 86.051 ;
     RECT  22.8 86.051 22.824 86.099 ;
     RECT  2.256 84.611 3.432 86.341 ;
     RECT  4.8 84.851 11.976 86.341 ;
     RECT  13.104 86.051 21.816 86.435 ;
     RECT  16.272 86.435 21.816 86.483 ;
     RECT  13.104 86.435 15 86.485 ;
     RECT  13.056 86.485 15 86.531 ;
     RECT  2.256 86.341 11.976 86.675 ;
     RECT  16.272 86.483 21.768 86.723 ;
     RECT  2.256 86.675 11.784 87.251 ;
     RECT  13.056 86.531 14.664 87.251 ;
     RECT  16.272 86.723 21.72 87.299 ;
     RECT  4.32 87.251 11.448 87.827 ;
     RECT  13.056 87.251 14.568 87.827 ;
     RECT  13.056 87.827 14.136 87.925 ;
     RECT  2.256 87.251 2.808 87.971 ;
     RECT  13.008 87.925 14.136 88.115 ;
     RECT  0.144 88.645 0.168 90.037 ;
     RECT  4.8 87.827 11.448 90.373 ;
     RECT  4.8 90.373 11.496 90.611 ;
     RECT  13.104 88.115 14.136 90.659 ;
     RECT  0.144 90.037 0.264 90.899 ;
     RECT  7.104 90.611 11.496 91.331 ;
     RECT  13.2 90.659 14.136 91.379 ;
     RECT  7.248 91.331 11.496 92.245 ;
     RECT  16.272 87.299 21.672 92.387 ;
     RECT  0.24 90.899 0.264 92.723 ;
     RECT  7.248 92.245 12.024 92.821 ;
     RECT  4.8 90.611 5.928 92.867 ;
     RECT  5.76 92.867 5.928 92.963 ;
     RECT  7.104 92.821 12.024 93.061 ;
     RECT  13.2 91.379 13.992 93.061 ;
     RECT  7.104 93.061 13.992 93.107 ;
     RECT  16.272 92.387 21.576 93.539 ;
     RECT  21.12 93.539 21.576 93.779 ;
     RECT  7.104 93.107 11.496 94.069 ;
     RECT  12.528 93.107 13.992 94.115 ;
     RECT  16.272 93.539 20.136 94.115 ;
     RECT  6.768 94.069 11.496 94.643 ;
     RECT  16.272 94.115 19.704 94.739 ;
     RECT  6.768 94.643 10.584 95.267 ;
     RECT  16.272 94.739 16.632 95.795 ;
     RECT  12 94.981 12.024 96.371 ;
     RECT  17.904 94.739 19.704 96.371 ;
     RECT  13.2 94.115 13.992 96.611 ;
     RECT  16.272 95.795 16.488 98.099 ;
     RECT  6.768 95.267 9.816 98.339 ;
     RECT  10.8 96.421 10.824 98.339 ;
     RECT  9.792 98.339 9.816 98.629 ;
     RECT  17.904 96.371 18.912 98.675 ;
     RECT  18.6 98.675 18.912 98.677 ;
     RECT  9.792 98.629 10.728 98.771 ;
     RECT  6.768 98.339 8.76 99.109 ;
     RECT  9.792 98.771 10.296 99.395 ;
     RECT  18.6 98.677 19.656 99.491 ;
     RECT  10.272 99.395 10.296 100.307 ;
     RECT  6.288 99.109 8.76 100.355 ;
     RECT  11.568 100.261 11.592 101.075 ;
     RECT  0.144 96.853 0.168 101.123 ;
     RECT  3.984 99.013 4.008 102.083 ;
     RECT  6.288 100.355 8.328 102.083 ;
     RECT  16.464 98.099 16.488 102.227 ;
     RECT  21.552 93.779 21.576 102.565 ;
     RECT  7.056 102.083 8.328 103.189 ;
     RECT  13.2 96.611 13.512 103.189 ;
     RECT  17.472 102.517 17.496 103.189 ;
     RECT  18.6 99.491 18.912 103.189 ;
     RECT  2.256 87.971 2.712 103.235 ;
     RECT  7.056 103.189 9.96 103.285 ;
     RECT  10.944 103.189 15.048 103.285 ;
     RECT  7.056 103.285 15.048 103.333 ;
     RECT  2.4 103.235 2.712 103.621 ;
     RECT  3.936 103.237 3.96 103.621 ;
     RECT  6.096 103.333 15.048 103.621 ;
     RECT  16.512 103.189 17.496 103.621 ;
     RECT  18.6 103.189 19.176 103.621 ;
     RECT  2.4 103.621 3.96 103.703 ;
     RECT  2.64 103.703 3.96 103.717 ;
     RECT  6.096 103.621 19.176 103.717 ;
     RECT  20.64 102.565 21.576 103.717 ;
     RECT  2.64 103.717 22.104 104.821 ;
     RECT  2.64 104.821 22.584 104.869 ;
     RECT  2.64 104.869 23.064 105.756 ;
     RECT  2.664 105.756 2.88 105.808 ;
     RECT  2.904 105.756 3.168 105.808 ;
     RECT  3.192 105.756 3.408 105.808 ;
     RECT  3.432 105.756 3.696 105.808 ;
     RECT  3.72 105.756 3.936 105.808 ;
     RECT  3.96 105.756 4.224 105.808 ;
     RECT  4.248 105.756 4.512 105.808 ;
     RECT  4.536 105.756 4.752 105.808 ;
     RECT  4.776 105.756 5.04 105.808 ;
     RECT  5.064 105.756 5.28 105.808 ;
     RECT  5.304 105.756 5.568 105.808 ;
     RECT  5.592 105.756 5.808 105.808 ;
     RECT  5.832 105.756 6.096 105.808 ;
     RECT  6.12 105.756 6.336 105.808 ;
     RECT  6.36 105.756 6.816 105.808 ;
     RECT  6.84 105.756 7.056 105.808 ;
     RECT  7.08 105.756 7.296 105.808 ;
     RECT  7.32 105.756 7.536 105.808 ;
     RECT  7.56 105.756 7.776 105.808 ;
     RECT  7.8 105.756 8.016 105.808 ;
     RECT  8.04 105.756 8.256 105.808 ;
     RECT  8.28 105.756 8.496 105.808 ;
     RECT  8.52 105.756 8.736 105.808 ;
     RECT  8.76 105.756 8.976 105.808 ;
     RECT  9 105.756 9.216 105.808 ;
     RECT  9.24 105.756 9.456 105.808 ;
     RECT  9.48 105.756 9.696 105.808 ;
     RECT  9.72 105.756 9.936 105.808 ;
     RECT  9.96 105.756 10.176 105.808 ;
     RECT  10.2 105.756 10.416 105.808 ;
     RECT  10.44 105.756 10.704 105.808 ;
     RECT  10.728 105.756 10.944 105.808 ;
     RECT  10.968 105.756 11.184 105.808 ;
     RECT  11.208 105.756 11.424 105.808 ;
     RECT  11.448 105.756 11.664 105.808 ;
     RECT  11.688 105.756 11.904 105.808 ;
     RECT  11.928 105.756 12.144 105.808 ;
     RECT  12.168 105.756 12.384 105.808 ;
     RECT  12.408 105.756 12.624 105.808 ;
     RECT  12.648 105.756 12.864 105.808 ;
     RECT  12.888 105.756 13.104 105.808 ;
     RECT  13.128 105.756 13.344 105.808 ;
     RECT  13.368 105.756 13.584 105.808 ;
     RECT  13.608 105.756 13.824 105.808 ;
     RECT  13.848 105.756 14.064 105.808 ;
     RECT  14.088 105.756 14.304 105.808 ;
     RECT  14.328 105.756 14.544 105.808 ;
     RECT  14.568 105.756 14.784 105.808 ;
     RECT  14.808 105.756 15.024 105.808 ;
     RECT  15.048 105.756 15.264 105.808 ;
     RECT  15.288 105.756 15.504 105.808 ;
     RECT  15.528 105.756 15.744 105.808 ;
     RECT  15.768 105.756 15.984 105.808 ;
     RECT  16.008 105.756 16.224 105.808 ;
     RECT  16.248 105.756 16.512 105.808 ;
     RECT  16.536 105.756 16.752 105.808 ;
     RECT  16.776 105.756 16.992 105.808 ;
     RECT  17.016 105.756 17.232 105.808 ;
     RECT  17.256 105.756 17.472 105.808 ;
     RECT  17.496 105.756 17.712 105.808 ;
     RECT  17.736 105.756 17.952 105.808 ;
     RECT  17.976 105.756 18.192 105.808 ;
     RECT  18.216 105.756 18.432 105.808 ;
     RECT  18.456 105.756 18.672 105.808 ;
     RECT  18.696 105.756 18.912 105.808 ;
     RECT  18.936 105.756 19.152 105.808 ;
     RECT  19.176 105.756 19.392 105.808 ;
     RECT  19.416 105.756 19.632 105.808 ;
     RECT  19.656 105.756 19.872 105.808 ;
     RECT  19.896 105.756 20.112 105.808 ;
     RECT  20.136 105.756 20.352 105.808 ;
     RECT  20.376 105.756 20.592 105.808 ;
     RECT  20.616 105.756 20.832 105.808 ;
     RECT  20.856 105.756 21.072 105.808 ;
     RECT  21.096 105.756 21.552 105.808 ;
     RECT  21.576 105.756 22.08 105.808 ;
     RECT  22.104 105.756 22.56 105.808 ;
     RECT  22.584 105.756 23.04 105.808 ;
     RECT  18.912 7.861 20.112 8.437 ;
     RECT  2.712 7.909 4.224 7.957 ;
     RECT  2.712 7.957 4.032 11.989 ;
     RECT  11.448 9.349 12.624 11.987 ;
     RECT  16.992 9.779 17.136 10.789 ;
     RECT  13.944 11.365 15.408 11.941 ;
     RECT  15.432 11.365 16.512 14.677 ;
     RECT  13.944 11.941 14.928 15.301 ;
     RECT  7.104 11.987 7.8 13.477 ;
     RECT  11.856 11.987 12.624 12.325 ;
     RECT  2.712 11.989 3.936 13.571 ;
     RECT  5.4 13.477 6.816 14.053 ;
     RECT  2.712 13.571 4.08 15.491 ;
     RECT  5.4 14.053 6.384 14.867 ;
     RECT  6.648 14.099 7.8 15.445 ;
     RECT  10.536 14.197 11.856 15.829 ;
     RECT  9.24 14.485 10.512 14.917 ;
     RECT  5.4 14.867 6.624 17.605 ;
     RECT  9.336 14.917 10.512 16.021 ;
     RECT  9.384 16.021 10.512 16.309 ;
     RECT  9.528 16.309 10.512 16.645 ;
     RECT  3.528 17.651 4.512 19.333 ;
     RECT  3.528 22.739 4.512 24.995 ;
     RECT  3.528 24.995 4.656 27.205 ;
     RECT  2.712 30.083 4.176 31.139 ;
     RECT  2.712 31.139 4.992 31.379 ;
     RECT  2.712 31.379 3.48 31.861 ;
     RECT  3.48 33.733 4.752 34.501 ;
     RECT  3.48 34.501 4.464 34.741 ;
     RECT  21.576 54.565 22.992 55.813 ;
     RECT  21.576 55.813 22.848 57.109 ;
     RECT  3.432 81.395 4.464 83.797 ;
     RECT  3.432 84.611 4.8 86.341 ;
     RECT  11.976 84.851 13.104 86.485 ;
     RECT  21.816 86.051 22.8 86.099 ;
     RECT  15 86.435 16.272 86.531 ;
     RECT  11.976 86.485 13.056 86.675 ;
     RECT  11.784 86.675 13.056 87.251 ;
     RECT  2.808 87.251 4.32 87.827 ;
     RECT  13.008 87.251 13.056 87.925 ;
     RECT  5.928 90.611 7.104 91.331 ;
     RECT  5.928 91.331 7.248 92.821 ;
     RECT  12.024 92.245 13.2 93.061 ;
     RECT  5.928 92.821 7.104 92.963 ;
     RECT  6.768 92.963 7.104 94.069 ;
     RECT  11.496 93.107 12.528 94.115 ;
     RECT  20.136 93.539 21.12 93.779 ;
     RECT  20.136 93.779 21.552 94.115 ;
     RECT  11.496 94.115 13.2 94.643 ;
     RECT  10.584 94.643 13.2 94.981 ;
     RECT  16.632 94.739 17.904 95.795 ;
     RECT  10.584 94.981 12 95.267 ;
     RECT  12.024 94.981 13.2 96.371 ;
     RECT  9.816 95.267 12 96.371 ;
     RECT  16.488 95.795 17.904 98.675 ;
     RECT  9.816 96.371 10.824 96.421 ;
     RECT  9.816 96.421 10.8 98.339 ;
     RECT  8.76 98.339 9.792 99.395 ;
     RECT  9.816 98.339 10.728 98.629 ;
     RECT  10.296 98.771 10.728 100.261 ;
     RECT  2.712 99.013 3.984 102.083 ;
     RECT  8.76 99.395 10.272 100.307 ;
     RECT  10.296 100.261 11.568 100.307 ;
     RECT  2.712 102.083 3.96 103.237 ;
     RECT  6.288 102.083 7.056 103.333 ;
     RECT  16.464 102.227 16.488 102.517 ;
     RECT  16.464 102.517 17.472 103.189 ;
     RECT  17.496 102.517 18.6 103.621 ;
     RECT  9.96 103.189 10.944 103.285 ;
     RECT  15.048 103.189 16.512 103.621 ;
     RECT  19.176 103.189 20.64 103.717 ;
     RECT  2.712 103.237 3.936 103.621 ;
  END
END ot_hgi_coll_qso_n2s1_b32
END LIBRARY
